VERSION 5.8 ;
BUSBITCHARS "[]" ;
DIVIDERCHAR "/" ;
UNITS
    DATABASE MICRONS 1000 ;
END UNITS

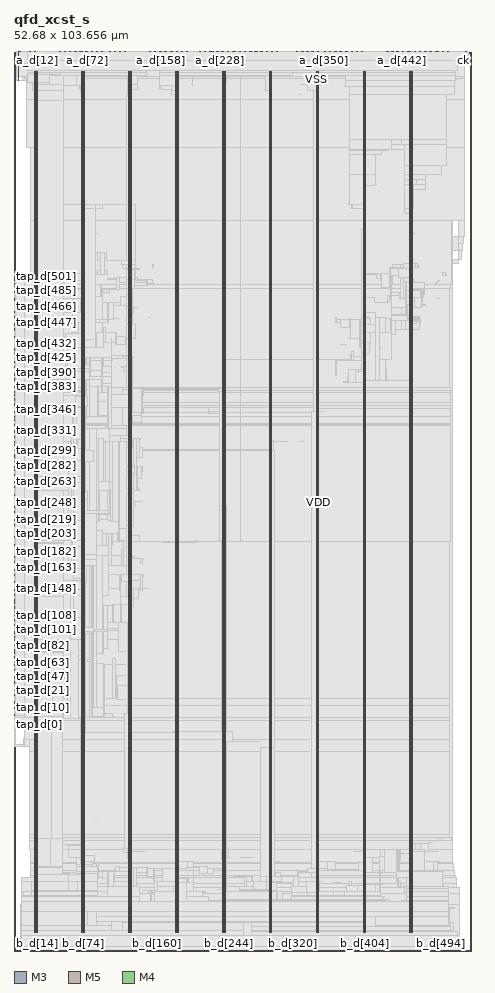
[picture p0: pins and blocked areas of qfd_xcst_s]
MACRO qfd_xcst_s
  FOREIGN qfd_xcst_s 0 0 ;
  CLASS BLOCK ;
  SIZE 52.68 BY 103.656 ;
  PIN a_d[0]
    DIRECTION INPUT ;
    USE SIGNAL ;
    PORT
      LAYER M3 ;
        RECT  1.44 103.618 1.458 103.656 ;
    END
  END a_d[0]
  PIN a_d[100]
    DIRECTION INPUT ;
    USE SIGNAL ;
    PORT
      LAYER M3 ;
        RECT  11.232 103.618 11.25 103.656 ;
    END
  END a_d[100]
  PIN a_d[101]
    DIRECTION INPUT ;
    USE SIGNAL ;
    PORT
      LAYER M5 ;
        RECT  11.328 103.572 11.352 103.656 ;
    END
  END a_d[101]
  PIN a_d[102]
    DIRECTION INPUT ;
    USE SIGNAL ;
    PORT
      LAYER M3 ;
        RECT  11.412 103.618 11.43 103.656 ;
    END
  END a_d[102]
  PIN a_d[103]
    DIRECTION INPUT ;
    USE SIGNAL ;
    PORT
      LAYER M5 ;
        RECT  11.52 103.572 11.544 103.656 ;
    END
  END a_d[103]
  PIN a_d[104]
    DIRECTION INPUT ;
    USE SIGNAL ;
    PORT
      LAYER M3 ;
        RECT  11.628 103.618 11.646 103.656 ;
    END
  END a_d[104]
  PIN a_d[105]
    DIRECTION INPUT ;
    USE SIGNAL ;
    PORT
      LAYER M5 ;
        RECT  11.712 103.572 11.736 103.656 ;
    END
  END a_d[105]
  PIN a_d[106]
    DIRECTION INPUT ;
    USE SIGNAL ;
    PORT
      LAYER M3 ;
        RECT  11.808 103.618 11.826 103.656 ;
    END
  END a_d[106]
  PIN a_d[107]
    DIRECTION INPUT ;
    USE SIGNAL ;
    PORT
      LAYER M5 ;
        RECT  11.904 103.572 11.928 103.656 ;
    END
  END a_d[107]
  PIN a_d[108]
    DIRECTION INPUT ;
    USE SIGNAL ;
    PORT
      LAYER M3 ;
        RECT  12.024 103.618 12.042 103.656 ;
    END
  END a_d[108]
  PIN a_d[109]
    DIRECTION INPUT ;
    USE SIGNAL ;
    PORT
      LAYER M5 ;
        RECT  12.096 103.572 12.12 103.656 ;
    END
  END a_d[109]
  PIN a_d[10]
    DIRECTION INPUT ;
    USE SIGNAL ;
    PORT
      LAYER M3 ;
        RECT  2.412 103.618 2.43 103.656 ;
    END
  END a_d[10]
  PIN a_d[110]
    DIRECTION INPUT ;
    USE SIGNAL ;
    PORT
      LAYER M3 ;
        RECT  12.204 103.618 12.222 103.656 ;
    END
  END a_d[110]
  PIN a_d[111]
    DIRECTION INPUT ;
    USE SIGNAL ;
    PORT
      LAYER M5 ;
        RECT  12.288 103.572 12.312 103.656 ;
    END
  END a_d[111]
  PIN a_d[112]
    DIRECTION INPUT ;
    USE SIGNAL ;
    PORT
      LAYER M3 ;
        RECT  12.42 103.618 12.438 103.656 ;
    END
  END a_d[112]
  PIN a_d[113]
    DIRECTION INPUT ;
    USE SIGNAL ;
    PORT
      LAYER M5 ;
        RECT  12.48 103.572 12.504 103.656 ;
    END
  END a_d[113]
  PIN a_d[114]
    DIRECTION INPUT ;
    USE SIGNAL ;
    PORT
      LAYER M3 ;
        RECT  12.6 103.618 12.618 103.656 ;
    END
  END a_d[114]
  PIN a_d[115]
    DIRECTION INPUT ;
    USE SIGNAL ;
    PORT
      LAYER M5 ;
        RECT  12.672 103.572 12.696 103.656 ;
    END
  END a_d[115]
  PIN a_d[116]
    DIRECTION INPUT ;
    USE SIGNAL ;
    PORT
      LAYER M3 ;
        RECT  12.78 103.618 12.798 103.656 ;
    END
  END a_d[116]
  PIN a_d[117]
    DIRECTION INPUT ;
    USE SIGNAL ;
    PORT
      LAYER M5 ;
        RECT  12.912 103.572 12.936 103.656 ;
    END
  END a_d[117]
  PIN a_d[118]
    DIRECTION INPUT ;
    USE SIGNAL ;
    PORT
      LAYER M3 ;
        RECT  12.996 103.618 13.014 103.656 ;
    END
  END a_d[118]
  PIN a_d[119]
    DIRECTION INPUT ;
    USE SIGNAL ;
    PORT
      LAYER M5 ;
        RECT  13.104 103.572 13.128 103.656 ;
    END
  END a_d[119]
  PIN a_d[11]
    DIRECTION INPUT ;
    USE SIGNAL ;
    PORT
      LAYER M5 ;
        RECT  2.496 103.572 2.52 103.656 ;
    END
  END a_d[11]
  PIN a_d[120]
    DIRECTION INPUT ;
    USE SIGNAL ;
    PORT
      LAYER M3 ;
        RECT  13.176 103.618 13.194 103.656 ;
    END
  END a_d[120]
  PIN a_d[121]
    DIRECTION INPUT ;
    USE SIGNAL ;
    PORT
      LAYER M5 ;
        RECT  13.296 103.572 13.32 103.656 ;
    END
  END a_d[121]
  PIN a_d[122]
    DIRECTION INPUT ;
    USE SIGNAL ;
    PORT
      LAYER M3 ;
        RECT  13.392 103.618 13.41 103.656 ;
    END
  END a_d[122]
  PIN a_d[123]
    DIRECTION INPUT ;
    USE SIGNAL ;
    PORT
      LAYER M5 ;
        RECT  13.488 103.572 13.512 103.656 ;
    END
  END a_d[123]
  PIN a_d[124]
    DIRECTION INPUT ;
    USE SIGNAL ;
    PORT
      LAYER M3 ;
        RECT  13.572 103.618 13.59 103.656 ;
    END
  END a_d[124]
  PIN a_d[125]
    DIRECTION INPUT ;
    USE SIGNAL ;
    PORT
      LAYER M5 ;
        RECT  13.68 103.572 13.704 103.656 ;
    END
  END a_d[125]
  PIN a_d[126]
    DIRECTION INPUT ;
    USE SIGNAL ;
    PORT
      LAYER M3 ;
        RECT  13.788 103.618 13.806 103.656 ;
    END
  END a_d[126]
  PIN a_d[127]
    DIRECTION INPUT ;
    USE SIGNAL ;
    PORT
      LAYER M5 ;
        RECT  13.872 103.572 13.896 103.656 ;
    END
  END a_d[127]
  PIN a_d[128]
    DIRECTION INPUT ;
    USE SIGNAL ;
    PORT
      LAYER M3 ;
        RECT  13.968 103.618 13.986 103.656 ;
    END
  END a_d[128]
  PIN a_d[129]
    DIRECTION INPUT ;
    USE SIGNAL ;
    PORT
      LAYER M5 ;
        RECT  14.064 103.572 14.088 103.656 ;
    END
  END a_d[129]
  PIN a_d[12]
    DIRECTION INPUT ;
    USE SIGNAL ;
    PORT
      LAYER M3 ;
        RECT  2.628 103.618 2.646 103.656 ;
    END
  END a_d[12]
  PIN a_d[130]
    DIRECTION INPUT ;
    USE SIGNAL ;
    PORT
      LAYER M3 ;
        RECT  14.184 103.618 14.202 103.656 ;
    END
  END a_d[130]
  PIN a_d[131]
    DIRECTION INPUT ;
    USE SIGNAL ;
    PORT
      LAYER M5 ;
        RECT  14.256 103.572 14.28 103.656 ;
    END
  END a_d[131]
  PIN a_d[132]
    DIRECTION INPUT ;
    USE SIGNAL ;
    PORT
      LAYER M3 ;
        RECT  14.364 103.618 14.382 103.656 ;
    END
  END a_d[132]
  PIN a_d[133]
    DIRECTION INPUT ;
    USE SIGNAL ;
    PORT
      LAYER M5 ;
        RECT  14.448 103.572 14.472 103.656 ;
    END
  END a_d[133]
  PIN a_d[134]
    DIRECTION INPUT ;
    USE SIGNAL ;
    PORT
      LAYER M3 ;
        RECT  14.544 103.618 14.562 103.656 ;
    END
  END a_d[134]
  PIN a_d[135]
    DIRECTION INPUT ;
    USE SIGNAL ;
    PORT
      LAYER M5 ;
        RECT  14.64 103.572 14.664 103.656 ;
    END
  END a_d[135]
  PIN a_d[136]
    DIRECTION INPUT ;
    USE SIGNAL ;
    PORT
      LAYER M3 ;
        RECT  14.76 103.618 14.778 103.656 ;
    END
  END a_d[136]
  PIN a_d[137]
    DIRECTION INPUT ;
    USE SIGNAL ;
    PORT
      LAYER M5 ;
        RECT  14.832 103.572 14.856 103.656 ;
    END
  END a_d[137]
  PIN a_d[138]
    DIRECTION INPUT ;
    USE SIGNAL ;
    PORT
      LAYER M3 ;
        RECT  14.94 103.618 14.958 103.656 ;
    END
  END a_d[138]
  PIN a_d[139]
    DIRECTION INPUT ;
    USE SIGNAL ;
    PORT
      LAYER M5 ;
        RECT  15.024 103.572 15.048 103.656 ;
    END
  END a_d[139]
  PIN a_d[13]
    DIRECTION INPUT ;
    USE SIGNAL ;
    PORT
      LAYER M5 ;
        RECT  2.736 103.572 2.76 103.656 ;
    END
  END a_d[13]
  PIN a_d[140]
    DIRECTION INPUT ;
    USE SIGNAL ;
    PORT
      LAYER M3 ;
        RECT  15.156 103.618 15.174 103.656 ;
    END
  END a_d[140]
  PIN a_d[141]
    DIRECTION INPUT ;
    USE SIGNAL ;
    PORT
      LAYER M5 ;
        RECT  15.216 103.572 15.24 103.656 ;
    END
  END a_d[141]
  PIN a_d[142]
    DIRECTION INPUT ;
    USE SIGNAL ;
    PORT
      LAYER M3 ;
        RECT  15.336 103.618 15.354 103.656 ;
    END
  END a_d[142]
  PIN a_d[143]
    DIRECTION INPUT ;
    USE SIGNAL ;
    PORT
      LAYER M5 ;
        RECT  15.456 103.572 15.48 103.656 ;
    END
  END a_d[143]
  PIN a_d[144]
    DIRECTION INPUT ;
    USE SIGNAL ;
    PORT
      LAYER M3 ;
        RECT  15.552 103.618 15.57 103.656 ;
    END
  END a_d[144]
  PIN a_d[145]
    DIRECTION INPUT ;
    USE SIGNAL ;
    PORT
      LAYER M5 ;
        RECT  15.648 103.572 15.672 103.656 ;
    END
  END a_d[145]
  PIN a_d[146]
    DIRECTION INPUT ;
    USE SIGNAL ;
    PORT
      LAYER M3 ;
        RECT  15.732 103.618 15.75 103.656 ;
    END
  END a_d[146]
  PIN a_d[147]
    DIRECTION INPUT ;
    USE SIGNAL ;
    PORT
      LAYER M5 ;
        RECT  15.84 103.572 15.864 103.656 ;
    END
  END a_d[147]
  PIN a_d[148]
    DIRECTION INPUT ;
    USE SIGNAL ;
    PORT
      LAYER M3 ;
        RECT  15.912 103.618 15.93 103.656 ;
    END
  END a_d[148]
  PIN a_d[149]
    DIRECTION INPUT ;
    USE SIGNAL ;
    PORT
      LAYER M5 ;
        RECT  16.032 103.572 16.056 103.656 ;
    END
  END a_d[149]
  PIN a_d[14]
    DIRECTION INPUT ;
    USE SIGNAL ;
    PORT
      LAYER M3 ;
        RECT  2.808 103.618 2.826 103.656 ;
    END
  END a_d[14]
  PIN a_d[150]
    DIRECTION INPUT ;
    USE SIGNAL ;
    PORT
      LAYER M3 ;
        RECT  16.128 103.618 16.146 103.656 ;
    END
  END a_d[150]
  PIN a_d[151]
    DIRECTION INPUT ;
    USE SIGNAL ;
    PORT
      LAYER M5 ;
        RECT  16.224 103.572 16.248 103.656 ;
    END
  END a_d[151]
  PIN a_d[152]
    DIRECTION INPUT ;
    USE SIGNAL ;
    PORT
      LAYER M3 ;
        RECT  16.308 103.618 16.326 103.656 ;
    END
  END a_d[152]
  PIN a_d[153]
    DIRECTION INPUT ;
    USE SIGNAL ;
    PORT
      LAYER M5 ;
        RECT  16.416 103.572 16.44 103.656 ;
    END
  END a_d[153]
  PIN a_d[154]
    DIRECTION INPUT ;
    USE SIGNAL ;
    PORT
      LAYER M3 ;
        RECT  16.524 103.618 16.542 103.656 ;
    END
  END a_d[154]
  PIN a_d[155]
    DIRECTION INPUT ;
    USE SIGNAL ;
    PORT
      LAYER M5 ;
        RECT  16.608 103.572 16.632 103.656 ;
    END
  END a_d[155]
  PIN a_d[156]
    DIRECTION INPUT ;
    USE SIGNAL ;
    PORT
      LAYER M3 ;
        RECT  16.704 103.618 16.722 103.656 ;
    END
  END a_d[156]
  PIN a_d[157]
    DIRECTION INPUT ;
    USE SIGNAL ;
    PORT
      LAYER M5 ;
        RECT  16.8 103.572 16.824 103.656 ;
    END
  END a_d[157]
  PIN a_d[158]
    DIRECTION INPUT ;
    USE SIGNAL ;
    PORT
      LAYER M3 ;
        RECT  16.92 103.618 16.938 103.656 ;
    END
  END a_d[158]
  PIN a_d[159]
    DIRECTION INPUT ;
    USE SIGNAL ;
    PORT
      LAYER M5 ;
        RECT  16.992 103.572 17.016 103.656 ;
    END
  END a_d[159]
  PIN a_d[15]
    DIRECTION INPUT ;
    USE SIGNAL ;
    PORT
      LAYER M5 ;
        RECT  2.928 103.572 2.952 103.656 ;
    END
  END a_d[15]
  PIN a_d[160]
    DIRECTION INPUT ;
    USE SIGNAL ;
    PORT
      LAYER M3 ;
        RECT  17.1 103.618 17.118 103.656 ;
    END
  END a_d[160]
  PIN a_d[161]
    DIRECTION INPUT ;
    USE SIGNAL ;
    PORT
      LAYER M5 ;
        RECT  17.184 103.572 17.208 103.656 ;
    END
  END a_d[161]
  PIN a_d[162]
    DIRECTION INPUT ;
    USE SIGNAL ;
    PORT
      LAYER M3 ;
        RECT  17.28 103.618 17.298 103.656 ;
    END
  END a_d[162]
  PIN a_d[163]
    DIRECTION INPUT ;
    USE SIGNAL ;
    PORT
      LAYER M5 ;
        RECT  17.376 103.572 17.4 103.656 ;
    END
  END a_d[163]
  PIN a_d[164]
    DIRECTION INPUT ;
    USE SIGNAL ;
    PORT
      LAYER M3 ;
        RECT  17.496 103.618 17.514 103.656 ;
    END
  END a_d[164]
  PIN a_d[165]
    DIRECTION INPUT ;
    USE SIGNAL ;
    PORT
      LAYER M5 ;
        RECT  17.568 103.572 17.592 103.656 ;
    END
  END a_d[165]
  PIN a_d[166]
    DIRECTION INPUT ;
    USE SIGNAL ;
    PORT
      LAYER M3 ;
        RECT  17.676 103.618 17.694 103.656 ;
    END
  END a_d[166]
  PIN a_d[167]
    DIRECTION INPUT ;
    USE SIGNAL ;
    PORT
      LAYER M5 ;
        RECT  17.808 103.572 17.832 103.656 ;
    END
  END a_d[167]
  PIN a_d[168]
    DIRECTION INPUT ;
    USE SIGNAL ;
    PORT
      LAYER M3 ;
        RECT  17.892 103.618 17.91 103.656 ;
    END
  END a_d[168]
  PIN a_d[169]
    DIRECTION INPUT ;
    USE SIGNAL ;
    PORT
      LAYER M5 ;
        RECT  18 103.572 18.024 103.656 ;
    END
  END a_d[169]
  PIN a_d[16]
    DIRECTION INPUT ;
    USE SIGNAL ;
    PORT
      LAYER M3 ;
        RECT  3.024 103.618 3.042 103.656 ;
    END
  END a_d[16]
  PIN a_d[170]
    DIRECTION INPUT ;
    USE SIGNAL ;
    PORT
      LAYER M3 ;
        RECT  18.072 103.618 18.09 103.656 ;
    END
  END a_d[170]
  PIN a_d[171]
    DIRECTION INPUT ;
    USE SIGNAL ;
    PORT
      LAYER M5 ;
        RECT  18.192 103.572 18.216 103.656 ;
    END
  END a_d[171]
  PIN a_d[172]
    DIRECTION INPUT ;
    USE SIGNAL ;
    PORT
      LAYER M3 ;
        RECT  18.288 103.618 18.306 103.656 ;
    END
  END a_d[172]
  PIN a_d[173]
    DIRECTION INPUT ;
    USE SIGNAL ;
    PORT
      LAYER M5 ;
        RECT  18.384 103.572 18.408 103.656 ;
    END
  END a_d[173]
  PIN a_d[174]
    DIRECTION INPUT ;
    USE SIGNAL ;
    PORT
      LAYER M3 ;
        RECT  18.468 103.618 18.486 103.656 ;
    END
  END a_d[174]
  PIN a_d[175]
    DIRECTION INPUT ;
    USE SIGNAL ;
    PORT
      LAYER M5 ;
        RECT  18.576 103.572 18.6 103.656 ;
    END
  END a_d[175]
  PIN a_d[176]
    DIRECTION INPUT ;
    USE SIGNAL ;
    PORT
      LAYER M3 ;
        RECT  18.684 103.618 18.702 103.656 ;
    END
  END a_d[176]
  PIN a_d[177]
    DIRECTION INPUT ;
    USE SIGNAL ;
    PORT
      LAYER M5 ;
        RECT  18.768 103.572 18.792 103.656 ;
    END
  END a_d[177]
  PIN a_d[178]
    DIRECTION INPUT ;
    USE SIGNAL ;
    PORT
      LAYER M3 ;
        RECT  18.864 103.618 18.882 103.656 ;
    END
  END a_d[178]
  PIN a_d[179]
    DIRECTION INPUT ;
    USE SIGNAL ;
    PORT
      LAYER M5 ;
        RECT  18.96 103.572 18.984 103.656 ;
    END
  END a_d[179]
  PIN a_d[17]
    DIRECTION INPUT ;
    USE SIGNAL ;
    PORT
      LAYER M5 ;
        RECT  3.12 103.572 3.144 103.656 ;
    END
  END a_d[17]
  PIN a_d[180]
    DIRECTION INPUT ;
    USE SIGNAL ;
    PORT
      LAYER M3 ;
        RECT  19.044 103.618 19.062 103.656 ;
    END
  END a_d[180]
  PIN a_d[181]
    DIRECTION INPUT ;
    USE SIGNAL ;
    PORT
      LAYER M5 ;
        RECT  19.152 103.572 19.176 103.656 ;
    END
  END a_d[181]
  PIN a_d[182]
    DIRECTION INPUT ;
    USE SIGNAL ;
    PORT
      LAYER M3 ;
        RECT  19.26 103.618 19.278 103.656 ;
    END
  END a_d[182]
  PIN a_d[183]
    DIRECTION INPUT ;
    USE SIGNAL ;
    PORT
      LAYER M5 ;
        RECT  19.344 103.572 19.368 103.656 ;
    END
  END a_d[183]
  PIN a_d[184]
    DIRECTION INPUT ;
    USE SIGNAL ;
    PORT
      LAYER M3 ;
        RECT  19.44 103.618 19.458 103.656 ;
    END
  END a_d[184]
  PIN a_d[185]
    DIRECTION INPUT ;
    USE SIGNAL ;
    PORT
      LAYER M5 ;
        RECT  19.536 103.572 19.56 103.656 ;
    END
  END a_d[185]
  PIN a_d[186]
    DIRECTION INPUT ;
    USE SIGNAL ;
    PORT
      LAYER M3 ;
        RECT  19.656 103.618 19.674 103.656 ;
    END
  END a_d[186]
  PIN a_d[187]
    DIRECTION INPUT ;
    USE SIGNAL ;
    PORT
      LAYER M5 ;
        RECT  19.728 103.572 19.752 103.656 ;
    END
  END a_d[187]
  PIN a_d[188]
    DIRECTION INPUT ;
    USE SIGNAL ;
    PORT
      LAYER M3 ;
        RECT  19.836 103.618 19.854 103.656 ;
    END
  END a_d[188]
  PIN a_d[189]
    DIRECTION INPUT ;
    USE SIGNAL ;
    PORT
      LAYER M5 ;
        RECT  19.92 103.572 19.944 103.656 ;
    END
  END a_d[189]
  PIN a_d[18]
    DIRECTION INPUT ;
    USE SIGNAL ;
    PORT
      LAYER M3 ;
        RECT  3.204 103.618 3.222 103.656 ;
    END
  END a_d[18]
  PIN a_d[190]
    DIRECTION INPUT ;
    USE SIGNAL ;
    PORT
      LAYER M3 ;
        RECT  20.052 103.618 20.07 103.656 ;
    END
  END a_d[190]
  PIN a_d[191]
    DIRECTION INPUT ;
    USE SIGNAL ;
    PORT
      LAYER M5 ;
        RECT  20.112 103.572 20.136 103.656 ;
    END
  END a_d[191]
  PIN a_d[192]
    DIRECTION INPUT ;
    USE SIGNAL ;
    PORT
      LAYER M3 ;
        RECT  20.232 103.618 20.25 103.656 ;
    END
  END a_d[192]
  PIN a_d[193]
    DIRECTION INPUT ;
    USE SIGNAL ;
    PORT
      LAYER M5 ;
        RECT  20.352 103.572 20.376 103.656 ;
    END
  END a_d[193]
  PIN a_d[194]
    DIRECTION INPUT ;
    USE SIGNAL ;
    PORT
      LAYER M3 ;
        RECT  20.412 103.618 20.43 103.656 ;
    END
  END a_d[194]
  PIN a_d[195]
    DIRECTION INPUT ;
    USE SIGNAL ;
    PORT
      LAYER M5 ;
        RECT  20.544 103.572 20.568 103.656 ;
    END
  END a_d[195]
  PIN a_d[196]
    DIRECTION INPUT ;
    USE SIGNAL ;
    PORT
      LAYER M3 ;
        RECT  20.628 103.618 20.646 103.656 ;
    END
  END a_d[196]
  PIN a_d[197]
    DIRECTION INPUT ;
    USE SIGNAL ;
    PORT
      LAYER M5 ;
        RECT  20.736 103.572 20.76 103.656 ;
    END
  END a_d[197]
  PIN a_d[198]
    DIRECTION INPUT ;
    USE SIGNAL ;
    PORT
      LAYER M3 ;
        RECT  20.808 103.618 20.826 103.656 ;
    END
  END a_d[198]
  PIN a_d[199]
    DIRECTION INPUT ;
    USE SIGNAL ;
    PORT
      LAYER M5 ;
        RECT  20.928 103.572 20.952 103.656 ;
    END
  END a_d[199]
  PIN a_d[19]
    DIRECTION INPUT ;
    USE SIGNAL ;
    PORT
      LAYER M5 ;
        RECT  3.312 103.572 3.336 103.656 ;
    END
  END a_d[19]
  PIN a_d[1]
    DIRECTION INPUT ;
    USE SIGNAL ;
    PORT
      LAYER M5 ;
        RECT  1.536 103.572 1.56 103.656 ;
    END
  END a_d[1]
  PIN a_d[200]
    DIRECTION INPUT ;
    USE SIGNAL ;
    PORT
      LAYER M3 ;
        RECT  21.024 103.618 21.042 103.656 ;
    END
  END a_d[200]
  PIN a_d[201]
    DIRECTION INPUT ;
    USE SIGNAL ;
    PORT
      LAYER M5 ;
        RECT  21.12 103.572 21.144 103.656 ;
    END
  END a_d[201]
  PIN a_d[202]
    DIRECTION INPUT ;
    USE SIGNAL ;
    PORT
      LAYER M3 ;
        RECT  21.204 103.618 21.222 103.656 ;
    END
  END a_d[202]
  PIN a_d[203]
    DIRECTION INPUT ;
    USE SIGNAL ;
    PORT
      LAYER M5 ;
        RECT  21.312 103.572 21.336 103.656 ;
    END
  END a_d[203]
  PIN a_d[204]
    DIRECTION INPUT ;
    USE SIGNAL ;
    PORT
      LAYER M3 ;
        RECT  21.42 103.618 21.438 103.656 ;
    END
  END a_d[204]
  PIN a_d[205]
    DIRECTION INPUT ;
    USE SIGNAL ;
    PORT
      LAYER M5 ;
        RECT  21.504 103.572 21.528 103.656 ;
    END
  END a_d[205]
  PIN a_d[206]
    DIRECTION INPUT ;
    USE SIGNAL ;
    PORT
      LAYER M3 ;
        RECT  21.6 103.618 21.618 103.656 ;
    END
  END a_d[206]
  PIN a_d[207]
    DIRECTION INPUT ;
    USE SIGNAL ;
    PORT
      LAYER M5 ;
        RECT  21.696 103.572 21.72 103.656 ;
    END
  END a_d[207]
  PIN a_d[208]
    DIRECTION INPUT ;
    USE SIGNAL ;
    PORT
      LAYER M3 ;
        RECT  21.816 103.618 21.834 103.656 ;
    END
  END a_d[208]
  PIN a_d[209]
    DIRECTION INPUT ;
    USE SIGNAL ;
    PORT
      LAYER M5 ;
        RECT  21.888 103.572 21.912 103.656 ;
    END
  END a_d[209]
  PIN a_d[20]
    DIRECTION INPUT ;
    USE SIGNAL ;
    PORT
      LAYER M3 ;
        RECT  3.384 103.618 3.402 103.656 ;
    END
  END a_d[20]
  PIN a_d[210]
    DIRECTION INPUT ;
    USE SIGNAL ;
    PORT
      LAYER M3 ;
        RECT  21.996 103.618 22.014 103.656 ;
    END
  END a_d[210]
  PIN a_d[211]
    DIRECTION INPUT ;
    USE SIGNAL ;
    PORT
      LAYER M5 ;
        RECT  22.08 103.572 22.104 103.656 ;
    END
  END a_d[211]
  PIN a_d[212]
    DIRECTION INPUT ;
    USE SIGNAL ;
    PORT
      LAYER M3 ;
        RECT  22.176 103.618 22.194 103.656 ;
    END
  END a_d[212]
  PIN a_d[213]
    DIRECTION INPUT ;
    USE SIGNAL ;
    PORT
      LAYER M5 ;
        RECT  22.272 103.572 22.296 103.656 ;
    END
  END a_d[213]
  PIN a_d[214]
    DIRECTION INPUT ;
    USE SIGNAL ;
    PORT
      LAYER M3 ;
        RECT  22.392 103.618 22.41 103.656 ;
    END
  END a_d[214]
  PIN a_d[215]
    DIRECTION INPUT ;
    USE SIGNAL ;
    PORT
      LAYER M5 ;
        RECT  22.464 103.572 22.488 103.656 ;
    END
  END a_d[215]
  PIN a_d[216]
    DIRECTION INPUT ;
    USE SIGNAL ;
    PORT
      LAYER M3 ;
        RECT  22.572 103.618 22.59 103.656 ;
    END
  END a_d[216]
  PIN a_d[217]
    DIRECTION INPUT ;
    USE SIGNAL ;
    PORT
      LAYER M5 ;
        RECT  22.656 103.572 22.68 103.656 ;
    END
  END a_d[217]
  PIN a_d[218]
    DIRECTION INPUT ;
    USE SIGNAL ;
    PORT
      LAYER M3 ;
        RECT  22.788 103.618 22.806 103.656 ;
    END
  END a_d[218]
  PIN a_d[219]
    DIRECTION INPUT ;
    USE SIGNAL ;
    PORT
      LAYER M5 ;
        RECT  22.896 103.572 22.92 103.656 ;
    END
  END a_d[219]
  PIN a_d[21]
    DIRECTION INPUT ;
    USE SIGNAL ;
    PORT
      LAYER M5 ;
        RECT  3.504 103.572 3.528 103.656 ;
    END
  END a_d[21]
  PIN a_d[220]
    DIRECTION INPUT ;
    USE SIGNAL ;
    PORT
      LAYER M3 ;
        RECT  22.968 103.618 22.986 103.656 ;
    END
  END a_d[220]
  PIN a_d[221]
    DIRECTION INPUT ;
    USE SIGNAL ;
    PORT
      LAYER M5 ;
        RECT  23.088 103.572 23.112 103.656 ;
    END
  END a_d[221]
  PIN a_d[222]
    DIRECTION INPUT ;
    USE SIGNAL ;
    PORT
      LAYER M3 ;
        RECT  23.184 103.618 23.202 103.656 ;
    END
  END a_d[222]
  PIN a_d[223]
    DIRECTION INPUT ;
    USE SIGNAL ;
    PORT
      LAYER M5 ;
        RECT  23.28 103.572 23.304 103.656 ;
    END
  END a_d[223]
  PIN a_d[224]
    DIRECTION INPUT ;
    USE SIGNAL ;
    PORT
      LAYER M3 ;
        RECT  23.364 103.618 23.382 103.656 ;
    END
  END a_d[224]
  PIN a_d[225]
    DIRECTION INPUT ;
    USE SIGNAL ;
    PORT
      LAYER M5 ;
        RECT  23.472 103.572 23.496 103.656 ;
    END
  END a_d[225]
  PIN a_d[226]
    DIRECTION INPUT ;
    USE SIGNAL ;
    PORT
      LAYER M3 ;
        RECT  23.544 103.618 23.562 103.656 ;
    END
  END a_d[226]
  PIN a_d[227]
    DIRECTION INPUT ;
    USE SIGNAL ;
    PORT
      LAYER M5 ;
        RECT  23.664 103.572 23.688 103.656 ;
    END
  END a_d[227]
  PIN a_d[228]
    DIRECTION INPUT ;
    USE SIGNAL ;
    PORT
      LAYER M3 ;
        RECT  23.76 103.618 23.778 103.656 ;
    END
  END a_d[228]
  PIN a_d[229]
    DIRECTION INPUT ;
    USE SIGNAL ;
    PORT
      LAYER M5 ;
        RECT  23.856 103.572 23.88 103.656 ;
    END
  END a_d[229]
  PIN a_d[22]
    DIRECTION INPUT ;
    USE SIGNAL ;
    PORT
      LAYER M3 ;
        RECT  3.6 103.618 3.618 103.656 ;
    END
  END a_d[22]
  PIN a_d[230]
    DIRECTION INPUT ;
    USE SIGNAL ;
    PORT
      LAYER M3 ;
        RECT  23.94 103.618 23.958 103.656 ;
    END
  END a_d[230]
  PIN a_d[231]
    DIRECTION INPUT ;
    USE SIGNAL ;
    PORT
      LAYER M5 ;
        RECT  24.048 103.572 24.072 103.656 ;
    END
  END a_d[231]
  PIN a_d[232]
    DIRECTION INPUT ;
    USE SIGNAL ;
    PORT
      LAYER M3 ;
        RECT  24.156 103.618 24.174 103.656 ;
    END
  END a_d[232]
  PIN a_d[233]
    DIRECTION INPUT ;
    USE SIGNAL ;
    PORT
      LAYER M5 ;
        RECT  24.24 103.572 24.264 103.656 ;
    END
  END a_d[233]
  PIN a_d[234]
    DIRECTION INPUT ;
    USE SIGNAL ;
    PORT
      LAYER M3 ;
        RECT  24.336 103.618 24.354 103.656 ;
    END
  END a_d[234]
  PIN a_d[235]
    DIRECTION INPUT ;
    USE SIGNAL ;
    PORT
      LAYER M5 ;
        RECT  24.432 103.572 24.456 103.656 ;
    END
  END a_d[235]
  PIN a_d[236]
    DIRECTION INPUT ;
    USE SIGNAL ;
    PORT
      LAYER M3 ;
        RECT  24.552 103.618 24.57 103.656 ;
    END
  END a_d[236]
  PIN a_d[237]
    DIRECTION INPUT ;
    USE SIGNAL ;
    PORT
      LAYER M5 ;
        RECT  24.624 103.572 24.648 103.656 ;
    END
  END a_d[237]
  PIN a_d[238]
    DIRECTION INPUT ;
    USE SIGNAL ;
    PORT
      LAYER M3 ;
        RECT  24.732 103.618 24.75 103.656 ;
    END
  END a_d[238]
  PIN a_d[239]
    DIRECTION INPUT ;
    USE SIGNAL ;
    PORT
      LAYER M5 ;
        RECT  24.816 103.572 24.84 103.656 ;
    END
  END a_d[239]
  PIN a_d[23]
    DIRECTION INPUT ;
    USE SIGNAL ;
    PORT
      LAYER M5 ;
        RECT  3.696 103.572 3.72 103.656 ;
    END
  END a_d[23]
  PIN a_d[240]
    DIRECTION INPUT ;
    USE SIGNAL ;
    PORT
      LAYER M3 ;
        RECT  24.948 103.618 24.966 103.656 ;
    END
  END a_d[240]
  PIN a_d[241]
    DIRECTION INPUT ;
    USE SIGNAL ;
    PORT
      LAYER M5 ;
        RECT  25.008 103.572 25.032 103.656 ;
    END
  END a_d[241]
  PIN a_d[242]
    DIRECTION INPUT ;
    USE SIGNAL ;
    PORT
      LAYER M3 ;
        RECT  25.128 103.618 25.146 103.656 ;
    END
  END a_d[242]
  PIN a_d[243]
    DIRECTION INPUT ;
    USE SIGNAL ;
    PORT
      LAYER M5 ;
        RECT  25.2 103.572 25.224 103.656 ;
    END
  END a_d[243]
  PIN a_d[244]
    DIRECTION INPUT ;
    USE SIGNAL ;
    PORT
      LAYER M3 ;
        RECT  25.308 103.618 25.326 103.656 ;
    END
  END a_d[244]
  PIN a_d[245]
    DIRECTION INPUT ;
    USE SIGNAL ;
    PORT
      LAYER M5 ;
        RECT  25.44 103.572 25.464 103.656 ;
    END
  END a_d[245]
  PIN a_d[246]
    DIRECTION INPUT ;
    USE SIGNAL ;
    PORT
      LAYER M3 ;
        RECT  25.524 103.618 25.542 103.656 ;
    END
  END a_d[246]
  PIN a_d[247]
    DIRECTION INPUT ;
    USE SIGNAL ;
    PORT
      LAYER M5 ;
        RECT  25.632 103.572 25.656 103.656 ;
    END
  END a_d[247]
  PIN a_d[248]
    DIRECTION INPUT ;
    USE SIGNAL ;
    PORT
      LAYER M3 ;
        RECT  25.704 103.618 25.722 103.656 ;
    END
  END a_d[248]
  PIN a_d[249]
    DIRECTION INPUT ;
    USE SIGNAL ;
    PORT
      LAYER M5 ;
        RECT  25.824 103.572 25.848 103.656 ;
    END
  END a_d[249]
  PIN a_d[24]
    DIRECTION INPUT ;
    USE SIGNAL ;
    PORT
      LAYER M3 ;
        RECT  3.78 103.618 3.798 103.656 ;
    END
  END a_d[24]
  PIN a_d[250]
    DIRECTION INPUT ;
    USE SIGNAL ;
    PORT
      LAYER M3 ;
        RECT  25.92 103.618 25.938 103.656 ;
    END
  END a_d[250]
  PIN a_d[251]
    DIRECTION INPUT ;
    USE SIGNAL ;
    PORT
      LAYER M5 ;
        RECT  26.016 103.572 26.04 103.656 ;
    END
  END a_d[251]
  PIN a_d[252]
    DIRECTION INPUT ;
    USE SIGNAL ;
    PORT
      LAYER M3 ;
        RECT  26.1 103.618 26.118 103.656 ;
    END
  END a_d[252]
  PIN a_d[253]
    DIRECTION INPUT ;
    USE SIGNAL ;
    PORT
      LAYER M5 ;
        RECT  26.208 103.572 26.232 103.656 ;
    END
  END a_d[253]
  PIN a_d[254]
    DIRECTION INPUT ;
    USE SIGNAL ;
    PORT
      LAYER M3 ;
        RECT  26.316 103.618 26.334 103.656 ;
    END
  END a_d[254]
  PIN a_d[255]
    DIRECTION INPUT ;
    USE SIGNAL ;
    PORT
      LAYER M5 ;
        RECT  26.4 103.572 26.424 103.656 ;
    END
  END a_d[255]
  PIN a_d[256]
    DIRECTION INPUT ;
    USE SIGNAL ;
    PORT
      LAYER M3 ;
        RECT  26.496 103.618 26.514 103.656 ;
    END
  END a_d[256]
  PIN a_d[257]
    DIRECTION INPUT ;
    USE SIGNAL ;
    PORT
      LAYER M5 ;
        RECT  26.592 103.572 26.616 103.656 ;
    END
  END a_d[257]
  PIN a_d[258]
    DIRECTION INPUT ;
    USE SIGNAL ;
    PORT
      LAYER M3 ;
        RECT  26.676 103.618 26.694 103.656 ;
    END
  END a_d[258]
  PIN a_d[259]
    DIRECTION INPUT ;
    USE SIGNAL ;
    PORT
      LAYER M5 ;
        RECT  26.784 103.572 26.808 103.656 ;
    END
  END a_d[259]
  PIN a_d[25]
    DIRECTION INPUT ;
    USE SIGNAL ;
    PORT
      LAYER M5 ;
        RECT  3.888 103.572 3.912 103.656 ;
    END
  END a_d[25]
  PIN a_d[260]
    DIRECTION INPUT ;
    USE SIGNAL ;
    PORT
      LAYER M3 ;
        RECT  26.892 103.618 26.91 103.656 ;
    END
  END a_d[260]
  PIN a_d[261]
    DIRECTION INPUT ;
    USE SIGNAL ;
    PORT
      LAYER M5 ;
        RECT  26.976 103.572 27 103.656 ;
    END
  END a_d[261]
  PIN a_d[262]
    DIRECTION INPUT ;
    USE SIGNAL ;
    PORT
      LAYER M3 ;
        RECT  27.072 103.618 27.09 103.656 ;
    END
  END a_d[262]
  PIN a_d[263]
    DIRECTION INPUT ;
    USE SIGNAL ;
    PORT
      LAYER M5 ;
        RECT  27.168 103.572 27.192 103.656 ;
    END
  END a_d[263]
  PIN a_d[264]
    DIRECTION INPUT ;
    USE SIGNAL ;
    PORT
      LAYER M3 ;
        RECT  27.288 103.618 27.306 103.656 ;
    END
  END a_d[264]
  PIN a_d[265]
    DIRECTION INPUT ;
    USE SIGNAL ;
    PORT
      LAYER M5 ;
        RECT  27.36 103.572 27.384 103.656 ;
    END
  END a_d[265]
  PIN a_d[266]
    DIRECTION INPUT ;
    USE SIGNAL ;
    PORT
      LAYER M3 ;
        RECT  27.468 103.618 27.486 103.656 ;
    END
  END a_d[266]
  PIN a_d[267]
    DIRECTION INPUT ;
    USE SIGNAL ;
    PORT
      LAYER M5 ;
        RECT  27.552 103.572 27.576 103.656 ;
    END
  END a_d[267]
  PIN a_d[268]
    DIRECTION INPUT ;
    USE SIGNAL ;
    PORT
      LAYER M3 ;
        RECT  27.684 103.618 27.702 103.656 ;
    END
  END a_d[268]
  PIN a_d[269]
    DIRECTION INPUT ;
    USE SIGNAL ;
    PORT
      LAYER M5 ;
        RECT  27.744 103.572 27.768 103.656 ;
    END
  END a_d[269]
  PIN a_d[26]
    DIRECTION INPUT ;
    USE SIGNAL ;
    PORT
      LAYER M3 ;
        RECT  3.996 103.618 4.014 103.656 ;
    END
  END a_d[26]
  PIN a_d[270]
    DIRECTION INPUT ;
    USE SIGNAL ;
    PORT
      LAYER M3 ;
        RECT  27.864 103.618 27.882 103.656 ;
    END
  END a_d[270]
  PIN a_d[271]
    DIRECTION INPUT ;
    USE SIGNAL ;
    PORT
      LAYER M5 ;
        RECT  27.984 103.572 28.008 103.656 ;
    END
  END a_d[271]
  PIN a_d[272]
    DIRECTION INPUT ;
    USE SIGNAL ;
    PORT
      LAYER M3 ;
        RECT  28.08 103.618 28.098 103.656 ;
    END
  END a_d[272]
  PIN a_d[273]
    DIRECTION INPUT ;
    USE SIGNAL ;
    PORT
      LAYER M5 ;
        RECT  28.176 103.572 28.2 103.656 ;
    END
  END a_d[273]
  PIN a_d[274]
    DIRECTION INPUT ;
    USE SIGNAL ;
    PORT
      LAYER M3 ;
        RECT  28.26 103.618 28.278 103.656 ;
    END
  END a_d[274]
  PIN a_d[275]
    DIRECTION INPUT ;
    USE SIGNAL ;
    PORT
      LAYER M5 ;
        RECT  28.368 103.572 28.392 103.656 ;
    END
  END a_d[275]
  PIN a_d[276]
    DIRECTION INPUT ;
    USE SIGNAL ;
    PORT
      LAYER M3 ;
        RECT  28.44 103.618 28.458 103.656 ;
    END
  END a_d[276]
  PIN a_d[277]
    DIRECTION INPUT ;
    USE SIGNAL ;
    PORT
      LAYER M5 ;
        RECT  28.56 103.572 28.584 103.656 ;
    END
  END a_d[277]
  PIN a_d[278]
    DIRECTION INPUT ;
    USE SIGNAL ;
    PORT
      LAYER M3 ;
        RECT  28.656 103.618 28.674 103.656 ;
    END
  END a_d[278]
  PIN a_d[279]
    DIRECTION INPUT ;
    USE SIGNAL ;
    PORT
      LAYER M5 ;
        RECT  28.752 103.572 28.776 103.656 ;
    END
  END a_d[279]
  PIN a_d[27]
    DIRECTION INPUT ;
    USE SIGNAL ;
    PORT
      LAYER M5 ;
        RECT  4.08 103.572 4.104 103.656 ;
    END
  END a_d[27]
  PIN a_d[280]
    DIRECTION INPUT ;
    USE SIGNAL ;
    PORT
      LAYER M3 ;
        RECT  28.836 103.618 28.854 103.656 ;
    END
  END a_d[280]
  PIN a_d[281]
    DIRECTION INPUT ;
    USE SIGNAL ;
    PORT
      LAYER M5 ;
        RECT  28.944 103.572 28.968 103.656 ;
    END
  END a_d[281]
  PIN a_d[282]
    DIRECTION INPUT ;
    USE SIGNAL ;
    PORT
      LAYER M3 ;
        RECT  29.052 103.618 29.07 103.656 ;
    END
  END a_d[282]
  PIN a_d[283]
    DIRECTION INPUT ;
    USE SIGNAL ;
    PORT
      LAYER M5 ;
        RECT  29.136 103.572 29.16 103.656 ;
    END
  END a_d[283]
  PIN a_d[284]
    DIRECTION INPUT ;
    USE SIGNAL ;
    PORT
      LAYER M3 ;
        RECT  29.232 103.618 29.25 103.656 ;
    END
  END a_d[284]
  PIN a_d[285]
    DIRECTION INPUT ;
    USE SIGNAL ;
    PORT
      LAYER M5 ;
        RECT  29.328 103.572 29.352 103.656 ;
    END
  END a_d[285]
  PIN a_d[286]
    DIRECTION INPUT ;
    USE SIGNAL ;
    PORT
      LAYER M3 ;
        RECT  29.448 103.618 29.466 103.656 ;
    END
  END a_d[286]
  PIN a_d[287]
    DIRECTION INPUT ;
    USE SIGNAL ;
    PORT
      LAYER M5 ;
        RECT  29.52 103.572 29.544 103.656 ;
    END
  END a_d[287]
  PIN a_d[288]
    DIRECTION INPUT ;
    USE SIGNAL ;
    PORT
      LAYER M3 ;
        RECT  29.628 103.618 29.646 103.656 ;
    END
  END a_d[288]
  PIN a_d[289]
    DIRECTION INPUT ;
    USE SIGNAL ;
    PORT
      LAYER M5 ;
        RECT  29.712 103.572 29.736 103.656 ;
    END
  END a_d[289]
  PIN a_d[28]
    DIRECTION INPUT ;
    USE SIGNAL ;
    PORT
      LAYER M3 ;
        RECT  4.176 103.618 4.194 103.656 ;
    END
  END a_d[28]
  PIN a_d[290]
    DIRECTION INPUT ;
    USE SIGNAL ;
    PORT
      LAYER M3 ;
        RECT  29.808 103.618 29.826 103.656 ;
    END
  END a_d[290]
  PIN a_d[291]
    DIRECTION INPUT ;
    USE SIGNAL ;
    PORT
      LAYER M5 ;
        RECT  29.904 103.572 29.928 103.656 ;
    END
  END a_d[291]
  PIN a_d[292]
    DIRECTION INPUT ;
    USE SIGNAL ;
    PORT
      LAYER M3 ;
        RECT  30.024 103.618 30.042 103.656 ;
    END
  END a_d[292]
  PIN a_d[293]
    DIRECTION INPUT ;
    USE SIGNAL ;
    PORT
      LAYER M5 ;
        RECT  30.096 103.572 30.12 103.656 ;
    END
  END a_d[293]
  PIN a_d[294]
    DIRECTION INPUT ;
    USE SIGNAL ;
    PORT
      LAYER M3 ;
        RECT  30.204 103.618 30.222 103.656 ;
    END
  END a_d[294]
  PIN a_d[295]
    DIRECTION INPUT ;
    USE SIGNAL ;
    PORT
      LAYER M5 ;
        RECT  30.288 103.572 30.312 103.656 ;
    END
  END a_d[295]
  PIN a_d[296]
    DIRECTION INPUT ;
    USE SIGNAL ;
    PORT
      LAYER M3 ;
        RECT  30.42 103.618 30.438 103.656 ;
    END
  END a_d[296]
  PIN a_d[297]
    DIRECTION INPUT ;
    USE SIGNAL ;
    PORT
      LAYER M5 ;
        RECT  30.528 103.572 30.552 103.656 ;
    END
  END a_d[297]
  PIN a_d[298]
    DIRECTION INPUT ;
    USE SIGNAL ;
    PORT
      LAYER M3 ;
        RECT  30.6 103.618 30.618 103.656 ;
    END
  END a_d[298]
  PIN a_d[299]
    DIRECTION INPUT ;
    USE SIGNAL ;
    PORT
      LAYER M5 ;
        RECT  30.72 103.572 30.744 103.656 ;
    END
  END a_d[299]
  PIN a_d[29]
    DIRECTION INPUT ;
    USE SIGNAL ;
    PORT
      LAYER M5 ;
        RECT  4.272 103.572 4.296 103.656 ;
    END
  END a_d[29]
  PIN a_d[2]
    DIRECTION INPUT ;
    USE SIGNAL ;
    PORT
      LAYER M3 ;
        RECT  1.656 103.618 1.674 103.656 ;
    END
  END a_d[2]
  PIN a_d[300]
    DIRECTION INPUT ;
    USE SIGNAL ;
    PORT
      LAYER M3 ;
        RECT  30.816 103.618 30.834 103.656 ;
    END
  END a_d[300]
  PIN a_d[301]
    DIRECTION INPUT ;
    USE SIGNAL ;
    PORT
      LAYER M5 ;
        RECT  30.912 103.572 30.936 103.656 ;
    END
  END a_d[301]
  PIN a_d[302]
    DIRECTION INPUT ;
    USE SIGNAL ;
    PORT
      LAYER M3 ;
        RECT  30.996 103.618 31.014 103.656 ;
    END
  END a_d[302]
  PIN a_d[303]
    DIRECTION INPUT ;
    USE SIGNAL ;
    PORT
      LAYER M5 ;
        RECT  31.104 103.572 31.128 103.656 ;
    END
  END a_d[303]
  PIN a_d[304]
    DIRECTION INPUT ;
    USE SIGNAL ;
    PORT
      LAYER M3 ;
        RECT  31.212 103.618 31.23 103.656 ;
    END
  END a_d[304]
  PIN a_d[305]
    DIRECTION INPUT ;
    USE SIGNAL ;
    PORT
      LAYER M5 ;
        RECT  31.296 103.572 31.32 103.656 ;
    END
  END a_d[305]
  PIN a_d[306]
    DIRECTION INPUT ;
    USE SIGNAL ;
    PORT
      LAYER M3 ;
        RECT  31.392 103.618 31.41 103.656 ;
    END
  END a_d[306]
  PIN a_d[307]
    DIRECTION INPUT ;
    USE SIGNAL ;
    PORT
      LAYER M5 ;
        RECT  31.488 103.572 31.512 103.656 ;
    END
  END a_d[307]
  PIN a_d[308]
    DIRECTION INPUT ;
    USE SIGNAL ;
    PORT
      LAYER M3 ;
        RECT  31.572 103.618 31.59 103.656 ;
    END
  END a_d[308]
  PIN a_d[309]
    DIRECTION INPUT ;
    USE SIGNAL ;
    PORT
      LAYER M5 ;
        RECT  31.68 103.572 31.704 103.656 ;
    END
  END a_d[309]
  PIN a_d[30]
    DIRECTION INPUT ;
    USE SIGNAL ;
    PORT
      LAYER M3 ;
        RECT  4.392 103.618 4.41 103.656 ;
    END
  END a_d[30]
  PIN a_d[310]
    DIRECTION INPUT ;
    USE SIGNAL ;
    PORT
      LAYER M3 ;
        RECT  31.788 103.618 31.806 103.656 ;
    END
  END a_d[310]
  PIN a_d[311]
    DIRECTION INPUT ;
    USE SIGNAL ;
    PORT
      LAYER M5 ;
        RECT  31.872 103.572 31.896 103.656 ;
    END
  END a_d[311]
  PIN a_d[312]
    DIRECTION INPUT ;
    USE SIGNAL ;
    PORT
      LAYER M3 ;
        RECT  31.968 103.618 31.986 103.656 ;
    END
  END a_d[312]
  PIN a_d[313]
    DIRECTION INPUT ;
    USE SIGNAL ;
    PORT
      LAYER M5 ;
        RECT  32.064 103.572 32.088 103.656 ;
    END
  END a_d[313]
  PIN a_d[314]
    DIRECTION INPUT ;
    USE SIGNAL ;
    PORT
      LAYER M3 ;
        RECT  32.184 103.618 32.202 103.656 ;
    END
  END a_d[314]
  PIN a_d[315]
    DIRECTION INPUT ;
    USE SIGNAL ;
    PORT
      LAYER M5 ;
        RECT  32.256 103.572 32.28 103.656 ;
    END
  END a_d[315]
  PIN a_d[316]
    DIRECTION INPUT ;
    USE SIGNAL ;
    PORT
      LAYER M3 ;
        RECT  32.364 103.618 32.382 103.656 ;
    END
  END a_d[316]
  PIN a_d[317]
    DIRECTION INPUT ;
    USE SIGNAL ;
    PORT
      LAYER M5 ;
        RECT  32.448 103.572 32.472 103.656 ;
    END
  END a_d[317]
  PIN a_d[318]
    DIRECTION INPUT ;
    USE SIGNAL ;
    PORT
      LAYER M3 ;
        RECT  32.58 103.618 32.598 103.656 ;
    END
  END a_d[318]
  PIN a_d[319]
    DIRECTION INPUT ;
    USE SIGNAL ;
    PORT
      LAYER M5 ;
        RECT  32.64 103.572 32.664 103.656 ;
    END
  END a_d[319]
  PIN a_d[31]
    DIRECTION INPUT ;
    USE SIGNAL ;
    PORT
      LAYER M5 ;
        RECT  4.464 103.572 4.488 103.656 ;
    END
  END a_d[31]
  PIN a_d[320]
    DIRECTION INPUT ;
    USE SIGNAL ;
    PORT
      LAYER M3 ;
        RECT  32.76 103.618 32.778 103.656 ;
    END
  END a_d[320]
  PIN a_d[321]
    DIRECTION INPUT ;
    USE SIGNAL ;
    PORT
      LAYER M5 ;
        RECT  32.832 103.572 32.856 103.656 ;
    END
  END a_d[321]
  PIN a_d[322]
    DIRECTION INPUT ;
    USE SIGNAL ;
    PORT
      LAYER M3 ;
        RECT  32.94 103.618 32.958 103.656 ;
    END
  END a_d[322]
  PIN a_d[323]
    DIRECTION INPUT ;
    USE SIGNAL ;
    PORT
      LAYER M5 ;
        RECT  33.072 103.572 33.096 103.656 ;
    END
  END a_d[323]
  PIN a_d[324]
    DIRECTION INPUT ;
    USE SIGNAL ;
    PORT
      LAYER M3 ;
        RECT  33.156 103.618 33.174 103.656 ;
    END
  END a_d[324]
  PIN a_d[325]
    DIRECTION INPUT ;
    USE SIGNAL ;
    PORT
      LAYER M5 ;
        RECT  33.264 103.572 33.288 103.656 ;
    END
  END a_d[325]
  PIN a_d[326]
    DIRECTION INPUT ;
    USE SIGNAL ;
    PORT
      LAYER M3 ;
        RECT  33.336 103.618 33.354 103.656 ;
    END
  END a_d[326]
  PIN a_d[327]
    DIRECTION INPUT ;
    USE SIGNAL ;
    PORT
      LAYER M5 ;
        RECT  33.456 103.572 33.48 103.656 ;
    END
  END a_d[327]
  PIN a_d[328]
    DIRECTION INPUT ;
    USE SIGNAL ;
    PORT
      LAYER M3 ;
        RECT  33.552 103.618 33.57 103.656 ;
    END
  END a_d[328]
  PIN a_d[329]
    DIRECTION INPUT ;
    USE SIGNAL ;
    PORT
      LAYER M5 ;
        RECT  33.648 103.572 33.672 103.656 ;
    END
  END a_d[329]
  PIN a_d[32]
    DIRECTION INPUT ;
    USE SIGNAL ;
    PORT
      LAYER M3 ;
        RECT  4.572 103.618 4.59 103.656 ;
    END
  END a_d[32]
  PIN a_d[330]
    DIRECTION INPUT ;
    USE SIGNAL ;
    PORT
      LAYER M3 ;
        RECT  33.732 103.618 33.75 103.656 ;
    END
  END a_d[330]
  PIN a_d[331]
    DIRECTION INPUT ;
    USE SIGNAL ;
    PORT
      LAYER M5 ;
        RECT  33.84 103.572 33.864 103.656 ;
    END
  END a_d[331]
  PIN a_d[332]
    DIRECTION INPUT ;
    USE SIGNAL ;
    PORT
      LAYER M3 ;
        RECT  33.948 103.618 33.966 103.656 ;
    END
  END a_d[332]
  PIN a_d[333]
    DIRECTION INPUT ;
    USE SIGNAL ;
    PORT
      LAYER M5 ;
        RECT  34.032 103.572 34.056 103.656 ;
    END
  END a_d[333]
  PIN a_d[334]
    DIRECTION INPUT ;
    USE SIGNAL ;
    PORT
      LAYER M3 ;
        RECT  34.128 103.618 34.146 103.656 ;
    END
  END a_d[334]
  PIN a_d[335]
    DIRECTION INPUT ;
    USE SIGNAL ;
    PORT
      LAYER M5 ;
        RECT  34.224 103.572 34.248 103.656 ;
    END
  END a_d[335]
  PIN a_d[336]
    DIRECTION INPUT ;
    USE SIGNAL ;
    PORT
      LAYER M3 ;
        RECT  34.308 103.618 34.326 103.656 ;
    END
  END a_d[336]
  PIN a_d[337]
    DIRECTION INPUT ;
    USE SIGNAL ;
    PORT
      LAYER M5 ;
        RECT  34.416 103.572 34.44 103.656 ;
    END
  END a_d[337]
  PIN a_d[338]
    DIRECTION INPUT ;
    USE SIGNAL ;
    PORT
      LAYER M3 ;
        RECT  34.524 103.618 34.542 103.656 ;
    END
  END a_d[338]
  PIN a_d[339]
    DIRECTION INPUT ;
    USE SIGNAL ;
    PORT
      LAYER M5 ;
        RECT  34.608 103.572 34.632 103.656 ;
    END
  END a_d[339]
  PIN a_d[33]
    DIRECTION INPUT ;
    USE SIGNAL ;
    PORT
      LAYER M5 ;
        RECT  4.656 103.572 4.68 103.656 ;
    END
  END a_d[33]
  PIN a_d[340]
    DIRECTION INPUT ;
    USE SIGNAL ;
    PORT
      LAYER M3 ;
        RECT  34.704 103.618 34.722 103.656 ;
    END
  END a_d[340]
  PIN a_d[341]
    DIRECTION INPUT ;
    USE SIGNAL ;
    PORT
      LAYER M5 ;
        RECT  34.8 103.572 34.824 103.656 ;
    END
  END a_d[341]
  PIN a_d[342]
    DIRECTION INPUT ;
    USE SIGNAL ;
    PORT
      LAYER M3 ;
        RECT  34.92 103.618 34.938 103.656 ;
    END
  END a_d[342]
  PIN a_d[343]
    DIRECTION INPUT ;
    USE SIGNAL ;
    PORT
      LAYER M5 ;
        RECT  34.992 103.572 35.016 103.656 ;
    END
  END a_d[343]
  PIN a_d[344]
    DIRECTION INPUT ;
    USE SIGNAL ;
    PORT
      LAYER M3 ;
        RECT  35.1 103.618 35.118 103.656 ;
    END
  END a_d[344]
  PIN a_d[345]
    DIRECTION INPUT ;
    USE SIGNAL ;
    PORT
      LAYER M5 ;
        RECT  35.184 103.572 35.208 103.656 ;
    END
  END a_d[345]
  PIN a_d[346]
    DIRECTION INPUT ;
    USE SIGNAL ;
    PORT
      LAYER M3 ;
        RECT  35.316 103.618 35.334 103.656 ;
    END
  END a_d[346]
  PIN a_d[347]
    DIRECTION INPUT ;
    USE SIGNAL ;
    PORT
      LAYER M5 ;
        RECT  35.376 103.572 35.4 103.656 ;
    END
  END a_d[347]
  PIN a_d[348]
    DIRECTION INPUT ;
    USE SIGNAL ;
    PORT
      LAYER M3 ;
        RECT  35.496 103.618 35.514 103.656 ;
    END
  END a_d[348]
  PIN a_d[349]
    DIRECTION INPUT ;
    USE SIGNAL ;
    PORT
      LAYER M5 ;
        RECT  35.616 103.572 35.64 103.656 ;
    END
  END a_d[349]
  PIN a_d[34]
    DIRECTION INPUT ;
    USE SIGNAL ;
    PORT
      LAYER M3 ;
        RECT  4.788 103.618 4.806 103.656 ;
    END
  END a_d[34]
  PIN a_d[350]
    DIRECTION INPUT ;
    USE SIGNAL ;
    PORT
      LAYER M3 ;
        RECT  35.712 103.618 35.73 103.656 ;
    END
  END a_d[350]
  PIN a_d[351]
    DIRECTION INPUT ;
    USE SIGNAL ;
    PORT
      LAYER M5 ;
        RECT  35.808 103.572 35.832 103.656 ;
    END
  END a_d[351]
  PIN a_d[352]
    DIRECTION INPUT ;
    USE SIGNAL ;
    PORT
      LAYER M3 ;
        RECT  35.892 103.618 35.91 103.656 ;
    END
  END a_d[352]
  PIN a_d[353]
    DIRECTION INPUT ;
    USE SIGNAL ;
    PORT
      LAYER M5 ;
        RECT  36 103.572 36.024 103.656 ;
    END
  END a_d[353]
  PIN a_d[354]
    DIRECTION INPUT ;
    USE SIGNAL ;
    PORT
      LAYER M3 ;
        RECT  36.072 103.618 36.09 103.656 ;
    END
  END a_d[354]
  PIN a_d[355]
    DIRECTION INPUT ;
    USE SIGNAL ;
    PORT
      LAYER M5 ;
        RECT  36.192 103.572 36.216 103.656 ;
    END
  END a_d[355]
  PIN a_d[356]
    DIRECTION INPUT ;
    USE SIGNAL ;
    PORT
      LAYER M3 ;
        RECT  36.288 103.618 36.306 103.656 ;
    END
  END a_d[356]
  PIN a_d[357]
    DIRECTION INPUT ;
    USE SIGNAL ;
    PORT
      LAYER M5 ;
        RECT  36.384 103.572 36.408 103.656 ;
    END
  END a_d[357]
  PIN a_d[358]
    DIRECTION INPUT ;
    USE SIGNAL ;
    PORT
      LAYER M3 ;
        RECT  36.468 103.618 36.486 103.656 ;
    END
  END a_d[358]
  PIN a_d[359]
    DIRECTION INPUT ;
    USE SIGNAL ;
    PORT
      LAYER M5 ;
        RECT  36.576 103.572 36.6 103.656 ;
    END
  END a_d[359]
  PIN a_d[35]
    DIRECTION INPUT ;
    USE SIGNAL ;
    PORT
      LAYER M5 ;
        RECT  4.848 103.572 4.872 103.656 ;
    END
  END a_d[35]
  PIN a_d[360]
    DIRECTION INPUT ;
    USE SIGNAL ;
    PORT
      LAYER M3 ;
        RECT  36.684 103.618 36.702 103.656 ;
    END
  END a_d[360]
  PIN a_d[361]
    DIRECTION INPUT ;
    USE SIGNAL ;
    PORT
      LAYER M5 ;
        RECT  36.768 103.572 36.792 103.656 ;
    END
  END a_d[361]
  PIN a_d[362]
    DIRECTION INPUT ;
    USE SIGNAL ;
    PORT
      LAYER M3 ;
        RECT  36.864 103.618 36.882 103.656 ;
    END
  END a_d[362]
  PIN a_d[363]
    DIRECTION INPUT ;
    USE SIGNAL ;
    PORT
      LAYER M5 ;
        RECT  36.96 103.572 36.984 103.656 ;
    END
  END a_d[363]
  PIN a_d[364]
    DIRECTION INPUT ;
    USE SIGNAL ;
    PORT
      LAYER M3 ;
        RECT  37.08 103.618 37.098 103.656 ;
    END
  END a_d[364]
  PIN a_d[365]
    DIRECTION INPUT ;
    USE SIGNAL ;
    PORT
      LAYER M5 ;
        RECT  37.152 103.572 37.176 103.656 ;
    END
  END a_d[365]
  PIN a_d[366]
    DIRECTION INPUT ;
    USE SIGNAL ;
    PORT
      LAYER M3 ;
        RECT  37.26 103.618 37.278 103.656 ;
    END
  END a_d[366]
  PIN a_d[367]
    DIRECTION INPUT ;
    USE SIGNAL ;
    PORT
      LAYER M5 ;
        RECT  37.344 103.572 37.368 103.656 ;
    END
  END a_d[367]
  PIN a_d[368]
    DIRECTION INPUT ;
    USE SIGNAL ;
    PORT
      LAYER M3 ;
        RECT  37.44 103.618 37.458 103.656 ;
    END
  END a_d[368]
  PIN a_d[369]
    DIRECTION INPUT ;
    USE SIGNAL ;
    PORT
      LAYER M5 ;
        RECT  37.536 103.572 37.56 103.656 ;
    END
  END a_d[369]
  PIN a_d[36]
    DIRECTION INPUT ;
    USE SIGNAL ;
    PORT
      LAYER M3 ;
        RECT  4.968 103.618 4.986 103.656 ;
    END
  END a_d[36]
  PIN a_d[370]
    DIRECTION INPUT ;
    USE SIGNAL ;
    PORT
      LAYER M3 ;
        RECT  37.656 103.618 37.674 103.656 ;
    END
  END a_d[370]
  PIN a_d[371]
    DIRECTION INPUT ;
    USE SIGNAL ;
    PORT
      LAYER M5 ;
        RECT  37.728 103.572 37.752 103.656 ;
    END
  END a_d[371]
  PIN a_d[372]
    DIRECTION INPUT ;
    USE SIGNAL ;
    PORT
      LAYER M3 ;
        RECT  37.836 103.618 37.854 103.656 ;
    END
  END a_d[372]
  PIN a_d[373]
    DIRECTION INPUT ;
    USE SIGNAL ;
    PORT
      LAYER M5 ;
        RECT  37.92 103.572 37.944 103.656 ;
    END
  END a_d[373]
  PIN a_d[374]
    DIRECTION INPUT ;
    USE SIGNAL ;
    PORT
      LAYER M3 ;
        RECT  38.052 103.618 38.07 103.656 ;
    END
  END a_d[374]
  PIN a_d[375]
    DIRECTION INPUT ;
    USE SIGNAL ;
    PORT
      LAYER M5 ;
        RECT  38.16 103.572 38.184 103.656 ;
    END
  END a_d[375]
  PIN a_d[376]
    DIRECTION INPUT ;
    USE SIGNAL ;
    PORT
      LAYER M3 ;
        RECT  38.232 103.618 38.25 103.656 ;
    END
  END a_d[376]
  PIN a_d[377]
    DIRECTION INPUT ;
    USE SIGNAL ;
    PORT
      LAYER M5 ;
        RECT  38.352 103.572 38.376 103.656 ;
    END
  END a_d[377]
  PIN a_d[378]
    DIRECTION INPUT ;
    USE SIGNAL ;
    PORT
      LAYER M3 ;
        RECT  38.448 103.618 38.466 103.656 ;
    END
  END a_d[378]
  PIN a_d[379]
    DIRECTION INPUT ;
    USE SIGNAL ;
    PORT
      LAYER M5 ;
        RECT  38.544 103.572 38.568 103.656 ;
    END
  END a_d[379]
  PIN a_d[37]
    DIRECTION INPUT ;
    USE SIGNAL ;
    PORT
      LAYER M5 ;
        RECT  5.04 103.572 5.064 103.656 ;
    END
  END a_d[37]
  PIN a_d[380]
    DIRECTION INPUT ;
    USE SIGNAL ;
    PORT
      LAYER M3 ;
        RECT  38.628 103.618 38.646 103.656 ;
    END
  END a_d[380]
  PIN a_d[381]
    DIRECTION INPUT ;
    USE SIGNAL ;
    PORT
      LAYER M5 ;
        RECT  38.736 103.572 38.76 103.656 ;
    END
  END a_d[381]
  PIN a_d[382]
    DIRECTION INPUT ;
    USE SIGNAL ;
    PORT
      LAYER M3 ;
        RECT  38.844 103.618 38.862 103.656 ;
    END
  END a_d[382]
  PIN a_d[383]
    DIRECTION INPUT ;
    USE SIGNAL ;
    PORT
      LAYER M5 ;
        RECT  38.928 103.572 38.952 103.656 ;
    END
  END a_d[383]
  PIN a_d[384]
    DIRECTION INPUT ;
    USE SIGNAL ;
    PORT
      LAYER M3 ;
        RECT  39.024 103.618 39.042 103.656 ;
    END
  END a_d[384]
  PIN a_d[385]
    DIRECTION INPUT ;
    USE SIGNAL ;
    PORT
      LAYER M5 ;
        RECT  39.12 103.572 39.144 103.656 ;
    END
  END a_d[385]
  PIN a_d[386]
    DIRECTION INPUT ;
    USE SIGNAL ;
    PORT
      LAYER M3 ;
        RECT  39.204 103.618 39.222 103.656 ;
    END
  END a_d[386]
  PIN a_d[387]
    DIRECTION INPUT ;
    USE SIGNAL ;
    PORT
      LAYER M5 ;
        RECT  39.312 103.572 39.336 103.656 ;
    END
  END a_d[387]
  PIN a_d[388]
    DIRECTION INPUT ;
    USE SIGNAL ;
    PORT
      LAYER M3 ;
        RECT  39.42 103.618 39.438 103.656 ;
    END
  END a_d[388]
  PIN a_d[389]
    DIRECTION INPUT ;
    USE SIGNAL ;
    PORT
      LAYER M5 ;
        RECT  39.504 103.572 39.528 103.656 ;
    END
  END a_d[389]
  PIN a_d[38]
    DIRECTION INPUT ;
    USE SIGNAL ;
    PORT
      LAYER M3 ;
        RECT  5.148 103.618 5.166 103.656 ;
    END
  END a_d[38]
  PIN a_d[390]
    DIRECTION INPUT ;
    USE SIGNAL ;
    PORT
      LAYER M3 ;
        RECT  39.6 103.618 39.618 103.656 ;
    END
  END a_d[390]
  PIN a_d[391]
    DIRECTION INPUT ;
    USE SIGNAL ;
    PORT
      LAYER M5 ;
        RECT  39.696 103.572 39.72 103.656 ;
    END
  END a_d[391]
  PIN a_d[392]
    DIRECTION INPUT ;
    USE SIGNAL ;
    PORT
      LAYER M3 ;
        RECT  39.816 103.618 39.834 103.656 ;
    END
  END a_d[392]
  PIN a_d[393]
    DIRECTION INPUT ;
    USE SIGNAL ;
    PORT
      LAYER M5 ;
        RECT  39.888 103.572 39.912 103.656 ;
    END
  END a_d[393]
  PIN a_d[394]
    DIRECTION INPUT ;
    USE SIGNAL ;
    PORT
      LAYER M3 ;
        RECT  39.996 103.618 40.014 103.656 ;
    END
  END a_d[394]
  PIN a_d[395]
    DIRECTION INPUT ;
    USE SIGNAL ;
    PORT
      LAYER M5 ;
        RECT  40.08 103.572 40.104 103.656 ;
    END
  END a_d[395]
  PIN a_d[396]
    DIRECTION INPUT ;
    USE SIGNAL ;
    PORT
      LAYER M3 ;
        RECT  40.212 103.618 40.23 103.656 ;
    END
  END a_d[396]
  PIN a_d[397]
    DIRECTION INPUT ;
    USE SIGNAL ;
    PORT
      LAYER M5 ;
        RECT  40.272 103.572 40.296 103.656 ;
    END
  END a_d[397]
  PIN a_d[398]
    DIRECTION INPUT ;
    USE SIGNAL ;
    PORT
      LAYER M3 ;
        RECT  40.392 103.618 40.41 103.656 ;
    END
  END a_d[398]
  PIN a_d[399]
    DIRECTION INPUT ;
    USE SIGNAL ;
    PORT
      LAYER M5 ;
        RECT  40.464 103.572 40.488 103.656 ;
    END
  END a_d[399]
  PIN a_d[39]
    DIRECTION INPUT ;
    USE SIGNAL ;
    PORT
      LAYER M5 ;
        RECT  5.28 103.572 5.304 103.656 ;
    END
  END a_d[39]
  PIN a_d[3]
    DIRECTION INPUT ;
    USE SIGNAL ;
    PORT
      LAYER M5 ;
        RECT  1.728 103.572 1.752 103.656 ;
    END
  END a_d[3]
  PIN a_d[400]
    DIRECTION INPUT ;
    USE SIGNAL ;
    PORT
      LAYER M3 ;
        RECT  40.572 103.618 40.59 103.656 ;
    END
  END a_d[400]
  PIN a_d[401]
    DIRECTION INPUT ;
    USE SIGNAL ;
    PORT
      LAYER M5 ;
        RECT  40.704 103.572 40.728 103.656 ;
    END
  END a_d[401]
  PIN a_d[402]
    DIRECTION INPUT ;
    USE SIGNAL ;
    PORT
      LAYER M3 ;
        RECT  40.788 103.618 40.806 103.656 ;
    END
  END a_d[402]
  PIN a_d[403]
    DIRECTION INPUT ;
    USE SIGNAL ;
    PORT
      LAYER M5 ;
        RECT  40.896 103.572 40.92 103.656 ;
    END
  END a_d[403]
  PIN a_d[404]
    DIRECTION INPUT ;
    USE SIGNAL ;
    PORT
      LAYER M3 ;
        RECT  40.968 103.618 40.986 103.656 ;
    END
  END a_d[404]
  PIN a_d[405]
    DIRECTION INPUT ;
    USE SIGNAL ;
    PORT
      LAYER M5 ;
        RECT  41.088 103.572 41.112 103.656 ;
    END
  END a_d[405]
  PIN a_d[406]
    DIRECTION INPUT ;
    USE SIGNAL ;
    PORT
      LAYER M3 ;
        RECT  41.184 103.618 41.202 103.656 ;
    END
  END a_d[406]
  PIN a_d[407]
    DIRECTION INPUT ;
    USE SIGNAL ;
    PORT
      LAYER M5 ;
        RECT  41.28 103.572 41.304 103.656 ;
    END
  END a_d[407]
  PIN a_d[408]
    DIRECTION INPUT ;
    USE SIGNAL ;
    PORT
      LAYER M3 ;
        RECT  41.364 103.618 41.382 103.656 ;
    END
  END a_d[408]
  PIN a_d[409]
    DIRECTION INPUT ;
    USE SIGNAL ;
    PORT
      LAYER M5 ;
        RECT  41.472 103.572 41.496 103.656 ;
    END
  END a_d[409]
  PIN a_d[40]
    DIRECTION INPUT ;
    USE SIGNAL ;
    PORT
      LAYER M3 ;
        RECT  5.364 103.618 5.382 103.656 ;
    END
  END a_d[40]
  PIN a_d[410]
    DIRECTION INPUT ;
    USE SIGNAL ;
    PORT
      LAYER M3 ;
        RECT  41.58 103.618 41.598 103.656 ;
    END
  END a_d[410]
  PIN a_d[411]
    DIRECTION INPUT ;
    USE SIGNAL ;
    PORT
      LAYER M5 ;
        RECT  41.664 103.572 41.688 103.656 ;
    END
  END a_d[411]
  PIN a_d[412]
    DIRECTION INPUT ;
    USE SIGNAL ;
    PORT
      LAYER M3 ;
        RECT  41.76 103.618 41.778 103.656 ;
    END
  END a_d[412]
  PIN a_d[413]
    DIRECTION INPUT ;
    USE SIGNAL ;
    PORT
      LAYER M5 ;
        RECT  41.856 103.572 41.88 103.656 ;
    END
  END a_d[413]
  PIN a_d[414]
    DIRECTION INPUT ;
    USE SIGNAL ;
    PORT
      LAYER M3 ;
        RECT  41.976 103.618 41.994 103.656 ;
    END
  END a_d[414]
  PIN a_d[415]
    DIRECTION INPUT ;
    USE SIGNAL ;
    PORT
      LAYER M5 ;
        RECT  42.048 103.572 42.072 103.656 ;
    END
  END a_d[415]
  PIN a_d[416]
    DIRECTION INPUT ;
    USE SIGNAL ;
    PORT
      LAYER M3 ;
        RECT  42.156 103.618 42.174 103.656 ;
    END
  END a_d[416]
  PIN a_d[417]
    DIRECTION INPUT ;
    USE SIGNAL ;
    PORT
      LAYER M5 ;
        RECT  42.24 103.572 42.264 103.656 ;
    END
  END a_d[417]
  PIN a_d[418]
    DIRECTION INPUT ;
    USE SIGNAL ;
    PORT
      LAYER M3 ;
        RECT  42.336 103.618 42.354 103.656 ;
    END
  END a_d[418]
  PIN a_d[419]
    DIRECTION INPUT ;
    USE SIGNAL ;
    PORT
      LAYER M5 ;
        RECT  42.432 103.572 42.456 103.656 ;
    END
  END a_d[419]
  PIN a_d[41]
    DIRECTION INPUT ;
    USE SIGNAL ;
    PORT
      LAYER M5 ;
        RECT  5.472 103.572 5.496 103.656 ;
    END
  END a_d[41]
  PIN a_d[420]
    DIRECTION INPUT ;
    USE SIGNAL ;
    PORT
      LAYER M3 ;
        RECT  42.552 103.618 42.57 103.656 ;
    END
  END a_d[420]
  PIN a_d[421]
    DIRECTION INPUT ;
    USE SIGNAL ;
    PORT
      LAYER M5 ;
        RECT  42.624 103.572 42.648 103.656 ;
    END
  END a_d[421]
  PIN a_d[422]
    DIRECTION INPUT ;
    USE SIGNAL ;
    PORT
      LAYER M3 ;
        RECT  42.732 103.618 42.75 103.656 ;
    END
  END a_d[422]
  PIN a_d[423]
    DIRECTION INPUT ;
    USE SIGNAL ;
    PORT
      LAYER M5 ;
        RECT  42.816 103.572 42.84 103.656 ;
    END
  END a_d[423]
  PIN a_d[424]
    DIRECTION INPUT ;
    USE SIGNAL ;
    PORT
      LAYER M3 ;
        RECT  42.948 103.618 42.966 103.656 ;
    END
  END a_d[424]
  PIN a_d[425]
    DIRECTION INPUT ;
    USE SIGNAL ;
    PORT
      LAYER M5 ;
        RECT  43.056 103.572 43.08 103.656 ;
    END
  END a_d[425]
  PIN a_d[426]
    DIRECTION INPUT ;
    USE SIGNAL ;
    PORT
      LAYER M3 ;
        RECT  43.128 103.618 43.146 103.656 ;
    END
  END a_d[426]
  PIN a_d[427]
    DIRECTION INPUT ;
    USE SIGNAL ;
    PORT
      LAYER M5 ;
        RECT  43.248 103.572 43.272 103.656 ;
    END
  END a_d[427]
  PIN a_d[428]
    DIRECTION INPUT ;
    USE SIGNAL ;
    PORT
      LAYER M3 ;
        RECT  43.344 103.618 43.362 103.656 ;
    END
  END a_d[428]
  PIN a_d[429]
    DIRECTION INPUT ;
    USE SIGNAL ;
    PORT
      LAYER M5 ;
        RECT  43.44 103.572 43.464 103.656 ;
    END
  END a_d[429]
  PIN a_d[42]
    DIRECTION INPUT ;
    USE SIGNAL ;
    PORT
      LAYER M3 ;
        RECT  5.544 103.618 5.562 103.656 ;
    END
  END a_d[42]
  PIN a_d[430]
    DIRECTION INPUT ;
    USE SIGNAL ;
    PORT
      LAYER M3 ;
        RECT  43.524 103.618 43.542 103.656 ;
    END
  END a_d[430]
  PIN a_d[431]
    DIRECTION INPUT ;
    USE SIGNAL ;
    PORT
      LAYER M5 ;
        RECT  43.632 103.572 43.656 103.656 ;
    END
  END a_d[431]
  PIN a_d[432]
    DIRECTION INPUT ;
    USE SIGNAL ;
    PORT
      LAYER M3 ;
        RECT  43.704 103.618 43.722 103.656 ;
    END
  END a_d[432]
  PIN a_d[433]
    DIRECTION INPUT ;
    USE SIGNAL ;
    PORT
      LAYER M5 ;
        RECT  43.824 103.572 43.848 103.656 ;
    END
  END a_d[433]
  PIN a_d[434]
    DIRECTION INPUT ;
    USE SIGNAL ;
    PORT
      LAYER M3 ;
        RECT  43.92 103.618 43.938 103.656 ;
    END
  END a_d[434]
  PIN a_d[435]
    DIRECTION INPUT ;
    USE SIGNAL ;
    PORT
      LAYER M5 ;
        RECT  44.016 103.572 44.04 103.656 ;
    END
  END a_d[435]
  PIN a_d[436]
    DIRECTION INPUT ;
    USE SIGNAL ;
    PORT
      LAYER M3 ;
        RECT  44.1 103.618 44.118 103.656 ;
    END
  END a_d[436]
  PIN a_d[437]
    DIRECTION INPUT ;
    USE SIGNAL ;
    PORT
      LAYER M5 ;
        RECT  44.208 103.572 44.232 103.656 ;
    END
  END a_d[437]
  PIN a_d[438]
    DIRECTION INPUT ;
    USE SIGNAL ;
    PORT
      LAYER M3 ;
        RECT  44.316 103.618 44.334 103.656 ;
    END
  END a_d[438]
  PIN a_d[439]
    DIRECTION INPUT ;
    USE SIGNAL ;
    PORT
      LAYER M5 ;
        RECT  44.4 103.572 44.424 103.656 ;
    END
  END a_d[439]
  PIN a_d[43]
    DIRECTION INPUT ;
    USE SIGNAL ;
    PORT
      LAYER M5 ;
        RECT  5.664 103.572 5.688 103.656 ;
    END
  END a_d[43]
  PIN a_d[440]
    DIRECTION INPUT ;
    USE SIGNAL ;
    PORT
      LAYER M3 ;
        RECT  44.496 103.618 44.514 103.656 ;
    END
  END a_d[440]
  PIN a_d[441]
    DIRECTION INPUT ;
    USE SIGNAL ;
    PORT
      LAYER M5 ;
        RECT  44.592 103.572 44.616 103.656 ;
    END
  END a_d[441]
  PIN a_d[442]
    DIRECTION INPUT ;
    USE SIGNAL ;
    PORT
      LAYER M3 ;
        RECT  44.712 103.618 44.73 103.656 ;
    END
  END a_d[442]
  PIN a_d[443]
    DIRECTION INPUT ;
    USE SIGNAL ;
    PORT
      LAYER M5 ;
        RECT  44.784 103.572 44.808 103.656 ;
    END
  END a_d[443]
  PIN a_d[444]
    DIRECTION INPUT ;
    USE SIGNAL ;
    PORT
      LAYER M3 ;
        RECT  44.892 103.618 44.91 103.656 ;
    END
  END a_d[444]
  PIN a_d[445]
    DIRECTION INPUT ;
    USE SIGNAL ;
    PORT
      LAYER M5 ;
        RECT  44.976 103.572 45 103.656 ;
    END
  END a_d[445]
  PIN a_d[446]
    DIRECTION INPUT ;
    USE SIGNAL ;
    PORT
      LAYER M3 ;
        RECT  45.108 103.618 45.126 103.656 ;
    END
  END a_d[446]
  PIN a_d[447]
    DIRECTION INPUT ;
    USE SIGNAL ;
    PORT
      LAYER M5 ;
        RECT  45.168 103.572 45.192 103.656 ;
    END
  END a_d[447]
  PIN a_d[448]
    DIRECTION INPUT ;
    USE SIGNAL ;
    PORT
      LAYER M3 ;
        RECT  45.288 103.618 45.306 103.656 ;
    END
  END a_d[448]
  PIN a_d[449]
    DIRECTION INPUT ;
    USE SIGNAL ;
    PORT
      LAYER M5 ;
        RECT  45.36 103.572 45.384 103.656 ;
    END
  END a_d[449]
  PIN a_d[44]
    DIRECTION INPUT ;
    USE SIGNAL ;
    PORT
      LAYER M3 ;
        RECT  5.76 103.618 5.778 103.656 ;
    END
  END a_d[44]
  PIN a_d[450]
    DIRECTION INPUT ;
    USE SIGNAL ;
    PORT
      LAYER M3 ;
        RECT  45.468 103.618 45.486 103.656 ;
    END
  END a_d[450]
  PIN a_d[451]
    DIRECTION INPUT ;
    USE SIGNAL ;
    PORT
      LAYER M5 ;
        RECT  45.6 103.572 45.624 103.656 ;
    END
  END a_d[451]
  PIN a_d[452]
    DIRECTION INPUT ;
    USE SIGNAL ;
    PORT
      LAYER M3 ;
        RECT  45.684 103.618 45.702 103.656 ;
    END
  END a_d[452]
  PIN a_d[453]
    DIRECTION INPUT ;
    USE SIGNAL ;
    PORT
      LAYER M5 ;
        RECT  45.792 103.572 45.816 103.656 ;
    END
  END a_d[453]
  PIN a_d[454]
    DIRECTION INPUT ;
    USE SIGNAL ;
    PORT
      LAYER M3 ;
        RECT  45.864 103.618 45.882 103.656 ;
    END
  END a_d[454]
  PIN a_d[455]
    DIRECTION INPUT ;
    USE SIGNAL ;
    PORT
      LAYER M5 ;
        RECT  45.984 103.572 46.008 103.656 ;
    END
  END a_d[455]
  PIN a_d[456]
    DIRECTION INPUT ;
    USE SIGNAL ;
    PORT
      LAYER M3 ;
        RECT  46.08 103.618 46.098 103.656 ;
    END
  END a_d[456]
  PIN a_d[457]
    DIRECTION INPUT ;
    USE SIGNAL ;
    PORT
      LAYER M5 ;
        RECT  46.176 103.572 46.2 103.656 ;
    END
  END a_d[457]
  PIN a_d[458]
    DIRECTION INPUT ;
    USE SIGNAL ;
    PORT
      LAYER M3 ;
        RECT  46.26 103.618 46.278 103.656 ;
    END
  END a_d[458]
  PIN a_d[459]
    DIRECTION INPUT ;
    USE SIGNAL ;
    PORT
      LAYER M5 ;
        RECT  46.368 103.572 46.392 103.656 ;
    END
  END a_d[459]
  PIN a_d[45]
    DIRECTION INPUT ;
    USE SIGNAL ;
    PORT
      LAYER M5 ;
        RECT  5.856 103.572 5.88 103.656 ;
    END
  END a_d[45]
  PIN a_d[460]
    DIRECTION INPUT ;
    USE SIGNAL ;
    PORT
      LAYER M3 ;
        RECT  46.476 103.618 46.494 103.656 ;
    END
  END a_d[460]
  PIN a_d[461]
    DIRECTION INPUT ;
    USE SIGNAL ;
    PORT
      LAYER M5 ;
        RECT  46.56 103.572 46.584 103.656 ;
    END
  END a_d[461]
  PIN a_d[462]
    DIRECTION INPUT ;
    USE SIGNAL ;
    PORT
      LAYER M3 ;
        RECT  46.656 103.618 46.674 103.656 ;
    END
  END a_d[462]
  PIN a_d[463]
    DIRECTION INPUT ;
    USE SIGNAL ;
    PORT
      LAYER M5 ;
        RECT  46.752 103.572 46.776 103.656 ;
    END
  END a_d[463]
  PIN a_d[464]
    DIRECTION INPUT ;
    USE SIGNAL ;
    PORT
      LAYER M3 ;
        RECT  46.836 103.618 46.854 103.656 ;
    END
  END a_d[464]
  PIN a_d[465]
    DIRECTION INPUT ;
    USE SIGNAL ;
    PORT
      LAYER M5 ;
        RECT  46.944 103.572 46.968 103.656 ;
    END
  END a_d[465]
  PIN a_d[466]
    DIRECTION INPUT ;
    USE SIGNAL ;
    PORT
      LAYER M3 ;
        RECT  47.052 103.618 47.07 103.656 ;
    END
  END a_d[466]
  PIN a_d[467]
    DIRECTION INPUT ;
    USE SIGNAL ;
    PORT
      LAYER M5 ;
        RECT  47.136 103.572 47.16 103.656 ;
    END
  END a_d[467]
  PIN a_d[468]
    DIRECTION INPUT ;
    USE SIGNAL ;
    PORT
      LAYER M3 ;
        RECT  47.232 103.618 47.25 103.656 ;
    END
  END a_d[468]
  PIN a_d[469]
    DIRECTION INPUT ;
    USE SIGNAL ;
    PORT
      LAYER M5 ;
        RECT  47.328 103.572 47.352 103.656 ;
    END
  END a_d[469]
  PIN a_d[46]
    DIRECTION INPUT ;
    USE SIGNAL ;
    PORT
      LAYER M3 ;
        RECT  5.94 103.618 5.958 103.656 ;
    END
  END a_d[46]
  PIN a_d[470]
    DIRECTION INPUT ;
    USE SIGNAL ;
    PORT
      LAYER M3 ;
        RECT  47.448 103.618 47.466 103.656 ;
    END
  END a_d[470]
  PIN a_d[471]
    DIRECTION INPUT ;
    USE SIGNAL ;
    PORT
      LAYER M5 ;
        RECT  47.52 103.572 47.544 103.656 ;
    END
  END a_d[471]
  PIN a_d[472]
    DIRECTION INPUT ;
    USE SIGNAL ;
    PORT
      LAYER M3 ;
        RECT  47.628 103.618 47.646 103.656 ;
    END
  END a_d[472]
  PIN a_d[473]
    DIRECTION INPUT ;
    USE SIGNAL ;
    PORT
      LAYER M5 ;
        RECT  47.712 103.572 47.736 103.656 ;
    END
  END a_d[473]
  PIN a_d[474]
    DIRECTION INPUT ;
    USE SIGNAL ;
    PORT
      LAYER M3 ;
        RECT  47.844 103.618 47.862 103.656 ;
    END
  END a_d[474]
  PIN a_d[475]
    DIRECTION INPUT ;
    USE SIGNAL ;
    PORT
      LAYER M5 ;
        RECT  47.904 103.572 47.928 103.656 ;
    END
  END a_d[475]
  PIN a_d[476]
    DIRECTION INPUT ;
    USE SIGNAL ;
    PORT
      LAYER M3 ;
        RECT  48.024 103.618 48.042 103.656 ;
    END
  END a_d[476]
  PIN a_d[477]
    DIRECTION INPUT ;
    USE SIGNAL ;
    PORT
      LAYER M5 ;
        RECT  48.144 103.572 48.168 103.656 ;
    END
  END a_d[477]
  PIN a_d[478]
    DIRECTION INPUT ;
    USE SIGNAL ;
    PORT
      LAYER M3 ;
        RECT  48.204 103.618 48.222 103.656 ;
    END
  END a_d[478]
  PIN a_d[479]
    DIRECTION INPUT ;
    USE SIGNAL ;
    PORT
      LAYER M5 ;
        RECT  48.336 103.572 48.36 103.656 ;
    END
  END a_d[479]
  PIN a_d[47]
    DIRECTION INPUT ;
    USE SIGNAL ;
    PORT
      LAYER M5 ;
        RECT  6.048 103.572 6.072 103.656 ;
    END
  END a_d[47]
  PIN a_d[480]
    DIRECTION INPUT ;
    USE SIGNAL ;
    PORT
      LAYER M3 ;
        RECT  48.42 103.618 48.438 103.656 ;
    END
  END a_d[480]
  PIN a_d[481]
    DIRECTION INPUT ;
    USE SIGNAL ;
    PORT
      LAYER M5 ;
        RECT  48.528 103.572 48.552 103.656 ;
    END
  END a_d[481]
  PIN a_d[482]
    DIRECTION INPUT ;
    USE SIGNAL ;
    PORT
      LAYER M3 ;
        RECT  48.6 103.618 48.618 103.656 ;
    END
  END a_d[482]
  PIN a_d[483]
    DIRECTION INPUT ;
    USE SIGNAL ;
    PORT
      LAYER M5 ;
        RECT  48.72 103.572 48.744 103.656 ;
    END
  END a_d[483]
  PIN a_d[484]
    DIRECTION INPUT ;
    USE SIGNAL ;
    PORT
      LAYER M3 ;
        RECT  48.816 103.618 48.834 103.656 ;
    END
  END a_d[484]
  PIN a_d[485]
    DIRECTION INPUT ;
    USE SIGNAL ;
    PORT
      LAYER M5 ;
        RECT  48.912 103.572 48.936 103.656 ;
    END
  END a_d[485]
  PIN a_d[486]
    DIRECTION INPUT ;
    USE SIGNAL ;
    PORT
      LAYER M3 ;
        RECT  48.996 103.618 49.014 103.656 ;
    END
  END a_d[486]
  PIN a_d[487]
    DIRECTION INPUT ;
    USE SIGNAL ;
    PORT
      LAYER M5 ;
        RECT  49.104 103.572 49.128 103.656 ;
    END
  END a_d[487]
  PIN a_d[488]
    DIRECTION INPUT ;
    USE SIGNAL ;
    PORT
      LAYER M3 ;
        RECT  49.212 103.618 49.23 103.656 ;
    END
  END a_d[488]
  PIN a_d[489]
    DIRECTION INPUT ;
    USE SIGNAL ;
    PORT
      LAYER M5 ;
        RECT  49.296 103.572 49.32 103.656 ;
    END
  END a_d[489]
  PIN a_d[48]
    DIRECTION INPUT ;
    USE SIGNAL ;
    PORT
      LAYER M3 ;
        RECT  6.156 103.618 6.174 103.656 ;
    END
  END a_d[48]
  PIN a_d[490]
    DIRECTION INPUT ;
    USE SIGNAL ;
    PORT
      LAYER M3 ;
        RECT  49.392 103.618 49.41 103.656 ;
    END
  END a_d[490]
  PIN a_d[491]
    DIRECTION INPUT ;
    USE SIGNAL ;
    PORT
      LAYER M5 ;
        RECT  49.488 103.572 49.512 103.656 ;
    END
  END a_d[491]
  PIN a_d[492]
    DIRECTION INPUT ;
    USE SIGNAL ;
    PORT
      LAYER M3 ;
        RECT  49.608 103.618 49.626 103.656 ;
    END
  END a_d[492]
  PIN a_d[493]
    DIRECTION INPUT ;
    USE SIGNAL ;
    PORT
      LAYER M5 ;
        RECT  49.68 103.572 49.704 103.656 ;
    END
  END a_d[493]
  PIN a_d[494]
    DIRECTION INPUT ;
    USE SIGNAL ;
    PORT
      LAYER M3 ;
        RECT  49.788 103.618 49.806 103.656 ;
    END
  END a_d[494]
  PIN a_d[495]
    DIRECTION INPUT ;
    USE SIGNAL ;
    PORT
      LAYER M5 ;
        RECT  49.872 103.572 49.896 103.656 ;
    END
  END a_d[495]
  PIN a_d[496]
    DIRECTION INPUT ;
    USE SIGNAL ;
    PORT
      LAYER M3 ;
        RECT  49.968 103.618 49.986 103.656 ;
    END
  END a_d[496]
  PIN a_d[497]
    DIRECTION INPUT ;
    USE SIGNAL ;
    PORT
      LAYER M5 ;
        RECT  50.064 103.572 50.088 103.656 ;
    END
  END a_d[497]
  PIN a_d[498]
    DIRECTION INPUT ;
    USE SIGNAL ;
    PORT
      LAYER M3 ;
        RECT  50.184 103.618 50.202 103.656 ;
    END
  END a_d[498]
  PIN a_d[499]
    DIRECTION INPUT ;
    USE SIGNAL ;
    PORT
      LAYER M5 ;
        RECT  50.256 103.572 50.28 103.656 ;
    END
  END a_d[499]
  PIN a_d[49]
    DIRECTION INPUT ;
    USE SIGNAL ;
    PORT
      LAYER M5 ;
        RECT  6.24 103.572 6.264 103.656 ;
    END
  END a_d[49]
  PIN a_d[4]
    DIRECTION INPUT ;
    USE SIGNAL ;
    PORT
      LAYER M3 ;
        RECT  1.836 103.618 1.854 103.656 ;
    END
  END a_d[4]
  PIN a_d[500]
    DIRECTION INPUT ;
    USE SIGNAL ;
    PORT
      LAYER M3 ;
        RECT  50.364 103.618 50.382 103.656 ;
    END
  END a_d[500]
  PIN a_d[501]
    DIRECTION INPUT ;
    USE SIGNAL ;
    PORT
      LAYER M5 ;
        RECT  50.448 103.572 50.472 103.656 ;
    END
  END a_d[501]
  PIN a_d[502]
    DIRECTION INPUT ;
    USE SIGNAL ;
    PORT
      LAYER M3 ;
        RECT  50.58 103.618 50.598 103.656 ;
    END
  END a_d[502]
  PIN a_d[503]
    DIRECTION INPUT ;
    USE SIGNAL ;
    PORT
      LAYER M5 ;
        RECT  50.688 103.572 50.712 103.656 ;
    END
  END a_d[503]
  PIN a_d[504]
    DIRECTION INPUT ;
    USE SIGNAL ;
    PORT
      LAYER M3 ;
        RECT  50.76 103.618 50.778 103.656 ;
    END
  END a_d[504]
  PIN a_d[505]
    DIRECTION INPUT ;
    USE SIGNAL ;
    PORT
      LAYER M5 ;
        RECT  50.88 103.572 50.904 103.656 ;
    END
  END a_d[505]
  PIN a_d[506]
    DIRECTION INPUT ;
    USE SIGNAL ;
    PORT
      LAYER M3 ;
        RECT  50.976 103.618 50.994 103.656 ;
    END
  END a_d[506]
  PIN a_d[507]
    DIRECTION INPUT ;
    USE SIGNAL ;
    PORT
      LAYER M5 ;
        RECT  51.072 103.572 51.096 103.656 ;
    END
  END a_d[507]
  PIN a_d[508]
    DIRECTION INPUT ;
    USE SIGNAL ;
    PORT
      LAYER M3 ;
        RECT  51.156 103.618 51.174 103.656 ;
    END
  END a_d[508]
  PIN a_d[509]
    DIRECTION INPUT ;
    USE SIGNAL ;
    PORT
      LAYER M5 ;
        RECT  51.264 103.572 51.288 103.656 ;
    END
  END a_d[509]
  PIN a_d[50]
    DIRECTION INPUT ;
    USE SIGNAL ;
    PORT
      LAYER M3 ;
        RECT  6.336 103.618 6.354 103.656 ;
    END
  END a_d[50]
  PIN a_d[510]
    DIRECTION INPUT ;
    USE SIGNAL ;
    PORT
      LAYER M3 ;
        RECT  51.336 103.618 51.354 103.656 ;
    END
  END a_d[510]
  PIN a_d[511]
    DIRECTION INPUT ;
    USE SIGNAL ;
    PORT
      LAYER M5 ;
        RECT  51.456 103.572 51.48 103.656 ;
    END
  END a_d[511]
  PIN a_d[512]
    DIRECTION INPUT ;
    USE SIGNAL ;
    PORT
      LAYER M3 ;
        RECT  51.552 103.618 51.57 103.656 ;
    END
  END a_d[512]
  PIN a_d[513]
    DIRECTION INPUT ;
    USE SIGNAL ;
    PORT
      LAYER M5 ;
        RECT  51.648 103.572 51.672 103.656 ;
    END
  END a_d[513]
  PIN a_d[514]
    DIRECTION INPUT ;
    USE SIGNAL ;
    PORT
      LAYER M3 ;
        RECT  51.732 103.618 51.75 103.656 ;
    END
  END a_d[514]
  PIN a_d[515]
    DIRECTION INPUT ;
    USE SIGNAL ;
    PORT
      LAYER M5 ;
        RECT  51.84 103.572 51.864 103.656 ;
    END
  END a_d[515]
  PIN a_d[51]
    DIRECTION INPUT ;
    USE SIGNAL ;
    PORT
      LAYER M5 ;
        RECT  6.432 103.572 6.456 103.656 ;
    END
  END a_d[51]
  PIN a_d[52]
    DIRECTION INPUT ;
    USE SIGNAL ;
    PORT
      LAYER M3 ;
        RECT  6.516 103.618 6.534 103.656 ;
    END
  END a_d[52]
  PIN a_d[53]
    DIRECTION INPUT ;
    USE SIGNAL ;
    PORT
      LAYER M5 ;
        RECT  6.624 103.572 6.648 103.656 ;
    END
  END a_d[53]
  PIN a_d[54]
    DIRECTION INPUT ;
    USE SIGNAL ;
    PORT
      LAYER M3 ;
        RECT  6.732 103.618 6.75 103.656 ;
    END
  END a_d[54]
  PIN a_d[55]
    DIRECTION INPUT ;
    USE SIGNAL ;
    PORT
      LAYER M5 ;
        RECT  6.816 103.572 6.84 103.656 ;
    END
  END a_d[55]
  PIN a_d[56]
    DIRECTION INPUT ;
    USE SIGNAL ;
    PORT
      LAYER M3 ;
        RECT  6.912 103.618 6.93 103.656 ;
    END
  END a_d[56]
  PIN a_d[57]
    DIRECTION INPUT ;
    USE SIGNAL ;
    PORT
      LAYER M5 ;
        RECT  7.008 103.572 7.032 103.656 ;
    END
  END a_d[57]
  PIN a_d[58]
    DIRECTION INPUT ;
    USE SIGNAL ;
    PORT
      LAYER M3 ;
        RECT  7.128 103.618 7.146 103.656 ;
    END
  END a_d[58]
  PIN a_d[59]
    DIRECTION INPUT ;
    USE SIGNAL ;
    PORT
      LAYER M5 ;
        RECT  7.2 103.572 7.224 103.656 ;
    END
  END a_d[59]
  PIN a_d[5]
    DIRECTION INPUT ;
    USE SIGNAL ;
    PORT
      LAYER M5 ;
        RECT  1.92 103.572 1.944 103.656 ;
    END
  END a_d[5]
  PIN a_d[60]
    DIRECTION INPUT ;
    USE SIGNAL ;
    PORT
      LAYER M3 ;
        RECT  7.308 103.618 7.326 103.656 ;
    END
  END a_d[60]
  PIN a_d[61]
    DIRECTION INPUT ;
    USE SIGNAL ;
    PORT
      LAYER M5 ;
        RECT  7.392 103.572 7.416 103.656 ;
    END
  END a_d[61]
  PIN a_d[62]
    DIRECTION INPUT ;
    USE SIGNAL ;
    PORT
      LAYER M3 ;
        RECT  7.524 103.618 7.542 103.656 ;
    END
  END a_d[62]
  PIN a_d[63]
    DIRECTION INPUT ;
    USE SIGNAL ;
    PORT
      LAYER M5 ;
        RECT  7.584 103.572 7.608 103.656 ;
    END
  END a_d[63]
  PIN a_d[64]
    DIRECTION INPUT ;
    USE SIGNAL ;
    PORT
      LAYER M3 ;
        RECT  7.704 103.618 7.722 103.656 ;
    END
  END a_d[64]
  PIN a_d[65]
    DIRECTION INPUT ;
    USE SIGNAL ;
    PORT
      LAYER M5 ;
        RECT  7.824 103.572 7.848 103.656 ;
    END
  END a_d[65]
  PIN a_d[66]
    DIRECTION INPUT ;
    USE SIGNAL ;
    PORT
      LAYER M3 ;
        RECT  7.92 103.618 7.938 103.656 ;
    END
  END a_d[66]
  PIN a_d[67]
    DIRECTION INPUT ;
    USE SIGNAL ;
    PORT
      LAYER M5 ;
        RECT  8.016 103.572 8.04 103.656 ;
    END
  END a_d[67]
  PIN a_d[68]
    DIRECTION INPUT ;
    USE SIGNAL ;
    PORT
      LAYER M3 ;
        RECT  8.1 103.618 8.118 103.656 ;
    END
  END a_d[68]
  PIN a_d[69]
    DIRECTION INPUT ;
    USE SIGNAL ;
    PORT
      LAYER M5 ;
        RECT  8.208 103.572 8.232 103.656 ;
    END
  END a_d[69]
  PIN a_d[6]
    DIRECTION INPUT ;
    USE SIGNAL ;
    PORT
      LAYER M3 ;
        RECT  2.016 103.618 2.034 103.656 ;
    END
  END a_d[6]
  PIN a_d[70]
    DIRECTION INPUT ;
    USE SIGNAL ;
    PORT
      LAYER M3 ;
        RECT  8.28 103.618 8.298 103.656 ;
    END
  END a_d[70]
  PIN a_d[71]
    DIRECTION INPUT ;
    USE SIGNAL ;
    PORT
      LAYER M5 ;
        RECT  8.4 103.572 8.424 103.656 ;
    END
  END a_d[71]
  PIN a_d[72]
    DIRECTION INPUT ;
    USE SIGNAL ;
    PORT
      LAYER M3 ;
        RECT  8.496 103.618 8.514 103.656 ;
    END
  END a_d[72]
  PIN a_d[73]
    DIRECTION INPUT ;
    USE SIGNAL ;
    PORT
      LAYER M5 ;
        RECT  8.592 103.572 8.616 103.656 ;
    END
  END a_d[73]
  PIN a_d[74]
    DIRECTION INPUT ;
    USE SIGNAL ;
    PORT
      LAYER M3 ;
        RECT  8.676 103.618 8.694 103.656 ;
    END
  END a_d[74]
  PIN a_d[75]
    DIRECTION INPUT ;
    USE SIGNAL ;
    PORT
      LAYER M5 ;
        RECT  8.784 103.572 8.808 103.656 ;
    END
  END a_d[75]
  PIN a_d[76]
    DIRECTION INPUT ;
    USE SIGNAL ;
    PORT
      LAYER M3 ;
        RECT  8.892 103.618 8.91 103.656 ;
    END
  END a_d[76]
  PIN a_d[77]
    DIRECTION INPUT ;
    USE SIGNAL ;
    PORT
      LAYER M5 ;
        RECT  8.976 103.572 9 103.656 ;
    END
  END a_d[77]
  PIN a_d[78]
    DIRECTION INPUT ;
    USE SIGNAL ;
    PORT
      LAYER M3 ;
        RECT  9.072 103.618 9.09 103.656 ;
    END
  END a_d[78]
  PIN a_d[79]
    DIRECTION INPUT ;
    USE SIGNAL ;
    PORT
      LAYER M5 ;
        RECT  9.168 103.572 9.192 103.656 ;
    END
  END a_d[79]
  PIN a_d[7]
    DIRECTION INPUT ;
    USE SIGNAL ;
    PORT
      LAYER M5 ;
        RECT  2.112 103.572 2.136 103.656 ;
    END
  END a_d[7]
  PIN a_d[80]
    DIRECTION INPUT ;
    USE SIGNAL ;
    PORT
      LAYER M3 ;
        RECT  9.288 103.618 9.306 103.656 ;
    END
  END a_d[80]
  PIN a_d[81]
    DIRECTION INPUT ;
    USE SIGNAL ;
    PORT
      LAYER M5 ;
        RECT  9.36 103.572 9.384 103.656 ;
    END
  END a_d[81]
  PIN a_d[82]
    DIRECTION INPUT ;
    USE SIGNAL ;
    PORT
      LAYER M3 ;
        RECT  9.468 103.618 9.486 103.656 ;
    END
  END a_d[82]
  PIN a_d[83]
    DIRECTION INPUT ;
    USE SIGNAL ;
    PORT
      LAYER M5 ;
        RECT  9.552 103.572 9.576 103.656 ;
    END
  END a_d[83]
  PIN a_d[84]
    DIRECTION INPUT ;
    USE SIGNAL ;
    PORT
      LAYER M3 ;
        RECT  9.648 103.618 9.666 103.656 ;
    END
  END a_d[84]
  PIN a_d[85]
    DIRECTION INPUT ;
    USE SIGNAL ;
    PORT
      LAYER M5 ;
        RECT  9.744 103.572 9.768 103.656 ;
    END
  END a_d[85]
  PIN a_d[86]
    DIRECTION INPUT ;
    USE SIGNAL ;
    PORT
      LAYER M3 ;
        RECT  9.864 103.618 9.882 103.656 ;
    END
  END a_d[86]
  PIN a_d[87]
    DIRECTION INPUT ;
    USE SIGNAL ;
    PORT
      LAYER M5 ;
        RECT  9.936 103.572 9.96 103.656 ;
    END
  END a_d[87]
  PIN a_d[88]
    DIRECTION INPUT ;
    USE SIGNAL ;
    PORT
      LAYER M3 ;
        RECT  10.044 103.618 10.062 103.656 ;
    END
  END a_d[88]
  PIN a_d[89]
    DIRECTION INPUT ;
    USE SIGNAL ;
    PORT
      LAYER M5 ;
        RECT  10.128 103.572 10.152 103.656 ;
    END
  END a_d[89]
  PIN a_d[8]
    DIRECTION INPUT ;
    USE SIGNAL ;
    PORT
      LAYER M3 ;
        RECT  2.232 103.618 2.25 103.656 ;
    END
  END a_d[8]
  PIN a_d[90]
    DIRECTION INPUT ;
    USE SIGNAL ;
    PORT
      LAYER M3 ;
        RECT  10.26 103.618 10.278 103.656 ;
    END
  END a_d[90]
  PIN a_d[91]
    DIRECTION INPUT ;
    USE SIGNAL ;
    PORT
      LAYER M5 ;
        RECT  10.368 103.572 10.392 103.656 ;
    END
  END a_d[91]
  PIN a_d[92]
    DIRECTION INPUT ;
    USE SIGNAL ;
    PORT
      LAYER M3 ;
        RECT  10.44 103.618 10.458 103.656 ;
    END
  END a_d[92]
  PIN a_d[93]
    DIRECTION INPUT ;
    USE SIGNAL ;
    PORT
      LAYER M5 ;
        RECT  10.56 103.572 10.584 103.656 ;
    END
  END a_d[93]
  PIN a_d[94]
    DIRECTION INPUT ;
    USE SIGNAL ;
    PORT
      LAYER M3 ;
        RECT  10.656 103.618 10.674 103.656 ;
    END
  END a_d[94]
  PIN a_d[95]
    DIRECTION INPUT ;
    USE SIGNAL ;
    PORT
      LAYER M5 ;
        RECT  10.752 103.572 10.776 103.656 ;
    END
  END a_d[95]
  PIN a_d[96]
    DIRECTION INPUT ;
    USE SIGNAL ;
    PORT
      LAYER M3 ;
        RECT  10.836 103.618 10.854 103.656 ;
    END
  END a_d[96]
  PIN a_d[97]
    DIRECTION INPUT ;
    USE SIGNAL ;
    PORT
      LAYER M5 ;
        RECT  10.944 103.572 10.968 103.656 ;
    END
  END a_d[97]
  PIN a_d[98]
    DIRECTION INPUT ;
    USE SIGNAL ;
    PORT
      LAYER M3 ;
        RECT  11.052 103.618 11.07 103.656 ;
    END
  END a_d[98]
  PIN a_d[99]
    DIRECTION INPUT ;
    USE SIGNAL ;
    PORT
      LAYER M5 ;
        RECT  11.136 103.572 11.16 103.656 ;
    END
  END a_d[99]
  PIN a_d[9]
    DIRECTION INPUT ;
    USE SIGNAL ;
    PORT
      LAYER M5 ;
        RECT  2.304 103.572 2.328 103.656 ;
    END
  END a_d[9]
  PIN b_d[0]
    DIRECTION OUTPUT ;
    USE SIGNAL ;
    PORT
      LAYER M3 ;
        RECT  0.756 0 0.774 0.038 ;
    END
  END b_d[0]
  PIN b_d[100]
    DIRECTION OUTPUT ;
    USE SIGNAL ;
    PORT
      LAYER M3 ;
        RECT  10.584 0 10.602 0.038 ;
    END
  END b_d[100]
  PIN b_d[101]
    DIRECTION OUTPUT ;
    USE SIGNAL ;
    PORT
      LAYER M5 ;
        RECT  10.656 0 10.68 0.084 ;
    END
  END b_d[101]
  PIN b_d[102]
    DIRECTION OUTPUT ;
    USE SIGNAL ;
    PORT
      LAYER M3 ;
        RECT  10.764 0 10.782 0.038 ;
    END
  END b_d[102]
  PIN b_d[103]
    DIRECTION OUTPUT ;
    USE SIGNAL ;
    PORT
      LAYER M5 ;
        RECT  10.848 0 10.872 0.084 ;
    END
  END b_d[103]
  PIN b_d[104]
    DIRECTION OUTPUT ;
    USE SIGNAL ;
    PORT
      LAYER M3 ;
        RECT  10.98 0 10.998 0.038 ;
    END
  END b_d[104]
  PIN b_d[105]
    DIRECTION OUTPUT ;
    USE SIGNAL ;
    PORT
      LAYER M5 ;
        RECT  11.088 0 11.112 0.084 ;
    END
  END b_d[105]
  PIN b_d[106]
    DIRECTION OUTPUT ;
    USE SIGNAL ;
    PORT
      LAYER M3 ;
        RECT  11.16 0 11.178 0.038 ;
    END
  END b_d[106]
  PIN b_d[107]
    DIRECTION OUTPUT ;
    USE SIGNAL ;
    PORT
      LAYER M5 ;
        RECT  11.28 0 11.304 0.084 ;
    END
  END b_d[107]
  PIN b_d[108]
    DIRECTION OUTPUT ;
    USE SIGNAL ;
    PORT
      LAYER M3 ;
        RECT  11.376 0 11.394 0.038 ;
    END
  END b_d[108]
  PIN b_d[109]
    DIRECTION OUTPUT ;
    USE SIGNAL ;
    PORT
      LAYER M5 ;
        RECT  11.472 0 11.496 0.084 ;
    END
  END b_d[109]
  PIN b_d[10]
    DIRECTION OUTPUT ;
    USE SIGNAL ;
    PORT
      LAYER M3 ;
        RECT  1.764 0 1.782 0.038 ;
    END
  END b_d[10]
  PIN b_d[110]
    DIRECTION OUTPUT ;
    USE SIGNAL ;
    PORT
      LAYER M3 ;
        RECT  11.556 0 11.574 0.038 ;
    END
  END b_d[110]
  PIN b_d[111]
    DIRECTION OUTPUT ;
    USE SIGNAL ;
    PORT
      LAYER M5 ;
        RECT  11.664 0 11.688 0.084 ;
    END
  END b_d[111]
  PIN b_d[112]
    DIRECTION OUTPUT ;
    USE SIGNAL ;
    PORT
      LAYER M3 ;
        RECT  11.736 0 11.754 0.038 ;
    END
  END b_d[112]
  PIN b_d[113]
    DIRECTION OUTPUT ;
    USE SIGNAL ;
    PORT
      LAYER M5 ;
        RECT  11.856 0 11.88 0.084 ;
    END
  END b_d[113]
  PIN b_d[114]
    DIRECTION OUTPUT ;
    USE SIGNAL ;
    PORT
      LAYER M3 ;
        RECT  11.952 0 11.97 0.038 ;
    END
  END b_d[114]
  PIN b_d[115]
    DIRECTION OUTPUT ;
    USE SIGNAL ;
    PORT
      LAYER M5 ;
        RECT  12.048 0 12.072 0.084 ;
    END
  END b_d[115]
  PIN b_d[116]
    DIRECTION OUTPUT ;
    USE SIGNAL ;
    PORT
      LAYER M3 ;
        RECT  12.132 0 12.15 0.038 ;
    END
  END b_d[116]
  PIN b_d[117]
    DIRECTION OUTPUT ;
    USE SIGNAL ;
    PORT
      LAYER M5 ;
        RECT  12.24 0 12.264 0.084 ;
    END
  END b_d[117]
  PIN b_d[118]
    DIRECTION OUTPUT ;
    USE SIGNAL ;
    PORT
      LAYER M3 ;
        RECT  12.348 0 12.366 0.038 ;
    END
  END b_d[118]
  PIN b_d[119]
    DIRECTION OUTPUT ;
    USE SIGNAL ;
    PORT
      LAYER M5 ;
        RECT  12.432 0 12.456 0.084 ;
    END
  END b_d[119]
  PIN b_d[11]
    DIRECTION OUTPUT ;
    USE SIGNAL ;
    PORT
      LAYER M5 ;
        RECT  1.872 0 1.896 0.084 ;
    END
  END b_d[11]
  PIN b_d[120]
    DIRECTION OUTPUT ;
    USE SIGNAL ;
    PORT
      LAYER M3 ;
        RECT  12.528 0 12.546 0.038 ;
    END
  END b_d[120]
  PIN b_d[121]
    DIRECTION OUTPUT ;
    USE SIGNAL ;
    PORT
      LAYER M5 ;
        RECT  12.624 0 12.648 0.084 ;
    END
  END b_d[121]
  PIN b_d[122]
    DIRECTION OUTPUT ;
    USE SIGNAL ;
    PORT
      LAYER M3 ;
        RECT  12.744 0 12.762 0.038 ;
    END
  END b_d[122]
  PIN b_d[123]
    DIRECTION OUTPUT ;
    USE SIGNAL ;
    PORT
      LAYER M5 ;
        RECT  12.816 0 12.84 0.084 ;
    END
  END b_d[123]
  PIN b_d[124]
    DIRECTION OUTPUT ;
    USE SIGNAL ;
    PORT
      LAYER M3 ;
        RECT  12.924 0 12.942 0.038 ;
    END
  END b_d[124]
  PIN b_d[125]
    DIRECTION OUTPUT ;
    USE SIGNAL ;
    PORT
      LAYER M5 ;
        RECT  13.008 0 13.032 0.084 ;
    END
  END b_d[125]
  PIN b_d[126]
    DIRECTION OUTPUT ;
    USE SIGNAL ;
    PORT
      LAYER M3 ;
        RECT  13.14 0 13.158 0.038 ;
    END
  END b_d[126]
  PIN b_d[127]
    DIRECTION OUTPUT ;
    USE SIGNAL ;
    PORT
      LAYER M5 ;
        RECT  13.2 0 13.224 0.084 ;
    END
  END b_d[127]
  PIN b_d[128]
    DIRECTION OUTPUT ;
    USE SIGNAL ;
    PORT
      LAYER M3 ;
        RECT  13.32 0 13.338 0.038 ;
    END
  END b_d[128]
  PIN b_d[129]
    DIRECTION OUTPUT ;
    USE SIGNAL ;
    PORT
      LAYER M5 ;
        RECT  13.44 0 13.464 0.084 ;
    END
  END b_d[129]
  PIN b_d[12]
    DIRECTION OUTPUT ;
    USE SIGNAL ;
    PORT
      LAYER M3 ;
        RECT  1.944 0 1.962 0.038 ;
    END
  END b_d[12]
  PIN b_d[130]
    DIRECTION OUTPUT ;
    USE SIGNAL ;
    PORT
      LAYER M3 ;
        RECT  13.536 0 13.554 0.038 ;
    END
  END b_d[130]
  PIN b_d[131]
    DIRECTION OUTPUT ;
    USE SIGNAL ;
    PORT
      LAYER M5 ;
        RECT  13.632 0 13.656 0.084 ;
    END
  END b_d[131]
  PIN b_d[132]
    DIRECTION OUTPUT ;
    USE SIGNAL ;
    PORT
      LAYER M3 ;
        RECT  13.716 0 13.734 0.038 ;
    END
  END b_d[132]
  PIN b_d[133]
    DIRECTION OUTPUT ;
    USE SIGNAL ;
    PORT
      LAYER M5 ;
        RECT  13.824 0 13.848 0.084 ;
    END
  END b_d[133]
  PIN b_d[134]
    DIRECTION OUTPUT ;
    USE SIGNAL ;
    PORT
      LAYER M3 ;
        RECT  13.896 0 13.914 0.038 ;
    END
  END b_d[134]
  PIN b_d[135]
    DIRECTION OUTPUT ;
    USE SIGNAL ;
    PORT
      LAYER M5 ;
        RECT  14.016 0 14.04 0.084 ;
    END
  END b_d[135]
  PIN b_d[136]
    DIRECTION OUTPUT ;
    USE SIGNAL ;
    PORT
      LAYER M3 ;
        RECT  14.112 0 14.13 0.038 ;
    END
  END b_d[136]
  PIN b_d[137]
    DIRECTION OUTPUT ;
    USE SIGNAL ;
    PORT
      LAYER M5 ;
        RECT  14.208 0 14.232 0.084 ;
    END
  END b_d[137]
  PIN b_d[138]
    DIRECTION OUTPUT ;
    USE SIGNAL ;
    PORT
      LAYER M3 ;
        RECT  14.292 0 14.31 0.038 ;
    END
  END b_d[138]
  PIN b_d[139]
    DIRECTION OUTPUT ;
    USE SIGNAL ;
    PORT
      LAYER M5 ;
        RECT  14.4 0 14.424 0.084 ;
    END
  END b_d[139]
  PIN b_d[13]
    DIRECTION OUTPUT ;
    USE SIGNAL ;
    PORT
      LAYER M5 ;
        RECT  2.064 0 2.088 0.084 ;
    END
  END b_d[13]
  PIN b_d[140]
    DIRECTION OUTPUT ;
    USE SIGNAL ;
    PORT
      LAYER M3 ;
        RECT  14.508 0 14.526 0.038 ;
    END
  END b_d[140]
  PIN b_d[141]
    DIRECTION OUTPUT ;
    USE SIGNAL ;
    PORT
      LAYER M5 ;
        RECT  14.592 0 14.616 0.084 ;
    END
  END b_d[141]
  PIN b_d[142]
    DIRECTION OUTPUT ;
    USE SIGNAL ;
    PORT
      LAYER M3 ;
        RECT  14.688 0 14.706 0.038 ;
    END
  END b_d[142]
  PIN b_d[143]
    DIRECTION OUTPUT ;
    USE SIGNAL ;
    PORT
      LAYER M5 ;
        RECT  14.784 0 14.808 0.084 ;
    END
  END b_d[143]
  PIN b_d[144]
    DIRECTION OUTPUT ;
    USE SIGNAL ;
    PORT
      LAYER M3 ;
        RECT  14.904 0 14.922 0.038 ;
    END
  END b_d[144]
  PIN b_d[145]
    DIRECTION OUTPUT ;
    USE SIGNAL ;
    PORT
      LAYER M5 ;
        RECT  14.976 0 15 0.084 ;
    END
  END b_d[145]
  PIN b_d[146]
    DIRECTION OUTPUT ;
    USE SIGNAL ;
    PORT
      LAYER M3 ;
        RECT  15.084 0 15.102 0.038 ;
    END
  END b_d[146]
  PIN b_d[147]
    DIRECTION OUTPUT ;
    USE SIGNAL ;
    PORT
      LAYER M5 ;
        RECT  15.168 0 15.192 0.084 ;
    END
  END b_d[147]
  PIN b_d[148]
    DIRECTION OUTPUT ;
    USE SIGNAL ;
    PORT
      LAYER M3 ;
        RECT  15.3 0 15.318 0.038 ;
    END
  END b_d[148]
  PIN b_d[149]
    DIRECTION OUTPUT ;
    USE SIGNAL ;
    PORT
      LAYER M5 ;
        RECT  15.36 0 15.384 0.084 ;
    END
  END b_d[149]
  PIN b_d[14]
    DIRECTION OUTPUT ;
    USE SIGNAL ;
    PORT
      LAYER M3 ;
        RECT  2.16 0 2.178 0.038 ;
    END
  END b_d[14]
  PIN b_d[150]
    DIRECTION OUTPUT ;
    USE SIGNAL ;
    PORT
      LAYER M3 ;
        RECT  15.48 0 15.498 0.038 ;
    END
  END b_d[150]
  PIN b_d[151]
    DIRECTION OUTPUT ;
    USE SIGNAL ;
    PORT
      LAYER M5 ;
        RECT  15.552 0 15.576 0.084 ;
    END
  END b_d[151]
  PIN b_d[152]
    DIRECTION OUTPUT ;
    USE SIGNAL ;
    PORT
      LAYER M3 ;
        RECT  15.66 0 15.678 0.038 ;
    END
  END b_d[152]
  PIN b_d[153]
    DIRECTION OUTPUT ;
    USE SIGNAL ;
    PORT
      LAYER M5 ;
        RECT  15.792 0 15.816 0.084 ;
    END
  END b_d[153]
  PIN b_d[154]
    DIRECTION OUTPUT ;
    USE SIGNAL ;
    PORT
      LAYER M3 ;
        RECT  15.876 0 15.894 0.038 ;
    END
  END b_d[154]
  PIN b_d[155]
    DIRECTION OUTPUT ;
    USE SIGNAL ;
    PORT
      LAYER M5 ;
        RECT  15.984 0 16.008 0.084 ;
    END
  END b_d[155]
  PIN b_d[156]
    DIRECTION OUTPUT ;
    USE SIGNAL ;
    PORT
      LAYER M3 ;
        RECT  16.056 0 16.074 0.038 ;
    END
  END b_d[156]
  PIN b_d[157]
    DIRECTION OUTPUT ;
    USE SIGNAL ;
    PORT
      LAYER M5 ;
        RECT  16.176 0 16.2 0.084 ;
    END
  END b_d[157]
  PIN b_d[158]
    DIRECTION OUTPUT ;
    USE SIGNAL ;
    PORT
      LAYER M3 ;
        RECT  16.272 0 16.29 0.038 ;
    END
  END b_d[158]
  PIN b_d[159]
    DIRECTION OUTPUT ;
    USE SIGNAL ;
    PORT
      LAYER M5 ;
        RECT  16.368 0 16.392 0.084 ;
    END
  END b_d[159]
  PIN b_d[15]
    DIRECTION OUTPUT ;
    USE SIGNAL ;
    PORT
      LAYER M5 ;
        RECT  2.256 0 2.28 0.084 ;
    END
  END b_d[15]
  PIN b_d[160]
    DIRECTION OUTPUT ;
    USE SIGNAL ;
    PORT
      LAYER M3 ;
        RECT  16.452 0 16.47 0.038 ;
    END
  END b_d[160]
  PIN b_d[161]
    DIRECTION OUTPUT ;
    USE SIGNAL ;
    PORT
      LAYER M5 ;
        RECT  16.56 0 16.584 0.084 ;
    END
  END b_d[161]
  PIN b_d[162]
    DIRECTION OUTPUT ;
    USE SIGNAL ;
    PORT
      LAYER M3 ;
        RECT  16.668 0 16.686 0.038 ;
    END
  END b_d[162]
  PIN b_d[163]
    DIRECTION OUTPUT ;
    USE SIGNAL ;
    PORT
      LAYER M5 ;
        RECT  16.752 0 16.776 0.084 ;
    END
  END b_d[163]
  PIN b_d[164]
    DIRECTION OUTPUT ;
    USE SIGNAL ;
    PORT
      LAYER M3 ;
        RECT  16.848 0 16.866 0.038 ;
    END
  END b_d[164]
  PIN b_d[165]
    DIRECTION OUTPUT ;
    USE SIGNAL ;
    PORT
      LAYER M5 ;
        RECT  16.944 0 16.968 0.084 ;
    END
  END b_d[165]
  PIN b_d[166]
    DIRECTION OUTPUT ;
    USE SIGNAL ;
    PORT
      LAYER M3 ;
        RECT  17.064 0 17.082 0.038 ;
    END
  END b_d[166]
  PIN b_d[167]
    DIRECTION OUTPUT ;
    USE SIGNAL ;
    PORT
      LAYER M5 ;
        RECT  17.136 0 17.16 0.084 ;
    END
  END b_d[167]
  PIN b_d[168]
    DIRECTION OUTPUT ;
    USE SIGNAL ;
    PORT
      LAYER M3 ;
        RECT  17.244 0 17.262 0.038 ;
    END
  END b_d[168]
  PIN b_d[169]
    DIRECTION OUTPUT ;
    USE SIGNAL ;
    PORT
      LAYER M5 ;
        RECT  17.328 0 17.352 0.084 ;
    END
  END b_d[169]
  PIN b_d[16]
    DIRECTION OUTPUT ;
    USE SIGNAL ;
    PORT
      LAYER M3 ;
        RECT  2.34 0 2.358 0.038 ;
    END
  END b_d[16]
  PIN b_d[170]
    DIRECTION OUTPUT ;
    USE SIGNAL ;
    PORT
      LAYER M3 ;
        RECT  17.424 0 17.442 0.038 ;
    END
  END b_d[170]
  PIN b_d[171]
    DIRECTION OUTPUT ;
    USE SIGNAL ;
    PORT
      LAYER M5 ;
        RECT  17.52 0 17.544 0.084 ;
    END
  END b_d[171]
  PIN b_d[172]
    DIRECTION OUTPUT ;
    USE SIGNAL ;
    PORT
      LAYER M3 ;
        RECT  17.64 0 17.658 0.038 ;
    END
  END b_d[172]
  PIN b_d[173]
    DIRECTION OUTPUT ;
    USE SIGNAL ;
    PORT
      LAYER M5 ;
        RECT  17.712 0 17.736 0.084 ;
    END
  END b_d[173]
  PIN b_d[174]
    DIRECTION OUTPUT ;
    USE SIGNAL ;
    PORT
      LAYER M3 ;
        RECT  17.82 0 17.838 0.038 ;
    END
  END b_d[174]
  PIN b_d[175]
    DIRECTION OUTPUT ;
    USE SIGNAL ;
    PORT
      LAYER M5 ;
        RECT  17.904 0 17.928 0.084 ;
    END
  END b_d[175]
  PIN b_d[176]
    DIRECTION OUTPUT ;
    USE SIGNAL ;
    PORT
      LAYER M3 ;
        RECT  18.036 0 18.054 0.038 ;
    END
  END b_d[176]
  PIN b_d[177]
    DIRECTION OUTPUT ;
    USE SIGNAL ;
    PORT
      LAYER M5 ;
        RECT  18.144 0 18.168 0.084 ;
    END
  END b_d[177]
  PIN b_d[178]
    DIRECTION OUTPUT ;
    USE SIGNAL ;
    PORT
      LAYER M3 ;
        RECT  18.216 0 18.234 0.038 ;
    END
  END b_d[178]
  PIN b_d[179]
    DIRECTION OUTPUT ;
    USE SIGNAL ;
    PORT
      LAYER M5 ;
        RECT  18.336 0 18.36 0.084 ;
    END
  END b_d[179]
  PIN b_d[17]
    DIRECTION OUTPUT ;
    USE SIGNAL ;
    PORT
      LAYER M5 ;
        RECT  2.448 0 2.472 0.084 ;
    END
  END b_d[17]
  PIN b_d[180]
    DIRECTION OUTPUT ;
    USE SIGNAL ;
    PORT
      LAYER M3 ;
        RECT  18.432 0 18.45 0.038 ;
    END
  END b_d[180]
  PIN b_d[181]
    DIRECTION OUTPUT ;
    USE SIGNAL ;
    PORT
      LAYER M5 ;
        RECT  18.528 0 18.552 0.084 ;
    END
  END b_d[181]
  PIN b_d[182]
    DIRECTION OUTPUT ;
    USE SIGNAL ;
    PORT
      LAYER M3 ;
        RECT  18.612 0 18.63 0.038 ;
    END
  END b_d[182]
  PIN b_d[183]
    DIRECTION OUTPUT ;
    USE SIGNAL ;
    PORT
      LAYER M5 ;
        RECT  18.72 0 18.744 0.084 ;
    END
  END b_d[183]
  PIN b_d[184]
    DIRECTION OUTPUT ;
    USE SIGNAL ;
    PORT
      LAYER M3 ;
        RECT  18.828 0 18.846 0.038 ;
    END
  END b_d[184]
  PIN b_d[185]
    DIRECTION OUTPUT ;
    USE SIGNAL ;
    PORT
      LAYER M5 ;
        RECT  18.912 0 18.936 0.084 ;
    END
  END b_d[185]
  PIN b_d[186]
    DIRECTION OUTPUT ;
    USE SIGNAL ;
    PORT
      LAYER M3 ;
        RECT  19.008 0 19.026 0.038 ;
    END
  END b_d[186]
  PIN b_d[187]
    DIRECTION OUTPUT ;
    USE SIGNAL ;
    PORT
      LAYER M5 ;
        RECT  19.104 0 19.128 0.084 ;
    END
  END b_d[187]
  PIN b_d[188]
    DIRECTION OUTPUT ;
    USE SIGNAL ;
    PORT
      LAYER M3 ;
        RECT  19.188 0 19.206 0.038 ;
    END
  END b_d[188]
  PIN b_d[189]
    DIRECTION OUTPUT ;
    USE SIGNAL ;
    PORT
      LAYER M5 ;
        RECT  19.296 0 19.32 0.084 ;
    END
  END b_d[189]
  PIN b_d[18]
    DIRECTION OUTPUT ;
    USE SIGNAL ;
    PORT
      LAYER M3 ;
        RECT  2.52 0 2.538 0.038 ;
    END
  END b_d[18]
  PIN b_d[190]
    DIRECTION OUTPUT ;
    USE SIGNAL ;
    PORT
      LAYER M3 ;
        RECT  19.404 0 19.422 0.038 ;
    END
  END b_d[190]
  PIN b_d[191]
    DIRECTION OUTPUT ;
    USE SIGNAL ;
    PORT
      LAYER M5 ;
        RECT  19.488 0 19.512 0.084 ;
    END
  END b_d[191]
  PIN b_d[192]
    DIRECTION OUTPUT ;
    USE SIGNAL ;
    PORT
      LAYER M3 ;
        RECT  19.584 0 19.602 0.038 ;
    END
  END b_d[192]
  PIN b_d[193]
    DIRECTION OUTPUT ;
    USE SIGNAL ;
    PORT
      LAYER M5 ;
        RECT  19.68 0 19.704 0.084 ;
    END
  END b_d[193]
  PIN b_d[194]
    DIRECTION OUTPUT ;
    USE SIGNAL ;
    PORT
      LAYER M3 ;
        RECT  19.8 0 19.818 0.038 ;
    END
  END b_d[194]
  PIN b_d[195]
    DIRECTION OUTPUT ;
    USE SIGNAL ;
    PORT
      LAYER M5 ;
        RECT  19.872 0 19.896 0.084 ;
    END
  END b_d[195]
  PIN b_d[196]
    DIRECTION OUTPUT ;
    USE SIGNAL ;
    PORT
      LAYER M3 ;
        RECT  19.98 0 19.998 0.038 ;
    END
  END b_d[196]
  PIN b_d[197]
    DIRECTION OUTPUT ;
    USE SIGNAL ;
    PORT
      LAYER M5 ;
        RECT  20.064 0 20.088 0.084 ;
    END
  END b_d[197]
  PIN b_d[198]
    DIRECTION OUTPUT ;
    USE SIGNAL ;
    PORT
      LAYER M3 ;
        RECT  20.196 0 20.214 0.038 ;
    END
  END b_d[198]
  PIN b_d[199]
    DIRECTION OUTPUT ;
    USE SIGNAL ;
    PORT
      LAYER M5 ;
        RECT  20.304 0 20.328 0.084 ;
    END
  END b_d[199]
  PIN b_d[19]
    DIRECTION OUTPUT ;
    USE SIGNAL ;
    PORT
      LAYER M5 ;
        RECT  2.64 0 2.664 0.084 ;
    END
  END b_d[19]
  PIN b_d[1]
    DIRECTION OUTPUT ;
    USE SIGNAL ;
    PORT
      LAYER M5 ;
        RECT  0.864 0 0.888 0.084 ;
    END
  END b_d[1]
  PIN b_d[200]
    DIRECTION OUTPUT ;
    USE SIGNAL ;
    PORT
      LAYER M3 ;
        RECT  20.376 0 20.394 0.038 ;
    END
  END b_d[200]
  PIN b_d[201]
    DIRECTION OUTPUT ;
    USE SIGNAL ;
    PORT
      LAYER M5 ;
        RECT  20.496 0 20.52 0.084 ;
    END
  END b_d[201]
  PIN b_d[202]
    DIRECTION OUTPUT ;
    USE SIGNAL ;
    PORT
      LAYER M3 ;
        RECT  20.592 0 20.61 0.038 ;
    END
  END b_d[202]
  PIN b_d[203]
    DIRECTION OUTPUT ;
    USE SIGNAL ;
    PORT
      LAYER M5 ;
        RECT  20.688 0 20.712 0.084 ;
    END
  END b_d[203]
  PIN b_d[204]
    DIRECTION OUTPUT ;
    USE SIGNAL ;
    PORT
      LAYER M3 ;
        RECT  20.772 0 20.79 0.038 ;
    END
  END b_d[204]
  PIN b_d[205]
    DIRECTION OUTPUT ;
    USE SIGNAL ;
    PORT
      LAYER M5 ;
        RECT  20.88 0 20.904 0.084 ;
    END
  END b_d[205]
  PIN b_d[206]
    DIRECTION OUTPUT ;
    USE SIGNAL ;
    PORT
      LAYER M3 ;
        RECT  20.988 0 21.006 0.038 ;
    END
  END b_d[206]
  PIN b_d[207]
    DIRECTION OUTPUT ;
    USE SIGNAL ;
    PORT
      LAYER M5 ;
        RECT  21.072 0 21.096 0.084 ;
    END
  END b_d[207]
  PIN b_d[208]
    DIRECTION OUTPUT ;
    USE SIGNAL ;
    PORT
      LAYER M3 ;
        RECT  21.168 0 21.186 0.038 ;
    END
  END b_d[208]
  PIN b_d[209]
    DIRECTION OUTPUT ;
    USE SIGNAL ;
    PORT
      LAYER M5 ;
        RECT  21.264 0 21.288 0.084 ;
    END
  END b_d[209]
  PIN b_d[20]
    DIRECTION OUTPUT ;
    USE SIGNAL ;
    PORT
      LAYER M3 ;
        RECT  2.736 0 2.754 0.038 ;
    END
  END b_d[20]
  PIN b_d[210]
    DIRECTION OUTPUT ;
    USE SIGNAL ;
    PORT
      LAYER M3 ;
        RECT  21.348 0 21.366 0.038 ;
    END
  END b_d[210]
  PIN b_d[211]
    DIRECTION OUTPUT ;
    USE SIGNAL ;
    PORT
      LAYER M5 ;
        RECT  21.456 0 21.48 0.084 ;
    END
  END b_d[211]
  PIN b_d[212]
    DIRECTION OUTPUT ;
    USE SIGNAL ;
    PORT
      LAYER M3 ;
        RECT  21.564 0 21.582 0.038 ;
    END
  END b_d[212]
  PIN b_d[213]
    DIRECTION OUTPUT ;
    USE SIGNAL ;
    PORT
      LAYER M5 ;
        RECT  21.648 0 21.672 0.084 ;
    END
  END b_d[213]
  PIN b_d[214]
    DIRECTION OUTPUT ;
    USE SIGNAL ;
    PORT
      LAYER M3 ;
        RECT  21.744 0 21.762 0.038 ;
    END
  END b_d[214]
  PIN b_d[215]
    DIRECTION OUTPUT ;
    USE SIGNAL ;
    PORT
      LAYER M5 ;
        RECT  21.84 0 21.864 0.084 ;
    END
  END b_d[215]
  PIN b_d[216]
    DIRECTION OUTPUT ;
    USE SIGNAL ;
    PORT
      LAYER M3 ;
        RECT  21.96 0 21.978 0.038 ;
    END
  END b_d[216]
  PIN b_d[217]
    DIRECTION OUTPUT ;
    USE SIGNAL ;
    PORT
      LAYER M5 ;
        RECT  22.032 0 22.056 0.084 ;
    END
  END b_d[217]
  PIN b_d[218]
    DIRECTION OUTPUT ;
    USE SIGNAL ;
    PORT
      LAYER M3 ;
        RECT  22.14 0 22.158 0.038 ;
    END
  END b_d[218]
  PIN b_d[219]
    DIRECTION OUTPUT ;
    USE SIGNAL ;
    PORT
      LAYER M5 ;
        RECT  22.224 0 22.248 0.084 ;
    END
  END b_d[219]
  PIN b_d[21]
    DIRECTION OUTPUT ;
    USE SIGNAL ;
    PORT
      LAYER M5 ;
        RECT  2.832 0 2.856 0.084 ;
    END
  END b_d[21]
  PIN b_d[220]
    DIRECTION OUTPUT ;
    USE SIGNAL ;
    PORT
      LAYER M3 ;
        RECT  22.356 0 22.374 0.038 ;
    END
  END b_d[220]
  PIN b_d[221]
    DIRECTION OUTPUT ;
    USE SIGNAL ;
    PORT
      LAYER M5 ;
        RECT  22.416 0 22.44 0.084 ;
    END
  END b_d[221]
  PIN b_d[222]
    DIRECTION OUTPUT ;
    USE SIGNAL ;
    PORT
      LAYER M3 ;
        RECT  22.536 0 22.554 0.038 ;
    END
  END b_d[222]
  PIN b_d[223]
    DIRECTION OUTPUT ;
    USE SIGNAL ;
    PORT
      LAYER M5 ;
        RECT  22.656 0 22.68 0.084 ;
    END
  END b_d[223]
  PIN b_d[224]
    DIRECTION OUTPUT ;
    USE SIGNAL ;
    PORT
      LAYER M3 ;
        RECT  22.752 0 22.77 0.038 ;
    END
  END b_d[224]
  PIN b_d[225]
    DIRECTION OUTPUT ;
    USE SIGNAL ;
    PORT
      LAYER M5 ;
        RECT  22.848 0 22.872 0.084 ;
    END
  END b_d[225]
  PIN b_d[226]
    DIRECTION OUTPUT ;
    USE SIGNAL ;
    PORT
      LAYER M3 ;
        RECT  22.932 0 22.95 0.038 ;
    END
  END b_d[226]
  PIN b_d[227]
    DIRECTION OUTPUT ;
    USE SIGNAL ;
    PORT
      LAYER M5 ;
        RECT  23.04 0 23.064 0.084 ;
    END
  END b_d[227]
  PIN b_d[228]
    DIRECTION OUTPUT ;
    USE SIGNAL ;
    PORT
      LAYER M3 ;
        RECT  23.112 0 23.13 0.038 ;
    END
  END b_d[228]
  PIN b_d[229]
    DIRECTION OUTPUT ;
    USE SIGNAL ;
    PORT
      LAYER M5 ;
        RECT  23.232 0 23.256 0.084 ;
    END
  END b_d[229]
  PIN b_d[22]
    DIRECTION OUTPUT ;
    USE SIGNAL ;
    PORT
      LAYER M3 ;
        RECT  2.916 0 2.934 0.038 ;
    END
  END b_d[22]
  PIN b_d[230]
    DIRECTION OUTPUT ;
    USE SIGNAL ;
    PORT
      LAYER M3 ;
        RECT  23.328 0 23.346 0.038 ;
    END
  END b_d[230]
  PIN b_d[231]
    DIRECTION OUTPUT ;
    USE SIGNAL ;
    PORT
      LAYER M5 ;
        RECT  23.424 0 23.448 0.084 ;
    END
  END b_d[231]
  PIN b_d[232]
    DIRECTION OUTPUT ;
    USE SIGNAL ;
    PORT
      LAYER M3 ;
        RECT  23.508 0 23.526 0.038 ;
    END
  END b_d[232]
  PIN b_d[233]
    DIRECTION OUTPUT ;
    USE SIGNAL ;
    PORT
      LAYER M5 ;
        RECT  23.616 0 23.64 0.084 ;
    END
  END b_d[233]
  PIN b_d[234]
    DIRECTION OUTPUT ;
    USE SIGNAL ;
    PORT
      LAYER M3 ;
        RECT  23.724 0 23.742 0.038 ;
    END
  END b_d[234]
  PIN b_d[235]
    DIRECTION OUTPUT ;
    USE SIGNAL ;
    PORT
      LAYER M5 ;
        RECT  23.808 0 23.832 0.084 ;
    END
  END b_d[235]
  PIN b_d[236]
    DIRECTION OUTPUT ;
    USE SIGNAL ;
    PORT
      LAYER M3 ;
        RECT  23.904 0 23.922 0.038 ;
    END
  END b_d[236]
  PIN b_d[237]
    DIRECTION OUTPUT ;
    USE SIGNAL ;
    PORT
      LAYER M5 ;
        RECT  24 0 24.024 0.084 ;
    END
  END b_d[237]
  PIN b_d[238]
    DIRECTION OUTPUT ;
    USE SIGNAL ;
    PORT
      LAYER M3 ;
        RECT  24.12 0 24.138 0.038 ;
    END
  END b_d[238]
  PIN b_d[239]
    DIRECTION OUTPUT ;
    USE SIGNAL ;
    PORT
      LAYER M5 ;
        RECT  24.192 0 24.216 0.084 ;
    END
  END b_d[239]
  PIN b_d[23]
    DIRECTION OUTPUT ;
    USE SIGNAL ;
    PORT
      LAYER M5 ;
        RECT  3.024 0 3.048 0.084 ;
    END
  END b_d[23]
  PIN b_d[240]
    DIRECTION OUTPUT ;
    USE SIGNAL ;
    PORT
      LAYER M3 ;
        RECT  24.3 0 24.318 0.038 ;
    END
  END b_d[240]
  PIN b_d[241]
    DIRECTION OUTPUT ;
    USE SIGNAL ;
    PORT
      LAYER M5 ;
        RECT  24.384 0 24.408 0.084 ;
    END
  END b_d[241]
  PIN b_d[242]
    DIRECTION OUTPUT ;
    USE SIGNAL ;
    PORT
      LAYER M3 ;
        RECT  24.516 0 24.534 0.038 ;
    END
  END b_d[242]
  PIN b_d[243]
    DIRECTION OUTPUT ;
    USE SIGNAL ;
    PORT
      LAYER M5 ;
        RECT  24.576 0 24.6 0.084 ;
    END
  END b_d[243]
  PIN b_d[244]
    DIRECTION OUTPUT ;
    USE SIGNAL ;
    PORT
      LAYER M3 ;
        RECT  24.696 0 24.714 0.038 ;
    END
  END b_d[244]
  PIN b_d[245]
    DIRECTION OUTPUT ;
    USE SIGNAL ;
    PORT
      LAYER M5 ;
        RECT  24.768 0 24.792 0.084 ;
    END
  END b_d[245]
  PIN b_d[246]
    DIRECTION OUTPUT ;
    USE SIGNAL ;
    PORT
      LAYER M3 ;
        RECT  24.876 0 24.894 0.038 ;
    END
  END b_d[246]
  PIN b_d[247]
    DIRECTION OUTPUT ;
    USE SIGNAL ;
    PORT
      LAYER M5 ;
        RECT  25.008 0 25.032 0.084 ;
    END
  END b_d[247]
  PIN b_d[248]
    DIRECTION OUTPUT ;
    USE SIGNAL ;
    PORT
      LAYER M3 ;
        RECT  25.092 0 25.11 0.038 ;
    END
  END b_d[248]
  PIN b_d[249]
    DIRECTION OUTPUT ;
    USE SIGNAL ;
    PORT
      LAYER M5 ;
        RECT  25.2 0 25.224 0.084 ;
    END
  END b_d[249]
  PIN b_d[24]
    DIRECTION OUTPUT ;
    USE SIGNAL ;
    PORT
      LAYER M3 ;
        RECT  3.132 0 3.15 0.038 ;
    END
  END b_d[24]
  PIN b_d[250]
    DIRECTION OUTPUT ;
    USE SIGNAL ;
    PORT
      LAYER M3 ;
        RECT  25.272 0 25.29 0.038 ;
    END
  END b_d[250]
  PIN b_d[251]
    DIRECTION OUTPUT ;
    USE SIGNAL ;
    PORT
      LAYER M5 ;
        RECT  25.392 0 25.416 0.084 ;
    END
  END b_d[251]
  PIN b_d[252]
    DIRECTION OUTPUT ;
    USE SIGNAL ;
    PORT
      LAYER M3 ;
        RECT  25.488 0 25.506 0.038 ;
    END
  END b_d[252]
  PIN b_d[253]
    DIRECTION OUTPUT ;
    USE SIGNAL ;
    PORT
      LAYER M5 ;
        RECT  25.584 0 25.608 0.084 ;
    END
  END b_d[253]
  PIN b_d[254]
    DIRECTION OUTPUT ;
    USE SIGNAL ;
    PORT
      LAYER M3 ;
        RECT  25.668 0 25.686 0.038 ;
    END
  END b_d[254]
  PIN b_d[255]
    DIRECTION OUTPUT ;
    USE SIGNAL ;
    PORT
      LAYER M5 ;
        RECT  25.776 0 25.8 0.084 ;
    END
  END b_d[255]
  PIN b_d[256]
    DIRECTION OUTPUT ;
    USE SIGNAL ;
    PORT
      LAYER M3 ;
        RECT  25.884 0 25.902 0.038 ;
    END
  END b_d[256]
  PIN b_d[257]
    DIRECTION OUTPUT ;
    USE SIGNAL ;
    PORT
      LAYER M5 ;
        RECT  25.968 0 25.992 0.084 ;
    END
  END b_d[257]
  PIN b_d[258]
    DIRECTION OUTPUT ;
    USE SIGNAL ;
    PORT
      LAYER M3 ;
        RECT  26.064 0 26.082 0.038 ;
    END
  END b_d[258]
  PIN b_d[259]
    DIRECTION OUTPUT ;
    USE SIGNAL ;
    PORT
      LAYER M5 ;
        RECT  26.16 0 26.184 0.084 ;
    END
  END b_d[259]
  PIN b_d[25]
    DIRECTION OUTPUT ;
    USE SIGNAL ;
    PORT
      LAYER M5 ;
        RECT  3.216 0 3.24 0.084 ;
    END
  END b_d[25]
  PIN b_d[260]
    DIRECTION OUTPUT ;
    USE SIGNAL ;
    PORT
      LAYER M3 ;
        RECT  26.28 0 26.298 0.038 ;
    END
  END b_d[260]
  PIN b_d[261]
    DIRECTION OUTPUT ;
    USE SIGNAL ;
    PORT
      LAYER M5 ;
        RECT  26.352 0 26.376 0.084 ;
    END
  END b_d[261]
  PIN b_d[262]
    DIRECTION OUTPUT ;
    USE SIGNAL ;
    PORT
      LAYER M3 ;
        RECT  26.46 0 26.478 0.038 ;
    END
  END b_d[262]
  PIN b_d[263]
    DIRECTION OUTPUT ;
    USE SIGNAL ;
    PORT
      LAYER M5 ;
        RECT  26.544 0 26.568 0.084 ;
    END
  END b_d[263]
  PIN b_d[264]
    DIRECTION OUTPUT ;
    USE SIGNAL ;
    PORT
      LAYER M3 ;
        RECT  26.64 0 26.658 0.038 ;
    END
  END b_d[264]
  PIN b_d[265]
    DIRECTION OUTPUT ;
    USE SIGNAL ;
    PORT
      LAYER M5 ;
        RECT  26.736 0 26.76 0.084 ;
    END
  END b_d[265]
  PIN b_d[266]
    DIRECTION OUTPUT ;
    USE SIGNAL ;
    PORT
      LAYER M3 ;
        RECT  26.856 0 26.874 0.038 ;
    END
  END b_d[266]
  PIN b_d[267]
    DIRECTION OUTPUT ;
    USE SIGNAL ;
    PORT
      LAYER M5 ;
        RECT  26.928 0 26.952 0.084 ;
    END
  END b_d[267]
  PIN b_d[268]
    DIRECTION OUTPUT ;
    USE SIGNAL ;
    PORT
      LAYER M3 ;
        RECT  27.036 0 27.054 0.038 ;
    END
  END b_d[268]
  PIN b_d[269]
    DIRECTION OUTPUT ;
    USE SIGNAL ;
    PORT
      LAYER M5 ;
        RECT  27.168 0 27.192 0.084 ;
    END
  END b_d[269]
  PIN b_d[26]
    DIRECTION OUTPUT ;
    USE SIGNAL ;
    PORT
      LAYER M3 ;
        RECT  3.312 0 3.33 0.038 ;
    END
  END b_d[26]
  PIN b_d[270]
    DIRECTION OUTPUT ;
    USE SIGNAL ;
    PORT
      LAYER M3 ;
        RECT  27.252 0 27.27 0.038 ;
    END
  END b_d[270]
  PIN b_d[271]
    DIRECTION OUTPUT ;
    USE SIGNAL ;
    PORT
      LAYER M5 ;
        RECT  27.36 0 27.384 0.084 ;
    END
  END b_d[271]
  PIN b_d[272]
    DIRECTION OUTPUT ;
    USE SIGNAL ;
    PORT
      LAYER M3 ;
        RECT  27.432 0 27.45 0.038 ;
    END
  END b_d[272]
  PIN b_d[273]
    DIRECTION OUTPUT ;
    USE SIGNAL ;
    PORT
      LAYER M5 ;
        RECT  27.552 0 27.576 0.084 ;
    END
  END b_d[273]
  PIN b_d[274]
    DIRECTION OUTPUT ;
    USE SIGNAL ;
    PORT
      LAYER M3 ;
        RECT  27.648 0 27.666 0.038 ;
    END
  END b_d[274]
  PIN b_d[275]
    DIRECTION OUTPUT ;
    USE SIGNAL ;
    PORT
      LAYER M5 ;
        RECT  27.744 0 27.768 0.084 ;
    END
  END b_d[275]
  PIN b_d[276]
    DIRECTION OUTPUT ;
    USE SIGNAL ;
    PORT
      LAYER M3 ;
        RECT  27.828 0 27.846 0.038 ;
    END
  END b_d[276]
  PIN b_d[277]
    DIRECTION OUTPUT ;
    USE SIGNAL ;
    PORT
      LAYER M5 ;
        RECT  27.936 0 27.96 0.084 ;
    END
  END b_d[277]
  PIN b_d[278]
    DIRECTION OUTPUT ;
    USE SIGNAL ;
    PORT
      LAYER M3 ;
        RECT  28.044 0 28.062 0.038 ;
    END
  END b_d[278]
  PIN b_d[279]
    DIRECTION OUTPUT ;
    USE SIGNAL ;
    PORT
      LAYER M5 ;
        RECT  28.128 0 28.152 0.084 ;
    END
  END b_d[279]
  PIN b_d[27]
    DIRECTION OUTPUT ;
    USE SIGNAL ;
    PORT
      LAYER M5 ;
        RECT  3.408 0 3.432 0.084 ;
    END
  END b_d[27]
  PIN b_d[280]
    DIRECTION OUTPUT ;
    USE SIGNAL ;
    PORT
      LAYER M3 ;
        RECT  28.224 0 28.242 0.038 ;
    END
  END b_d[280]
  PIN b_d[281]
    DIRECTION OUTPUT ;
    USE SIGNAL ;
    PORT
      LAYER M5 ;
        RECT  28.32 0 28.344 0.084 ;
    END
  END b_d[281]
  PIN b_d[282]
    DIRECTION OUTPUT ;
    USE SIGNAL ;
    PORT
      LAYER M3 ;
        RECT  28.404 0 28.422 0.038 ;
    END
  END b_d[282]
  PIN b_d[283]
    DIRECTION OUTPUT ;
    USE SIGNAL ;
    PORT
      LAYER M5 ;
        RECT  28.512 0 28.536 0.084 ;
    END
  END b_d[283]
  PIN b_d[284]
    DIRECTION OUTPUT ;
    USE SIGNAL ;
    PORT
      LAYER M3 ;
        RECT  28.62 0 28.638 0.038 ;
    END
  END b_d[284]
  PIN b_d[285]
    DIRECTION OUTPUT ;
    USE SIGNAL ;
    PORT
      LAYER M5 ;
        RECT  28.704 0 28.728 0.084 ;
    END
  END b_d[285]
  PIN b_d[286]
    DIRECTION OUTPUT ;
    USE SIGNAL ;
    PORT
      LAYER M3 ;
        RECT  28.8 0 28.818 0.038 ;
    END
  END b_d[286]
  PIN b_d[287]
    DIRECTION OUTPUT ;
    USE SIGNAL ;
    PORT
      LAYER M5 ;
        RECT  28.896 0 28.92 0.084 ;
    END
  END b_d[287]
  PIN b_d[288]
    DIRECTION OUTPUT ;
    USE SIGNAL ;
    PORT
      LAYER M3 ;
        RECT  29.016 0 29.034 0.038 ;
    END
  END b_d[288]
  PIN b_d[289]
    DIRECTION OUTPUT ;
    USE SIGNAL ;
    PORT
      LAYER M5 ;
        RECT  29.088 0 29.112 0.084 ;
    END
  END b_d[289]
  PIN b_d[28]
    DIRECTION OUTPUT ;
    USE SIGNAL ;
    PORT
      LAYER M3 ;
        RECT  3.528 0 3.546 0.038 ;
    END
  END b_d[28]
  PIN b_d[290]
    DIRECTION OUTPUT ;
    USE SIGNAL ;
    PORT
      LAYER M3 ;
        RECT  29.196 0 29.214 0.038 ;
    END
  END b_d[290]
  PIN b_d[291]
    DIRECTION OUTPUT ;
    USE SIGNAL ;
    PORT
      LAYER M5 ;
        RECT  29.28 0 29.304 0.084 ;
    END
  END b_d[291]
  PIN b_d[292]
    DIRECTION OUTPUT ;
    USE SIGNAL ;
    PORT
      LAYER M3 ;
        RECT  29.412 0 29.43 0.038 ;
    END
  END b_d[292]
  PIN b_d[293]
    DIRECTION OUTPUT ;
    USE SIGNAL ;
    PORT
      LAYER M5 ;
        RECT  29.52 0 29.544 0.084 ;
    END
  END b_d[293]
  PIN b_d[294]
    DIRECTION OUTPUT ;
    USE SIGNAL ;
    PORT
      LAYER M3 ;
        RECT  29.592 0 29.61 0.038 ;
    END
  END b_d[294]
  PIN b_d[295]
    DIRECTION OUTPUT ;
    USE SIGNAL ;
    PORT
      LAYER M5 ;
        RECT  29.712 0 29.736 0.084 ;
    END
  END b_d[295]
  PIN b_d[296]
    DIRECTION OUTPUT ;
    USE SIGNAL ;
    PORT
      LAYER M3 ;
        RECT  29.808 0 29.826 0.038 ;
    END
  END b_d[296]
  PIN b_d[297]
    DIRECTION OUTPUT ;
    USE SIGNAL ;
    PORT
      LAYER M5 ;
        RECT  29.904 0 29.928 0.084 ;
    END
  END b_d[297]
  PIN b_d[298]
    DIRECTION OUTPUT ;
    USE SIGNAL ;
    PORT
      LAYER M3 ;
        RECT  29.988 0 30.006 0.038 ;
    END
  END b_d[298]
  PIN b_d[299]
    DIRECTION OUTPUT ;
    USE SIGNAL ;
    PORT
      LAYER M5 ;
        RECT  30.096 0 30.12 0.084 ;
    END
  END b_d[299]
  PIN b_d[29]
    DIRECTION OUTPUT ;
    USE SIGNAL ;
    PORT
      LAYER M5 ;
        RECT  3.6 0 3.624 0.084 ;
    END
  END b_d[29]
  PIN b_d[2]
    DIRECTION OUTPUT ;
    USE SIGNAL ;
    PORT
      LAYER M3 ;
        RECT  0.972 0 0.99 0.038 ;
    END
  END b_d[2]
  PIN b_d[300]
    DIRECTION OUTPUT ;
    USE SIGNAL ;
    PORT
      LAYER M3 ;
        RECT  30.204 0 30.222 0.038 ;
    END
  END b_d[300]
  PIN b_d[301]
    DIRECTION OUTPUT ;
    USE SIGNAL ;
    PORT
      LAYER M5 ;
        RECT  30.288 0 30.312 0.084 ;
    END
  END b_d[301]
  PIN b_d[302]
    DIRECTION OUTPUT ;
    USE SIGNAL ;
    PORT
      LAYER M3 ;
        RECT  30.384 0 30.402 0.038 ;
    END
  END b_d[302]
  PIN b_d[303]
    DIRECTION OUTPUT ;
    USE SIGNAL ;
    PORT
      LAYER M5 ;
        RECT  30.48 0 30.504 0.084 ;
    END
  END b_d[303]
  PIN b_d[304]
    DIRECTION OUTPUT ;
    USE SIGNAL ;
    PORT
      LAYER M3 ;
        RECT  30.564 0 30.582 0.038 ;
    END
  END b_d[304]
  PIN b_d[305]
    DIRECTION OUTPUT ;
    USE SIGNAL ;
    PORT
      LAYER M5 ;
        RECT  30.672 0 30.696 0.084 ;
    END
  END b_d[305]
  PIN b_d[306]
    DIRECTION OUTPUT ;
    USE SIGNAL ;
    PORT
      LAYER M3 ;
        RECT  30.78 0 30.798 0.038 ;
    END
  END b_d[306]
  PIN b_d[307]
    DIRECTION OUTPUT ;
    USE SIGNAL ;
    PORT
      LAYER M5 ;
        RECT  30.864 0 30.888 0.084 ;
    END
  END b_d[307]
  PIN b_d[308]
    DIRECTION OUTPUT ;
    USE SIGNAL ;
    PORT
      LAYER M3 ;
        RECT  30.96 0 30.978 0.038 ;
    END
  END b_d[308]
  PIN b_d[309]
    DIRECTION OUTPUT ;
    USE SIGNAL ;
    PORT
      LAYER M5 ;
        RECT  31.056 0 31.08 0.084 ;
    END
  END b_d[309]
  PIN b_d[30]
    DIRECTION OUTPUT ;
    USE SIGNAL ;
    PORT
      LAYER M3 ;
        RECT  3.708 0 3.726 0.038 ;
    END
  END b_d[30]
  PIN b_d[310]
    DIRECTION OUTPUT ;
    USE SIGNAL ;
    PORT
      LAYER M3 ;
        RECT  31.176 0 31.194 0.038 ;
    END
  END b_d[310]
  PIN b_d[311]
    DIRECTION OUTPUT ;
    USE SIGNAL ;
    PORT
      LAYER M5 ;
        RECT  31.248 0 31.272 0.084 ;
    END
  END b_d[311]
  PIN b_d[312]
    DIRECTION OUTPUT ;
    USE SIGNAL ;
    PORT
      LAYER M3 ;
        RECT  31.356 0 31.374 0.038 ;
    END
  END b_d[312]
  PIN b_d[313]
    DIRECTION OUTPUT ;
    USE SIGNAL ;
    PORT
      LAYER M5 ;
        RECT  31.44 0 31.464 0.084 ;
    END
  END b_d[313]
  PIN b_d[314]
    DIRECTION OUTPUT ;
    USE SIGNAL ;
    PORT
      LAYER M3 ;
        RECT  31.572 0 31.59 0.038 ;
    END
  END b_d[314]
  PIN b_d[315]
    DIRECTION OUTPUT ;
    USE SIGNAL ;
    PORT
      LAYER M5 ;
        RECT  31.632 0 31.656 0.084 ;
    END
  END b_d[315]
  PIN b_d[316]
    DIRECTION OUTPUT ;
    USE SIGNAL ;
    PORT
      LAYER M3 ;
        RECT  31.752 0 31.77 0.038 ;
    END
  END b_d[316]
  PIN b_d[317]
    DIRECTION OUTPUT ;
    USE SIGNAL ;
    PORT
      LAYER M5 ;
        RECT  31.872 0 31.896 0.084 ;
    END
  END b_d[317]
  PIN b_d[318]
    DIRECTION OUTPUT ;
    USE SIGNAL ;
    PORT
      LAYER M3 ;
        RECT  31.968 0 31.986 0.038 ;
    END
  END b_d[318]
  PIN b_d[319]
    DIRECTION OUTPUT ;
    USE SIGNAL ;
    PORT
      LAYER M5 ;
        RECT  32.064 0 32.088 0.084 ;
    END
  END b_d[319]
  PIN b_d[31]
    DIRECTION OUTPUT ;
    USE SIGNAL ;
    PORT
      LAYER M5 ;
        RECT  3.792 0 3.816 0.084 ;
    END
  END b_d[31]
  PIN b_d[320]
    DIRECTION OUTPUT ;
    USE SIGNAL ;
    PORT
      LAYER M3 ;
        RECT  32.148 0 32.166 0.038 ;
    END
  END b_d[320]
  PIN b_d[321]
    DIRECTION OUTPUT ;
    USE SIGNAL ;
    PORT
      LAYER M5 ;
        RECT  32.256 0 32.28 0.084 ;
    END
  END b_d[321]
  PIN b_d[322]
    DIRECTION OUTPUT ;
    USE SIGNAL ;
    PORT
      LAYER M3 ;
        RECT  32.328 0 32.346 0.038 ;
    END
  END b_d[322]
  PIN b_d[323]
    DIRECTION OUTPUT ;
    USE SIGNAL ;
    PORT
      LAYER M5 ;
        RECT  32.448 0 32.472 0.084 ;
    END
  END b_d[323]
  PIN b_d[324]
    DIRECTION OUTPUT ;
    USE SIGNAL ;
    PORT
      LAYER M3 ;
        RECT  32.544 0 32.562 0.038 ;
    END
  END b_d[324]
  PIN b_d[325]
    DIRECTION OUTPUT ;
    USE SIGNAL ;
    PORT
      LAYER M5 ;
        RECT  32.64 0 32.664 0.084 ;
    END
  END b_d[325]
  PIN b_d[326]
    DIRECTION OUTPUT ;
    USE SIGNAL ;
    PORT
      LAYER M3 ;
        RECT  32.724 0 32.742 0.038 ;
    END
  END b_d[326]
  PIN b_d[327]
    DIRECTION OUTPUT ;
    USE SIGNAL ;
    PORT
      LAYER M5 ;
        RECT  32.832 0 32.856 0.084 ;
    END
  END b_d[327]
  PIN b_d[328]
    DIRECTION OUTPUT ;
    USE SIGNAL ;
    PORT
      LAYER M3 ;
        RECT  32.94 0 32.958 0.038 ;
    END
  END b_d[328]
  PIN b_d[329]
    DIRECTION OUTPUT ;
    USE SIGNAL ;
    PORT
      LAYER M5 ;
        RECT  33.024 0 33.048 0.084 ;
    END
  END b_d[329]
  PIN b_d[32]
    DIRECTION OUTPUT ;
    USE SIGNAL ;
    PORT
      LAYER M3 ;
        RECT  3.924 0 3.942 0.038 ;
    END
  END b_d[32]
  PIN b_d[330]
    DIRECTION OUTPUT ;
    USE SIGNAL ;
    PORT
      LAYER M3 ;
        RECT  33.12 0 33.138 0.038 ;
    END
  END b_d[330]
  PIN b_d[331]
    DIRECTION OUTPUT ;
    USE SIGNAL ;
    PORT
      LAYER M5 ;
        RECT  33.216 0 33.24 0.084 ;
    END
  END b_d[331]
  PIN b_d[332]
    DIRECTION OUTPUT ;
    USE SIGNAL ;
    PORT
      LAYER M3 ;
        RECT  33.336 0 33.354 0.038 ;
    END
  END b_d[332]
  PIN b_d[333]
    DIRECTION OUTPUT ;
    USE SIGNAL ;
    PORT
      LAYER M5 ;
        RECT  33.408 0 33.432 0.084 ;
    END
  END b_d[333]
  PIN b_d[334]
    DIRECTION OUTPUT ;
    USE SIGNAL ;
    PORT
      LAYER M3 ;
        RECT  33.516 0 33.534 0.038 ;
    END
  END b_d[334]
  PIN b_d[335]
    DIRECTION OUTPUT ;
    USE SIGNAL ;
    PORT
      LAYER M5 ;
        RECT  33.6 0 33.624 0.084 ;
    END
  END b_d[335]
  PIN b_d[336]
    DIRECTION OUTPUT ;
    USE SIGNAL ;
    PORT
      LAYER M3 ;
        RECT  33.732 0 33.75 0.038 ;
    END
  END b_d[336]
  PIN b_d[337]
    DIRECTION OUTPUT ;
    USE SIGNAL ;
    PORT
      LAYER M5 ;
        RECT  33.792 0 33.816 0.084 ;
    END
  END b_d[337]
  PIN b_d[338]
    DIRECTION OUTPUT ;
    USE SIGNAL ;
    PORT
      LAYER M3 ;
        RECT  33.912 0 33.93 0.038 ;
    END
  END b_d[338]
  PIN b_d[339]
    DIRECTION OUTPUT ;
    USE SIGNAL ;
    PORT
      LAYER M5 ;
        RECT  33.984 0 34.008 0.084 ;
    END
  END b_d[339]
  PIN b_d[33]
    DIRECTION OUTPUT ;
    USE SIGNAL ;
    PORT
      LAYER M5 ;
        RECT  3.984 0 4.008 0.084 ;
    END
  END b_d[33]
  PIN b_d[340]
    DIRECTION OUTPUT ;
    USE SIGNAL ;
    PORT
      LAYER M3 ;
        RECT  34.092 0 34.11 0.038 ;
    END
  END b_d[340]
  PIN b_d[341]
    DIRECTION OUTPUT ;
    USE SIGNAL ;
    PORT
      LAYER M5 ;
        RECT  34.224 0 34.248 0.084 ;
    END
  END b_d[341]
  PIN b_d[342]
    DIRECTION OUTPUT ;
    USE SIGNAL ;
    PORT
      LAYER M3 ;
        RECT  34.308 0 34.326 0.038 ;
    END
  END b_d[342]
  PIN b_d[343]
    DIRECTION OUTPUT ;
    USE SIGNAL ;
    PORT
      LAYER M5 ;
        RECT  34.416 0 34.44 0.084 ;
    END
  END b_d[343]
  PIN b_d[344]
    DIRECTION OUTPUT ;
    USE SIGNAL ;
    PORT
      LAYER M3 ;
        RECT  34.488 0 34.506 0.038 ;
    END
  END b_d[344]
  PIN b_d[345]
    DIRECTION OUTPUT ;
    USE SIGNAL ;
    PORT
      LAYER M5 ;
        RECT  34.608 0 34.632 0.084 ;
    END
  END b_d[345]
  PIN b_d[346]
    DIRECTION OUTPUT ;
    USE SIGNAL ;
    PORT
      LAYER M3 ;
        RECT  34.704 0 34.722 0.038 ;
    END
  END b_d[346]
  PIN b_d[347]
    DIRECTION OUTPUT ;
    USE SIGNAL ;
    PORT
      LAYER M5 ;
        RECT  34.8 0 34.824 0.084 ;
    END
  END b_d[347]
  PIN b_d[348]
    DIRECTION OUTPUT ;
    USE SIGNAL ;
    PORT
      LAYER M3 ;
        RECT  34.884 0 34.902 0.038 ;
    END
  END b_d[348]
  PIN b_d[349]
    DIRECTION OUTPUT ;
    USE SIGNAL ;
    PORT
      LAYER M5 ;
        RECT  34.992 0 35.016 0.084 ;
    END
  END b_d[349]
  PIN b_d[34]
    DIRECTION OUTPUT ;
    USE SIGNAL ;
    PORT
      LAYER M3 ;
        RECT  4.104 0 4.122 0.038 ;
    END
  END b_d[34]
  PIN b_d[350]
    DIRECTION OUTPUT ;
    USE SIGNAL ;
    PORT
      LAYER M3 ;
        RECT  35.1 0 35.118 0.038 ;
    END
  END b_d[350]
  PIN b_d[351]
    DIRECTION OUTPUT ;
    USE SIGNAL ;
    PORT
      LAYER M5 ;
        RECT  35.184 0 35.208 0.084 ;
    END
  END b_d[351]
  PIN b_d[352]
    DIRECTION OUTPUT ;
    USE SIGNAL ;
    PORT
      LAYER M3 ;
        RECT  35.28 0 35.298 0.038 ;
    END
  END b_d[352]
  PIN b_d[353]
    DIRECTION OUTPUT ;
    USE SIGNAL ;
    PORT
      LAYER M5 ;
        RECT  35.376 0 35.4 0.084 ;
    END
  END b_d[353]
  PIN b_d[354]
    DIRECTION OUTPUT ;
    USE SIGNAL ;
    PORT
      LAYER M3 ;
        RECT  35.496 0 35.514 0.038 ;
    END
  END b_d[354]
  PIN b_d[355]
    DIRECTION OUTPUT ;
    USE SIGNAL ;
    PORT
      LAYER M5 ;
        RECT  35.568 0 35.592 0.084 ;
    END
  END b_d[355]
  PIN b_d[356]
    DIRECTION OUTPUT ;
    USE SIGNAL ;
    PORT
      LAYER M3 ;
        RECT  35.676 0 35.694 0.038 ;
    END
  END b_d[356]
  PIN b_d[357]
    DIRECTION OUTPUT ;
    USE SIGNAL ;
    PORT
      LAYER M5 ;
        RECT  35.76 0 35.784 0.084 ;
    END
  END b_d[357]
  PIN b_d[358]
    DIRECTION OUTPUT ;
    USE SIGNAL ;
    PORT
      LAYER M3 ;
        RECT  35.856 0 35.874 0.038 ;
    END
  END b_d[358]
  PIN b_d[359]
    DIRECTION OUTPUT ;
    USE SIGNAL ;
    PORT
      LAYER M5 ;
        RECT  35.952 0 35.976 0.084 ;
    END
  END b_d[359]
  PIN b_d[35]
    DIRECTION OUTPUT ;
    USE SIGNAL ;
    PORT
      LAYER M5 ;
        RECT  4.224 0 4.248 0.084 ;
    END
  END b_d[35]
  PIN b_d[360]
    DIRECTION OUTPUT ;
    USE SIGNAL ;
    PORT
      LAYER M3 ;
        RECT  36.072 0 36.09 0.038 ;
    END
  END b_d[360]
  PIN b_d[361]
    DIRECTION OUTPUT ;
    USE SIGNAL ;
    PORT
      LAYER M5 ;
        RECT  36.144 0 36.168 0.084 ;
    END
  END b_d[361]
  PIN b_d[362]
    DIRECTION OUTPUT ;
    USE SIGNAL ;
    PORT
      LAYER M3 ;
        RECT  36.252 0 36.27 0.038 ;
    END
  END b_d[362]
  PIN b_d[363]
    DIRECTION OUTPUT ;
    USE SIGNAL ;
    PORT
      LAYER M5 ;
        RECT  36.384 0 36.408 0.084 ;
    END
  END b_d[363]
  PIN b_d[364]
    DIRECTION OUTPUT ;
    USE SIGNAL ;
    PORT
      LAYER M3 ;
        RECT  36.468 0 36.486 0.038 ;
    END
  END b_d[364]
  PIN b_d[365]
    DIRECTION OUTPUT ;
    USE SIGNAL ;
    PORT
      LAYER M5 ;
        RECT  36.576 0 36.6 0.084 ;
    END
  END b_d[365]
  PIN b_d[366]
    DIRECTION OUTPUT ;
    USE SIGNAL ;
    PORT
      LAYER M3 ;
        RECT  36.648 0 36.666 0.038 ;
    END
  END b_d[366]
  PIN b_d[367]
    DIRECTION OUTPUT ;
    USE SIGNAL ;
    PORT
      LAYER M5 ;
        RECT  36.768 0 36.792 0.084 ;
    END
  END b_d[367]
  PIN b_d[368]
    DIRECTION OUTPUT ;
    USE SIGNAL ;
    PORT
      LAYER M3 ;
        RECT  36.864 0 36.882 0.038 ;
    END
  END b_d[368]
  PIN b_d[369]
    DIRECTION OUTPUT ;
    USE SIGNAL ;
    PORT
      LAYER M5 ;
        RECT  36.96 0 36.984 0.084 ;
    END
  END b_d[369]
  PIN b_d[36]
    DIRECTION OUTPUT ;
    USE SIGNAL ;
    PORT
      LAYER M3 ;
        RECT  4.32 0 4.338 0.038 ;
    END
  END b_d[36]
  PIN b_d[370]
    DIRECTION OUTPUT ;
    USE SIGNAL ;
    PORT
      LAYER M3 ;
        RECT  37.044 0 37.062 0.038 ;
    END
  END b_d[370]
  PIN b_d[371]
    DIRECTION OUTPUT ;
    USE SIGNAL ;
    PORT
      LAYER M5 ;
        RECT  37.152 0 37.176 0.084 ;
    END
  END b_d[371]
  PIN b_d[372]
    DIRECTION OUTPUT ;
    USE SIGNAL ;
    PORT
      LAYER M3 ;
        RECT  37.26 0 37.278 0.038 ;
    END
  END b_d[372]
  PIN b_d[373]
    DIRECTION OUTPUT ;
    USE SIGNAL ;
    PORT
      LAYER M5 ;
        RECT  37.344 0 37.368 0.084 ;
    END
  END b_d[373]
  PIN b_d[374]
    DIRECTION OUTPUT ;
    USE SIGNAL ;
    PORT
      LAYER M3 ;
        RECT  37.44 0 37.458 0.038 ;
    END
  END b_d[374]
  PIN b_d[375]
    DIRECTION OUTPUT ;
    USE SIGNAL ;
    PORT
      LAYER M5 ;
        RECT  37.536 0 37.56 0.084 ;
    END
  END b_d[375]
  PIN b_d[376]
    DIRECTION OUTPUT ;
    USE SIGNAL ;
    PORT
      LAYER M3 ;
        RECT  37.656 0 37.674 0.038 ;
    END
  END b_d[376]
  PIN b_d[377]
    DIRECTION OUTPUT ;
    USE SIGNAL ;
    PORT
      LAYER M5 ;
        RECT  37.728 0 37.752 0.084 ;
    END
  END b_d[377]
  PIN b_d[378]
    DIRECTION OUTPUT ;
    USE SIGNAL ;
    PORT
      LAYER M3 ;
        RECT  37.836 0 37.854 0.038 ;
    END
  END b_d[378]
  PIN b_d[379]
    DIRECTION OUTPUT ;
    USE SIGNAL ;
    PORT
      LAYER M5 ;
        RECT  37.92 0 37.944 0.084 ;
    END
  END b_d[379]
  PIN b_d[37]
    DIRECTION OUTPUT ;
    USE SIGNAL ;
    PORT
      LAYER M5 ;
        RECT  4.416 0 4.44 0.084 ;
    END
  END b_d[37]
  PIN b_d[380]
    DIRECTION OUTPUT ;
    USE SIGNAL ;
    PORT
      LAYER M3 ;
        RECT  38.016 0 38.034 0.038 ;
    END
  END b_d[380]
  PIN b_d[381]
    DIRECTION OUTPUT ;
    USE SIGNAL ;
    PORT
      LAYER M5 ;
        RECT  38.112 0 38.136 0.084 ;
    END
  END b_d[381]
  PIN b_d[382]
    DIRECTION OUTPUT ;
    USE SIGNAL ;
    PORT
      LAYER M3 ;
        RECT  38.232 0 38.25 0.038 ;
    END
  END b_d[382]
  PIN b_d[383]
    DIRECTION OUTPUT ;
    USE SIGNAL ;
    PORT
      LAYER M5 ;
        RECT  38.304 0 38.328 0.084 ;
    END
  END b_d[383]
  PIN b_d[384]
    DIRECTION OUTPUT ;
    USE SIGNAL ;
    PORT
      LAYER M3 ;
        RECT  38.412 0 38.43 0.038 ;
    END
  END b_d[384]
  PIN b_d[385]
    DIRECTION OUTPUT ;
    USE SIGNAL ;
    PORT
      LAYER M5 ;
        RECT  38.496 0 38.52 0.084 ;
    END
  END b_d[385]
  PIN b_d[386]
    DIRECTION OUTPUT ;
    USE SIGNAL ;
    PORT
      LAYER M3 ;
        RECT  38.628 0 38.646 0.038 ;
    END
  END b_d[386]
  PIN b_d[387]
    DIRECTION OUTPUT ;
    USE SIGNAL ;
    PORT
      LAYER M5 ;
        RECT  38.736 0 38.76 0.084 ;
    END
  END b_d[387]
  PIN b_d[388]
    DIRECTION OUTPUT ;
    USE SIGNAL ;
    PORT
      LAYER M3 ;
        RECT  38.808 0 38.826 0.038 ;
    END
  END b_d[388]
  PIN b_d[389]
    DIRECTION OUTPUT ;
    USE SIGNAL ;
    PORT
      LAYER M5 ;
        RECT  38.928 0 38.952 0.084 ;
    END
  END b_d[389]
  PIN b_d[38]
    DIRECTION OUTPUT ;
    USE SIGNAL ;
    PORT
      LAYER M3 ;
        RECT  4.5 0 4.518 0.038 ;
    END
  END b_d[38]
  PIN b_d[390]
    DIRECTION OUTPUT ;
    USE SIGNAL ;
    PORT
      LAYER M3 ;
        RECT  39.024 0 39.042 0.038 ;
    END
  END b_d[390]
  PIN b_d[391]
    DIRECTION OUTPUT ;
    USE SIGNAL ;
    PORT
      LAYER M5 ;
        RECT  39.12 0 39.144 0.084 ;
    END
  END b_d[391]
  PIN b_d[392]
    DIRECTION OUTPUT ;
    USE SIGNAL ;
    PORT
      LAYER M3 ;
        RECT  39.204 0 39.222 0.038 ;
    END
  END b_d[392]
  PIN b_d[393]
    DIRECTION OUTPUT ;
    USE SIGNAL ;
    PORT
      LAYER M5 ;
        RECT  39.312 0 39.336 0.084 ;
    END
  END b_d[393]
  PIN b_d[394]
    DIRECTION OUTPUT ;
    USE SIGNAL ;
    PORT
      LAYER M3 ;
        RECT  39.42 0 39.438 0.038 ;
    END
  END b_d[394]
  PIN b_d[395]
    DIRECTION OUTPUT ;
    USE SIGNAL ;
    PORT
      LAYER M5 ;
        RECT  39.504 0 39.528 0.084 ;
    END
  END b_d[395]
  PIN b_d[396]
    DIRECTION OUTPUT ;
    USE SIGNAL ;
    PORT
      LAYER M3 ;
        RECT  39.6 0 39.618 0.038 ;
    END
  END b_d[396]
  PIN b_d[397]
    DIRECTION OUTPUT ;
    USE SIGNAL ;
    PORT
      LAYER M5 ;
        RECT  39.696 0 39.72 0.084 ;
    END
  END b_d[397]
  PIN b_d[398]
    DIRECTION OUTPUT ;
    USE SIGNAL ;
    PORT
      LAYER M3 ;
        RECT  39.78 0 39.798 0.038 ;
    END
  END b_d[398]
  PIN b_d[399]
    DIRECTION OUTPUT ;
    USE SIGNAL ;
    PORT
      LAYER M5 ;
        RECT  39.888 0 39.912 0.084 ;
    END
  END b_d[399]
  PIN b_d[39]
    DIRECTION OUTPUT ;
    USE SIGNAL ;
    PORT
      LAYER M5 ;
        RECT  4.608 0 4.632 0.084 ;
    END
  END b_d[39]
  PIN b_d[3]
    DIRECTION OUTPUT ;
    USE SIGNAL ;
    PORT
      LAYER M5 ;
        RECT  1.056 0 1.08 0.084 ;
    END
  END b_d[3]
  PIN b_d[400]
    DIRECTION OUTPUT ;
    USE SIGNAL ;
    PORT
      LAYER M3 ;
        RECT  39.996 0 40.014 0.038 ;
    END
  END b_d[400]
  PIN b_d[401]
    DIRECTION OUTPUT ;
    USE SIGNAL ;
    PORT
      LAYER M5 ;
        RECT  40.08 0 40.104 0.084 ;
    END
  END b_d[401]
  PIN b_d[402]
    DIRECTION OUTPUT ;
    USE SIGNAL ;
    PORT
      LAYER M3 ;
        RECT  40.176 0 40.194 0.038 ;
    END
  END b_d[402]
  PIN b_d[403]
    DIRECTION OUTPUT ;
    USE SIGNAL ;
    PORT
      LAYER M5 ;
        RECT  40.272 0 40.296 0.084 ;
    END
  END b_d[403]
  PIN b_d[404]
    DIRECTION OUTPUT ;
    USE SIGNAL ;
    PORT
      LAYER M3 ;
        RECT  40.392 0 40.41 0.038 ;
    END
  END b_d[404]
  PIN b_d[405]
    DIRECTION OUTPUT ;
    USE SIGNAL ;
    PORT
      LAYER M5 ;
        RECT  40.464 0 40.488 0.084 ;
    END
  END b_d[405]
  PIN b_d[406]
    DIRECTION OUTPUT ;
    USE SIGNAL ;
    PORT
      LAYER M3 ;
        RECT  40.572 0 40.59 0.038 ;
    END
  END b_d[406]
  PIN b_d[407]
    DIRECTION OUTPUT ;
    USE SIGNAL ;
    PORT
      LAYER M5 ;
        RECT  40.656 0 40.68 0.084 ;
    END
  END b_d[407]
  PIN b_d[408]
    DIRECTION OUTPUT ;
    USE SIGNAL ;
    PORT
      LAYER M3 ;
        RECT  40.788 0 40.806 0.038 ;
    END
  END b_d[408]
  PIN b_d[409]
    DIRECTION OUTPUT ;
    USE SIGNAL ;
    PORT
      LAYER M5 ;
        RECT  40.848 0 40.872 0.084 ;
    END
  END b_d[409]
  PIN b_d[40]
    DIRECTION OUTPUT ;
    USE SIGNAL ;
    PORT
      LAYER M3 ;
        RECT  4.68 0 4.698 0.038 ;
    END
  END b_d[40]
  PIN b_d[410]
    DIRECTION OUTPUT ;
    USE SIGNAL ;
    PORT
      LAYER M3 ;
        RECT  40.968 0 40.986 0.038 ;
    END
  END b_d[410]
  PIN b_d[411]
    DIRECTION OUTPUT ;
    USE SIGNAL ;
    PORT
      LAYER M5 ;
        RECT  41.088 0 41.112 0.084 ;
    END
  END b_d[411]
  PIN b_d[412]
    DIRECTION OUTPUT ;
    USE SIGNAL ;
    PORT
      LAYER M3 ;
        RECT  41.184 0 41.202 0.038 ;
    END
  END b_d[412]
  PIN b_d[413]
    DIRECTION OUTPUT ;
    USE SIGNAL ;
    PORT
      LAYER M5 ;
        RECT  41.28 0 41.304 0.084 ;
    END
  END b_d[413]
  PIN b_d[414]
    DIRECTION OUTPUT ;
    USE SIGNAL ;
    PORT
      LAYER M3 ;
        RECT  41.364 0 41.382 0.038 ;
    END
  END b_d[414]
  PIN b_d[415]
    DIRECTION OUTPUT ;
    USE SIGNAL ;
    PORT
      LAYER M5 ;
        RECT  41.472 0 41.496 0.084 ;
    END
  END b_d[415]
  PIN b_d[416]
    DIRECTION OUTPUT ;
    USE SIGNAL ;
    PORT
      LAYER M3 ;
        RECT  41.544 0 41.562 0.038 ;
    END
  END b_d[416]
  PIN b_d[417]
    DIRECTION OUTPUT ;
    USE SIGNAL ;
    PORT
      LAYER M5 ;
        RECT  41.664 0 41.688 0.084 ;
    END
  END b_d[417]
  PIN b_d[418]
    DIRECTION OUTPUT ;
    USE SIGNAL ;
    PORT
      LAYER M3 ;
        RECT  41.76 0 41.778 0.038 ;
    END
  END b_d[418]
  PIN b_d[419]
    DIRECTION OUTPUT ;
    USE SIGNAL ;
    PORT
      LAYER M5 ;
        RECT  41.856 0 41.88 0.084 ;
    END
  END b_d[419]
  PIN b_d[41]
    DIRECTION OUTPUT ;
    USE SIGNAL ;
    PORT
      LAYER M5 ;
        RECT  4.8 0 4.824 0.084 ;
    END
  END b_d[41]
  PIN b_d[420]
    DIRECTION OUTPUT ;
    USE SIGNAL ;
    PORT
      LAYER M3 ;
        RECT  41.94 0 41.958 0.038 ;
    END
  END b_d[420]
  PIN b_d[421]
    DIRECTION OUTPUT ;
    USE SIGNAL ;
    PORT
      LAYER M5 ;
        RECT  42.048 0 42.072 0.084 ;
    END
  END b_d[421]
  PIN b_d[422]
    DIRECTION OUTPUT ;
    USE SIGNAL ;
    PORT
      LAYER M3 ;
        RECT  42.156 0 42.174 0.038 ;
    END
  END b_d[422]
  PIN b_d[423]
    DIRECTION OUTPUT ;
    USE SIGNAL ;
    PORT
      LAYER M5 ;
        RECT  42.24 0 42.264 0.084 ;
    END
  END b_d[423]
  PIN b_d[424]
    DIRECTION OUTPUT ;
    USE SIGNAL ;
    PORT
      LAYER M3 ;
        RECT  42.336 0 42.354 0.038 ;
    END
  END b_d[424]
  PIN b_d[425]
    DIRECTION OUTPUT ;
    USE SIGNAL ;
    PORT
      LAYER M5 ;
        RECT  42.432 0 42.456 0.084 ;
    END
  END b_d[425]
  PIN b_d[426]
    DIRECTION OUTPUT ;
    USE SIGNAL ;
    PORT
      LAYER M3 ;
        RECT  42.552 0 42.57 0.038 ;
    END
  END b_d[426]
  PIN b_d[427]
    DIRECTION OUTPUT ;
    USE SIGNAL ;
    PORT
      LAYER M5 ;
        RECT  42.624 0 42.648 0.084 ;
    END
  END b_d[427]
  PIN b_d[428]
    DIRECTION OUTPUT ;
    USE SIGNAL ;
    PORT
      LAYER M3 ;
        RECT  42.732 0 42.75 0.038 ;
    END
  END b_d[428]
  PIN b_d[429]
    DIRECTION OUTPUT ;
    USE SIGNAL ;
    PORT
      LAYER M5 ;
        RECT  42.816 0 42.84 0.084 ;
    END
  END b_d[429]
  PIN b_d[42]
    DIRECTION OUTPUT ;
    USE SIGNAL ;
    PORT
      LAYER M3 ;
        RECT  4.896 0 4.914 0.038 ;
    END
  END b_d[42]
  PIN b_d[430]
    DIRECTION OUTPUT ;
    USE SIGNAL ;
    PORT
      LAYER M3 ;
        RECT  42.948 0 42.966 0.038 ;
    END
  END b_d[430]
  PIN b_d[431]
    DIRECTION OUTPUT ;
    USE SIGNAL ;
    PORT
      LAYER M5 ;
        RECT  43.008 0 43.032 0.084 ;
    END
  END b_d[431]
  PIN b_d[432]
    DIRECTION OUTPUT ;
    USE SIGNAL ;
    PORT
      LAYER M3 ;
        RECT  43.128 0 43.146 0.038 ;
    END
  END b_d[432]
  PIN b_d[433]
    DIRECTION OUTPUT ;
    USE SIGNAL ;
    PORT
      LAYER M5 ;
        RECT  43.2 0 43.224 0.084 ;
    END
  END b_d[433]
  PIN b_d[434]
    DIRECTION OUTPUT ;
    USE SIGNAL ;
    PORT
      LAYER M3 ;
        RECT  43.308 0 43.326 0.038 ;
    END
  END b_d[434]
  PIN b_d[435]
    DIRECTION OUTPUT ;
    USE SIGNAL ;
    PORT
      LAYER M5 ;
        RECT  43.44 0 43.464 0.084 ;
    END
  END b_d[435]
  PIN b_d[436]
    DIRECTION OUTPUT ;
    USE SIGNAL ;
    PORT
      LAYER M3 ;
        RECT  43.524 0 43.542 0.038 ;
    END
  END b_d[436]
  PIN b_d[437]
    DIRECTION OUTPUT ;
    USE SIGNAL ;
    PORT
      LAYER M5 ;
        RECT  43.632 0 43.656 0.084 ;
    END
  END b_d[437]
  PIN b_d[438]
    DIRECTION OUTPUT ;
    USE SIGNAL ;
    PORT
      LAYER M3 ;
        RECT  43.704 0 43.722 0.038 ;
    END
  END b_d[438]
  PIN b_d[439]
    DIRECTION OUTPUT ;
    USE SIGNAL ;
    PORT
      LAYER M5 ;
        RECT  43.824 0 43.848 0.084 ;
    END
  END b_d[439]
  PIN b_d[43]
    DIRECTION OUTPUT ;
    USE SIGNAL ;
    PORT
      LAYER M5 ;
        RECT  4.992 0 5.016 0.084 ;
    END
  END b_d[43]
  PIN b_d[440]
    DIRECTION OUTPUT ;
    USE SIGNAL ;
    PORT
      LAYER M3 ;
        RECT  43.92 0 43.938 0.038 ;
    END
  END b_d[440]
  PIN b_d[441]
    DIRECTION OUTPUT ;
    USE SIGNAL ;
    PORT
      LAYER M5 ;
        RECT  44.016 0 44.04 0.084 ;
    END
  END b_d[441]
  PIN b_d[442]
    DIRECTION OUTPUT ;
    USE SIGNAL ;
    PORT
      LAYER M3 ;
        RECT  44.1 0 44.118 0.038 ;
    END
  END b_d[442]
  PIN b_d[443]
    DIRECTION OUTPUT ;
    USE SIGNAL ;
    PORT
      LAYER M5 ;
        RECT  44.208 0 44.232 0.084 ;
    END
  END b_d[443]
  PIN b_d[444]
    DIRECTION OUTPUT ;
    USE SIGNAL ;
    PORT
      LAYER M3 ;
        RECT  44.316 0 44.334 0.038 ;
    END
  END b_d[444]
  PIN b_d[445]
    DIRECTION OUTPUT ;
    USE SIGNAL ;
    PORT
      LAYER M5 ;
        RECT  44.4 0 44.424 0.084 ;
    END
  END b_d[445]
  PIN b_d[446]
    DIRECTION OUTPUT ;
    USE SIGNAL ;
    PORT
      LAYER M3 ;
        RECT  44.496 0 44.514 0.038 ;
    END
  END b_d[446]
  PIN b_d[447]
    DIRECTION OUTPUT ;
    USE SIGNAL ;
    PORT
      LAYER M5 ;
        RECT  44.592 0 44.616 0.084 ;
    END
  END b_d[447]
  PIN b_d[448]
    DIRECTION OUTPUT ;
    USE SIGNAL ;
    PORT
      LAYER M3 ;
        RECT  44.712 0 44.73 0.038 ;
    END
  END b_d[448]
  PIN b_d[449]
    DIRECTION OUTPUT ;
    USE SIGNAL ;
    PORT
      LAYER M5 ;
        RECT  44.784 0 44.808 0.084 ;
    END
  END b_d[449]
  PIN b_d[44]
    DIRECTION OUTPUT ;
    USE SIGNAL ;
    PORT
      LAYER M3 ;
        RECT  5.076 0 5.094 0.038 ;
    END
  END b_d[44]
  PIN b_d[450]
    DIRECTION OUTPUT ;
    USE SIGNAL ;
    PORT
      LAYER M3 ;
        RECT  44.892 0 44.91 0.038 ;
    END
  END b_d[450]
  PIN b_d[451]
    DIRECTION OUTPUT ;
    USE SIGNAL ;
    PORT
      LAYER M5 ;
        RECT  44.976 0 45 0.084 ;
    END
  END b_d[451]
  PIN b_d[452]
    DIRECTION OUTPUT ;
    USE SIGNAL ;
    PORT
      LAYER M3 ;
        RECT  45.072 0 45.09 0.038 ;
    END
  END b_d[452]
  PIN b_d[453]
    DIRECTION OUTPUT ;
    USE SIGNAL ;
    PORT
      LAYER M5 ;
        RECT  45.168 0 45.192 0.084 ;
    END
  END b_d[453]
  PIN b_d[454]
    DIRECTION OUTPUT ;
    USE SIGNAL ;
    PORT
      LAYER M3 ;
        RECT  45.288 0 45.306 0.038 ;
    END
  END b_d[454]
  PIN b_d[455]
    DIRECTION OUTPUT ;
    USE SIGNAL ;
    PORT
      LAYER M5 ;
        RECT  45.36 0 45.384 0.084 ;
    END
  END b_d[455]
  PIN b_d[456]
    DIRECTION OUTPUT ;
    USE SIGNAL ;
    PORT
      LAYER M3 ;
        RECT  45.468 0 45.486 0.038 ;
    END
  END b_d[456]
  PIN b_d[457]
    DIRECTION OUTPUT ;
    USE SIGNAL ;
    PORT
      LAYER M5 ;
        RECT  45.6 0 45.624 0.084 ;
    END
  END b_d[457]
  PIN b_d[458]
    DIRECTION OUTPUT ;
    USE SIGNAL ;
    PORT
      LAYER M3 ;
        RECT  45.684 0 45.702 0.038 ;
    END
  END b_d[458]
  PIN b_d[459]
    DIRECTION OUTPUT ;
    USE SIGNAL ;
    PORT
      LAYER M5 ;
        RECT  45.792 0 45.816 0.084 ;
    END
  END b_d[459]
  PIN b_d[45]
    DIRECTION OUTPUT ;
    USE SIGNAL ;
    PORT
      LAYER M5 ;
        RECT  5.184 0 5.208 0.084 ;
    END
  END b_d[45]
  PIN b_d[460]
    DIRECTION OUTPUT ;
    USE SIGNAL ;
    PORT
      LAYER M3 ;
        RECT  45.864 0 45.882 0.038 ;
    END
  END b_d[460]
  PIN b_d[461]
    DIRECTION OUTPUT ;
    USE SIGNAL ;
    PORT
      LAYER M5 ;
        RECT  45.984 0 46.008 0.084 ;
    END
  END b_d[461]
  PIN b_d[462]
    DIRECTION OUTPUT ;
    USE SIGNAL ;
    PORT
      LAYER M3 ;
        RECT  46.08 0 46.098 0.038 ;
    END
  END b_d[462]
  PIN b_d[463]
    DIRECTION OUTPUT ;
    USE SIGNAL ;
    PORT
      LAYER M5 ;
        RECT  46.176 0 46.2 0.084 ;
    END
  END b_d[463]
  PIN b_d[464]
    DIRECTION OUTPUT ;
    USE SIGNAL ;
    PORT
      LAYER M3 ;
        RECT  46.26 0 46.278 0.038 ;
    END
  END b_d[464]
  PIN b_d[465]
    DIRECTION OUTPUT ;
    USE SIGNAL ;
    PORT
      LAYER M5 ;
        RECT  46.368 0 46.392 0.084 ;
    END
  END b_d[465]
  PIN b_d[466]
    DIRECTION OUTPUT ;
    USE SIGNAL ;
    PORT
      LAYER M3 ;
        RECT  46.476 0 46.494 0.038 ;
    END
  END b_d[466]
  PIN b_d[467]
    DIRECTION OUTPUT ;
    USE SIGNAL ;
    PORT
      LAYER M5 ;
        RECT  46.56 0 46.584 0.084 ;
    END
  END b_d[467]
  PIN b_d[468]
    DIRECTION OUTPUT ;
    USE SIGNAL ;
    PORT
      LAYER M3 ;
        RECT  46.656 0 46.674 0.038 ;
    END
  END b_d[468]
  PIN b_d[469]
    DIRECTION OUTPUT ;
    USE SIGNAL ;
    PORT
      LAYER M5 ;
        RECT  46.752 0 46.776 0.084 ;
    END
  END b_d[469]
  PIN b_d[46]
    DIRECTION OUTPUT ;
    USE SIGNAL ;
    PORT
      LAYER M3 ;
        RECT  5.292 0 5.31 0.038 ;
    END
  END b_d[46]
  PIN b_d[470]
    DIRECTION OUTPUT ;
    USE SIGNAL ;
    PORT
      LAYER M3 ;
        RECT  46.872 0 46.89 0.038 ;
    END
  END b_d[470]
  PIN b_d[471]
    DIRECTION OUTPUT ;
    USE SIGNAL ;
    PORT
      LAYER M5 ;
        RECT  46.944 0 46.968 0.084 ;
    END
  END b_d[471]
  PIN b_d[472]
    DIRECTION OUTPUT ;
    USE SIGNAL ;
    PORT
      LAYER M3 ;
        RECT  47.052 0 47.07 0.038 ;
    END
  END b_d[472]
  PIN b_d[473]
    DIRECTION OUTPUT ;
    USE SIGNAL ;
    PORT
      LAYER M5 ;
        RECT  47.136 0 47.16 0.084 ;
    END
  END b_d[473]
  PIN b_d[474]
    DIRECTION OUTPUT ;
    USE SIGNAL ;
    PORT
      LAYER M3 ;
        RECT  47.232 0 47.25 0.038 ;
    END
  END b_d[474]
  PIN b_d[475]
    DIRECTION OUTPUT ;
    USE SIGNAL ;
    PORT
      LAYER M5 ;
        RECT  47.328 0 47.352 0.084 ;
    END
  END b_d[475]
  PIN b_d[476]
    DIRECTION OUTPUT ;
    USE SIGNAL ;
    PORT
      LAYER M3 ;
        RECT  47.448 0 47.466 0.038 ;
    END
  END b_d[476]
  PIN b_d[477]
    DIRECTION OUTPUT ;
    USE SIGNAL ;
    PORT
      LAYER M5 ;
        RECT  47.52 0 47.544 0.084 ;
    END
  END b_d[477]
  PIN b_d[478]
    DIRECTION OUTPUT ;
    USE SIGNAL ;
    PORT
      LAYER M3 ;
        RECT  47.628 0 47.646 0.038 ;
    END
  END b_d[478]
  PIN b_d[479]
    DIRECTION OUTPUT ;
    USE SIGNAL ;
    PORT
      LAYER M5 ;
        RECT  47.712 0 47.736 0.084 ;
    END
  END b_d[479]
  PIN b_d[47]
    DIRECTION OUTPUT ;
    USE SIGNAL ;
    PORT
      LAYER M5 ;
        RECT  5.376 0 5.4 0.084 ;
    END
  END b_d[47]
  PIN b_d[480]
    DIRECTION OUTPUT ;
    USE SIGNAL ;
    PORT
      LAYER M3 ;
        RECT  47.844 0 47.862 0.038 ;
    END
  END b_d[480]
  PIN b_d[481]
    DIRECTION OUTPUT ;
    USE SIGNAL ;
    PORT
      LAYER M5 ;
        RECT  47.952 0 47.976 0.084 ;
    END
  END b_d[481]
  PIN b_d[482]
    DIRECTION OUTPUT ;
    USE SIGNAL ;
    PORT
      LAYER M3 ;
        RECT  48.024 0 48.042 0.038 ;
    END
  END b_d[482]
  PIN b_d[483]
    DIRECTION OUTPUT ;
    USE SIGNAL ;
    PORT
      LAYER M5 ;
        RECT  48.144 0 48.168 0.084 ;
    END
  END b_d[483]
  PIN b_d[484]
    DIRECTION OUTPUT ;
    USE SIGNAL ;
    PORT
      LAYER M3 ;
        RECT  48.24 0 48.258 0.038 ;
    END
  END b_d[484]
  PIN b_d[485]
    DIRECTION OUTPUT ;
    USE SIGNAL ;
    PORT
      LAYER M5 ;
        RECT  48.336 0 48.36 0.084 ;
    END
  END b_d[485]
  PIN b_d[486]
    DIRECTION OUTPUT ;
    USE SIGNAL ;
    PORT
      LAYER M3 ;
        RECT  48.42 0 48.438 0.038 ;
    END
  END b_d[486]
  PIN b_d[487]
    DIRECTION OUTPUT ;
    USE SIGNAL ;
    PORT
      LAYER M5 ;
        RECT  48.528 0 48.552 0.084 ;
    END
  END b_d[487]
  PIN b_d[488]
    DIRECTION OUTPUT ;
    USE SIGNAL ;
    PORT
      LAYER M3 ;
        RECT  48.636 0 48.654 0.038 ;
    END
  END b_d[488]
  PIN b_d[489]
    DIRECTION OUTPUT ;
    USE SIGNAL ;
    PORT
      LAYER M5 ;
        RECT  48.72 0 48.744 0.084 ;
    END
  END b_d[489]
  PIN b_d[48]
    DIRECTION OUTPUT ;
    USE SIGNAL ;
    PORT
      LAYER M3 ;
        RECT  5.472 0 5.49 0.038 ;
    END
  END b_d[48]
  PIN b_d[490]
    DIRECTION OUTPUT ;
    USE SIGNAL ;
    PORT
      LAYER M3 ;
        RECT  48.816 0 48.834 0.038 ;
    END
  END b_d[490]
  PIN b_d[491]
    DIRECTION OUTPUT ;
    USE SIGNAL ;
    PORT
      LAYER M5 ;
        RECT  48.912 0 48.936 0.084 ;
    END
  END b_d[491]
  PIN b_d[492]
    DIRECTION OUTPUT ;
    USE SIGNAL ;
    PORT
      LAYER M3 ;
        RECT  48.996 0 49.014 0.038 ;
    END
  END b_d[492]
  PIN b_d[493]
    DIRECTION OUTPUT ;
    USE SIGNAL ;
    PORT
      LAYER M5 ;
        RECT  49.104 0 49.128 0.084 ;
    END
  END b_d[493]
  PIN b_d[494]
    DIRECTION OUTPUT ;
    USE SIGNAL ;
    PORT
      LAYER M3 ;
        RECT  49.212 0 49.23 0.038 ;
    END
  END b_d[494]
  PIN b_d[495]
    DIRECTION OUTPUT ;
    USE SIGNAL ;
    PORT
      LAYER M5 ;
        RECT  49.296 0 49.32 0.084 ;
    END
  END b_d[495]
  PIN b_d[496]
    DIRECTION OUTPUT ;
    USE SIGNAL ;
    PORT
      LAYER M3 ;
        RECT  49.392 0 49.41 0.038 ;
    END
  END b_d[496]
  PIN b_d[497]
    DIRECTION OUTPUT ;
    USE SIGNAL ;
    PORT
      LAYER M5 ;
        RECT  49.488 0 49.512 0.084 ;
    END
  END b_d[497]
  PIN b_d[498]
    DIRECTION OUTPUT ;
    USE SIGNAL ;
    PORT
      LAYER M3 ;
        RECT  49.608 0 49.626 0.038 ;
    END
  END b_d[498]
  PIN b_d[499]
    DIRECTION OUTPUT ;
    USE SIGNAL ;
    PORT
      LAYER M5 ;
        RECT  49.68 0 49.704 0.084 ;
    END
  END b_d[499]
  PIN b_d[49]
    DIRECTION OUTPUT ;
    USE SIGNAL ;
    PORT
      LAYER M5 ;
        RECT  5.568 0 5.592 0.084 ;
    END
  END b_d[49]
  PIN b_d[4]
    DIRECTION OUTPUT ;
    USE SIGNAL ;
    PORT
      LAYER M3 ;
        RECT  1.152 0 1.17 0.038 ;
    END
  END b_d[4]
  PIN b_d[500]
    DIRECTION OUTPUT ;
    USE SIGNAL ;
    PORT
      LAYER M3 ;
        RECT  49.788 0 49.806 0.038 ;
    END
  END b_d[500]
  PIN b_d[501]
    DIRECTION OUTPUT ;
    USE SIGNAL ;
    PORT
      LAYER M5 ;
        RECT  49.872 0 49.896 0.084 ;
    END
  END b_d[501]
  PIN b_d[502]
    DIRECTION OUTPUT ;
    USE SIGNAL ;
    PORT
      LAYER M3 ;
        RECT  50.004 0 50.022 0.038 ;
    END
  END b_d[502]
  PIN b_d[503]
    DIRECTION OUTPUT ;
    USE SIGNAL ;
    PORT
      LAYER M5 ;
        RECT  50.064 0 50.088 0.084 ;
    END
  END b_d[503]
  PIN b_d[504]
    DIRECTION OUTPUT ;
    USE SIGNAL ;
    PORT
      LAYER M3 ;
        RECT  50.184 0 50.202 0.038 ;
    END
  END b_d[504]
  PIN b_d[505]
    DIRECTION OUTPUT ;
    USE SIGNAL ;
    PORT
      LAYER M5 ;
        RECT  50.304 0 50.328 0.084 ;
    END
  END b_d[505]
  PIN b_d[506]
    DIRECTION OUTPUT ;
    USE SIGNAL ;
    PORT
      LAYER M3 ;
        RECT  50.4 0 50.418 0.038 ;
    END
  END b_d[506]
  PIN b_d[507]
    DIRECTION OUTPUT ;
    USE SIGNAL ;
    PORT
      LAYER M5 ;
        RECT  50.496 0 50.52 0.084 ;
    END
  END b_d[507]
  PIN b_d[508]
    DIRECTION OUTPUT ;
    USE SIGNAL ;
    PORT
      LAYER M3 ;
        RECT  50.58 0 50.598 0.038 ;
    END
  END b_d[508]
  PIN b_d[509]
    DIRECTION OUTPUT ;
    USE SIGNAL ;
    PORT
      LAYER M5 ;
        RECT  50.688 0 50.712 0.084 ;
    END
  END b_d[509]
  PIN b_d[50]
    DIRECTION OUTPUT ;
    USE SIGNAL ;
    PORT
      LAYER M3 ;
        RECT  5.688 0 5.706 0.038 ;
    END
  END b_d[50]
  PIN b_d[510]
    DIRECTION OUTPUT ;
    USE SIGNAL ;
    PORT
      LAYER M3 ;
        RECT  50.76 0 50.778 0.038 ;
    END
  END b_d[510]
  PIN b_d[511]
    DIRECTION OUTPUT ;
    USE SIGNAL ;
    PORT
      LAYER M5 ;
        RECT  50.88 0 50.904 0.084 ;
    END
  END b_d[511]
  PIN b_d[512]
    DIRECTION OUTPUT ;
    USE SIGNAL ;
    PORT
      LAYER M3 ;
        RECT  50.976 0 50.994 0.038 ;
    END
  END b_d[512]
  PIN b_d[513]
    DIRECTION OUTPUT ;
    USE SIGNAL ;
    PORT
      LAYER M5 ;
        RECT  51.072 0 51.096 0.084 ;
    END
  END b_d[513]
  PIN b_d[514]
    DIRECTION OUTPUT ;
    USE SIGNAL ;
    PORT
      LAYER M3 ;
        RECT  51.156 0 51.174 0.038 ;
    END
  END b_d[514]
  PIN b_d[515]
    DIRECTION OUTPUT ;
    USE SIGNAL ;
    PORT
      LAYER M5 ;
        RECT  51.264 0 51.288 0.084 ;
    END
  END b_d[515]
  PIN b_d[51]
    DIRECTION OUTPUT ;
    USE SIGNAL ;
    PORT
      LAYER M5 ;
        RECT  5.76 0 5.784 0.084 ;
    END
  END b_d[51]
  PIN b_d[52]
    DIRECTION OUTPUT ;
    USE SIGNAL ;
    PORT
      LAYER M3 ;
        RECT  5.868 0 5.886 0.038 ;
    END
  END b_d[52]
  PIN b_d[53]
    DIRECTION OUTPUT ;
    USE SIGNAL ;
    PORT
      LAYER M5 ;
        RECT  5.952 0 5.976 0.084 ;
    END
  END b_d[53]
  PIN b_d[54]
    DIRECTION OUTPUT ;
    USE SIGNAL ;
    PORT
      LAYER M3 ;
        RECT  6.084 0 6.102 0.038 ;
    END
  END b_d[54]
  PIN b_d[55]
    DIRECTION OUTPUT ;
    USE SIGNAL ;
    PORT
      LAYER M5 ;
        RECT  6.144 0 6.168 0.084 ;
    END
  END b_d[55]
  PIN b_d[56]
    DIRECTION OUTPUT ;
    USE SIGNAL ;
    PORT
      LAYER M3 ;
        RECT  6.264 0 6.282 0.038 ;
    END
  END b_d[56]
  PIN b_d[57]
    DIRECTION OUTPUT ;
    USE SIGNAL ;
    PORT
      LAYER M5 ;
        RECT  6.336 0 6.36 0.084 ;
    END
  END b_d[57]
  PIN b_d[58]
    DIRECTION OUTPUT ;
    USE SIGNAL ;
    PORT
      LAYER M3 ;
        RECT  6.444 0 6.462 0.038 ;
    END
  END b_d[58]
  PIN b_d[59]
    DIRECTION OUTPUT ;
    USE SIGNAL ;
    PORT
      LAYER M5 ;
        RECT  6.576 0 6.6 0.084 ;
    END
  END b_d[59]
  PIN b_d[5]
    DIRECTION OUTPUT ;
    USE SIGNAL ;
    PORT
      LAYER M5 ;
        RECT  1.248 0 1.272 0.084 ;
    END
  END b_d[5]
  PIN b_d[60]
    DIRECTION OUTPUT ;
    USE SIGNAL ;
    PORT
      LAYER M3 ;
        RECT  6.66 0 6.678 0.038 ;
    END
  END b_d[60]
  PIN b_d[61]
    DIRECTION OUTPUT ;
    USE SIGNAL ;
    PORT
      LAYER M5 ;
        RECT  6.768 0 6.792 0.084 ;
    END
  END b_d[61]
  PIN b_d[62]
    DIRECTION OUTPUT ;
    USE SIGNAL ;
    PORT
      LAYER M3 ;
        RECT  6.84 0 6.858 0.038 ;
    END
  END b_d[62]
  PIN b_d[63]
    DIRECTION OUTPUT ;
    USE SIGNAL ;
    PORT
      LAYER M5 ;
        RECT  6.96 0 6.984 0.084 ;
    END
  END b_d[63]
  PIN b_d[64]
    DIRECTION OUTPUT ;
    USE SIGNAL ;
    PORT
      LAYER M3 ;
        RECT  7.056 0 7.074 0.038 ;
    END
  END b_d[64]
  PIN b_d[65]
    DIRECTION OUTPUT ;
    USE SIGNAL ;
    PORT
      LAYER M5 ;
        RECT  7.152 0 7.176 0.084 ;
    END
  END b_d[65]
  PIN b_d[66]
    DIRECTION OUTPUT ;
    USE SIGNAL ;
    PORT
      LAYER M3 ;
        RECT  7.236 0 7.254 0.038 ;
    END
  END b_d[66]
  PIN b_d[67]
    DIRECTION OUTPUT ;
    USE SIGNAL ;
    PORT
      LAYER M5 ;
        RECT  7.344 0 7.368 0.084 ;
    END
  END b_d[67]
  PIN b_d[68]
    DIRECTION OUTPUT ;
    USE SIGNAL ;
    PORT
      LAYER M3 ;
        RECT  7.452 0 7.47 0.038 ;
    END
  END b_d[68]
  PIN b_d[69]
    DIRECTION OUTPUT ;
    USE SIGNAL ;
    PORT
      LAYER M5 ;
        RECT  7.536 0 7.56 0.084 ;
    END
  END b_d[69]
  PIN b_d[6]
    DIRECTION OUTPUT ;
    USE SIGNAL ;
    PORT
      LAYER M3 ;
        RECT  1.368 0 1.386 0.038 ;
    END
  END b_d[6]
  PIN b_d[70]
    DIRECTION OUTPUT ;
    USE SIGNAL ;
    PORT
      LAYER M3 ;
        RECT  7.632 0 7.65 0.038 ;
    END
  END b_d[70]
  PIN b_d[71]
    DIRECTION OUTPUT ;
    USE SIGNAL ;
    PORT
      LAYER M5 ;
        RECT  7.728 0 7.752 0.084 ;
    END
  END b_d[71]
  PIN b_d[72]
    DIRECTION OUTPUT ;
    USE SIGNAL ;
    PORT
      LAYER M3 ;
        RECT  7.848 0 7.866 0.038 ;
    END
  END b_d[72]
  PIN b_d[73]
    DIRECTION OUTPUT ;
    USE SIGNAL ;
    PORT
      LAYER M5 ;
        RECT  7.92 0 7.944 0.084 ;
    END
  END b_d[73]
  PIN b_d[74]
    DIRECTION OUTPUT ;
    USE SIGNAL ;
    PORT
      LAYER M3 ;
        RECT  8.028 0 8.046 0.038 ;
    END
  END b_d[74]
  PIN b_d[75]
    DIRECTION OUTPUT ;
    USE SIGNAL ;
    PORT
      LAYER M5 ;
        RECT  8.112 0 8.136 0.084 ;
    END
  END b_d[75]
  PIN b_d[76]
    DIRECTION OUTPUT ;
    USE SIGNAL ;
    PORT
      LAYER M3 ;
        RECT  8.208 0 8.226 0.038 ;
    END
  END b_d[76]
  PIN b_d[77]
    DIRECTION OUTPUT ;
    USE SIGNAL ;
    PORT
      LAYER M5 ;
        RECT  8.304 0 8.328 0.084 ;
    END
  END b_d[77]
  PIN b_d[78]
    DIRECTION OUTPUT ;
    USE SIGNAL ;
    PORT
      LAYER M3 ;
        RECT  8.424 0 8.442 0.038 ;
    END
  END b_d[78]
  PIN b_d[79]
    DIRECTION OUTPUT ;
    USE SIGNAL ;
    PORT
      LAYER M5 ;
        RECT  8.496 0 8.52 0.084 ;
    END
  END b_d[79]
  PIN b_d[7]
    DIRECTION OUTPUT ;
    USE SIGNAL ;
    PORT
      LAYER M5 ;
        RECT  1.44 0 1.464 0.084 ;
    END
  END b_d[7]
  PIN b_d[80]
    DIRECTION OUTPUT ;
    USE SIGNAL ;
    PORT
      LAYER M3 ;
        RECT  8.604 0 8.622 0.038 ;
    END
  END b_d[80]
  PIN b_d[81]
    DIRECTION OUTPUT ;
    USE SIGNAL ;
    PORT
      LAYER M5 ;
        RECT  8.688 0 8.712 0.084 ;
    END
  END b_d[81]
  PIN b_d[82]
    DIRECTION OUTPUT ;
    USE SIGNAL ;
    PORT
      LAYER M3 ;
        RECT  8.82 0 8.838 0.038 ;
    END
  END b_d[82]
  PIN b_d[83]
    DIRECTION OUTPUT ;
    USE SIGNAL ;
    PORT
      LAYER M5 ;
        RECT  8.928 0 8.952 0.084 ;
    END
  END b_d[83]
  PIN b_d[84]
    DIRECTION OUTPUT ;
    USE SIGNAL ;
    PORT
      LAYER M3 ;
        RECT  9 0 9.018 0.038 ;
    END
  END b_d[84]
  PIN b_d[85]
    DIRECTION OUTPUT ;
    USE SIGNAL ;
    PORT
      LAYER M5 ;
        RECT  9.12 0 9.144 0.084 ;
    END
  END b_d[85]
  PIN b_d[86]
    DIRECTION OUTPUT ;
    USE SIGNAL ;
    PORT
      LAYER M3 ;
        RECT  9.216 0 9.234 0.038 ;
    END
  END b_d[86]
  PIN b_d[87]
    DIRECTION OUTPUT ;
    USE SIGNAL ;
    PORT
      LAYER M5 ;
        RECT  9.312 0 9.336 0.084 ;
    END
  END b_d[87]
  PIN b_d[88]
    DIRECTION OUTPUT ;
    USE SIGNAL ;
    PORT
      LAYER M3 ;
        RECT  9.396 0 9.414 0.038 ;
    END
  END b_d[88]
  PIN b_d[89]
    DIRECTION OUTPUT ;
    USE SIGNAL ;
    PORT
      LAYER M5 ;
        RECT  9.504 0 9.528 0.084 ;
    END
  END b_d[89]
  PIN b_d[8]
    DIRECTION OUTPUT ;
    USE SIGNAL ;
    PORT
      LAYER M3 ;
        RECT  1.548 0 1.566 0.038 ;
    END
  END b_d[8]
  PIN b_d[90]
    DIRECTION OUTPUT ;
    USE SIGNAL ;
    PORT
      LAYER M3 ;
        RECT  9.612 0 9.63 0.038 ;
    END
  END b_d[90]
  PIN b_d[91]
    DIRECTION OUTPUT ;
    USE SIGNAL ;
    PORT
      LAYER M5 ;
        RECT  9.696 0 9.72 0.084 ;
    END
  END b_d[91]
  PIN b_d[92]
    DIRECTION OUTPUT ;
    USE SIGNAL ;
    PORT
      LAYER M3 ;
        RECT  9.792 0 9.81 0.038 ;
    END
  END b_d[92]
  PIN b_d[93]
    DIRECTION OUTPUT ;
    USE SIGNAL ;
    PORT
      LAYER M5 ;
        RECT  9.888 0 9.912 0.084 ;
    END
  END b_d[93]
  PIN b_d[94]
    DIRECTION OUTPUT ;
    USE SIGNAL ;
    PORT
      LAYER M3 ;
        RECT  9.972 0 9.99 0.038 ;
    END
  END b_d[94]
  PIN b_d[95]
    DIRECTION OUTPUT ;
    USE SIGNAL ;
    PORT
      LAYER M5 ;
        RECT  10.08 0 10.104 0.084 ;
    END
  END b_d[95]
  PIN b_d[96]
    DIRECTION OUTPUT ;
    USE SIGNAL ;
    PORT
      LAYER M3 ;
        RECT  10.188 0 10.206 0.038 ;
    END
  END b_d[96]
  PIN b_d[97]
    DIRECTION OUTPUT ;
    USE SIGNAL ;
    PORT
      LAYER M5 ;
        RECT  10.272 0 10.296 0.084 ;
    END
  END b_d[97]
  PIN b_d[98]
    DIRECTION OUTPUT ;
    USE SIGNAL ;
    PORT
      LAYER M3 ;
        RECT  10.368 0 10.386 0.038 ;
    END
  END b_d[98]
  PIN b_d[99]
    DIRECTION OUTPUT ;
    USE SIGNAL ;
    PORT
      LAYER M5 ;
        RECT  10.464 0 10.488 0.084 ;
    END
  END b_d[99]
  PIN b_d[9]
    DIRECTION OUTPUT ;
    USE SIGNAL ;
    PORT
      LAYER M5 ;
        RECT  1.632 0 1.656 0.084 ;
    END
  END b_d[9]
  PIN ck
    DIRECTION INPUT ;
    USE SIGNAL ;
    PORT
      LAYER M3 ;
        RECT  52.056 103.618 52.074 103.656 ;
    END
  END ck
  PIN rst_n
    DIRECTION INPUT ;
    USE SIGNAL ;
    PORT
      LAYER M3 ;
        RECT  52.344 103.618 52.362 103.656 ;
    END
  END rst_n
  PIN sidx[0]
    DIRECTION INPUT ;
    USE SIGNAL ;
    PORT
      LAYER M3 ;
        RECT  0.288 103.618 0.306 103.656 ;
    END
  END sidx[0]
  PIN sidx[1]
    DIRECTION INPUT ;
    USE SIGNAL ;
    PORT
      LAYER M5 ;
        RECT  0.48 103.572 0.504 103.656 ;
    END
    PORT
      LAYER M5 ;
        RECT  0.48 100.261 0.504 103.632 ;
    END
  END sidx[1]
  PIN sidx[2]
    DIRECTION INPUT ;
    USE SIGNAL ;
    PORT
      LAYER M3 ;
        RECT  0.684 103.618 0.702 103.656 ;
    END
  END sidx[2]
  PIN tap_d[0]
    DIRECTION OUTPUT ;
    USE SIGNAL ;
    PORT
      LAYER M4 ;
        RECT  0 26.976 0.084 27 ;
    END
  END tap_d[0]
  PIN tap_d[100]
    DIRECTION OUTPUT ;
    USE SIGNAL ;
    PORT
      LAYER M4 ;
        RECT  0 36.912 0.084 36.936 ;
    END
  END tap_d[100]
  PIN tap_d[101]
    DIRECTION OUTPUT ;
    USE SIGNAL ;
    PORT
      LAYER M4 ;
        RECT  0 37.008 0.084 37.032 ;
    END
  END tap_d[101]
  PIN tap_d[102]
    DIRECTION OUTPUT ;
    USE SIGNAL ;
    PORT
      LAYER M4 ;
        RECT  0 37.104 0.084 37.128 ;
    END
  END tap_d[102]
  PIN tap_d[103]
    DIRECTION OUTPUT ;
    USE SIGNAL ;
    PORT
      LAYER M4 ;
        RECT  0 37.2 0.084 37.224 ;
    END
  END tap_d[103]
  PIN tap_d[104]
    DIRECTION OUTPUT ;
    USE SIGNAL ;
    PORT
      LAYER M4 ;
        RECT  0 37.296 0.084 37.32 ;
    END
  END tap_d[104]
  PIN tap_d[105]
    DIRECTION OUTPUT ;
    USE SIGNAL ;
    PORT
      LAYER M4 ;
        RECT  0 37.392 0.084 37.416 ;
    END
  END tap_d[105]
  PIN tap_d[106]
    DIRECTION OUTPUT ;
    USE SIGNAL ;
    PORT
      LAYER M4 ;
        RECT  0 37.536 0.084 37.56 ;
    END
  END tap_d[106]
  PIN tap_d[107]
    DIRECTION OUTPUT ;
    USE SIGNAL ;
    PORT
      LAYER M4 ;
        RECT  0 37.632 0.084 37.656 ;
    END
  END tap_d[107]
  PIN tap_d[108]
    DIRECTION OUTPUT ;
    USE SIGNAL ;
    PORT
      LAYER M4 ;
        RECT  0 37.728 0.084 37.752 ;
    END
  END tap_d[108]
  PIN tap_d[109]
    DIRECTION OUTPUT ;
    USE SIGNAL ;
    PORT
      LAYER M4 ;
        RECT  0 37.824 0.084 37.848 ;
    END
  END tap_d[109]
  PIN tap_d[10]
    DIRECTION OUTPUT ;
    USE SIGNAL ;
    PORT
      LAYER M4 ;
        RECT  0 27.984 0.084 28.008 ;
    END
  END tap_d[10]
  PIN tap_d[110]
    DIRECTION OUTPUT ;
    USE SIGNAL ;
    PORT
      LAYER M4 ;
        RECT  0 37.92 0.084 37.944 ;
    END
  END tap_d[110]
  PIN tap_d[111]
    DIRECTION OUTPUT ;
    USE SIGNAL ;
    PORT
      LAYER M4 ;
        RECT  0 38.016 0.084 38.04 ;
    END
  END tap_d[111]
  PIN tap_d[112]
    DIRECTION OUTPUT ;
    USE SIGNAL ;
    PORT
      LAYER M4 ;
        RECT  0 38.112 0.084 38.136 ;
    END
  END tap_d[112]
  PIN tap_d[113]
    DIRECTION OUTPUT ;
    USE SIGNAL ;
    PORT
      LAYER M4 ;
        RECT  0 38.208 0.084 38.232 ;
    END
  END tap_d[113]
  PIN tap_d[114]
    DIRECTION OUTPUT ;
    USE SIGNAL ;
    PORT
      LAYER M4 ;
        RECT  0 38.304 0.084 38.328 ;
    END
  END tap_d[114]
  PIN tap_d[115]
    DIRECTION OUTPUT ;
    USE SIGNAL ;
    PORT
      LAYER M4 ;
        RECT  0 38.4 0.084 38.424 ;
    END
  END tap_d[115]
  PIN tap_d[116]
    DIRECTION OUTPUT ;
    USE SIGNAL ;
    PORT
      LAYER M4 ;
        RECT  0 38.496 0.084 38.52 ;
    END
  END tap_d[116]
  PIN tap_d[117]
    DIRECTION OUTPUT ;
    USE SIGNAL ;
    PORT
      LAYER M4 ;
        RECT  0 38.592 0.084 38.616 ;
    END
  END tap_d[117]
  PIN tap_d[118]
    DIRECTION OUTPUT ;
    USE SIGNAL ;
    PORT
      LAYER M4 ;
        RECT  0 38.688 0.084 38.712 ;
    END
  END tap_d[118]
  PIN tap_d[119]
    DIRECTION OUTPUT ;
    USE SIGNAL ;
    PORT
      LAYER M4 ;
        RECT  0 38.784 0.084 38.808 ;
    END
  END tap_d[119]
  PIN tap_d[11]
    DIRECTION OUTPUT ;
    USE SIGNAL ;
    PORT
      LAYER M4 ;
        RECT  0 28.08 0.084 28.104 ;
    END
  END tap_d[11]
  PIN tap_d[120]
    DIRECTION OUTPUT ;
    USE SIGNAL ;
    PORT
      LAYER M4 ;
        RECT  0 38.928 0.084 38.952 ;
    END
  END tap_d[120]
  PIN tap_d[121]
    DIRECTION OUTPUT ;
    USE SIGNAL ;
    PORT
      LAYER M4 ;
        RECT  0 39.024 0.084 39.048 ;
    END
  END tap_d[121]
  PIN tap_d[122]
    DIRECTION OUTPUT ;
    USE SIGNAL ;
    PORT
      LAYER M4 ;
        RECT  0 39.12 0.084 39.144 ;
    END
  END tap_d[122]
  PIN tap_d[123]
    DIRECTION OUTPUT ;
    USE SIGNAL ;
    PORT
      LAYER M4 ;
        RECT  0 39.216 0.084 39.24 ;
    END
  END tap_d[123]
  PIN tap_d[124]
    DIRECTION OUTPUT ;
    USE SIGNAL ;
    PORT
      LAYER M4 ;
        RECT  0 39.312 0.084 39.336 ;
    END
  END tap_d[124]
  PIN tap_d[125]
    DIRECTION OUTPUT ;
    USE SIGNAL ;
    PORT
      LAYER M4 ;
        RECT  0 39.408 0.084 39.432 ;
    END
  END tap_d[125]
  PIN tap_d[126]
    DIRECTION OUTPUT ;
    USE SIGNAL ;
    PORT
      LAYER M4 ;
        RECT  0 39.504 0.084 39.528 ;
    END
  END tap_d[126]
  PIN tap_d[127]
    DIRECTION OUTPUT ;
    USE SIGNAL ;
    PORT
      LAYER M4 ;
        RECT  0 39.6 0.084 39.624 ;
    END
  END tap_d[127]
  PIN tap_d[128]
    DIRECTION OUTPUT ;
    USE SIGNAL ;
    PORT
      LAYER M4 ;
        RECT  0 39.696 0.084 39.72 ;
    END
  END tap_d[128]
  PIN tap_d[129]
    DIRECTION OUTPUT ;
    USE SIGNAL ;
    PORT
      LAYER M4 ;
        RECT  0 39.792 0.084 39.816 ;
    END
  END tap_d[129]
  PIN tap_d[12]
    DIRECTION OUTPUT ;
    USE SIGNAL ;
    PORT
      LAYER M4 ;
        RECT  0 28.176 0.084 28.2 ;
    END
  END tap_d[12]
  PIN tap_d[130]
    DIRECTION OUTPUT ;
    USE SIGNAL ;
    PORT
      LAYER M4 ;
        RECT  0 39.888 0.084 39.912 ;
    END
  END tap_d[130]
  PIN tap_d[131]
    DIRECTION OUTPUT ;
    USE SIGNAL ;
    PORT
      LAYER M4 ;
        RECT  0 39.984 0.084 40.008 ;
    END
  END tap_d[131]
  PIN tap_d[132]
    DIRECTION OUTPUT ;
    USE SIGNAL ;
    PORT
      LAYER M4 ;
        RECT  0 40.08 0.084 40.104 ;
    END
  END tap_d[132]
  PIN tap_d[133]
    DIRECTION OUTPUT ;
    USE SIGNAL ;
    PORT
      LAYER M4 ;
        RECT  0 40.176 0.084 40.2 ;
    END
  END tap_d[133]
  PIN tap_d[134]
    DIRECTION OUTPUT ;
    USE SIGNAL ;
    PORT
      LAYER M4 ;
        RECT  0 40.32 0.084 40.344 ;
    END
  END tap_d[134]
  PIN tap_d[135]
    DIRECTION OUTPUT ;
    USE SIGNAL ;
    PORT
      LAYER M4 ;
        RECT  0 40.416 0.084 40.44 ;
    END
  END tap_d[135]
  PIN tap_d[136]
    DIRECTION OUTPUT ;
    USE SIGNAL ;
    PORT
      LAYER M4 ;
        RECT  0 40.512 0.084 40.536 ;
    END
  END tap_d[136]
  PIN tap_d[137]
    DIRECTION OUTPUT ;
    USE SIGNAL ;
    PORT
      LAYER M4 ;
        RECT  0 40.608 0.084 40.632 ;
    END
  END tap_d[137]
  PIN tap_d[138]
    DIRECTION OUTPUT ;
    USE SIGNAL ;
    PORT
      LAYER M4 ;
        RECT  0 40.704 0.084 40.728 ;
    END
  END tap_d[138]
  PIN tap_d[139]
    DIRECTION OUTPUT ;
    USE SIGNAL ;
    PORT
      LAYER M4 ;
        RECT  0 40.8 0.084 40.824 ;
    END
  END tap_d[139]
  PIN tap_d[13]
    DIRECTION OUTPUT ;
    USE SIGNAL ;
    PORT
      LAYER M4 ;
        RECT  0 28.272 0.084 28.296 ;
    END
  END tap_d[13]
  PIN tap_d[140]
    DIRECTION OUTPUT ;
    USE SIGNAL ;
    PORT
      LAYER M4 ;
        RECT  0 40.896 0.084 40.92 ;
    END
  END tap_d[140]
  PIN tap_d[141]
    DIRECTION OUTPUT ;
    USE SIGNAL ;
    PORT
      LAYER M4 ;
        RECT  0 40.992 0.084 41.016 ;
    END
  END tap_d[141]
  PIN tap_d[142]
    DIRECTION OUTPUT ;
    USE SIGNAL ;
    PORT
      LAYER M4 ;
        RECT  0 41.088 0.084 41.112 ;
    END
  END tap_d[142]
  PIN tap_d[143]
    DIRECTION OUTPUT ;
    USE SIGNAL ;
    PORT
      LAYER M4 ;
        RECT  0 41.184 0.084 41.208 ;
    END
  END tap_d[143]
  PIN tap_d[144]
    DIRECTION OUTPUT ;
    USE SIGNAL ;
    PORT
      LAYER M4 ;
        RECT  0 41.28 0.084 41.304 ;
    END
  END tap_d[144]
  PIN tap_d[145]
    DIRECTION OUTPUT ;
    USE SIGNAL ;
    PORT
      LAYER M4 ;
        RECT  0 41.376 0.084 41.4 ;
    END
  END tap_d[145]
  PIN tap_d[146]
    DIRECTION OUTPUT ;
    USE SIGNAL ;
    PORT
      LAYER M4 ;
        RECT  0 41.472 0.084 41.496 ;
    END
  END tap_d[146]
  PIN tap_d[147]
    DIRECTION OUTPUT ;
    USE SIGNAL ;
    PORT
      LAYER M4 ;
        RECT  0 41.568 0.084 41.592 ;
    END
  END tap_d[147]
  PIN tap_d[148]
    DIRECTION OUTPUT ;
    USE SIGNAL ;
    PORT
      LAYER M4 ;
        RECT  0 41.712 0.084 41.736 ;
    END
  END tap_d[148]
  PIN tap_d[149]
    DIRECTION OUTPUT ;
    USE SIGNAL ;
    PORT
      LAYER M4 ;
        RECT  0 41.808 0.084 41.832 ;
    END
  END tap_d[149]
  PIN tap_d[14]
    DIRECTION OUTPUT ;
    USE SIGNAL ;
    PORT
      LAYER M4 ;
        RECT  0 28.368 0.084 28.392 ;
    END
  END tap_d[14]
  PIN tap_d[150]
    DIRECTION OUTPUT ;
    USE SIGNAL ;
    PORT
      LAYER M4 ;
        RECT  0 41.904 0.084 41.928 ;
    END
  END tap_d[150]
  PIN tap_d[151]
    DIRECTION OUTPUT ;
    USE SIGNAL ;
    PORT
      LAYER M4 ;
        RECT  0 42 0.084 42.024 ;
    END
  END tap_d[151]
  PIN tap_d[152]
    DIRECTION OUTPUT ;
    USE SIGNAL ;
    PORT
      LAYER M4 ;
        RECT  0 42.096 0.084 42.12 ;
    END
  END tap_d[152]
  PIN tap_d[153]
    DIRECTION OUTPUT ;
    USE SIGNAL ;
    PORT
      LAYER M4 ;
        RECT  0 42.192 0.084 42.216 ;
    END
  END tap_d[153]
  PIN tap_d[154]
    DIRECTION OUTPUT ;
    USE SIGNAL ;
    PORT
      LAYER M4 ;
        RECT  0 42.288 0.084 42.312 ;
    END
  END tap_d[154]
  PIN tap_d[155]
    DIRECTION OUTPUT ;
    USE SIGNAL ;
    PORT
      LAYER M4 ;
        RECT  0 42.384 0.084 42.408 ;
    END
  END tap_d[155]
  PIN tap_d[156]
    DIRECTION OUTPUT ;
    USE SIGNAL ;
    PORT
      LAYER M4 ;
        RECT  0 42.48 0.084 42.504 ;
    END
  END tap_d[156]
  PIN tap_d[157]
    DIRECTION OUTPUT ;
    USE SIGNAL ;
    PORT
      LAYER M4 ;
        RECT  0 42.576 0.084 42.6 ;
    END
  END tap_d[157]
  PIN tap_d[158]
    DIRECTION OUTPUT ;
    USE SIGNAL ;
    PORT
      LAYER M4 ;
        RECT  0 42.672 0.084 42.696 ;
    END
  END tap_d[158]
  PIN tap_d[159]
    DIRECTION OUTPUT ;
    USE SIGNAL ;
    PORT
      LAYER M4 ;
        RECT  0 42.768 0.084 42.792 ;
    END
  END tap_d[159]
  PIN tap_d[15]
    DIRECTION OUTPUT ;
    USE SIGNAL ;
    PORT
      LAYER M4 ;
        RECT  0 28.464 0.084 28.488 ;
    END
  END tap_d[15]
  PIN tap_d[160]
    DIRECTION OUTPUT ;
    USE SIGNAL ;
    PORT
      LAYER M4 ;
        RECT  0 42.864 0.084 42.888 ;
    END
  END tap_d[160]
  PIN tap_d[161]
    DIRECTION OUTPUT ;
    USE SIGNAL ;
    PORT
      LAYER M4 ;
        RECT  0 42.96 0.084 42.984 ;
    END
  END tap_d[161]
  PIN tap_d[162]
    DIRECTION OUTPUT ;
    USE SIGNAL ;
    PORT
      LAYER M4 ;
        RECT  0 43.104 0.084 43.128 ;
    END
  END tap_d[162]
  PIN tap_d[163]
    DIRECTION OUTPUT ;
    USE SIGNAL ;
    PORT
      LAYER M4 ;
        RECT  0 43.2 0.084 43.224 ;
    END
  END tap_d[163]
  PIN tap_d[164]
    DIRECTION OUTPUT ;
    USE SIGNAL ;
    PORT
      LAYER M4 ;
        RECT  0 43.296 0.084 43.32 ;
    END
  END tap_d[164]
  PIN tap_d[165]
    DIRECTION OUTPUT ;
    USE SIGNAL ;
    PORT
      LAYER M4 ;
        RECT  0 43.392 0.084 43.416 ;
    END
  END tap_d[165]
  PIN tap_d[166]
    DIRECTION OUTPUT ;
    USE SIGNAL ;
    PORT
      LAYER M4 ;
        RECT  0 43.488 0.084 43.512 ;
    END
  END tap_d[166]
  PIN tap_d[167]
    DIRECTION OUTPUT ;
    USE SIGNAL ;
    PORT
      LAYER M4 ;
        RECT  0 43.584 0.084 43.608 ;
    END
  END tap_d[167]
  PIN tap_d[168]
    DIRECTION OUTPUT ;
    USE SIGNAL ;
    PORT
      LAYER M4 ;
        RECT  0 43.68 0.084 43.704 ;
    END
  END tap_d[168]
  PIN tap_d[169]
    DIRECTION OUTPUT ;
    USE SIGNAL ;
    PORT
      LAYER M4 ;
        RECT  0 43.776 0.084 43.8 ;
    END
  END tap_d[169]
  PIN tap_d[16]
    DIRECTION OUTPUT ;
    USE SIGNAL ;
    PORT
      LAYER M4 ;
        RECT  0 28.56 0.084 28.584 ;
    END
  END tap_d[16]
  PIN tap_d[170]
    DIRECTION OUTPUT ;
    USE SIGNAL ;
    PORT
      LAYER M4 ;
        RECT  0 43.872 0.084 43.896 ;
    END
  END tap_d[170]
  PIN tap_d[171]
    DIRECTION OUTPUT ;
    USE SIGNAL ;
    PORT
      LAYER M4 ;
        RECT  0 43.968 0.084 43.992 ;
    END
  END tap_d[171]
  PIN tap_d[172]
    DIRECTION OUTPUT ;
    USE SIGNAL ;
    PORT
      LAYER M4 ;
        RECT  0 44.064 0.084 44.088 ;
    END
  END tap_d[172]
  PIN tap_d[173]
    DIRECTION OUTPUT ;
    USE SIGNAL ;
    PORT
      LAYER M4 ;
        RECT  0 44.16 0.084 44.184 ;
    END
  END tap_d[173]
  PIN tap_d[174]
    DIRECTION OUTPUT ;
    USE SIGNAL ;
    PORT
      LAYER M4 ;
        RECT  0 44.256 0.084 44.28 ;
    END
  END tap_d[174]
  PIN tap_d[175]
    DIRECTION OUTPUT ;
    USE SIGNAL ;
    PORT
      LAYER M4 ;
        RECT  0 44.352 0.084 44.376 ;
    END
  END tap_d[175]
  PIN tap_d[176]
    DIRECTION OUTPUT ;
    USE SIGNAL ;
    PORT
      LAYER M4 ;
        RECT  0 44.496 0.084 44.52 ;
    END
  END tap_d[176]
  PIN tap_d[177]
    DIRECTION OUTPUT ;
    USE SIGNAL ;
    PORT
      LAYER M4 ;
        RECT  0 44.592 0.084 44.616 ;
    END
  END tap_d[177]
  PIN tap_d[178]
    DIRECTION OUTPUT ;
    USE SIGNAL ;
    PORT
      LAYER M4 ;
        RECT  0 44.688 0.084 44.712 ;
    END
  END tap_d[178]
  PIN tap_d[179]
    DIRECTION OUTPUT ;
    USE SIGNAL ;
    PORT
      LAYER M4 ;
        RECT  0 44.784 0.084 44.808 ;
    END
  END tap_d[179]
  PIN tap_d[17]
    DIRECTION OUTPUT ;
    USE SIGNAL ;
    PORT
      LAYER M4 ;
        RECT  0 28.656 0.084 28.68 ;
    END
  END tap_d[17]
  PIN tap_d[180]
    DIRECTION OUTPUT ;
    USE SIGNAL ;
    PORT
      LAYER M4 ;
        RECT  0 44.88 0.084 44.904 ;
    END
  END tap_d[180]
  PIN tap_d[181]
    DIRECTION OUTPUT ;
    USE SIGNAL ;
    PORT
      LAYER M4 ;
        RECT  0 44.976 0.084 45 ;
    END
  END tap_d[181]
  PIN tap_d[182]
    DIRECTION OUTPUT ;
    USE SIGNAL ;
    PORT
      LAYER M4 ;
        RECT  0 45.072 0.084 45.096 ;
    END
  END tap_d[182]
  PIN tap_d[183]
    DIRECTION OUTPUT ;
    USE SIGNAL ;
    PORT
      LAYER M4 ;
        RECT  0 45.168 0.084 45.192 ;
    END
  END tap_d[183]
  PIN tap_d[184]
    DIRECTION OUTPUT ;
    USE SIGNAL ;
    PORT
      LAYER M4 ;
        RECT  0 45.264 0.084 45.288 ;
    END
  END tap_d[184]
  PIN tap_d[185]
    DIRECTION OUTPUT ;
    USE SIGNAL ;
    PORT
      LAYER M4 ;
        RECT  0 45.36 0.084 45.384 ;
    END
  END tap_d[185]
  PIN tap_d[186]
    DIRECTION OUTPUT ;
    USE SIGNAL ;
    PORT
      LAYER M4 ;
        RECT  0 45.456 0.084 45.48 ;
    END
  END tap_d[186]
  PIN tap_d[187]
    DIRECTION OUTPUT ;
    USE SIGNAL ;
    PORT
      LAYER M4 ;
        RECT  0 45.552 0.084 45.576 ;
    END
  END tap_d[187]
  PIN tap_d[188]
    DIRECTION OUTPUT ;
    USE SIGNAL ;
    PORT
      LAYER M4 ;
        RECT  0 45.648 0.084 45.672 ;
    END
  END tap_d[188]
  PIN tap_d[189]
    DIRECTION OUTPUT ;
    USE SIGNAL ;
    PORT
      LAYER M4 ;
        RECT  0 45.744 0.084 45.768 ;
    END
  END tap_d[189]
  PIN tap_d[18]
    DIRECTION OUTPUT ;
    USE SIGNAL ;
    PORT
      LAYER M4 ;
        RECT  0 28.752 0.084 28.776 ;
    END
  END tap_d[18]
  PIN tap_d[190]
    DIRECTION OUTPUT ;
    USE SIGNAL ;
    PORT
      LAYER M4 ;
        RECT  0 45.888 0.084 45.912 ;
    END
  END tap_d[190]
  PIN tap_d[191]
    DIRECTION OUTPUT ;
    USE SIGNAL ;
    PORT
      LAYER M4 ;
        RECT  0 45.984 0.084 46.008 ;
    END
  END tap_d[191]
  PIN tap_d[192]
    DIRECTION OUTPUT ;
    USE SIGNAL ;
    PORT
      LAYER M4 ;
        RECT  0 46.08 0.084 46.104 ;
    END
  END tap_d[192]
  PIN tap_d[193]
    DIRECTION OUTPUT ;
    USE SIGNAL ;
    PORT
      LAYER M4 ;
        RECT  0 46.176 0.084 46.2 ;
    END
  END tap_d[193]
  PIN tap_d[194]
    DIRECTION OUTPUT ;
    USE SIGNAL ;
    PORT
      LAYER M4 ;
        RECT  0 46.272 0.084 46.296 ;
    END
  END tap_d[194]
  PIN tap_d[195]
    DIRECTION OUTPUT ;
    USE SIGNAL ;
    PORT
      LAYER M4 ;
        RECT  0 46.368 0.084 46.392 ;
    END
  END tap_d[195]
  PIN tap_d[196]
    DIRECTION OUTPUT ;
    USE SIGNAL ;
    PORT
      LAYER M4 ;
        RECT  0 46.464 0.084 46.488 ;
    END
  END tap_d[196]
  PIN tap_d[197]
    DIRECTION OUTPUT ;
    USE SIGNAL ;
    PORT
      LAYER M4 ;
        RECT  0 46.56 0.084 46.584 ;
    END
  END tap_d[197]
  PIN tap_d[198]
    DIRECTION OUTPUT ;
    USE SIGNAL ;
    PORT
      LAYER M4 ;
        RECT  0 46.656 0.084 46.68 ;
    END
  END tap_d[198]
  PIN tap_d[199]
    DIRECTION OUTPUT ;
    USE SIGNAL ;
    PORT
      LAYER M4 ;
        RECT  0 46.752 0.084 46.776 ;
    END
  END tap_d[199]
  PIN tap_d[19]
    DIRECTION OUTPUT ;
    USE SIGNAL ;
    PORT
      LAYER M4 ;
        RECT  0 28.848 0.084 28.872 ;
    END
  END tap_d[19]
  PIN tap_d[1]
    DIRECTION OUTPUT ;
    USE SIGNAL ;
    PORT
      LAYER M4 ;
        RECT  0 27.072 0.084 27.096 ;
    END
  END tap_d[1]
  PIN tap_d[200]
    DIRECTION OUTPUT ;
    USE SIGNAL ;
    PORT
      LAYER M4 ;
        RECT  0 46.848 0.084 46.872 ;
    END
  END tap_d[200]
  PIN tap_d[201]
    DIRECTION OUTPUT ;
    USE SIGNAL ;
    PORT
      LAYER M4 ;
        RECT  0 46.944 0.084 46.968 ;
    END
  END tap_d[201]
  PIN tap_d[202]
    DIRECTION OUTPUT ;
    USE SIGNAL ;
    PORT
      LAYER M4 ;
        RECT  0 47.04 0.084 47.064 ;
    END
  END tap_d[202]
  PIN tap_d[203]
    DIRECTION OUTPUT ;
    USE SIGNAL ;
    PORT
      LAYER M4 ;
        RECT  0 47.136 0.084 47.16 ;
    END
  END tap_d[203]
  PIN tap_d[204]
    DIRECTION OUTPUT ;
    USE SIGNAL ;
    PORT
      LAYER M4 ;
        RECT  0 47.28 0.084 47.304 ;
    END
  END tap_d[204]
  PIN tap_d[205]
    DIRECTION OUTPUT ;
    USE SIGNAL ;
    PORT
      LAYER M4 ;
        RECT  0 47.376 0.084 47.4 ;
    END
  END tap_d[205]
  PIN tap_d[206]
    DIRECTION OUTPUT ;
    USE SIGNAL ;
    PORT
      LAYER M4 ;
        RECT  0 47.472 0.084 47.496 ;
    END
  END tap_d[206]
  PIN tap_d[207]
    DIRECTION OUTPUT ;
    USE SIGNAL ;
    PORT
      LAYER M4 ;
        RECT  0 47.568 0.084 47.592 ;
    END
  END tap_d[207]
  PIN tap_d[208]
    DIRECTION OUTPUT ;
    USE SIGNAL ;
    PORT
      LAYER M4 ;
        RECT  0 47.664 0.084 47.688 ;
    END
  END tap_d[208]
  PIN tap_d[209]
    DIRECTION OUTPUT ;
    USE SIGNAL ;
    PORT
      LAYER M4 ;
        RECT  0 47.76 0.084 47.784 ;
    END
  END tap_d[209]
  PIN tap_d[20]
    DIRECTION OUTPUT ;
    USE SIGNAL ;
    PORT
      LAYER M4 ;
        RECT  0 28.944 0.084 28.968 ;
    END
  END tap_d[20]
  PIN tap_d[210]
    DIRECTION OUTPUT ;
    USE SIGNAL ;
    PORT
      LAYER M4 ;
        RECT  0 47.856 0.084 47.88 ;
    END
  END tap_d[210]
  PIN tap_d[211]
    DIRECTION OUTPUT ;
    USE SIGNAL ;
    PORT
      LAYER M4 ;
        RECT  0 47.952 0.084 47.976 ;
    END
  END tap_d[211]
  PIN tap_d[212]
    DIRECTION OUTPUT ;
    USE SIGNAL ;
    PORT
      LAYER M4 ;
        RECT  0 48.048 0.084 48.072 ;
    END
  END tap_d[212]
  PIN tap_d[213]
    DIRECTION OUTPUT ;
    USE SIGNAL ;
    PORT
      LAYER M4 ;
        RECT  0 48.144 0.084 48.168 ;
    END
  END tap_d[213]
  PIN tap_d[214]
    DIRECTION OUTPUT ;
    USE SIGNAL ;
    PORT
      LAYER M4 ;
        RECT  0 48.24 0.084 48.264 ;
    END
  END tap_d[214]
  PIN tap_d[215]
    DIRECTION OUTPUT ;
    USE SIGNAL ;
    PORT
      LAYER M4 ;
        RECT  0 48.336 0.084 48.36 ;
    END
  END tap_d[215]
  PIN tap_d[216]
    DIRECTION OUTPUT ;
    USE SIGNAL ;
    PORT
      LAYER M4 ;
        RECT  0 48.432 0.084 48.456 ;
    END
  END tap_d[216]
  PIN tap_d[217]
    DIRECTION OUTPUT ;
    USE SIGNAL ;
    PORT
      LAYER M4 ;
        RECT  0 48.528 0.084 48.552 ;
    END
  END tap_d[217]
  PIN tap_d[218]
    DIRECTION OUTPUT ;
    USE SIGNAL ;
    PORT
      LAYER M4 ;
        RECT  0 48.624 0.084 48.648 ;
    END
  END tap_d[218]
  PIN tap_d[219]
    DIRECTION OUTPUT ;
    USE SIGNAL ;
    PORT
      LAYER M4 ;
        RECT  0 48.768 0.084 48.792 ;
    END
  END tap_d[219]
  PIN tap_d[21]
    DIRECTION OUTPUT ;
    USE SIGNAL ;
    PORT
      LAYER M4 ;
        RECT  0 29.088 0.084 29.112 ;
    END
  END tap_d[21]
  PIN tap_d[220]
    DIRECTION OUTPUT ;
    USE SIGNAL ;
    PORT
      LAYER M4 ;
        RECT  0 48.864 0.084 48.888 ;
    END
  END tap_d[220]
  PIN tap_d[221]
    DIRECTION OUTPUT ;
    USE SIGNAL ;
    PORT
      LAYER M4 ;
        RECT  0 48.96 0.084 48.984 ;
    END
  END tap_d[221]
  PIN tap_d[222]
    DIRECTION OUTPUT ;
    USE SIGNAL ;
    PORT
      LAYER M4 ;
        RECT  0 49.056 0.084 49.08 ;
    END
  END tap_d[222]
  PIN tap_d[223]
    DIRECTION OUTPUT ;
    USE SIGNAL ;
    PORT
      LAYER M4 ;
        RECT  0 49.152 0.084 49.176 ;
    END
  END tap_d[223]
  PIN tap_d[224]
    DIRECTION OUTPUT ;
    USE SIGNAL ;
    PORT
      LAYER M4 ;
        RECT  0 49.248 0.084 49.272 ;
    END
  END tap_d[224]
  PIN tap_d[225]
    DIRECTION OUTPUT ;
    USE SIGNAL ;
    PORT
      LAYER M4 ;
        RECT  0 49.344 0.084 49.368 ;
    END
  END tap_d[225]
  PIN tap_d[226]
    DIRECTION OUTPUT ;
    USE SIGNAL ;
    PORT
      LAYER M4 ;
        RECT  0 49.44 0.084 49.464 ;
    END
  END tap_d[226]
  PIN tap_d[227]
    DIRECTION OUTPUT ;
    USE SIGNAL ;
    PORT
      LAYER M4 ;
        RECT  0 49.536 0.084 49.56 ;
    END
  END tap_d[227]
  PIN tap_d[228]
    DIRECTION OUTPUT ;
    USE SIGNAL ;
    PORT
      LAYER M4 ;
        RECT  0 49.632 0.084 49.656 ;
    END
  END tap_d[228]
  PIN tap_d[229]
    DIRECTION OUTPUT ;
    USE SIGNAL ;
    PORT
      LAYER M4 ;
        RECT  0 49.728 0.084 49.752 ;
    END
  END tap_d[229]
  PIN tap_d[22]
    DIRECTION OUTPUT ;
    USE SIGNAL ;
    PORT
      LAYER M4 ;
        RECT  0 29.184 0.084 29.208 ;
    END
  END tap_d[22]
  PIN tap_d[230]
    DIRECTION OUTPUT ;
    USE SIGNAL ;
    PORT
      LAYER M4 ;
        RECT  0 49.824 0.084 49.848 ;
    END
  END tap_d[230]
  PIN tap_d[231]
    DIRECTION OUTPUT ;
    USE SIGNAL ;
    PORT
      LAYER M4 ;
        RECT  0 49.92 0.084 49.944 ;
    END
  END tap_d[231]
  PIN tap_d[232]
    DIRECTION OUTPUT ;
    USE SIGNAL ;
    PORT
      LAYER M4 ;
        RECT  0 50.016 0.084 50.04 ;
    END
  END tap_d[232]
  PIN tap_d[233]
    DIRECTION OUTPUT ;
    USE SIGNAL ;
    PORT
      LAYER M4 ;
        RECT  0 50.16 0.084 50.184 ;
    END
  END tap_d[233]
  PIN tap_d[234]
    DIRECTION OUTPUT ;
    USE SIGNAL ;
    PORT
      LAYER M4 ;
        RECT  0 50.256 0.084 50.28 ;
    END
  END tap_d[234]
  PIN tap_d[235]
    DIRECTION OUTPUT ;
    USE SIGNAL ;
    PORT
      LAYER M4 ;
        RECT  0 50.352 0.084 50.376 ;
    END
  END tap_d[235]
  PIN tap_d[236]
    DIRECTION OUTPUT ;
    USE SIGNAL ;
    PORT
      LAYER M4 ;
        RECT  0 50.448 0.084 50.472 ;
    END
  END tap_d[236]
  PIN tap_d[237]
    DIRECTION OUTPUT ;
    USE SIGNAL ;
    PORT
      LAYER M4 ;
        RECT  0 50.544 0.084 50.568 ;
    END
  END tap_d[237]
  PIN tap_d[238]
    DIRECTION OUTPUT ;
    USE SIGNAL ;
    PORT
      LAYER M4 ;
        RECT  0 50.64 0.084 50.664 ;
    END
  END tap_d[238]
  PIN tap_d[239]
    DIRECTION OUTPUT ;
    USE SIGNAL ;
    PORT
      LAYER M4 ;
        RECT  0 50.736 0.084 50.76 ;
    END
  END tap_d[239]
  PIN tap_d[23]
    DIRECTION OUTPUT ;
    USE SIGNAL ;
    PORT
      LAYER M4 ;
        RECT  0 29.28 0.084 29.304 ;
    END
  END tap_d[23]
  PIN tap_d[240]
    DIRECTION OUTPUT ;
    USE SIGNAL ;
    PORT
      LAYER M4 ;
        RECT  0 50.832 0.084 50.856 ;
    END
  END tap_d[240]
  PIN tap_d[241]
    DIRECTION OUTPUT ;
    USE SIGNAL ;
    PORT
      LAYER M4 ;
        RECT  0 50.928 0.084 50.952 ;
    END
  END tap_d[241]
  PIN tap_d[242]
    DIRECTION OUTPUT ;
    USE SIGNAL ;
    PORT
      LAYER M4 ;
        RECT  0 51.024 0.084 51.048 ;
    END
  END tap_d[242]
  PIN tap_d[243]
    DIRECTION OUTPUT ;
    USE SIGNAL ;
    PORT
      LAYER M4 ;
        RECT  0 51.12 0.084 51.144 ;
    END
  END tap_d[243]
  PIN tap_d[244]
    DIRECTION OUTPUT ;
    USE SIGNAL ;
    PORT
      LAYER M4 ;
        RECT  0 51.216 0.084 51.24 ;
    END
  END tap_d[244]
  PIN tap_d[245]
    DIRECTION OUTPUT ;
    USE SIGNAL ;
    PORT
      LAYER M4 ;
        RECT  0 51.312 0.084 51.336 ;
    END
  END tap_d[245]
  PIN tap_d[246]
    DIRECTION OUTPUT ;
    USE SIGNAL ;
    PORT
      LAYER M4 ;
        RECT  0 51.408 0.084 51.432 ;
    END
  END tap_d[246]
  PIN tap_d[247]
    DIRECTION OUTPUT ;
    USE SIGNAL ;
    PORT
      LAYER M4 ;
        RECT  0 51.552 0.084 51.576 ;
    END
  END tap_d[247]
  PIN tap_d[248]
    DIRECTION OUTPUT ;
    USE SIGNAL ;
    PORT
      LAYER M4 ;
        RECT  0 51.648 0.084 51.672 ;
    END
  END tap_d[248]
  PIN tap_d[249]
    DIRECTION OUTPUT ;
    USE SIGNAL ;
    PORT
      LAYER M4 ;
        RECT  0 51.744 0.084 51.768 ;
    END
  END tap_d[249]
  PIN tap_d[24]
    DIRECTION OUTPUT ;
    USE SIGNAL ;
    PORT
      LAYER M4 ;
        RECT  0 29.376 0.084 29.4 ;
    END
  END tap_d[24]
  PIN tap_d[250]
    DIRECTION OUTPUT ;
    USE SIGNAL ;
    PORT
      LAYER M4 ;
        RECT  0 51.84 0.084 51.864 ;
    END
  END tap_d[250]
  PIN tap_d[251]
    DIRECTION OUTPUT ;
    USE SIGNAL ;
    PORT
      LAYER M4 ;
        RECT  0 51.936 0.084 51.96 ;
    END
  END tap_d[251]
  PIN tap_d[252]
    DIRECTION OUTPUT ;
    USE SIGNAL ;
    PORT
      LAYER M4 ;
        RECT  0 52.032 0.084 52.056 ;
    END
  END tap_d[252]
  PIN tap_d[253]
    DIRECTION OUTPUT ;
    USE SIGNAL ;
    PORT
      LAYER M4 ;
        RECT  0 52.128 0.084 52.152 ;
    END
  END tap_d[253]
  PIN tap_d[254]
    DIRECTION OUTPUT ;
    USE SIGNAL ;
    PORT
      LAYER M4 ;
        RECT  0 52.224 0.084 52.248 ;
    END
  END tap_d[254]
  PIN tap_d[255]
    DIRECTION OUTPUT ;
    USE SIGNAL ;
    PORT
      LAYER M4 ;
        RECT  0 52.32 0.084 52.344 ;
    END
  END tap_d[255]
  PIN tap_d[256]
    DIRECTION OUTPUT ;
    USE SIGNAL ;
    PORT
      LAYER M4 ;
        RECT  0 52.416 0.084 52.44 ;
    END
  END tap_d[256]
  PIN tap_d[257]
    DIRECTION OUTPUT ;
    USE SIGNAL ;
    PORT
      LAYER M4 ;
        RECT  0 52.512 0.084 52.536 ;
    END
  END tap_d[257]
  PIN tap_d[258]
    DIRECTION OUTPUT ;
    USE SIGNAL ;
    PORT
      LAYER M4 ;
        RECT  0 52.608 0.084 52.632 ;
    END
  END tap_d[258]
  PIN tap_d[259]
    DIRECTION OUTPUT ;
    USE SIGNAL ;
    PORT
      LAYER M4 ;
        RECT  0 52.704 0.084 52.728 ;
    END
  END tap_d[259]
  PIN tap_d[25]
    DIRECTION OUTPUT ;
    USE SIGNAL ;
    PORT
      LAYER M4 ;
        RECT  0 29.472 0.084 29.496 ;
    END
  END tap_d[25]
  PIN tap_d[260]
    DIRECTION OUTPUT ;
    USE SIGNAL ;
    PORT
      LAYER M4 ;
        RECT  0 52.8 0.084 52.824 ;
    END
  END tap_d[260]
  PIN tap_d[261]
    DIRECTION OUTPUT ;
    USE SIGNAL ;
    PORT
      LAYER M4 ;
        RECT  0 52.944 0.084 52.968 ;
    END
  END tap_d[261]
  PIN tap_d[262]
    DIRECTION OUTPUT ;
    USE SIGNAL ;
    PORT
      LAYER M4 ;
        RECT  0 53.04 0.084 53.064 ;
    END
  END tap_d[262]
  PIN tap_d[263]
    DIRECTION OUTPUT ;
    USE SIGNAL ;
    PORT
      LAYER M4 ;
        RECT  0 53.136 0.084 53.16 ;
    END
  END tap_d[263]
  PIN tap_d[264]
    DIRECTION OUTPUT ;
    USE SIGNAL ;
    PORT
      LAYER M4 ;
        RECT  0 53.232 0.084 53.256 ;
    END
  END tap_d[264]
  PIN tap_d[265]
    DIRECTION OUTPUT ;
    USE SIGNAL ;
    PORT
      LAYER M4 ;
        RECT  0 53.328 0.084 53.352 ;
    END
  END tap_d[265]
  PIN tap_d[266]
    DIRECTION OUTPUT ;
    USE SIGNAL ;
    PORT
      LAYER M4 ;
        RECT  0 53.424 0.084 53.448 ;
    END
  END tap_d[266]
  PIN tap_d[267]
    DIRECTION OUTPUT ;
    USE SIGNAL ;
    PORT
      LAYER M4 ;
        RECT  0 53.52 0.084 53.544 ;
    END
  END tap_d[267]
  PIN tap_d[268]
    DIRECTION OUTPUT ;
    USE SIGNAL ;
    PORT
      LAYER M4 ;
        RECT  0 53.616 0.084 53.64 ;
    END
  END tap_d[268]
  PIN tap_d[269]
    DIRECTION OUTPUT ;
    USE SIGNAL ;
    PORT
      LAYER M4 ;
        RECT  0 53.712 0.084 53.736 ;
    END
  END tap_d[269]
  PIN tap_d[26]
    DIRECTION OUTPUT ;
    USE SIGNAL ;
    PORT
      LAYER M4 ;
        RECT  0 29.568 0.084 29.592 ;
    END
  END tap_d[26]
  PIN tap_d[270]
    DIRECTION OUTPUT ;
    USE SIGNAL ;
    PORT
      LAYER M4 ;
        RECT  0 53.808 0.084 53.832 ;
    END
  END tap_d[270]
  PIN tap_d[271]
    DIRECTION OUTPUT ;
    USE SIGNAL ;
    PORT
      LAYER M4 ;
        RECT  0 53.904 0.084 53.928 ;
    END
  END tap_d[271]
  PIN tap_d[272]
    DIRECTION OUTPUT ;
    USE SIGNAL ;
    PORT
      LAYER M4 ;
        RECT  0 54 0.084 54.024 ;
    END
  END tap_d[272]
  PIN tap_d[273]
    DIRECTION OUTPUT ;
    USE SIGNAL ;
    PORT
      LAYER M4 ;
        RECT  0 54.096 0.084 54.12 ;
    END
  END tap_d[273]
  PIN tap_d[274]
    DIRECTION OUTPUT ;
    USE SIGNAL ;
    PORT
      LAYER M4 ;
        RECT  0 54.192 0.084 54.216 ;
    END
  END tap_d[274]
  PIN tap_d[275]
    DIRECTION OUTPUT ;
    USE SIGNAL ;
    PORT
      LAYER M4 ;
        RECT  0 54.336 0.084 54.36 ;
    END
  END tap_d[275]
  PIN tap_d[276]
    DIRECTION OUTPUT ;
    USE SIGNAL ;
    PORT
      LAYER M4 ;
        RECT  0 54.432 0.084 54.456 ;
    END
  END tap_d[276]
  PIN tap_d[277]
    DIRECTION OUTPUT ;
    USE SIGNAL ;
    PORT
      LAYER M4 ;
        RECT  0 54.528 0.084 54.552 ;
    END
  END tap_d[277]
  PIN tap_d[278]
    DIRECTION OUTPUT ;
    USE SIGNAL ;
    PORT
      LAYER M4 ;
        RECT  0 54.624 0.084 54.648 ;
    END
  END tap_d[278]
  PIN tap_d[279]
    DIRECTION OUTPUT ;
    USE SIGNAL ;
    PORT
      LAYER M4 ;
        RECT  0 54.72 0.084 54.744 ;
    END
  END tap_d[279]
  PIN tap_d[27]
    DIRECTION OUTPUT ;
    USE SIGNAL ;
    PORT
      LAYER M4 ;
        RECT  0 29.664 0.084 29.688 ;
    END
  END tap_d[27]
  PIN tap_d[280]
    DIRECTION OUTPUT ;
    USE SIGNAL ;
    PORT
      LAYER M4 ;
        RECT  0 54.816 0.084 54.84 ;
    END
  END tap_d[280]
  PIN tap_d[281]
    DIRECTION OUTPUT ;
    USE SIGNAL ;
    PORT
      LAYER M4 ;
        RECT  0 54.912 0.084 54.936 ;
    END
  END tap_d[281]
  PIN tap_d[282]
    DIRECTION OUTPUT ;
    USE SIGNAL ;
    PORT
      LAYER M4 ;
        RECT  0 55.008 0.084 55.032 ;
    END
  END tap_d[282]
  PIN tap_d[283]
    DIRECTION OUTPUT ;
    USE SIGNAL ;
    PORT
      LAYER M4 ;
        RECT  0 55.104 0.084 55.128 ;
    END
  END tap_d[283]
  PIN tap_d[284]
    DIRECTION OUTPUT ;
    USE SIGNAL ;
    PORT
      LAYER M4 ;
        RECT  0 55.2 0.084 55.224 ;
    END
  END tap_d[284]
  PIN tap_d[285]
    DIRECTION OUTPUT ;
    USE SIGNAL ;
    PORT
      LAYER M4 ;
        RECT  0 55.296 0.084 55.32 ;
    END
  END tap_d[285]
  PIN tap_d[286]
    DIRECTION OUTPUT ;
    USE SIGNAL ;
    PORT
      LAYER M4 ;
        RECT  0 55.392 0.084 55.416 ;
    END
  END tap_d[286]
  PIN tap_d[287]
    DIRECTION OUTPUT ;
    USE SIGNAL ;
    PORT
      LAYER M4 ;
        RECT  0 55.488 0.084 55.512 ;
    END
  END tap_d[287]
  PIN tap_d[288]
    DIRECTION OUTPUT ;
    USE SIGNAL ;
    PORT
      LAYER M4 ;
        RECT  0 55.584 0.084 55.608 ;
    END
  END tap_d[288]
  PIN tap_d[289]
    DIRECTION OUTPUT ;
    USE SIGNAL ;
    PORT
      LAYER M4 ;
        RECT  0 55.728 0.084 55.752 ;
    END
  END tap_d[289]
  PIN tap_d[28]
    DIRECTION OUTPUT ;
    USE SIGNAL ;
    PORT
      LAYER M4 ;
        RECT  0 29.76 0.084 29.784 ;
    END
  END tap_d[28]
  PIN tap_d[290]
    DIRECTION OUTPUT ;
    USE SIGNAL ;
    PORT
      LAYER M4 ;
        RECT  0 55.824 0.084 55.848 ;
    END
  END tap_d[290]
  PIN tap_d[291]
    DIRECTION OUTPUT ;
    USE SIGNAL ;
    PORT
      LAYER M4 ;
        RECT  0 55.92 0.084 55.944 ;
    END
  END tap_d[291]
  PIN tap_d[292]
    DIRECTION OUTPUT ;
    USE SIGNAL ;
    PORT
      LAYER M4 ;
        RECT  0 56.016 0.084 56.04 ;
    END
  END tap_d[292]
  PIN tap_d[293]
    DIRECTION OUTPUT ;
    USE SIGNAL ;
    PORT
      LAYER M4 ;
        RECT  0 56.112 0.084 56.136 ;
    END
  END tap_d[293]
  PIN tap_d[294]
    DIRECTION OUTPUT ;
    USE SIGNAL ;
    PORT
      LAYER M4 ;
        RECT  0 56.208 0.084 56.232 ;
    END
  END tap_d[294]
  PIN tap_d[295]
    DIRECTION OUTPUT ;
    USE SIGNAL ;
    PORT
      LAYER M4 ;
        RECT  0 56.304 0.084 56.328 ;
    END
  END tap_d[295]
  PIN tap_d[296]
    DIRECTION OUTPUT ;
    USE SIGNAL ;
    PORT
      LAYER M4 ;
        RECT  0 56.4 0.084 56.424 ;
    END
  END tap_d[296]
  PIN tap_d[297]
    DIRECTION OUTPUT ;
    USE SIGNAL ;
    PORT
      LAYER M4 ;
        RECT  0 56.496 0.084 56.52 ;
    END
  END tap_d[297]
  PIN tap_d[298]
    DIRECTION OUTPUT ;
    USE SIGNAL ;
    PORT
      LAYER M4 ;
        RECT  0 56.592 0.084 56.616 ;
    END
  END tap_d[298]
  PIN tap_d[299]
    DIRECTION OUTPUT ;
    USE SIGNAL ;
    PORT
      LAYER M4 ;
        RECT  0 56.688 0.084 56.712 ;
    END
  END tap_d[299]
  PIN tap_d[29]
    DIRECTION OUTPUT ;
    USE SIGNAL ;
    PORT
      LAYER M4 ;
        RECT  0 29.856 0.084 29.88 ;
    END
  END tap_d[29]
  PIN tap_d[2]
    DIRECTION OUTPUT ;
    USE SIGNAL ;
    PORT
      LAYER M4 ;
        RECT  0 27.168 0.084 27.192 ;
    END
  END tap_d[2]
  PIN tap_d[300]
    DIRECTION OUTPUT ;
    USE SIGNAL ;
    PORT
      LAYER M4 ;
        RECT  0 56.784 0.084 56.808 ;
    END
  END tap_d[300]
  PIN tap_d[301]
    DIRECTION OUTPUT ;
    USE SIGNAL ;
    PORT
      LAYER M4 ;
        RECT  0 56.88 0.084 56.904 ;
    END
  END tap_d[301]
  PIN tap_d[302]
    DIRECTION OUTPUT ;
    USE SIGNAL ;
    PORT
      LAYER M4 ;
        RECT  0 56.976 0.084 57 ;
    END
  END tap_d[302]
  PIN tap_d[303]
    DIRECTION OUTPUT ;
    USE SIGNAL ;
    PORT
      LAYER M4 ;
        RECT  0 57.12 0.084 57.144 ;
    END
  END tap_d[303]
  PIN tap_d[304]
    DIRECTION OUTPUT ;
    USE SIGNAL ;
    PORT
      LAYER M4 ;
        RECT  0 57.216 0.084 57.24 ;
    END
  END tap_d[304]
  PIN tap_d[305]
    DIRECTION OUTPUT ;
    USE SIGNAL ;
    PORT
      LAYER M4 ;
        RECT  0 57.312 0.084 57.336 ;
    END
  END tap_d[305]
  PIN tap_d[306]
    DIRECTION OUTPUT ;
    USE SIGNAL ;
    PORT
      LAYER M4 ;
        RECT  0 57.408 0.084 57.432 ;
    END
  END tap_d[306]
  PIN tap_d[307]
    DIRECTION OUTPUT ;
    USE SIGNAL ;
    PORT
      LAYER M4 ;
        RECT  0 57.504 0.084 57.528 ;
    END
  END tap_d[307]
  PIN tap_d[308]
    DIRECTION OUTPUT ;
    USE SIGNAL ;
    PORT
      LAYER M4 ;
        RECT  0 57.6 0.084 57.624 ;
    END
  END tap_d[308]
  PIN tap_d[309]
    DIRECTION OUTPUT ;
    USE SIGNAL ;
    PORT
      LAYER M4 ;
        RECT  0 57.696 0.084 57.72 ;
    END
  END tap_d[309]
  PIN tap_d[30]
    DIRECTION OUTPUT ;
    USE SIGNAL ;
    PORT
      LAYER M4 ;
        RECT  0 29.952 0.084 29.976 ;
    END
  END tap_d[30]
  PIN tap_d[310]
    DIRECTION OUTPUT ;
    USE SIGNAL ;
    PORT
      LAYER M4 ;
        RECT  0 57.792 0.084 57.816 ;
    END
  END tap_d[310]
  PIN tap_d[311]
    DIRECTION OUTPUT ;
    USE SIGNAL ;
    PORT
      LAYER M4 ;
        RECT  0 57.888 0.084 57.912 ;
    END
  END tap_d[311]
  PIN tap_d[312]
    DIRECTION OUTPUT ;
    USE SIGNAL ;
    PORT
      LAYER M4 ;
        RECT  0 57.984 0.084 58.008 ;
    END
  END tap_d[312]
  PIN tap_d[313]
    DIRECTION OUTPUT ;
    USE SIGNAL ;
    PORT
      LAYER M4 ;
        RECT  0 58.08 0.084 58.104 ;
    END
  END tap_d[313]
  PIN tap_d[314]
    DIRECTION OUTPUT ;
    USE SIGNAL ;
    PORT
      LAYER M4 ;
        RECT  0 58.176 0.084 58.2 ;
    END
  END tap_d[314]
  PIN tap_d[315]
    DIRECTION OUTPUT ;
    USE SIGNAL ;
    PORT
      LAYER M4 ;
        RECT  0 58.272 0.084 58.296 ;
    END
  END tap_d[315]
  PIN tap_d[316]
    DIRECTION OUTPUT ;
    USE SIGNAL ;
    PORT
      LAYER M4 ;
        RECT  0 58.368 0.084 58.392 ;
    END
  END tap_d[316]
  PIN tap_d[317]
    DIRECTION OUTPUT ;
    USE SIGNAL ;
    PORT
      LAYER M4 ;
        RECT  0 58.512 0.084 58.536 ;
    END
  END tap_d[317]
  PIN tap_d[318]
    DIRECTION OUTPUT ;
    USE SIGNAL ;
    PORT
      LAYER M4 ;
        RECT  0 58.608 0.084 58.632 ;
    END
  END tap_d[318]
  PIN tap_d[319]
    DIRECTION OUTPUT ;
    USE SIGNAL ;
    PORT
      LAYER M4 ;
        RECT  0 58.704 0.084 58.728 ;
    END
  END tap_d[319]
  PIN tap_d[31]
    DIRECTION OUTPUT ;
    USE SIGNAL ;
    PORT
      LAYER M4 ;
        RECT  0 30.048 0.084 30.072 ;
    END
  END tap_d[31]
  PIN tap_d[320]
    DIRECTION OUTPUT ;
    USE SIGNAL ;
    PORT
      LAYER M4 ;
        RECT  0 58.8 0.084 58.824 ;
    END
  END tap_d[320]
  PIN tap_d[321]
    DIRECTION OUTPUT ;
    USE SIGNAL ;
    PORT
      LAYER M4 ;
        RECT  0 58.896 0.084 58.92 ;
    END
  END tap_d[321]
  PIN tap_d[322]
    DIRECTION OUTPUT ;
    USE SIGNAL ;
    PORT
      LAYER M4 ;
        RECT  0 58.992 0.084 59.016 ;
    END
  END tap_d[322]
  PIN tap_d[323]
    DIRECTION OUTPUT ;
    USE SIGNAL ;
    PORT
      LAYER M4 ;
        RECT  0 59.088 0.084 59.112 ;
    END
  END tap_d[323]
  PIN tap_d[324]
    DIRECTION OUTPUT ;
    USE SIGNAL ;
    PORT
      LAYER M4 ;
        RECT  0 59.184 0.084 59.208 ;
    END
  END tap_d[324]
  PIN tap_d[325]
    DIRECTION OUTPUT ;
    USE SIGNAL ;
    PORT
      LAYER M4 ;
        RECT  0 59.28 0.084 59.304 ;
    END
  END tap_d[325]
  PIN tap_d[326]
    DIRECTION OUTPUT ;
    USE SIGNAL ;
    PORT
      LAYER M4 ;
        RECT  0 59.376 0.084 59.4 ;
    END
  END tap_d[326]
  PIN tap_d[327]
    DIRECTION OUTPUT ;
    USE SIGNAL ;
    PORT
      LAYER M4 ;
        RECT  0 59.472 0.084 59.496 ;
    END
  END tap_d[327]
  PIN tap_d[328]
    DIRECTION OUTPUT ;
    USE SIGNAL ;
    PORT
      LAYER M4 ;
        RECT  0 59.568 0.084 59.592 ;
    END
  END tap_d[328]
  PIN tap_d[329]
    DIRECTION OUTPUT ;
    USE SIGNAL ;
    PORT
      LAYER M4 ;
        RECT  0 59.664 0.084 59.688 ;
    END
  END tap_d[329]
  PIN tap_d[32]
    DIRECTION OUTPUT ;
    USE SIGNAL ;
    PORT
      LAYER M4 ;
        RECT  0 30.144 0.084 30.168 ;
    END
  END tap_d[32]
  PIN tap_d[330]
    DIRECTION OUTPUT ;
    USE SIGNAL ;
    PORT
      LAYER M4 ;
        RECT  0 59.76 0.084 59.784 ;
    END
  END tap_d[330]
  PIN tap_d[331]
    DIRECTION OUTPUT ;
    USE SIGNAL ;
    PORT
      LAYER M4 ;
        RECT  0 59.904 0.084 59.928 ;
    END
  END tap_d[331]
  PIN tap_d[332]
    DIRECTION OUTPUT ;
    USE SIGNAL ;
    PORT
      LAYER M4 ;
        RECT  0 60 0.084 60.024 ;
    END
  END tap_d[332]
  PIN tap_d[333]
    DIRECTION OUTPUT ;
    USE SIGNAL ;
    PORT
      LAYER M4 ;
        RECT  0 60.096 0.084 60.12 ;
    END
  END tap_d[333]
  PIN tap_d[334]
    DIRECTION OUTPUT ;
    USE SIGNAL ;
    PORT
      LAYER M4 ;
        RECT  0 60.192 0.084 60.216 ;
    END
  END tap_d[334]
  PIN tap_d[335]
    DIRECTION OUTPUT ;
    USE SIGNAL ;
    PORT
      LAYER M4 ;
        RECT  0 60.288 0.084 60.312 ;
    END
  END tap_d[335]
  PIN tap_d[336]
    DIRECTION OUTPUT ;
    USE SIGNAL ;
    PORT
      LAYER M4 ;
        RECT  0 60.384 0.084 60.408 ;
    END
  END tap_d[336]
  PIN tap_d[337]
    DIRECTION OUTPUT ;
    USE SIGNAL ;
    PORT
      LAYER M4 ;
        RECT  0 60.48 0.084 60.504 ;
    END
  END tap_d[337]
  PIN tap_d[338]
    DIRECTION OUTPUT ;
    USE SIGNAL ;
    PORT
      LAYER M4 ;
        RECT  0 60.576 0.084 60.6 ;
    END
  END tap_d[338]
  PIN tap_d[339]
    DIRECTION OUTPUT ;
    USE SIGNAL ;
    PORT
      LAYER M4 ;
        RECT  0 60.672 0.084 60.696 ;
    END
  END tap_d[339]
  PIN tap_d[33]
    DIRECTION OUTPUT ;
    USE SIGNAL ;
    PORT
      LAYER M4 ;
        RECT  0 30.24 0.084 30.264 ;
    END
  END tap_d[33]
  PIN tap_d[340]
    DIRECTION OUTPUT ;
    USE SIGNAL ;
    PORT
      LAYER M4 ;
        RECT  0 60.768 0.084 60.792 ;
    END
  END tap_d[340]
  PIN tap_d[341]
    DIRECTION OUTPUT ;
    USE SIGNAL ;
    PORT
      LAYER M4 ;
        RECT  0 60.864 0.084 60.888 ;
    END
  END tap_d[341]
  PIN tap_d[342]
    DIRECTION OUTPUT ;
    USE SIGNAL ;
    PORT
      LAYER M4 ;
        RECT  0 60.96 0.084 60.984 ;
    END
  END tap_d[342]
  PIN tap_d[343]
    DIRECTION OUTPUT ;
    USE SIGNAL ;
    PORT
      LAYER M4 ;
        RECT  0 61.056 0.084 61.08 ;
    END
  END tap_d[343]
  PIN tap_d[344]
    DIRECTION OUTPUT ;
    USE SIGNAL ;
    PORT
      LAYER M4 ;
        RECT  0 61.152 0.084 61.176 ;
    END
  END tap_d[344]
  PIN tap_d[345]
    DIRECTION OUTPUT ;
    USE SIGNAL ;
    PORT
      LAYER M4 ;
        RECT  0 61.248 0.084 61.272 ;
    END
  END tap_d[345]
  PIN tap_d[346]
    DIRECTION OUTPUT ;
    USE SIGNAL ;
    PORT
      LAYER M4 ;
        RECT  0 61.392 0.084 61.416 ;
    END
  END tap_d[346]
  PIN tap_d[347]
    DIRECTION OUTPUT ;
    USE SIGNAL ;
    PORT
      LAYER M4 ;
        RECT  0 61.488 0.084 61.512 ;
    END
  END tap_d[347]
  PIN tap_d[348]
    DIRECTION OUTPUT ;
    USE SIGNAL ;
    PORT
      LAYER M4 ;
        RECT  0 61.584 0.084 61.608 ;
    END
  END tap_d[348]
  PIN tap_d[349]
    DIRECTION OUTPUT ;
    USE SIGNAL ;
    PORT
      LAYER M4 ;
        RECT  0 61.68 0.084 61.704 ;
    END
  END tap_d[349]
  PIN tap_d[34]
    DIRECTION OUTPUT ;
    USE SIGNAL ;
    PORT
      LAYER M4 ;
        RECT  0 30.336 0.084 30.36 ;
    END
  END tap_d[34]
  PIN tap_d[350]
    DIRECTION OUTPUT ;
    USE SIGNAL ;
    PORT
      LAYER M4 ;
        RECT  0 61.776 0.084 61.8 ;
    END
  END tap_d[350]
  PIN tap_d[351]
    DIRECTION OUTPUT ;
    USE SIGNAL ;
    PORT
      LAYER M4 ;
        RECT  0 61.872 0.084 61.896 ;
    END
  END tap_d[351]
  PIN tap_d[352]
    DIRECTION OUTPUT ;
    USE SIGNAL ;
    PORT
      LAYER M4 ;
        RECT  0 61.968 0.084 61.992 ;
    END
  END tap_d[352]
  PIN tap_d[353]
    DIRECTION OUTPUT ;
    USE SIGNAL ;
    PORT
      LAYER M4 ;
        RECT  0 62.064 0.084 62.088 ;
    END
  END tap_d[353]
  PIN tap_d[354]
    DIRECTION OUTPUT ;
    USE SIGNAL ;
    PORT
      LAYER M4 ;
        RECT  0 62.16 0.084 62.184 ;
    END
  END tap_d[354]
  PIN tap_d[355]
    DIRECTION OUTPUT ;
    USE SIGNAL ;
    PORT
      LAYER M4 ;
        RECT  0 62.256 0.084 62.28 ;
    END
  END tap_d[355]
  PIN tap_d[356]
    DIRECTION OUTPUT ;
    USE SIGNAL ;
    PORT
      LAYER M4 ;
        RECT  0 62.352 0.084 62.376 ;
    END
  END tap_d[356]
  PIN tap_d[357]
    DIRECTION OUTPUT ;
    USE SIGNAL ;
    PORT
      LAYER M4 ;
        RECT  0 62.448 0.084 62.472 ;
    END
  END tap_d[357]
  PIN tap_d[358]
    DIRECTION OUTPUT ;
    USE SIGNAL ;
    PORT
      LAYER M4 ;
        RECT  0 62.544 0.084 62.568 ;
    END
  END tap_d[358]
  PIN tap_d[359]
    DIRECTION OUTPUT ;
    USE SIGNAL ;
    PORT
      LAYER M4 ;
        RECT  0 62.64 0.084 62.664 ;
    END
  END tap_d[359]
  PIN tap_d[35]
    DIRECTION OUTPUT ;
    USE SIGNAL ;
    PORT
      LAYER M4 ;
        RECT  0 30.48 0.084 30.504 ;
    END
  END tap_d[35]
  PIN tap_d[360]
    DIRECTION OUTPUT ;
    USE SIGNAL ;
    PORT
      LAYER M4 ;
        RECT  0 62.784 0.084 62.808 ;
    END
  END tap_d[360]
  PIN tap_d[361]
    DIRECTION OUTPUT ;
    USE SIGNAL ;
    PORT
      LAYER M4 ;
        RECT  0 62.88 0.084 62.904 ;
    END
  END tap_d[361]
  PIN tap_d[362]
    DIRECTION OUTPUT ;
    USE SIGNAL ;
    PORT
      LAYER M4 ;
        RECT  0 62.976 0.084 63 ;
    END
  END tap_d[362]
  PIN tap_d[363]
    DIRECTION OUTPUT ;
    USE SIGNAL ;
    PORT
      LAYER M4 ;
        RECT  0 63.072 0.084 63.096 ;
    END
  END tap_d[363]
  PIN tap_d[364]
    DIRECTION OUTPUT ;
    USE SIGNAL ;
    PORT
      LAYER M4 ;
        RECT  0 63.168 0.084 63.192 ;
    END
  END tap_d[364]
  PIN tap_d[365]
    DIRECTION OUTPUT ;
    USE SIGNAL ;
    PORT
      LAYER M4 ;
        RECT  0 63.264 0.084 63.288 ;
    END
  END tap_d[365]
  PIN tap_d[366]
    DIRECTION OUTPUT ;
    USE SIGNAL ;
    PORT
      LAYER M4 ;
        RECT  0 63.36 0.084 63.384 ;
    END
  END tap_d[366]
  PIN tap_d[367]
    DIRECTION OUTPUT ;
    USE SIGNAL ;
    PORT
      LAYER M4 ;
        RECT  0 63.456 0.084 63.48 ;
    END
  END tap_d[367]
  PIN tap_d[368]
    DIRECTION OUTPUT ;
    USE SIGNAL ;
    PORT
      LAYER M4 ;
        RECT  0 63.552 0.084 63.576 ;
    END
  END tap_d[368]
  PIN tap_d[369]
    DIRECTION OUTPUT ;
    USE SIGNAL ;
    PORT
      LAYER M4 ;
        RECT  0 63.648 0.084 63.672 ;
    END
  END tap_d[369]
  PIN tap_d[36]
    DIRECTION OUTPUT ;
    USE SIGNAL ;
    PORT
      LAYER M4 ;
        RECT  0 30.576 0.084 30.6 ;
    END
  END tap_d[36]
  PIN tap_d[370]
    DIRECTION OUTPUT ;
    USE SIGNAL ;
    PORT
      LAYER M4 ;
        RECT  0 63.744 0.084 63.768 ;
    END
  END tap_d[370]
  PIN tap_d[371]
    DIRECTION OUTPUT ;
    USE SIGNAL ;
    PORT
      LAYER M4 ;
        RECT  0 63.84 0.084 63.864 ;
    END
  END tap_d[371]
  PIN tap_d[372]
    DIRECTION OUTPUT ;
    USE SIGNAL ;
    PORT
      LAYER M4 ;
        RECT  0 63.936 0.084 63.96 ;
    END
  END tap_d[372]
  PIN tap_d[373]
    DIRECTION OUTPUT ;
    USE SIGNAL ;
    PORT
      LAYER M4 ;
        RECT  0 64.032 0.084 64.056 ;
    END
  END tap_d[373]
  PIN tap_d[374]
    DIRECTION OUTPUT ;
    USE SIGNAL ;
    PORT
      LAYER M4 ;
        RECT  0 64.176 0.084 64.2 ;
    END
  END tap_d[374]
  PIN tap_d[375]
    DIRECTION OUTPUT ;
    USE SIGNAL ;
    PORT
      LAYER M4 ;
        RECT  0 64.272 0.084 64.296 ;
    END
  END tap_d[375]
  PIN tap_d[376]
    DIRECTION OUTPUT ;
    USE SIGNAL ;
    PORT
      LAYER M4 ;
        RECT  0 64.368 0.084 64.392 ;
    END
  END tap_d[376]
  PIN tap_d[377]
    DIRECTION OUTPUT ;
    USE SIGNAL ;
    PORT
      LAYER M4 ;
        RECT  0 64.464 0.084 64.488 ;
    END
  END tap_d[377]
  PIN tap_d[378]
    DIRECTION OUTPUT ;
    USE SIGNAL ;
    PORT
      LAYER M4 ;
        RECT  0 64.56 0.084 64.584 ;
    END
  END tap_d[378]
  PIN tap_d[379]
    DIRECTION OUTPUT ;
    USE SIGNAL ;
    PORT
      LAYER M4 ;
        RECT  0 64.656 0.084 64.68 ;
    END
  END tap_d[379]
  PIN tap_d[37]
    DIRECTION OUTPUT ;
    USE SIGNAL ;
    PORT
      LAYER M4 ;
        RECT  0 30.672 0.084 30.696 ;
    END
  END tap_d[37]
  PIN tap_d[380]
    DIRECTION OUTPUT ;
    USE SIGNAL ;
    PORT
      LAYER M4 ;
        RECT  0 64.752 0.084 64.776 ;
    END
  END tap_d[380]
  PIN tap_d[381]
    DIRECTION OUTPUT ;
    USE SIGNAL ;
    PORT
      LAYER M4 ;
        RECT  0 64.848 0.084 64.872 ;
    END
  END tap_d[381]
  PIN tap_d[382]
    DIRECTION OUTPUT ;
    USE SIGNAL ;
    PORT
      LAYER M4 ;
        RECT  0 64.944 0.084 64.968 ;
    END
  END tap_d[382]
  PIN tap_d[383]
    DIRECTION OUTPUT ;
    USE SIGNAL ;
    PORT
      LAYER M4 ;
        RECT  0 65.04 0.084 65.064 ;
    END
  END tap_d[383]
  PIN tap_d[384]
    DIRECTION OUTPUT ;
    USE SIGNAL ;
    PORT
      LAYER M4 ;
        RECT  0 65.136 0.084 65.16 ;
    END
  END tap_d[384]
  PIN tap_d[385]
    DIRECTION OUTPUT ;
    USE SIGNAL ;
    PORT
      LAYER M4 ;
        RECT  0 65.232 0.084 65.256 ;
    END
  END tap_d[385]
  PIN tap_d[386]
    DIRECTION OUTPUT ;
    USE SIGNAL ;
    PORT
      LAYER M4 ;
        RECT  0 65.328 0.084 65.352 ;
    END
  END tap_d[386]
  PIN tap_d[387]
    DIRECTION OUTPUT ;
    USE SIGNAL ;
    PORT
      LAYER M4 ;
        RECT  0 65.424 0.084 65.448 ;
    END
  END tap_d[387]
  PIN tap_d[388]
    DIRECTION OUTPUT ;
    USE SIGNAL ;
    PORT
      LAYER M4 ;
        RECT  0 65.568 0.084 65.592 ;
    END
  END tap_d[388]
  PIN tap_d[389]
    DIRECTION OUTPUT ;
    USE SIGNAL ;
    PORT
      LAYER M4 ;
        RECT  0 65.664 0.084 65.688 ;
    END
  END tap_d[389]
  PIN tap_d[38]
    DIRECTION OUTPUT ;
    USE SIGNAL ;
    PORT
      LAYER M4 ;
        RECT  0 30.768 0.084 30.792 ;
    END
  END tap_d[38]
  PIN tap_d[390]
    DIRECTION OUTPUT ;
    USE SIGNAL ;
    PORT
      LAYER M4 ;
        RECT  0 65.76 0.084 65.784 ;
    END
  END tap_d[390]
  PIN tap_d[391]
    DIRECTION OUTPUT ;
    USE SIGNAL ;
    PORT
      LAYER M4 ;
        RECT  0 65.856 0.084 65.88 ;
    END
  END tap_d[391]
  PIN tap_d[392]
    DIRECTION OUTPUT ;
    USE SIGNAL ;
    PORT
      LAYER M4 ;
        RECT  0 65.952 0.084 65.976 ;
    END
  END tap_d[392]
  PIN tap_d[393]
    DIRECTION OUTPUT ;
    USE SIGNAL ;
    PORT
      LAYER M4 ;
        RECT  0 66.048 0.084 66.072 ;
    END
  END tap_d[393]
  PIN tap_d[394]
    DIRECTION OUTPUT ;
    USE SIGNAL ;
    PORT
      LAYER M4 ;
        RECT  0 66.144 0.084 66.168 ;
    END
  END tap_d[394]
  PIN tap_d[395]
    DIRECTION OUTPUT ;
    USE SIGNAL ;
    PORT
      LAYER M4 ;
        RECT  0 66.24 0.084 66.264 ;
    END
  END tap_d[395]
  PIN tap_d[396]
    DIRECTION OUTPUT ;
    USE SIGNAL ;
    PORT
      LAYER M4 ;
        RECT  0 66.336 0.084 66.36 ;
    END
  END tap_d[396]
  PIN tap_d[397]
    DIRECTION OUTPUT ;
    USE SIGNAL ;
    PORT
      LAYER M4 ;
        RECT  0 66.432 0.084 66.456 ;
    END
  END tap_d[397]
  PIN tap_d[398]
    DIRECTION OUTPUT ;
    USE SIGNAL ;
    PORT
      LAYER M4 ;
        RECT  0 66.528 0.084 66.552 ;
    END
  END tap_d[398]
  PIN tap_d[399]
    DIRECTION OUTPUT ;
    USE SIGNAL ;
    PORT
      LAYER M4 ;
        RECT  0 66.624 0.084 66.648 ;
    END
  END tap_d[399]
  PIN tap_d[39]
    DIRECTION OUTPUT ;
    USE SIGNAL ;
    PORT
      LAYER M4 ;
        RECT  0 30.864 0.084 30.888 ;
    END
  END tap_d[39]
  PIN tap_d[3]
    DIRECTION OUTPUT ;
    USE SIGNAL ;
    PORT
      LAYER M4 ;
        RECT  0 27.264 0.084 27.288 ;
    END
  END tap_d[3]
  PIN tap_d[400]
    DIRECTION OUTPUT ;
    USE SIGNAL ;
    PORT
      LAYER M4 ;
        RECT  0 66.72 0.084 66.744 ;
    END
  END tap_d[400]
  PIN tap_d[401]
    DIRECTION OUTPUT ;
    USE SIGNAL ;
    PORT
      LAYER M4 ;
        RECT  0 66.816 0.084 66.84 ;
    END
  END tap_d[401]
  PIN tap_d[402]
    DIRECTION OUTPUT ;
    USE SIGNAL ;
    PORT
      LAYER M4 ;
        RECT  0 66.96 0.084 66.984 ;
    END
  END tap_d[402]
  PIN tap_d[403]
    DIRECTION OUTPUT ;
    USE SIGNAL ;
    PORT
      LAYER M4 ;
        RECT  0 67.056 0.084 67.08 ;
    END
  END tap_d[403]
  PIN tap_d[404]
    DIRECTION OUTPUT ;
    USE SIGNAL ;
    PORT
      LAYER M4 ;
        RECT  0 67.152 0.084 67.176 ;
    END
  END tap_d[404]
  PIN tap_d[405]
    DIRECTION OUTPUT ;
    USE SIGNAL ;
    PORT
      LAYER M4 ;
        RECT  0 67.248 0.084 67.272 ;
    END
  END tap_d[405]
  PIN tap_d[406]
    DIRECTION OUTPUT ;
    USE SIGNAL ;
    PORT
      LAYER M4 ;
        RECT  0 67.344 0.084 67.368 ;
    END
  END tap_d[406]
  PIN tap_d[407]
    DIRECTION OUTPUT ;
    USE SIGNAL ;
    PORT
      LAYER M4 ;
        RECT  0 67.44 0.084 67.464 ;
    END
  END tap_d[407]
  PIN tap_d[408]
    DIRECTION OUTPUT ;
    USE SIGNAL ;
    PORT
      LAYER M4 ;
        RECT  0 67.536 0.084 67.56 ;
    END
  END tap_d[408]
  PIN tap_d[409]
    DIRECTION OUTPUT ;
    USE SIGNAL ;
    PORT
      LAYER M4 ;
        RECT  0 67.632 0.084 67.656 ;
    END
  END tap_d[409]
  PIN tap_d[40]
    DIRECTION OUTPUT ;
    USE SIGNAL ;
    PORT
      LAYER M4 ;
        RECT  0 30.96 0.084 30.984 ;
    END
  END tap_d[40]
  PIN tap_d[410]
    DIRECTION OUTPUT ;
    USE SIGNAL ;
    PORT
      LAYER M4 ;
        RECT  0 67.728 0.084 67.752 ;
    END
  END tap_d[410]
  PIN tap_d[411]
    DIRECTION OUTPUT ;
    USE SIGNAL ;
    PORT
      LAYER M4 ;
        RECT  0 67.824 0.084 67.848 ;
    END
  END tap_d[411]
  PIN tap_d[412]
    DIRECTION OUTPUT ;
    USE SIGNAL ;
    PORT
      LAYER M4 ;
        RECT  0 67.92 0.084 67.944 ;
    END
  END tap_d[412]
  PIN tap_d[413]
    DIRECTION OUTPUT ;
    USE SIGNAL ;
    PORT
      LAYER M4 ;
        RECT  0 68.016 0.084 68.04 ;
    END
  END tap_d[413]
  PIN tap_d[414]
    DIRECTION OUTPUT ;
    USE SIGNAL ;
    PORT
      LAYER M4 ;
        RECT  0 68.112 0.084 68.136 ;
    END
  END tap_d[414]
  PIN tap_d[415]
    DIRECTION OUTPUT ;
    USE SIGNAL ;
    PORT
      LAYER M4 ;
        RECT  0 68.208 0.084 68.232 ;
    END
  END tap_d[415]
  PIN tap_d[416]
    DIRECTION OUTPUT ;
    USE SIGNAL ;
    PORT
      LAYER M4 ;
        RECT  0 68.352 0.084 68.376 ;
    END
  END tap_d[416]
  PIN tap_d[417]
    DIRECTION OUTPUT ;
    USE SIGNAL ;
    PORT
      LAYER M4 ;
        RECT  0 68.448 0.084 68.472 ;
    END
  END tap_d[417]
  PIN tap_d[418]
    DIRECTION OUTPUT ;
    USE SIGNAL ;
    PORT
      LAYER M4 ;
        RECT  0 68.544 0.084 68.568 ;
    END
  END tap_d[418]
  PIN tap_d[419]
    DIRECTION OUTPUT ;
    USE SIGNAL ;
    PORT
      LAYER M4 ;
        RECT  0 68.64 0.084 68.664 ;
    END
  END tap_d[419]
  PIN tap_d[41]
    DIRECTION OUTPUT ;
    USE SIGNAL ;
    PORT
      LAYER M4 ;
        RECT  0 31.056 0.084 31.08 ;
    END
  END tap_d[41]
  PIN tap_d[420]
    DIRECTION OUTPUT ;
    USE SIGNAL ;
    PORT
      LAYER M4 ;
        RECT  0 68.736 0.084 68.76 ;
    END
  END tap_d[420]
  PIN tap_d[421]
    DIRECTION OUTPUT ;
    USE SIGNAL ;
    PORT
      LAYER M4 ;
        RECT  0 68.832 0.084 68.856 ;
    END
  END tap_d[421]
  PIN tap_d[422]
    DIRECTION OUTPUT ;
    USE SIGNAL ;
    PORT
      LAYER M4 ;
        RECT  0 68.928 0.084 68.952 ;
    END
  END tap_d[422]
  PIN tap_d[423]
    DIRECTION OUTPUT ;
    USE SIGNAL ;
    PORT
      LAYER M4 ;
        RECT  0 69.024 0.084 69.048 ;
    END
  END tap_d[423]
  PIN tap_d[424]
    DIRECTION OUTPUT ;
    USE SIGNAL ;
    PORT
      LAYER M4 ;
        RECT  0 69.12 0.084 69.144 ;
    END
  END tap_d[424]
  PIN tap_d[425]
    DIRECTION OUTPUT ;
    USE SIGNAL ;
    PORT
      LAYER M4 ;
        RECT  0 69.216 0.084 69.24 ;
    END
  END tap_d[425]
  PIN tap_d[426]
    DIRECTION OUTPUT ;
    USE SIGNAL ;
    PORT
      LAYER M4 ;
        RECT  0 69.312 0.084 69.336 ;
    END
  END tap_d[426]
  PIN tap_d[427]
    DIRECTION OUTPUT ;
    USE SIGNAL ;
    PORT
      LAYER M4 ;
        RECT  0 69.408 0.084 69.432 ;
    END
  END tap_d[427]
  PIN tap_d[428]
    DIRECTION OUTPUT ;
    USE SIGNAL ;
    PORT
      LAYER M4 ;
        RECT  0 69.504 0.084 69.528 ;
    END
  END tap_d[428]
  PIN tap_d[429]
    DIRECTION OUTPUT ;
    USE SIGNAL ;
    PORT
      LAYER M4 ;
        RECT  0 69.6 0.084 69.624 ;
    END
  END tap_d[429]
  PIN tap_d[42]
    DIRECTION OUTPUT ;
    USE SIGNAL ;
    PORT
      LAYER M4 ;
        RECT  0 31.152 0.084 31.176 ;
    END
  END tap_d[42]
  PIN tap_d[430]
    DIRECTION OUTPUT ;
    USE SIGNAL ;
    PORT
      LAYER M4 ;
        RECT  0 69.744 0.084 69.768 ;
    END
  END tap_d[430]
  PIN tap_d[431]
    DIRECTION OUTPUT ;
    USE SIGNAL ;
    PORT
      LAYER M4 ;
        RECT  0 69.84 0.084 69.864 ;
    END
  END tap_d[431]
  PIN tap_d[432]
    DIRECTION OUTPUT ;
    USE SIGNAL ;
    PORT
      LAYER M4 ;
        RECT  0 69.936 0.084 69.96 ;
    END
  END tap_d[432]
  PIN tap_d[433]
    DIRECTION OUTPUT ;
    USE SIGNAL ;
    PORT
      LAYER M4 ;
        RECT  0 70.032 0.084 70.056 ;
    END
  END tap_d[433]
  PIN tap_d[434]
    DIRECTION OUTPUT ;
    USE SIGNAL ;
    PORT
      LAYER M4 ;
        RECT  0 70.128 0.084 70.152 ;
    END
  END tap_d[434]
  PIN tap_d[435]
    DIRECTION OUTPUT ;
    USE SIGNAL ;
    PORT
      LAYER M4 ;
        RECT  0 70.224 0.084 70.248 ;
    END
  END tap_d[435]
  PIN tap_d[436]
    DIRECTION OUTPUT ;
    USE SIGNAL ;
    PORT
      LAYER M4 ;
        RECT  0 70.32 0.084 70.344 ;
    END
  END tap_d[436]
  PIN tap_d[437]
    DIRECTION OUTPUT ;
    USE SIGNAL ;
    PORT
      LAYER M4 ;
        RECT  0 70.416 0.084 70.44 ;
    END
  END tap_d[437]
  PIN tap_d[438]
    DIRECTION OUTPUT ;
    USE SIGNAL ;
    PORT
      LAYER M4 ;
        RECT  0 70.512 0.084 70.536 ;
    END
  END tap_d[438]
  PIN tap_d[439]
    DIRECTION OUTPUT ;
    USE SIGNAL ;
    PORT
      LAYER M4 ;
        RECT  0 70.608 0.084 70.632 ;
    END
  END tap_d[439]
  PIN tap_d[43]
    DIRECTION OUTPUT ;
    USE SIGNAL ;
    PORT
      LAYER M4 ;
        RECT  0 31.248 0.084 31.272 ;
    END
  END tap_d[43]
  PIN tap_d[440]
    DIRECTION OUTPUT ;
    USE SIGNAL ;
    PORT
      LAYER M4 ;
        RECT  0 70.704 0.084 70.728 ;
    END
  END tap_d[440]
  PIN tap_d[441]
    DIRECTION OUTPUT ;
    USE SIGNAL ;
    PORT
      LAYER M4 ;
        RECT  0 70.8 0.084 70.824 ;
    END
  END tap_d[441]
  PIN tap_d[442]
    DIRECTION OUTPUT ;
    USE SIGNAL ;
    PORT
      LAYER M4 ;
        RECT  0 70.896 0.084 70.92 ;
    END
  END tap_d[442]
  PIN tap_d[443]
    DIRECTION OUTPUT ;
    USE SIGNAL ;
    PORT
      LAYER M4 ;
        RECT  0 70.992 0.084 71.016 ;
    END
  END tap_d[443]
  PIN tap_d[444]
    DIRECTION OUTPUT ;
    USE SIGNAL ;
    PORT
      LAYER M4 ;
        RECT  0 71.136 0.084 71.16 ;
    END
  END tap_d[444]
  PIN tap_d[445]
    DIRECTION OUTPUT ;
    USE SIGNAL ;
    PORT
      LAYER M4 ;
        RECT  0 71.232 0.084 71.256 ;
    END
  END tap_d[445]
  PIN tap_d[446]
    DIRECTION OUTPUT ;
    USE SIGNAL ;
    PORT
      LAYER M4 ;
        RECT  0 71.328 0.084 71.352 ;
    END
  END tap_d[446]
  PIN tap_d[447]
    DIRECTION OUTPUT ;
    USE SIGNAL ;
    PORT
      LAYER M4 ;
        RECT  0 71.424 0.084 71.448 ;
    END
  END tap_d[447]
  PIN tap_d[448]
    DIRECTION OUTPUT ;
    USE SIGNAL ;
    PORT
      LAYER M4 ;
        RECT  0 71.52 0.084 71.544 ;
    END
  END tap_d[448]
  PIN tap_d[449]
    DIRECTION OUTPUT ;
    USE SIGNAL ;
    PORT
      LAYER M4 ;
        RECT  0 71.616 0.084 71.64 ;
    END
  END tap_d[449]
  PIN tap_d[44]
    DIRECTION OUTPUT ;
    USE SIGNAL ;
    PORT
      LAYER M4 ;
        RECT  0 31.344 0.084 31.368 ;
    END
  END tap_d[44]
  PIN tap_d[450]
    DIRECTION OUTPUT ;
    USE SIGNAL ;
    PORT
      LAYER M4 ;
        RECT  0 71.712 0.084 71.736 ;
    END
  END tap_d[450]
  PIN tap_d[451]
    DIRECTION OUTPUT ;
    USE SIGNAL ;
    PORT
      LAYER M4 ;
        RECT  0 71.808 0.084 71.832 ;
    END
  END tap_d[451]
  PIN tap_d[452]
    DIRECTION OUTPUT ;
    USE SIGNAL ;
    PORT
      LAYER M4 ;
        RECT  0 71.904 0.084 71.928 ;
    END
  END tap_d[452]
  PIN tap_d[453]
    DIRECTION OUTPUT ;
    USE SIGNAL ;
    PORT
      LAYER M4 ;
        RECT  0 72 0.084 72.024 ;
    END
  END tap_d[453]
  PIN tap_d[454]
    DIRECTION OUTPUT ;
    USE SIGNAL ;
    PORT
      LAYER M4 ;
        RECT  0 72.096 0.084 72.12 ;
    END
  END tap_d[454]
  PIN tap_d[455]
    DIRECTION OUTPUT ;
    USE SIGNAL ;
    PORT
      LAYER M4 ;
        RECT  0 72.192 0.084 72.216 ;
    END
  END tap_d[455]
  PIN tap_d[456]
    DIRECTION OUTPUT ;
    USE SIGNAL ;
    PORT
      LAYER M4 ;
        RECT  0 72.288 0.084 72.312 ;
    END
  END tap_d[456]
  PIN tap_d[457]
    DIRECTION OUTPUT ;
    USE SIGNAL ;
    PORT
      LAYER M4 ;
        RECT  0 72.384 0.084 72.408 ;
    END
  END tap_d[457]
  PIN tap_d[458]
    DIRECTION OUTPUT ;
    USE SIGNAL ;
    PORT
      LAYER M4 ;
        RECT  0 72.528 0.084 72.552 ;
    END
  END tap_d[458]
  PIN tap_d[459]
    DIRECTION OUTPUT ;
    USE SIGNAL ;
    PORT
      LAYER M4 ;
        RECT  0 72.624 0.084 72.648 ;
    END
  END tap_d[459]
  PIN tap_d[45]
    DIRECTION OUTPUT ;
    USE SIGNAL ;
    PORT
      LAYER M4 ;
        RECT  0 31.44 0.084 31.464 ;
    END
  END tap_d[45]
  PIN tap_d[460]
    DIRECTION OUTPUT ;
    USE SIGNAL ;
    PORT
      LAYER M4 ;
        RECT  0 72.72 0.084 72.744 ;
    END
  END tap_d[460]
  PIN tap_d[461]
    DIRECTION OUTPUT ;
    USE SIGNAL ;
    PORT
      LAYER M4 ;
        RECT  0 72.816 0.084 72.84 ;
    END
  END tap_d[461]
  PIN tap_d[462]
    DIRECTION OUTPUT ;
    USE SIGNAL ;
    PORT
      LAYER M4 ;
        RECT  0 72.912 0.084 72.936 ;
    END
  END tap_d[462]
  PIN tap_d[463]
    DIRECTION OUTPUT ;
    USE SIGNAL ;
    PORT
      LAYER M4 ;
        RECT  0 73.008 0.084 73.032 ;
    END
  END tap_d[463]
  PIN tap_d[464]
    DIRECTION OUTPUT ;
    USE SIGNAL ;
    PORT
      LAYER M4 ;
        RECT  0 73.104 0.084 73.128 ;
    END
  END tap_d[464]
  PIN tap_d[465]
    DIRECTION OUTPUT ;
    USE SIGNAL ;
    PORT
      LAYER M4 ;
        RECT  0 73.2 0.084 73.224 ;
    END
  END tap_d[465]
  PIN tap_d[466]
    DIRECTION OUTPUT ;
    USE SIGNAL ;
    PORT
      LAYER M4 ;
        RECT  0 73.296 0.084 73.32 ;
    END
  END tap_d[466]
  PIN tap_d[467]
    DIRECTION OUTPUT ;
    USE SIGNAL ;
    PORT
      LAYER M4 ;
        RECT  0 73.392 0.084 73.416 ;
    END
  END tap_d[467]
  PIN tap_d[468]
    DIRECTION OUTPUT ;
    USE SIGNAL ;
    PORT
      LAYER M4 ;
        RECT  0 73.488 0.084 73.512 ;
    END
  END tap_d[468]
  PIN tap_d[469]
    DIRECTION OUTPUT ;
    USE SIGNAL ;
    PORT
      LAYER M4 ;
        RECT  0 73.584 0.084 73.608 ;
    END
  END tap_d[469]
  PIN tap_d[46]
    DIRECTION OUTPUT ;
    USE SIGNAL ;
    PORT
      LAYER M4 ;
        RECT  0 31.536 0.084 31.56 ;
    END
  END tap_d[46]
  PIN tap_d[470]
    DIRECTION OUTPUT ;
    USE SIGNAL ;
    PORT
      LAYER M4 ;
        RECT  0 73.68 0.084 73.704 ;
    END
  END tap_d[470]
  PIN tap_d[471]
    DIRECTION OUTPUT ;
    USE SIGNAL ;
    PORT
      LAYER M4 ;
        RECT  0 73.776 0.084 73.8 ;
    END
  END tap_d[471]
  PIN tap_d[472]
    DIRECTION OUTPUT ;
    USE SIGNAL ;
    PORT
      LAYER M4 ;
        RECT  0 73.872 0.084 73.896 ;
    END
  END tap_d[472]
  PIN tap_d[473]
    DIRECTION OUTPUT ;
    USE SIGNAL ;
    PORT
      LAYER M4 ;
        RECT  0 74.016 0.084 74.04 ;
    END
  END tap_d[473]
  PIN tap_d[474]
    DIRECTION OUTPUT ;
    USE SIGNAL ;
    PORT
      LAYER M4 ;
        RECT  0 74.112 0.084 74.136 ;
    END
  END tap_d[474]
  PIN tap_d[475]
    DIRECTION OUTPUT ;
    USE SIGNAL ;
    PORT
      LAYER M4 ;
        RECT  0 74.208 0.084 74.232 ;
    END
  END tap_d[475]
  PIN tap_d[476]
    DIRECTION OUTPUT ;
    USE SIGNAL ;
    PORT
      LAYER M4 ;
        RECT  0 74.304 0.084 74.328 ;
    END
  END tap_d[476]
  PIN tap_d[477]
    DIRECTION OUTPUT ;
    USE SIGNAL ;
    PORT
      LAYER M4 ;
        RECT  0 74.4 0.084 74.424 ;
    END
  END tap_d[477]
  PIN tap_d[478]
    DIRECTION OUTPUT ;
    USE SIGNAL ;
    PORT
      LAYER M4 ;
        RECT  0 74.496 0.084 74.52 ;
    END
  END tap_d[478]
  PIN tap_d[479]
    DIRECTION OUTPUT ;
    USE SIGNAL ;
    PORT
      LAYER M4 ;
        RECT  0 74.592 0.084 74.616 ;
    END
  END tap_d[479]
  PIN tap_d[47]
    DIRECTION OUTPUT ;
    USE SIGNAL ;
    PORT
      LAYER M4 ;
        RECT  0 31.632 0.084 31.656 ;
    END
  END tap_d[47]
  PIN tap_d[480]
    DIRECTION OUTPUT ;
    USE SIGNAL ;
    PORT
      LAYER M4 ;
        RECT  0 74.688 0.084 74.712 ;
    END
  END tap_d[480]
  PIN tap_d[481]
    DIRECTION OUTPUT ;
    USE SIGNAL ;
    PORT
      LAYER M4 ;
        RECT  0 74.784 0.084 74.808 ;
    END
  END tap_d[481]
  PIN tap_d[482]
    DIRECTION OUTPUT ;
    USE SIGNAL ;
    PORT
      LAYER M4 ;
        RECT  0 74.88 0.084 74.904 ;
    END
  END tap_d[482]
  PIN tap_d[483]
    DIRECTION OUTPUT ;
    USE SIGNAL ;
    PORT
      LAYER M4 ;
        RECT  0 74.976 0.084 75 ;
    END
  END tap_d[483]
  PIN tap_d[484]
    DIRECTION OUTPUT ;
    USE SIGNAL ;
    PORT
      LAYER M4 ;
        RECT  0 75.072 0.084 75.096 ;
    END
  END tap_d[484]
  PIN tap_d[485]
    DIRECTION OUTPUT ;
    USE SIGNAL ;
    PORT
      LAYER M4 ;
        RECT  0 75.168 0.084 75.192 ;
    END
  END tap_d[485]
  PIN tap_d[486]
    DIRECTION OUTPUT ;
    USE SIGNAL ;
    PORT
      LAYER M4 ;
        RECT  0 75.264 0.084 75.288 ;
    END
  END tap_d[486]
  PIN tap_d[487]
    DIRECTION OUTPUT ;
    USE SIGNAL ;
    PORT
      LAYER M4 ;
        RECT  0 75.408 0.084 75.432 ;
    END
  END tap_d[487]
  PIN tap_d[488]
    DIRECTION OUTPUT ;
    USE SIGNAL ;
    PORT
      LAYER M4 ;
        RECT  0 75.504 0.084 75.528 ;
    END
  END tap_d[488]
  PIN tap_d[489]
    DIRECTION OUTPUT ;
    USE SIGNAL ;
    PORT
      LAYER M4 ;
        RECT  0 75.6 0.084 75.624 ;
    END
  END tap_d[489]
  PIN tap_d[48]
    DIRECTION OUTPUT ;
    USE SIGNAL ;
    PORT
      LAYER M4 ;
        RECT  0 31.728 0.084 31.752 ;
    END
  END tap_d[48]
  PIN tap_d[490]
    DIRECTION OUTPUT ;
    USE SIGNAL ;
    PORT
      LAYER M4 ;
        RECT  0 75.696 0.084 75.72 ;
    END
  END tap_d[490]
  PIN tap_d[491]
    DIRECTION OUTPUT ;
    USE SIGNAL ;
    PORT
      LAYER M4 ;
        RECT  0 75.792 0.084 75.816 ;
    END
  END tap_d[491]
  PIN tap_d[492]
    DIRECTION OUTPUT ;
    USE SIGNAL ;
    PORT
      LAYER M4 ;
        RECT  0 75.888 0.084 75.912 ;
    END
  END tap_d[492]
  PIN tap_d[493]
    DIRECTION OUTPUT ;
    USE SIGNAL ;
    PORT
      LAYER M4 ;
        RECT  0 75.984 0.084 76.008 ;
    END
  END tap_d[493]
  PIN tap_d[494]
    DIRECTION OUTPUT ;
    USE SIGNAL ;
    PORT
      LAYER M4 ;
        RECT  0 76.08 0.084 76.104 ;
    END
  END tap_d[494]
  PIN tap_d[495]
    DIRECTION OUTPUT ;
    USE SIGNAL ;
    PORT
      LAYER M4 ;
        RECT  0 76.176 0.084 76.2 ;
    END
  END tap_d[495]
  PIN tap_d[496]
    DIRECTION OUTPUT ;
    USE SIGNAL ;
    PORT
      LAYER M4 ;
        RECT  0 76.272 0.084 76.296 ;
    END
  END tap_d[496]
  PIN tap_d[497]
    DIRECTION OUTPUT ;
    USE SIGNAL ;
    PORT
      LAYER M4 ;
        RECT  0 76.368 0.084 76.392 ;
    END
  END tap_d[497]
  PIN tap_d[498]
    DIRECTION OUTPUT ;
    USE SIGNAL ;
    PORT
      LAYER M4 ;
        RECT  0 76.464 0.084 76.488 ;
    END
  END tap_d[498]
  PIN tap_d[499]
    DIRECTION OUTPUT ;
    USE SIGNAL ;
    PORT
      LAYER M4 ;
        RECT  0 76.56 0.084 76.584 ;
    END
  END tap_d[499]
  PIN tap_d[49]
    DIRECTION OUTPUT ;
    USE SIGNAL ;
    PORT
      LAYER M4 ;
        RECT  0 31.872 0.084 31.896 ;
    END
  END tap_d[49]
  PIN tap_d[4]
    DIRECTION OUTPUT ;
    USE SIGNAL ;
    PORT
      LAYER M4 ;
        RECT  0 27.36 0.084 27.384 ;
    END
  END tap_d[4]
  PIN tap_d[500]
    DIRECTION OUTPUT ;
    USE SIGNAL ;
    PORT
      LAYER M4 ;
        RECT  0 76.656 0.084 76.68 ;
    END
  END tap_d[500]
  PIN tap_d[501]
    DIRECTION OUTPUT ;
    USE SIGNAL ;
    PORT
      LAYER M4 ;
        RECT  0 76.8 0.084 76.824 ;
    END
  END tap_d[501]
  PIN tap_d[502]
    DIRECTION OUTPUT ;
    USE SIGNAL ;
    PORT
      LAYER M4 ;
        RECT  0 76.896 0.084 76.92 ;
    END
  END tap_d[502]
  PIN tap_d[503]
    DIRECTION OUTPUT ;
    USE SIGNAL ;
    PORT
      LAYER M4 ;
        RECT  0 76.992 0.084 77.016 ;
    END
  END tap_d[503]
  PIN tap_d[504]
    DIRECTION OUTPUT ;
    USE SIGNAL ;
    PORT
      LAYER M4 ;
        RECT  0 77.088 0.084 77.112 ;
    END
  END tap_d[504]
  PIN tap_d[505]
    DIRECTION OUTPUT ;
    USE SIGNAL ;
    PORT
      LAYER M4 ;
        RECT  0 77.184 0.084 77.208 ;
    END
  END tap_d[505]
  PIN tap_d[506]
    DIRECTION OUTPUT ;
    USE SIGNAL ;
    PORT
      LAYER M4 ;
        RECT  0 77.28 0.084 77.304 ;
    END
  END tap_d[506]
  PIN tap_d[507]
    DIRECTION OUTPUT ;
    USE SIGNAL ;
    PORT
      LAYER M4 ;
        RECT  0 77.376 0.084 77.4 ;
    END
  END tap_d[507]
  PIN tap_d[50]
    DIRECTION OUTPUT ;
    USE SIGNAL ;
    PORT
      LAYER M4 ;
        RECT  0 31.968 0.084 31.992 ;
    END
  END tap_d[50]
  PIN tap_d[51]
    DIRECTION OUTPUT ;
    USE SIGNAL ;
    PORT
      LAYER M4 ;
        RECT  0 32.064 0.084 32.088 ;
    END
  END tap_d[51]
  PIN tap_d[52]
    DIRECTION OUTPUT ;
    USE SIGNAL ;
    PORT
      LAYER M4 ;
        RECT  0 32.16 0.084 32.184 ;
    END
  END tap_d[52]
  PIN tap_d[53]
    DIRECTION OUTPUT ;
    USE SIGNAL ;
    PORT
      LAYER M4 ;
        RECT  0 32.256 0.084 32.28 ;
    END
  END tap_d[53]
  PIN tap_d[54]
    DIRECTION OUTPUT ;
    USE SIGNAL ;
    PORT
      LAYER M4 ;
        RECT  0 32.352 0.084 32.376 ;
    END
  END tap_d[54]
  PIN tap_d[55]
    DIRECTION OUTPUT ;
    USE SIGNAL ;
    PORT
      LAYER M4 ;
        RECT  0 32.448 0.084 32.472 ;
    END
  END tap_d[55]
  PIN tap_d[56]
    DIRECTION OUTPUT ;
    USE SIGNAL ;
    PORT
      LAYER M4 ;
        RECT  0 32.544 0.084 32.568 ;
    END
  END tap_d[56]
  PIN tap_d[57]
    DIRECTION OUTPUT ;
    USE SIGNAL ;
    PORT
      LAYER M4 ;
        RECT  0 32.64 0.084 32.664 ;
    END
  END tap_d[57]
  PIN tap_d[58]
    DIRECTION OUTPUT ;
    USE SIGNAL ;
    PORT
      LAYER M4 ;
        RECT  0 32.736 0.084 32.76 ;
    END
  END tap_d[58]
  PIN tap_d[59]
    DIRECTION OUTPUT ;
    USE SIGNAL ;
    PORT
      LAYER M4 ;
        RECT  0 32.832 0.084 32.856 ;
    END
  END tap_d[59]
  PIN tap_d[5]
    DIRECTION OUTPUT ;
    USE SIGNAL ;
    PORT
      LAYER M4 ;
        RECT  0 27.456 0.084 27.48 ;
    END
  END tap_d[5]
  PIN tap_d[60]
    DIRECTION OUTPUT ;
    USE SIGNAL ;
    PORT
      LAYER M4 ;
        RECT  0 32.928 0.084 32.952 ;
    END
  END tap_d[60]
  PIN tap_d[61]
    DIRECTION OUTPUT ;
    USE SIGNAL ;
    PORT
      LAYER M4 ;
        RECT  0 33.024 0.084 33.048 ;
    END
  END tap_d[61]
  PIN tap_d[62]
    DIRECTION OUTPUT ;
    USE SIGNAL ;
    PORT
      LAYER M4 ;
        RECT  0 33.12 0.084 33.144 ;
    END
  END tap_d[62]
  PIN tap_d[63]
    DIRECTION OUTPUT ;
    USE SIGNAL ;
    PORT
      LAYER M4 ;
        RECT  0 33.264 0.084 33.288 ;
    END
  END tap_d[63]
  PIN tap_d[64]
    DIRECTION OUTPUT ;
    USE SIGNAL ;
    PORT
      LAYER M4 ;
        RECT  0 33.36 0.084 33.384 ;
    END
  END tap_d[64]
  PIN tap_d[65]
    DIRECTION OUTPUT ;
    USE SIGNAL ;
    PORT
      LAYER M4 ;
        RECT  0 33.456 0.084 33.48 ;
    END
  END tap_d[65]
  PIN tap_d[66]
    DIRECTION OUTPUT ;
    USE SIGNAL ;
    PORT
      LAYER M4 ;
        RECT  0 33.552 0.084 33.576 ;
    END
  END tap_d[66]
  PIN tap_d[67]
    DIRECTION OUTPUT ;
    USE SIGNAL ;
    PORT
      LAYER M4 ;
        RECT  0 33.648 0.084 33.672 ;
    END
  END tap_d[67]
  PIN tap_d[68]
    DIRECTION OUTPUT ;
    USE SIGNAL ;
    PORT
      LAYER M4 ;
        RECT  0 33.744 0.084 33.768 ;
    END
  END tap_d[68]
  PIN tap_d[69]
    DIRECTION OUTPUT ;
    USE SIGNAL ;
    PORT
      LAYER M4 ;
        RECT  0 33.84 0.084 33.864 ;
    END
  END tap_d[69]
  PIN tap_d[6]
    DIRECTION OUTPUT ;
    USE SIGNAL ;
    PORT
      LAYER M4 ;
        RECT  0 27.552 0.084 27.576 ;
    END
  END tap_d[6]
  PIN tap_d[70]
    DIRECTION OUTPUT ;
    USE SIGNAL ;
    PORT
      LAYER M4 ;
        RECT  0 33.936 0.084 33.96 ;
    END
  END tap_d[70]
  PIN tap_d[71]
    DIRECTION OUTPUT ;
    USE SIGNAL ;
    PORT
      LAYER M4 ;
        RECT  0 34.032 0.084 34.056 ;
    END
  END tap_d[71]
  PIN tap_d[72]
    DIRECTION OUTPUT ;
    USE SIGNAL ;
    PORT
      LAYER M4 ;
        RECT  0 34.128 0.084 34.152 ;
    END
  END tap_d[72]
  PIN tap_d[73]
    DIRECTION OUTPUT ;
    USE SIGNAL ;
    PORT
      LAYER M4 ;
        RECT  0 34.224 0.084 34.248 ;
    END
  END tap_d[73]
  PIN tap_d[74]
    DIRECTION OUTPUT ;
    USE SIGNAL ;
    PORT
      LAYER M4 ;
        RECT  0 34.32 0.084 34.344 ;
    END
  END tap_d[74]
  PIN tap_d[75]
    DIRECTION OUTPUT ;
    USE SIGNAL ;
    PORT
      LAYER M4 ;
        RECT  0 34.416 0.084 34.44 ;
    END
  END tap_d[75]
  PIN tap_d[76]
    DIRECTION OUTPUT ;
    USE SIGNAL ;
    PORT
      LAYER M4 ;
        RECT  0 34.512 0.084 34.536 ;
    END
  END tap_d[76]
  PIN tap_d[77]
    DIRECTION OUTPUT ;
    USE SIGNAL ;
    PORT
      LAYER M4 ;
        RECT  0 34.656 0.084 34.68 ;
    END
  END tap_d[77]
  PIN tap_d[78]
    DIRECTION OUTPUT ;
    USE SIGNAL ;
    PORT
      LAYER M4 ;
        RECT  0 34.752 0.084 34.776 ;
    END
  END tap_d[78]
  PIN tap_d[79]
    DIRECTION OUTPUT ;
    USE SIGNAL ;
    PORT
      LAYER M4 ;
        RECT  0 34.848 0.084 34.872 ;
    END
  END tap_d[79]
  PIN tap_d[7]
    DIRECTION OUTPUT ;
    USE SIGNAL ;
    PORT
      LAYER M4 ;
        RECT  0 27.696 0.084 27.72 ;
    END
  END tap_d[7]
  PIN tap_d[80]
    DIRECTION OUTPUT ;
    USE SIGNAL ;
    PORT
      LAYER M4 ;
        RECT  0 34.944 0.084 34.968 ;
    END
  END tap_d[80]
  PIN tap_d[81]
    DIRECTION OUTPUT ;
    USE SIGNAL ;
    PORT
      LAYER M4 ;
        RECT  0 35.04 0.084 35.064 ;
    END
  END tap_d[81]
  PIN tap_d[82]
    DIRECTION OUTPUT ;
    USE SIGNAL ;
    PORT
      LAYER M4 ;
        RECT  0 35.136 0.084 35.16 ;
    END
  END tap_d[82]
  PIN tap_d[83]
    DIRECTION OUTPUT ;
    USE SIGNAL ;
    PORT
      LAYER M4 ;
        RECT  0 35.232 0.084 35.256 ;
    END
  END tap_d[83]
  PIN tap_d[84]
    DIRECTION OUTPUT ;
    USE SIGNAL ;
    PORT
      LAYER M4 ;
        RECT  0 35.328 0.084 35.352 ;
    END
  END tap_d[84]
  PIN tap_d[85]
    DIRECTION OUTPUT ;
    USE SIGNAL ;
    PORT
      LAYER M4 ;
        RECT  0 35.424 0.084 35.448 ;
    END
  END tap_d[85]
  PIN tap_d[86]
    DIRECTION OUTPUT ;
    USE SIGNAL ;
    PORT
      LAYER M4 ;
        RECT  0 35.52 0.084 35.544 ;
    END
  END tap_d[86]
  PIN tap_d[87]
    DIRECTION OUTPUT ;
    USE SIGNAL ;
    PORT
      LAYER M4 ;
        RECT  0 35.616 0.084 35.64 ;
    END
  END tap_d[87]
  PIN tap_d[88]
    DIRECTION OUTPUT ;
    USE SIGNAL ;
    PORT
      LAYER M4 ;
        RECT  0 35.712 0.084 35.736 ;
    END
  END tap_d[88]
  PIN tap_d[89]
    DIRECTION OUTPUT ;
    USE SIGNAL ;
    PORT
      LAYER M4 ;
        RECT  0 35.808 0.084 35.832 ;
    END
  END tap_d[89]
  PIN tap_d[8]
    DIRECTION OUTPUT ;
    USE SIGNAL ;
    PORT
      LAYER M4 ;
        RECT  0 27.792 0.084 27.816 ;
    END
  END tap_d[8]
  PIN tap_d[90]
    DIRECTION OUTPUT ;
    USE SIGNAL ;
    PORT
      LAYER M4 ;
        RECT  0 35.904 0.084 35.928 ;
    END
  END tap_d[90]
  PIN tap_d[91]
    DIRECTION OUTPUT ;
    USE SIGNAL ;
    PORT
      LAYER M4 ;
        RECT  0 36 0.084 36.024 ;
    END
  END tap_d[91]
  PIN tap_d[92]
    DIRECTION OUTPUT ;
    USE SIGNAL ;
    PORT
      LAYER M4 ;
        RECT  0 36.144 0.084 36.168 ;
    END
  END tap_d[92]
  PIN tap_d[93]
    DIRECTION OUTPUT ;
    USE SIGNAL ;
    PORT
      LAYER M4 ;
        RECT  0 36.24 0.084 36.264 ;
    END
  END tap_d[93]
  PIN tap_d[94]
    DIRECTION OUTPUT ;
    USE SIGNAL ;
    PORT
      LAYER M4 ;
        RECT  0 36.336 0.084 36.36 ;
    END
  END tap_d[94]
  PIN tap_d[95]
    DIRECTION OUTPUT ;
    USE SIGNAL ;
    PORT
      LAYER M4 ;
        RECT  0 36.432 0.084 36.456 ;
    END
  END tap_d[95]
  PIN tap_d[96]
    DIRECTION OUTPUT ;
    USE SIGNAL ;
    PORT
      LAYER M4 ;
        RECT  0 36.528 0.084 36.552 ;
    END
  END tap_d[96]
  PIN tap_d[97]
    DIRECTION OUTPUT ;
    USE SIGNAL ;
    PORT
      LAYER M4 ;
        RECT  0 36.624 0.084 36.648 ;
    END
  END tap_d[97]
  PIN tap_d[98]
    DIRECTION OUTPUT ;
    USE SIGNAL ;
    PORT
      LAYER M4 ;
        RECT  0 36.72 0.084 36.744 ;
    END
  END tap_d[98]
  PIN tap_d[99]
    DIRECTION OUTPUT ;
    USE SIGNAL ;
    PORT
      LAYER M4 ;
        RECT  0 36.816 0.084 36.84 ;
    END
  END tap_d[99]
  PIN tap_d[9]
    DIRECTION OUTPUT ;
    USE SIGNAL ;
    PORT
      LAYER M4 ;
        RECT  0 27.888 0.084 27.912 ;
    END
  END tap_d[9]
  PIN tie_hi
    DIRECTION OUTPUT ;
    USE SIGNAL ;
    PORT
      LAYER M3 ;
        RECT  0.936 103.618 0.954 103.656 ;
    END
  END tie_hi
  PIN tie_lo
    DIRECTION OUTPUT ;
    USE SIGNAL ;
    PORT
      LAYER M3 ;
        RECT  1.188 103.618 1.206 103.656 ;
    END
  END tie_lo
  PIN VDD
    DIRECTION INOUT ;
    USE POWER ;
    PORT
      LAYER M5 ;
        RECT  45.792 2.151 45.912 101.273 ;
        RECT  40.392 2.151 40.512 101.273 ;
        RECT  34.992 2.151 35.112 101.273 ;
        RECT  29.592 2.151 29.712 101.273 ;
        RECT  24.192 2.151 24.312 101.273 ;
        RECT  18.792 2.151 18.912 101.273 ;
        RECT  13.392 2.151 13.512 101.273 ;
        RECT  7.992 2.151 8.112 101.273 ;
        RECT  2.592 2.151 2.712 101.273 ;
    END
  END VDD
  PIN VSS
    DIRECTION INOUT ;
    USE GROUND ;
    PORT
      LAYER M5 ;
        RECT  45.6 2.137 45.72 101.259 ;
        RECT  40.2 2.137 40.32 101.259 ;
        RECT  34.8 2.137 34.92 101.259 ;
        RECT  29.4 2.137 29.52 101.259 ;
        RECT  24 2.137 24.12 101.259 ;
        RECT  18.6 2.137 18.72 101.259 ;
        RECT  13.2 2.137 13.32 101.259 ;
        RECT  7.8 2.137 7.92 101.259 ;
        RECT  2.4 2.137 2.52 101.259 ;
    END
  END VSS
  # OT_OBS_CLOSED layer=M5 d_um=1.536 added=127
  OBS
    LAYER RVTN ;
     RECT  2.16 2.16 50.49 2.295 ;
     RECT  2.16 2.565 50.49 2.835 ;
     RECT  2.16 3.105 50.49 3.375 ;
     RECT  2.16 3.645 50.49 3.915 ;
     RECT  2.16 4.185 50.49 4.455 ;
     RECT  2.16 4.725 50.49 4.995 ;
     RECT  2.16 5.265 50.49 5.535 ;
     RECT  2.16 5.805 50.49 6.075 ;
     RECT  2.16 6.345 50.49 6.615 ;
     RECT  2.16 6.885 50.49 7.155 ;
     RECT  2.16 7.425 50.49 7.695 ;
     RECT  2.16 7.965 50.49 8.235 ;
     RECT  2.16 8.505 50.49 8.775 ;
     RECT  2.16 9.045 50.49 9.315 ;
     RECT  2.16 9.585 50.49 9.855 ;
     RECT  2.16 10.125 50.49 10.395 ;
     RECT  2.16 10.665 50.49 10.935 ;
     RECT  2.16 11.205 50.49 11.475 ;
     RECT  2.16 11.745 50.49 12.015 ;
     RECT  2.16 12.285 50.49 12.555 ;
     RECT  2.16 12.825 50.49 13.095 ;
     RECT  2.16 13.365 50.49 13.635 ;
     RECT  2.16 13.905 50.49 14.175 ;
     RECT  2.16 14.445 50.49 14.715 ;
     RECT  2.16 14.985 50.49 15.255 ;
     RECT  2.16 15.525 50.49 15.795 ;
     RECT  2.16 16.065 50.49 16.335 ;
     RECT  2.16 16.605 50.49 16.875 ;
     RECT  2.16 17.145 50.49 17.415 ;
     RECT  2.16 17.685 50.49 17.955 ;
     RECT  2.16 18.225 50.49 18.495 ;
     RECT  2.16 18.765 50.49 19.035 ;
     RECT  2.16 19.305 50.49 19.575 ;
     RECT  2.16 19.845 50.49 20.115 ;
     RECT  2.16 20.385 50.49 20.655 ;
     RECT  2.16 20.925 50.49 21.195 ;
     RECT  2.16 21.465 50.49 21.735 ;
     RECT  2.16 22.005 50.49 22.275 ;
     RECT  2.16 22.545 50.49 22.815 ;
     RECT  2.16 23.085 50.49 23.355 ;
     RECT  2.16 23.625 50.49 23.895 ;
     RECT  2.16 24.165 50.49 24.435 ;
     RECT  2.16 24.705 50.49 24.975 ;
     RECT  2.16 25.245 50.49 25.515 ;
     RECT  2.16 25.785 50.49 26.055 ;
     RECT  2.16 26.325 50.49 26.595 ;
     RECT  2.16 26.865 50.49 27.135 ;
     RECT  2.16 27.405 50.49 27.675 ;
     RECT  2.16 27.945 50.49 28.215 ;
     RECT  2.16 28.485 50.49 28.755 ;
     RECT  2.16 29.025 50.49 29.295 ;
     RECT  2.16 29.565 50.49 29.835 ;
     RECT  2.16 30.105 50.49 30.375 ;
     RECT  2.16 30.645 50.49 30.915 ;
     RECT  2.16 31.185 50.49 31.455 ;
     RECT  2.16 31.725 50.49 31.995 ;
     RECT  2.16 32.265 50.49 32.535 ;
     RECT  2.16 32.805 50.49 33.075 ;
     RECT  2.16 33.345 50.49 33.615 ;
     RECT  2.16 33.885 50.49 34.155 ;
     RECT  2.16 34.425 50.49 34.695 ;
     RECT  2.16 34.965 50.49 35.235 ;
     RECT  2.16 35.505 50.49 35.775 ;
     RECT  2.16 36.045 50.49 36.315 ;
     RECT  2.16 36.585 50.49 36.855 ;
     RECT  2.16 37.125 50.49 37.395 ;
     RECT  2.16 37.665 50.49 37.935 ;
     RECT  2.16 38.205 50.49 38.475 ;
     RECT  2.16 38.745 50.49 39.015 ;
     RECT  2.16 39.285 50.49 39.555 ;
     RECT  2.16 39.825 50.49 40.095 ;
     RECT  2.16 40.365 50.49 40.635 ;
     RECT  2.16 40.905 50.49 41.175 ;
     RECT  2.16 41.445 50.49 41.715 ;
     RECT  2.16 41.985 50.49 42.255 ;
     RECT  2.16 42.525 50.49 42.795 ;
     RECT  2.16 43.065 50.49 43.335 ;
     RECT  2.16 43.605 50.49 43.875 ;
     RECT  2.16 44.145 50.49 44.415 ;
     RECT  2.16 44.685 50.49 44.955 ;
     RECT  2.16 45.225 50.49 45.495 ;
     RECT  2.16 45.765 50.49 46.035 ;
     RECT  2.16 46.305 50.49 46.575 ;
     RECT  2.16 46.845 50.49 47.115 ;
     RECT  2.16 47.385 50.49 47.655 ;
     RECT  2.16 47.925 50.49 48.195 ;
     RECT  2.16 48.465 50.49 48.735 ;
     RECT  2.16 49.005 50.49 49.275 ;
     RECT  2.16 49.545 50.49 49.815 ;
     RECT  2.16 50.085 50.49 50.355 ;
     RECT  2.16 50.625 50.49 50.895 ;
     RECT  2.16 51.165 50.49 51.435 ;
     RECT  2.16 51.705 50.49 51.975 ;
     RECT  2.16 52.245 50.49 52.515 ;
     RECT  2.16 52.785 50.49 53.055 ;
     RECT  2.16 53.325 50.49 53.595 ;
     RECT  2.16 53.865 50.49 54.135 ;
     RECT  2.16 54.405 50.49 54.675 ;
     RECT  2.16 54.945 50.49 55.215 ;
     RECT  2.16 55.485 50.49 55.755 ;
     RECT  2.16 56.025 50.49 56.295 ;
     RECT  2.16 56.565 50.49 56.835 ;
     RECT  2.16 57.105 50.49 57.375 ;
     RECT  2.16 57.645 50.49 57.915 ;
     RECT  2.16 58.185 50.49 58.455 ;
     RECT  2.16 58.725 50.49 58.995 ;
     RECT  2.16 59.265 50.49 59.535 ;
     RECT  2.16 59.805 50.49 60.075 ;
     RECT  2.16 60.345 50.49 60.615 ;
     RECT  2.16 60.885 50.49 61.155 ;
     RECT  2.16 61.425 50.49 61.695 ;
     RECT  2.16 61.965 50.49 62.235 ;
     RECT  2.16 62.505 50.49 62.775 ;
     RECT  2.16 63.045 50.49 63.315 ;
     RECT  2.16 63.585 50.49 63.855 ;
     RECT  2.16 64.125 50.49 64.395 ;
     RECT  2.16 64.665 50.49 64.935 ;
     RECT  2.16 65.205 50.49 65.475 ;
     RECT  2.16 65.745 50.49 66.015 ;
     RECT  2.16 66.285 50.49 66.555 ;
     RECT  2.16 66.825 50.49 67.095 ;
     RECT  2.16 67.365 50.49 67.635 ;
     RECT  2.16 67.905 50.49 68.175 ;
     RECT  2.16 68.445 50.49 68.715 ;
     RECT  2.16 68.985 50.49 69.255 ;
     RECT  2.16 69.525 50.49 69.795 ;
     RECT  2.16 70.065 50.49 70.335 ;
     RECT  2.16 70.605 50.49 70.875 ;
     RECT  2.16 71.145 50.49 71.415 ;
     RECT  2.16 71.685 50.49 71.955 ;
     RECT  2.16 72.225 50.49 72.495 ;
     RECT  2.16 72.765 50.49 73.035 ;
     RECT  2.16 73.305 50.49 73.575 ;
     RECT  2.16 73.845 50.49 74.115 ;
     RECT  2.16 74.385 50.49 74.655 ;
     RECT  2.16 74.925 50.49 75.195 ;
     RECT  2.16 75.465 50.49 75.735 ;
     RECT  2.16 76.005 50.49 76.275 ;
     RECT  2.16 76.545 50.49 76.815 ;
     RECT  2.16 77.085 50.49 77.355 ;
     RECT  2.16 77.625 50.49 77.895 ;
     RECT  2.16 78.165 50.49 78.435 ;
     RECT  2.16 78.705 50.49 78.975 ;
     RECT  2.16 79.245 50.49 79.515 ;
     RECT  2.16 79.785 50.49 80.055 ;
     RECT  2.16 80.325 50.49 80.595 ;
     RECT  2.16 80.865 50.49 81.135 ;
     RECT  2.16 81.405 50.49 81.675 ;
     RECT  2.16 81.945 50.49 82.215 ;
     RECT  2.16 82.485 50.49 82.755 ;
     RECT  2.16 83.025 50.49 83.295 ;
     RECT  2.16 83.565 50.49 83.835 ;
     RECT  2.16 84.105 50.49 84.375 ;
     RECT  2.16 84.645 50.49 84.915 ;
     RECT  2.16 85.185 50.49 85.455 ;
     RECT  2.16 85.725 50.49 85.995 ;
     RECT  2.16 86.265 50.49 86.535 ;
     RECT  2.16 86.805 50.49 87.075 ;
     RECT  2.16 87.345 50.49 87.615 ;
     RECT  2.16 87.885 50.49 88.155 ;
     RECT  2.16 88.425 50.49 88.695 ;
     RECT  2.16 88.965 50.49 89.235 ;
     RECT  2.16 89.505 50.49 89.775 ;
     RECT  2.16 90.045 50.49 90.315 ;
     RECT  2.16 90.585 50.49 90.855 ;
     RECT  2.16 91.125 50.49 91.395 ;
     RECT  2.16 91.665 50.49 91.935 ;
     RECT  2.16 92.205 50.49 92.475 ;
     RECT  2.16 92.745 50.49 93.015 ;
     RECT  2.16 93.285 50.49 93.555 ;
     RECT  2.16 93.825 50.49 94.095 ;
     RECT  2.16 94.365 50.49 94.635 ;
     RECT  2.16 94.905 50.49 95.175 ;
     RECT  2.16 95.445 50.49 95.715 ;
     RECT  2.16 95.985 50.49 96.255 ;
     RECT  2.16 96.525 50.49 96.795 ;
     RECT  2.16 97.065 50.49 97.335 ;
     RECT  2.16 97.605 50.49 97.875 ;
     RECT  2.16 98.145 50.49 98.415 ;
     RECT  2.16 98.685 50.49 98.955 ;
     RECT  2.16 99.225 50.49 99.495 ;
     RECT  2.16 99.765 50.49 100.035 ;
     RECT  2.16 100.305 50.49 100.575 ;
     RECT  2.16 100.845 50.49 101.115 ;
    LAYER RVTP ;
     RECT  2.16 2.295 50.49 2.565 ;
     RECT  2.16 2.835 50.49 3.105 ;
     RECT  2.16 3.375 50.49 3.645 ;
     RECT  2.16 3.915 50.49 4.185 ;
     RECT  2.16 4.455 50.49 4.725 ;
     RECT  2.16 4.995 50.49 5.265 ;
     RECT  2.16 5.535 50.49 5.805 ;
     RECT  2.16 6.075 50.49 6.345 ;
     RECT  2.16 6.615 50.49 6.885 ;
     RECT  2.16 7.155 50.49 7.425 ;
     RECT  2.16 7.695 50.49 7.965 ;
     RECT  2.16 8.235 50.49 8.505 ;
     RECT  2.16 8.775 50.49 9.045 ;
     RECT  2.16 9.315 50.49 9.585 ;
     RECT  2.16 9.855 50.49 10.125 ;
     RECT  2.16 10.395 50.49 10.665 ;
     RECT  2.16 10.935 50.49 11.205 ;
     RECT  2.16 11.475 50.49 11.745 ;
     RECT  2.16 12.015 50.49 12.285 ;
     RECT  2.16 12.555 50.49 12.825 ;
     RECT  2.16 13.095 50.49 13.365 ;
     RECT  2.16 13.635 50.49 13.905 ;
     RECT  2.16 14.175 50.49 14.445 ;
     RECT  2.16 14.715 50.49 14.985 ;
     RECT  2.16 15.255 50.49 15.525 ;
     RECT  2.16 15.795 50.49 16.065 ;
     RECT  2.16 16.335 50.49 16.605 ;
     RECT  2.16 16.875 50.49 17.145 ;
     RECT  2.16 17.415 50.49 17.685 ;
     RECT  2.16 17.955 50.49 18.225 ;
     RECT  2.16 18.495 50.49 18.765 ;
     RECT  2.16 19.035 50.49 19.305 ;
     RECT  2.16 19.575 50.49 19.845 ;
     RECT  2.16 20.115 50.49 20.385 ;
     RECT  2.16 20.655 50.49 20.925 ;
     RECT  2.16 21.195 50.49 21.465 ;
     RECT  2.16 21.735 50.49 22.005 ;
     RECT  2.16 22.275 50.49 22.545 ;
     RECT  2.16 22.815 50.49 23.085 ;
     RECT  2.16 23.355 50.49 23.625 ;
     RECT  2.16 23.895 50.49 24.165 ;
     RECT  2.16 24.435 50.49 24.705 ;
     RECT  2.16 24.975 50.49 25.245 ;
     RECT  2.16 25.515 50.49 25.785 ;
     RECT  2.16 26.055 50.49 26.325 ;
     RECT  2.16 26.595 50.49 26.865 ;
     RECT  2.16 27.135 50.49 27.405 ;
     RECT  2.16 27.675 50.49 27.945 ;
     RECT  2.16 28.215 50.49 28.485 ;
     RECT  2.16 28.755 50.49 29.025 ;
     RECT  2.16 29.295 50.49 29.565 ;
     RECT  2.16 29.835 50.49 30.105 ;
     RECT  2.16 30.375 50.49 30.645 ;
     RECT  2.16 30.915 50.49 31.185 ;
     RECT  2.16 31.455 50.49 31.725 ;
     RECT  2.16 31.995 50.49 32.265 ;
     RECT  2.16 32.535 50.49 32.805 ;
     RECT  2.16 33.075 50.49 33.345 ;
     RECT  2.16 33.615 50.49 33.885 ;
     RECT  2.16 34.155 50.49 34.425 ;
     RECT  2.16 34.695 50.49 34.965 ;
     RECT  2.16 35.235 50.49 35.505 ;
     RECT  2.16 35.775 50.49 36.045 ;
     RECT  2.16 36.315 50.49 36.585 ;
     RECT  2.16 36.855 50.49 37.125 ;
     RECT  2.16 37.395 50.49 37.665 ;
     RECT  2.16 37.935 50.49 38.205 ;
     RECT  2.16 38.475 50.49 38.745 ;
     RECT  2.16 39.015 50.49 39.285 ;
     RECT  2.16 39.555 50.49 39.825 ;
     RECT  2.16 40.095 50.49 40.365 ;
     RECT  2.16 40.635 50.49 40.905 ;
     RECT  2.16 41.175 50.49 41.445 ;
     RECT  2.16 41.715 50.49 41.985 ;
     RECT  2.16 42.255 50.49 42.525 ;
     RECT  2.16 42.795 50.49 43.065 ;
     RECT  2.16 43.335 50.49 43.605 ;
     RECT  2.16 43.875 50.49 44.145 ;
     RECT  2.16 44.415 50.49 44.685 ;
     RECT  2.16 44.955 50.49 45.225 ;
     RECT  2.16 45.495 50.49 45.765 ;
     RECT  2.16 46.035 50.49 46.305 ;
     RECT  2.16 46.575 50.49 46.845 ;
     RECT  2.16 47.115 50.49 47.385 ;
     RECT  2.16 47.655 50.49 47.925 ;
     RECT  2.16 48.195 50.49 48.465 ;
     RECT  2.16 48.735 50.49 49.005 ;
     RECT  2.16 49.275 50.49 49.545 ;
     RECT  2.16 49.815 50.49 50.085 ;
     RECT  2.16 50.355 50.49 50.625 ;
     RECT  2.16 50.895 50.49 51.165 ;
     RECT  2.16 51.435 50.49 51.705 ;
     RECT  2.16 51.975 50.49 52.245 ;
     RECT  2.16 52.515 50.49 52.785 ;
     RECT  2.16 53.055 50.49 53.325 ;
     RECT  2.16 53.595 50.49 53.865 ;
     RECT  2.16 54.135 50.49 54.405 ;
     RECT  2.16 54.675 50.49 54.945 ;
     RECT  2.16 55.215 50.49 55.485 ;
     RECT  2.16 55.755 50.49 56.025 ;
     RECT  2.16 56.295 50.49 56.565 ;
     RECT  2.16 56.835 50.49 57.105 ;
     RECT  2.16 57.375 50.49 57.645 ;
     RECT  2.16 57.915 50.49 58.185 ;
     RECT  2.16 58.455 50.49 58.725 ;
     RECT  2.16 58.995 50.49 59.265 ;
     RECT  2.16 59.535 50.49 59.805 ;
     RECT  2.16 60.075 50.49 60.345 ;
     RECT  2.16 60.615 50.49 60.885 ;
     RECT  2.16 61.155 50.49 61.425 ;
     RECT  2.16 61.695 50.49 61.965 ;
     RECT  2.16 62.235 50.49 62.505 ;
     RECT  2.16 62.775 50.49 63.045 ;
     RECT  2.16 63.315 50.49 63.585 ;
     RECT  2.16 63.855 50.49 64.125 ;
     RECT  2.16 64.395 50.49 64.665 ;
     RECT  2.16 64.935 50.49 65.205 ;
     RECT  2.16 65.475 50.49 65.745 ;
     RECT  2.16 66.015 50.49 66.285 ;
     RECT  2.16 66.555 50.49 66.825 ;
     RECT  2.16 67.095 50.49 67.365 ;
     RECT  2.16 67.635 50.49 67.905 ;
     RECT  2.16 68.175 50.49 68.445 ;
     RECT  2.16 68.715 50.49 68.985 ;
     RECT  2.16 69.255 50.49 69.525 ;
     RECT  2.16 69.795 50.49 70.065 ;
     RECT  2.16 70.335 50.49 70.605 ;
     RECT  2.16 70.875 50.49 71.145 ;
     RECT  2.16 71.415 50.49 71.685 ;
     RECT  2.16 71.955 50.49 72.225 ;
     RECT  2.16 72.495 50.49 72.765 ;
     RECT  2.16 73.035 50.49 73.305 ;
     RECT  2.16 73.575 50.49 73.845 ;
     RECT  2.16 74.115 50.49 74.385 ;
     RECT  2.16 74.655 50.49 74.925 ;
     RECT  2.16 75.195 50.49 75.465 ;
     RECT  2.16 75.735 50.49 76.005 ;
     RECT  2.16 76.275 50.49 76.545 ;
     RECT  2.16 76.815 50.49 77.085 ;
     RECT  2.16 77.355 50.49 77.625 ;
     RECT  2.16 77.895 50.49 78.165 ;
     RECT  2.16 78.435 50.49 78.705 ;
     RECT  2.16 78.975 50.49 79.245 ;
     RECT  2.16 79.515 50.49 79.785 ;
     RECT  2.16 80.055 50.49 80.325 ;
     RECT  2.16 80.595 50.49 80.865 ;
     RECT  2.16 81.135 50.49 81.405 ;
     RECT  2.16 81.675 50.49 81.945 ;
     RECT  2.16 82.215 50.49 82.485 ;
     RECT  2.16 82.755 50.49 83.025 ;
     RECT  2.16 83.295 50.49 83.565 ;
     RECT  2.16 83.835 50.49 84.105 ;
     RECT  2.16 84.375 50.49 84.645 ;
     RECT  2.16 84.915 50.49 85.185 ;
     RECT  2.16 85.455 50.49 85.725 ;
     RECT  2.16 85.995 50.49 86.265 ;
     RECT  2.16 86.535 50.49 86.805 ;
     RECT  2.16 87.075 50.49 87.345 ;
     RECT  2.16 87.615 50.49 87.885 ;
     RECT  2.16 88.155 50.49 88.425 ;
     RECT  2.16 88.695 50.49 88.965 ;
     RECT  2.16 89.235 50.49 89.505 ;
     RECT  2.16 89.775 50.49 90.045 ;
     RECT  2.16 90.315 50.49 90.585 ;
     RECT  2.16 90.855 50.49 91.125 ;
     RECT  2.16 91.395 50.49 91.665 ;
     RECT  2.16 91.935 50.49 92.205 ;
     RECT  2.16 92.475 50.49 92.745 ;
     RECT  2.16 93.015 50.49 93.285 ;
     RECT  2.16 93.555 50.49 93.825 ;
     RECT  2.16 94.095 50.49 94.365 ;
     RECT  2.16 94.635 50.49 94.905 ;
     RECT  2.16 95.175 50.49 95.445 ;
     RECT  2.16 95.715 50.49 95.985 ;
     RECT  2.16 96.255 50.49 96.525 ;
     RECT  2.16 96.795 50.49 97.065 ;
     RECT  2.16 97.335 50.49 97.605 ;
     RECT  2.16 97.875 50.49 98.145 ;
     RECT  2.16 98.415 50.49 98.685 ;
     RECT  2.16 98.955 50.49 99.225 ;
     RECT  2.16 99.495 50.49 99.765 ;
     RECT  2.16 100.035 50.49 100.305 ;
     RECT  2.16 100.575 50.49 100.845 ;
     RECT  2.16 101.115 50.49 101.25 ;
    LAYER M1 ;
     RECT  2.16 2.151 50.49 101.259 ;
    LAYER M2 ;
     RECT  0.031 23.796 0.103 23.814 ;
     RECT  0.103 47.322 0.139 47.34 ;
     RECT  0.103 48.366 0.139 49.374 ;
     RECT  0.103 50.706 0.139 50.724 ;
     RECT  0.103 65.448 0.139 65.97 ;
     RECT  0.103 27.216 0.175 27.234 ;
     RECT  0.103 32.238 0.175 32.454 ;
     RECT  0.103 33.93 0.175 34.146 ;
     RECT  0.103 34.938 0.175 34.956 ;
     RECT  0.103 54.576 0.175 54.594 ;
     RECT  0.103 55.836 0.175 55.854 ;
     RECT  0.103 68.922 0.175 68.94 ;
     RECT  0.103 72.936 0.175 73.53 ;
     RECT  0.103 31.23 0.203 31.248 ;
     RECT  0.175 32.238 0.203 32.724 ;
     RECT  0.175 33.93 0.203 34.956 ;
     RECT  0.103 37.521 0.203 37.539 ;
     RECT  0.103 40.878 0.203 41.202 ;
     RECT  0.139 47.322 0.203 50.724 ;
     RECT  0.103 58.122 0.203 58.14 ;
     RECT  0.139 64.908 0.203 65.97 ;
     RECT  0.175 26.496 0.211 27.234 ;
     RECT  0.103 28.458 0.211 28.476 ;
     RECT  0.203 47.322 0.239 50.454 ;
     RECT  0.139 43.956 0.247 44.514 ;
     RECT  0.103 45.468 0.247 45.99 ;
     RECT  0.239 47.322 0.247 47.574 ;
     RECT  0.247 43.956 0.275 45.99 ;
     RECT  0.175 55.836 0.275 56.394 ;
     RECT  0.103 42.57 0.463 42.588 ;
     RECT  0.275 43.956 0.463 45.594 ;
     RECT  0.211 25.758 0.499 28.476 ;
     RECT  0.103 29.466 0.499 29.484 ;
     RECT  0.139 67.842 0.499 67.86 ;
     RECT  0.175 68.922 0.499 68.976 ;
     RECT  0.499 25.758 0.535 29.484 ;
     RECT  0.203 33.93 0.535 34.416 ;
     RECT  0.463 42.57 0.535 42.714 ;
     RECT  0.247 47.286 0.535 47.574 ;
     RECT  0.499 51.678 0.535 51.696 ;
     RECT  0.103 52.992 0.535 53.514 ;
     RECT  0.275 55.836 0.535 55.854 ;
     RECT  0.103 62.514 0.535 63.108 ;
     RECT  0.535 25.758 0.571 29.592 ;
     RECT  0.283 100.242 0.931 100.26 ;
     RECT  0.679 101.088 0.931 101.106 ;
     RECT  0.751 5.346 1.147 5.364 ;
     RECT  0.967 6.624 1.147 6.642 ;
     RECT  0.103 23.598 1.147 23.814 ;
     RECT  1.147 23.598 1.183 24.426 ;
     RECT  0.571 25.758 1.183 29.628 ;
     RECT  0.103 64.098 1.183 64.116 ;
     RECT  0.203 64.908 1.183 65.466 ;
     RECT  1.147 6.624 1.363 7.344 ;
     RECT  1.147 5.346 1.471 5.832 ;
     RECT  1.363 6.624 1.471 7.794 ;
     RECT  1.543 3.654 1.615 3.672 ;
     RECT  1.471 5.346 1.615 7.794 ;
     RECT  0.931 100.242 1.687 101.106 ;
     RECT  1.615 3.654 1.831 4.104 ;
     RECT  1.579 2.808 1.867 2.826 ;
     RECT  1.615 5.346 1.867 8.424 ;
     RECT  1.867 10.206 1.903 10.224 ;
     RECT  1.183 23.598 1.903 29.628 ;
     RECT  0.211 30.726 1.903 31.212 ;
     RECT  1.831 3.654 1.939 4.284 ;
     RECT  1.867 5.31 1.939 8.424 ;
     RECT  1.903 9.756 1.939 10.224 ;
     RECT  1.939 9.756 1.975 10.494 ;
     RECT  1.831 11.646 1.975 11.664 ;
     RECT  1.867 2.574 2.011 2.826 ;
     RECT  1.939 3.654 2.011 8.424 ;
     RECT  1.687 100.08 2.011 101.106 ;
     RECT  2.011 2.574 2.047 8.424 ;
     RECT  2.011 99.54 2.047 101.106 ;
     RECT  2.047 2.538 2.083 8.424 ;
     RECT  1.975 9.756 2.083 11.664 ;
     RECT  1.399 98.082 2.119 98.1 ;
     RECT  2.083 9.756 2.155 11.844 ;
     RECT  0.535 47.196 2.155 47.574 ;
     RECT  0.535 62.478 2.155 63.108 ;
     RECT  1.183 64.098 2.155 65.466 ;
     RECT  0.103 70.074 2.155 70.092 ;
     RECT  2.119 74.628 2.155 74.646 ;
     RECT  0.535 75.546 2.155 75.564 ;
     RECT  2.119 97.92 2.155 98.1 ;
     RECT  2.047 98.928 2.155 101.106 ;
     RECT  2.083 2.538 2.16 8.604 ;
     RECT  2.155 9.756 2.16 11.934 ;
     RECT  1.903 23.598 2.16 31.212 ;
     RECT  0.203 32.436 2.16 32.724 ;
     RECT  0.535 33.858 2.16 34.416 ;
     RECT  0.499 35.208 2.16 35.334 ;
     RECT  2.155 37.908 2.16 37.926 ;
     RECT  0.535 39.186 2.16 39.816 ;
     RECT  0.535 41.346 2.16 41.364 ;
     RECT  0.535 42.57 2.16 42.75 ;
     RECT  0.463 43.776 2.16 45.594 ;
     RECT  2.155 47.016 2.16 47.574 ;
     RECT  0.239 48.366 2.16 50.076 ;
     RECT  0.535 51.408 2.16 51.696 ;
     RECT  0.535 52.794 2.16 53.514 ;
     RECT  0.175 54.576 2.16 54.864 ;
     RECT  0.535 55.656 2.16 55.854 ;
     RECT  0.535 60.624 2.16 60.642 ;
     RECT  2.155 62.208 2.16 65.466 ;
     RECT  2.155 66.456 2.16 66.474 ;
     RECT  0.499 67.842 2.16 68.976 ;
     RECT  2.155 70.002 2.16 70.092 ;
     RECT  0.103 71.154 2.16 71.784 ;
     RECT  0.175 72.576 2.16 73.53 ;
     RECT  2.155 74.628 2.16 76.068 ;
     RECT  2.155 77.904 2.16 77.922 ;
     RECT  1.435 92.52 2.16 92.538 ;
     RECT  1.867 97.146 2.16 97.164 ;
     RECT  2.155 97.92 2.16 101.106 ;
     RECT  2.16 2.151 2.263 101.259 ;
     RECT  2.263 2.106 2.371 101.259 ;
     RECT  2.371 2.106 2.399 101.529 ;
     RECT  2.399 2.151 2.795 101.529 ;
     RECT  2.299 0.036 2.831 0.054 ;
     RECT  2.335 103.59 2.831 103.608 ;
     RECT  2.795 2.151 3.127 101.448 ;
     RECT  3.127 1.728 3.407 101.448 ;
     RECT  3.595 103.59 3.947 103.608 ;
     RECT  3.407 1.728 4.235 101.259 ;
     RECT  4.711 103.59 4.811 103.608 ;
     RECT  4.963 0.036 5.099 0.054 ;
     RECT  4.235 2.106 5.135 101.259 ;
     RECT  6.079 0.036 6.179 0.054 ;
     RECT  5.135 2.151 6.439 101.259 ;
     RECT  5.863 103.59 6.503 103.608 ;
     RECT  6.439 1.728 6.755 101.259 ;
     RECT  6.755 2.106 7.079 101.259 ;
     RECT  6.799 102.006 7.331 102.024 ;
     RECT  8.095 103.59 8.231 103.608 ;
     RECT  7.079 2.151 8.347 101.259 ;
     RECT  8.347 2.106 8.491 101.259 ;
     RECT  8.491 2.106 8.591 101.529 ;
     RECT  8.591 2.106 8.987 101.448 ;
     RECT  8.987 2.151 9.023 101.448 ;
     RECT  9.023 2.151 9.095 101.376 ;
     RECT  7.051 0.036 9.671 0.054 ;
     RECT  10.687 0.036 11.399 0.054 ;
     RECT  9.463 103.59 12.443 103.608 ;
     RECT  12.415 0.036 12.551 0.054 ;
     RECT  9.095 2.151 13.315 101.259 ;
     RECT  13.315 2.151 13.415 101.448 ;
     RECT  13.315 0.108 13.531 0.126 ;
     RECT  13.531 0.036 13.559 0.126 ;
     RECT  13.559 0.036 13.631 0.054 ;
     RECT  13.675 103.59 14.207 103.608 ;
     RECT  15.007 103.59 16.799 103.608 ;
     RECT  13.415 2.151 16.843 101.259 ;
     RECT  16.843 1.728 17.123 101.259 ;
     RECT  17.123 2.151 18.499 101.259 ;
     RECT  19.003 0.036 19.103 0.054 ;
     RECT  18.859 103.59 19.859 103.608 ;
     RECT  18.499 2.106 20.363 101.259 ;
     RECT  21.343 0.036 21.407 0.054 ;
     RECT  20.363 2.151 21.883 101.259 ;
     RECT  21.883 2.106 21.955 101.259 ;
     RECT  21.955 1.728 22.271 101.259 ;
     RECT  22.351 0.036 22.523 0.054 ;
     RECT  22.271 2.106 22.595 101.259 ;
     RECT  22.243 103.59 22.991 103.608 ;
     RECT  23.251 0.036 23.351 0.054 ;
     RECT  22.595 2.151 23.719 101.259 ;
     RECT  23.719 1.728 23.999 101.259 ;
     RECT  24.115 1.152 24.431 1.17 ;
     RECT  24.331 102.546 24.431 102.564 ;
     RECT  24.655 103.59 24.755 103.608 ;
     RECT  23.999 2.151 25.483 101.259 ;
     RECT  25.483 1.728 25.691 101.259 ;
     RECT  25.663 0.036 25.763 0.054 ;
     RECT  25.691 2.151 26.635 101.259 ;
     RECT  25.843 103.59 26.699 103.608 ;
     RECT  26.635 1.728 26.951 101.259 ;
     RECT  26.887 0.108 27.031 0.126 ;
     RECT  27.031 0.036 27.275 0.126 ;
     RECT  27.859 103.59 28.255 103.608 ;
     RECT  27.275 0.036 28.463 0.054 ;
     RECT  28.255 103.446 28.463 103.608 ;
     RECT  28.463 103.518 28.859 103.608 ;
     RECT  26.951 2.151 28.903 101.259 ;
     RECT  29.191 0.036 29.435 0.054 ;
     RECT  28.903 2.106 29.515 101.259 ;
     RECT  29.515 2.106 29.579 101.448 ;
     RECT  29.579 2.151 29.651 101.448 ;
     RECT  28.859 103.59 29.831 103.608 ;
     RECT  30.559 0.036 30.659 0.054 ;
     RECT  29.651 2.151 31.567 101.259 ;
     RECT  31.567 1.728 32.099 101.259 ;
     RECT  31.747 0.036 32.819 0.054 ;
     RECT  32.099 2.151 32.935 101.259 ;
     RECT  32.935 1.728 33.179 101.259 ;
     RECT  30.883 103.59 33.215 103.608 ;
     RECT  33.907 0.036 34.151 0.054 ;
     RECT  34.195 103.59 34.331 103.608 ;
     RECT  35.095 1.152 35.195 1.17 ;
     RECT  34.879 0.036 35.699 0.054 ;
     RECT  33.179 2.151 36.391 101.259 ;
     RECT  36.391 2.106 37.435 101.259 ;
     RECT  35.095 103.59 37.463 103.608 ;
     RECT  37.435 1.728 37.643 101.259 ;
     RECT  38.947 103.518 38.983 103.536 ;
     RECT  38.983 103.518 39.227 103.608 ;
     RECT  39.523 0.036 40.099 0.054 ;
     RECT  39.227 103.59 40.235 103.608 ;
     RECT  37.643 2.151 40.243 101.259 ;
     RECT  40.099 0.036 40.271 0.126 ;
     RECT  40.271 0.108 40.415 0.126 ;
     RECT  40.351 103.356 40.487 103.572 ;
     RECT  40.243 1.728 40.667 101.259 ;
     RECT  40.487 103.446 41.035 103.572 ;
     RECT  41.035 103.446 41.207 103.608 ;
     RECT  41.107 0.036 41.387 0.054 ;
     RECT  41.207 103.446 41.387 103.464 ;
     RECT  42.007 103.59 42.575 103.608 ;
     RECT  42.547 0.036 42.583 0.054 ;
     RECT  40.667 2.151 42.727 101.259 ;
     RECT  42.583 0.036 42.755 0.126 ;
     RECT  42.755 0.036 43.223 0.054 ;
     RECT  42.727 2.106 43.303 101.259 ;
     RECT  43.303 1.656 43.439 101.259 ;
     RECT  43.483 103.59 44.123 103.608 ;
     RECT  43.439 2.106 44.375 101.259 ;
     RECT  44.131 103.518 44.591 103.536 ;
     RECT  43.015 102.276 44.671 102.294 ;
     RECT  44.671 102.051 44.995 102.294 ;
     RECT  44.995 102.051 45.131 102.654 ;
     RECT  45.131 102.051 45.499 102.294 ;
     RECT  45.355 0.576 45.707 0.594 ;
     RECT  45.499 102.006 45.707 102.294 ;
     RECT  44.851 103.59 45.751 103.608 ;
     RECT  46.255 0.108 46.399 0.126 ;
     RECT  46.399 0.036 46.499 0.126 ;
     RECT  45.751 103.518 46.679 103.608 ;
     RECT  46.679 103.59 47.479 103.608 ;
     RECT  44.375 2.151 47.767 101.259 ;
     RECT  46.499 0.036 48.443 0.054 ;
     RECT  47.767 2.106 48.443 101.259 ;
     RECT  48.443 2.151 48.847 101.259 ;
     RECT  47.479 103.518 49.019 103.608 ;
     RECT  48.847 2.151 49.279 101.484 ;
     RECT  49.019 103.554 49.307 103.608 ;
     RECT  49.243 0.036 49.415 0.054 ;
     RECT  49.279 2.106 49.559 101.484 ;
     RECT  49.307 103.59 49.631 103.608 ;
     RECT  49.559 2.106 50.207 101.259 ;
     RECT  50.207 2.151 50.49 101.259 ;
     RECT  50.49 2.196 50.495 5.364 ;
     RECT  50.49 6.246 50.495 10.044 ;
     RECT  50.49 84.15 50.495 84.366 ;
     RECT  50.495 2.268 50.531 5.364 ;
     RECT  50.49 12.726 50.531 12.744 ;
     RECT  50.495 84.348 50.531 84.366 ;
     RECT  50.49 93.87 50.531 94.554 ;
     RECT  50.495 7.056 50.567 10.044 ;
     RECT  50.495 6.246 50.603 6.264 ;
     RECT  50.531 93.87 50.603 94.428 ;
     RECT  50.531 2.268 50.639 5.328 ;
     RECT  50.567 10.026 50.675 10.044 ;
     RECT  50.639 2.268 50.711 5.184 ;
     RECT  50.711 3.078 50.747 5.184 ;
     RECT  50.747 3.348 50.783 5.184 ;
     RECT  50.567 7.056 50.783 9.234 ;
     RECT  50.49 95.76 50.783 95.778 ;
     RECT  50.783 3.348 50.819 3.636 ;
     RECT  50.783 7.056 50.819 8.694 ;
     RECT  50.819 3.348 50.855 3.366 ;
     RECT  50.783 4.5 50.891 5.184 ;
     RECT  50.711 2.268 50.927 2.286 ;
     RECT  50.819 7.056 50.927 8.424 ;
     RECT  50.755 0.036 50.963 0.054 ;
     RECT  50.927 8.406 50.963 8.424 ;
     RECT  50.927 7.056 50.999 7.344 ;
     RECT  50.603 94.41 50.999 94.428 ;
     RECT  50.891 5.076 51.035 5.184 ;
     RECT  51.035 5.076 51.179 5.094 ;
     RECT  50.49 79.218 51.179 79.614 ;
     RECT  50.999 7.326 51.287 7.344 ;
     RECT  50.49 80.676 51.359 82.314 ;
     RECT  51.179 79.596 51.503 79.614 ;
     RECT  51.359 80.676 51.575 81.504 ;
     RECT  51.575 80.676 51.683 80.694 ;
     RECT  51.575 81.486 51.755 81.504 ;
     RECT  51.359 82.296 51.863 82.314 ;
     RECT  45.707 102.276 52.367 102.294 ;
    LAYER M3 ;
     RECT  0.756 0.012 51.174 0.523 ;
     RECT  0.756 0.523 51.282 5.369 ;
     RECT  0.972 5.369 51.282 6.647 ;
     RECT  1.152 6.647 51.282 7.349 ;
     RECT  1.368 7.349 50.958 7.799 ;
     RECT  1.62 7.799 50.958 8.429 ;
     RECT  1.908 8.429 50.814 8.699 ;
     RECT  1.908 8.699 50.778 9.239 ;
     RECT  1.908 9.239 50.67 10.049 ;
     RECT  1.908 10.049 50.526 10.201 ;
     RECT  1.872 10.201 50.526 11.641 ;
     RECT  1.836 11.641 50.526 12.749 ;
     RECT  1.836 12.749 50.346 13.019 ;
     RECT  1.836 13.019 50.202 13.469 ;
     RECT  1.836 13.469 2.79 22.981 ;
     RECT  3.528 13.469 50.202 22.981 ;
     RECT  0.108 23.593 0.126 23.791 ;
     RECT  1.836 22.981 50.202 24.403 ;
     RECT  0.036 23.791 0.126 25.753 ;
     RECT  0.036 25.753 0.234 26.131 ;
     RECT  0.036 26.131 0.27 26.527 ;
     RECT  1.152 24.403 50.202 26.527 ;
     RECT  0.036 26.527 50.202 26.909 ;
     RECT  0.108 26.909 50.202 28.301 ;
     RECT  0.108 28.301 0.27 29.029 ;
     RECT  1.152 28.301 50.202 29.029 ;
     RECT  0.108 29.029 50.202 29.057 ;
     RECT  0.108 29.057 0.594 29.789 ;
     RECT  0.108 29.789 0.522 29.981 ;
     RECT  0.108 29.981 0.198 30.365 ;
     RECT  0.144 30.365 0.198 30.721 ;
     RECT  0.144 30.721 0.234 31.189 ;
     RECT  0.144 31.189 0.558 31.225 ;
     RECT  0.108 31.225 0.558 31.373 ;
     RECT  0.144 31.373 0.558 32.233 ;
     RECT  0.108 32.233 0.558 32.669 ;
     RECT  0.108 32.669 0.342 32.861 ;
     RECT  0.144 32.861 0.342 33.053 ;
     RECT  0.144 33.053 0.198 33.853 ;
     RECT  0.144 33.853 0.558 33.916 ;
     RECT  0.108 33.916 0.558 34.349 ;
     RECT  0.108 34.349 0.522 34.973 ;
     RECT  0.144 34.973 0.522 35.203 ;
     RECT  0.144 35.203 0.558 35.357 ;
     RECT  0.144 35.357 0.522 35.789 ;
     RECT  0.504 35.789 0.522 35.933 ;
     RECT  0.216 37.387 0.234 37.516 ;
     RECT  0.108 37.516 0.234 37.517 ;
     RECT  0.108 37.517 0.198 37.565 ;
     RECT  0.144 37.565 0.198 37.613 ;
     RECT  0.144 37.613 0.162 38.587 ;
     RECT  0.144 38.587 0.342 39.181 ;
     RECT  0.144 39.181 0.558 40.061 ;
     RECT  0.18 40.061 0.558 40.109 ;
     RECT  0.18 40.109 0.414 40.445 ;
     RECT  0.18 40.445 0.198 40.873 ;
     RECT  0.108 40.873 0.198 41.309 ;
     RECT  0.144 41.309 0.198 41.341 ;
     RECT  0.144 41.341 0.558 42.556 ;
     RECT  0.108 42.556 0.558 42.893 ;
     RECT  0.108 42.893 0.486 43.901 ;
     RECT  0.144 43.901 0.486 44.383 ;
     RECT  0.144 44.383 0.558 44.621 ;
     RECT  0.144 44.621 0.522 45.451 ;
     RECT  0.108 45.451 0.522 45.571 ;
     RECT  0.108 45.571 0.558 46.013 ;
     RECT  0.54 46.013 0.558 46.109 ;
     RECT  1.872 29.057 50.202 47.155 ;
     RECT  0.144 47.083 0.162 47.191 ;
     RECT  0.144 47.191 0.558 47.308 ;
     RECT  0.108 47.308 0.558 47.501 ;
     RECT  0.144 47.501 0.558 47.981 ;
     RECT  0.144 47.981 0.342 48.361 ;
     RECT  0.108 48.361 0.342 49.243 ;
     RECT  0.108 49.243 0.378 49.565 ;
     RECT  0.108 49.565 0.342 50.861 ;
     RECT  0.216 50.861 0.342 51.403 ;
     RECT  0.216 51.403 0.558 52.219 ;
     RECT  0.216 52.219 0.666 52.267 ;
     RECT  0.144 52.267 0.666 52.349 ;
     RECT  0.144 52.349 0.558 52.972 ;
     RECT  0.108 52.972 0.558 53.371 ;
     RECT  0.108 53.371 0.63 53.429 ;
     RECT  0.108 53.429 0.558 53.453 ;
     RECT  0.108 53.453 0.522 53.645 ;
     RECT  0.144 53.645 0.522 53.837 ;
     RECT  0.144 53.837 0.486 54.221 ;
     RECT  0.144 54.221 0.198 54.556 ;
     RECT  0.108 54.556 0.198 54.845 ;
     RECT  0.144 54.845 0.198 55.651 ;
     RECT  0.144 55.651 0.558 55.831 ;
     RECT  0.108 55.831 0.558 55.949 ;
     RECT  0.18 55.949 0.558 56.525 ;
     RECT  0.144 56.827 0.162 58.108 ;
     RECT  0.108 58.108 0.198 58.253 ;
     RECT  0.108 58.253 0.162 58.301 ;
     RECT  0.144 58.301 0.162 58.493 ;
     RECT  0.324 59.659 0.342 59.789 ;
     RECT  1.872 47.155 50.274 60.475 ;
     RECT  1.152 60.475 50.274 60.619 ;
     RECT  0.144 60.619 50.274 60.797 ;
     RECT  0.324 60.797 50.274 61.613 ;
     RECT  0.324 61.613 0.342 61.627 ;
     RECT  0.144 61.627 0.342 62.443 ;
     RECT  0.108 62.443 0.342 62.473 ;
     RECT  1.152 61.613 50.274 62.473 ;
     RECT  0.108 62.473 50.274 62.813 ;
     RECT  1.152 62.813 50.274 63.197 ;
     RECT  0.108 62.813 0.342 63.389 ;
     RECT  1.872 63.197 50.274 64.267 ;
     RECT  1.296 64.267 50.274 64.363 ;
     RECT  1.188 64.363 50.274 64.499 ;
     RECT  1.872 64.499 50.274 64.859 ;
     RECT  0.108 63.389 0.162 65.407 ;
     RECT  0.108 65.407 0.198 65.851 ;
     RECT  0.108 65.851 0.342 65.981 ;
     RECT  0.108 65.981 0.162 65.984 ;
     RECT  0.144 65.984 0.162 66.461 ;
     RECT  0.144 67.579 0.162 68.251 ;
     RECT  0.144 68.251 0.522 68.377 ;
     RECT  0.144 68.377 0.558 68.573 ;
     RECT  0.144 68.573 0.522 68.917 ;
     RECT  0.108 68.917 0.522 69.053 ;
     RECT  0.144 69.053 0.522 69.149 ;
     RECT  0.18 69.149 0.522 69.341 ;
     RECT  0.18 69.341 0.198 69.437 ;
     RECT  0.108 70.069 0.126 70.219 ;
     RECT  0.108 70.219 0.342 70.349 ;
     RECT  0.144 70.349 0.342 70.637 ;
     RECT  0.144 70.637 0.162 71.149 ;
     RECT  0.108 71.149 0.162 71.933 ;
     RECT  0.144 71.933 0.162 72.571 ;
     RECT  0.144 72.571 0.198 72.697 ;
     RECT  0.144 72.697 0.558 72.931 ;
     RECT  0.108 72.931 0.558 73.133 ;
     RECT  0.108 73.133 0.522 73.709 ;
     RECT  0.504 73.709 0.522 74.141 ;
     RECT  0.324 75.067 0.342 75.541 ;
     RECT  0.324 75.541 0.558 75.917 ;
     RECT  0.324 75.917 0.342 76.027 ;
     RECT  0.144 76.027 0.342 76.301 ;
     RECT  1.872 64.859 50.166 76.315 ;
     RECT  0.216 76.301 0.342 76.781 ;
     RECT  1.872 76.315 50.31 76.819 ;
     RECT  0.324 76.781 0.342 77.117 ;
     RECT  51.156 79.213 51.174 79.591 ;
     RECT  51.156 79.591 51.498 80.671 ;
     RECT  51.156 80.671 51.678 81.481 ;
     RECT  51.156 81.481 51.75 82.291 ;
     RECT  1.872 76.819 50.418 84.145 ;
     RECT  51.156 82.291 51.858 84.145 ;
     RECT  1.872 84.145 51.858 92.515 ;
     RECT  1.44 92.515 51.858 98.077 ;
     RECT  1.404 98.077 51.858 100.471 ;
     RECT  0.288 100.237 0.306 100.741 ;
     RECT  1.188 100.471 51.858 100.741 ;
     RECT  0.288 100.741 51.858 102.271 ;
     RECT  0.288 102.271 52.362 103.644 ;
    LAYER M4 ;
     RECT  0.025 26.88 0.06 26.904 ;
     RECT  0.06 26.88 0.173 77.4 ;
     RECT  0.173 27.072 1.177 77.4 ;
     RECT  1.045 6.864 1.181 6.888 ;
     RECT  1.237 6.336 1.421 6.36 ;
     RECT  0.469 100.272 1.525 100.296 ;
     RECT  1.525 100.08 1.717 100.296 ;
     RECT  1.717 100.08 1.909 100.92 ;
     RECT  0.853 8.448 2.053 8.472 ;
     RECT  1.909 100.08 2.101 101.208 ;
     RECT  1.681 2.784 2.245 2.808 ;
     RECT  1.421 5.712 2.245 6.36 ;
     RECT  2.245 2.784 2.293 4.44 ;
     RECT  2.245 5.664 2.293 6.552 ;
     RECT  2.053 7.968 2.293 8.472 ;
     RECT  2.293 5.664 2.365 8.472 ;
     RECT  2.252 9.648 2.365 9.672 ;
     RECT  1.853 1.728 2.408 1.752 ;
     RECT  2.293 2.784 2.408 4.536 ;
     RECT  2.365 5.664 2.408 9.672 ;
     RECT  1.177 26.88 2.408 77.4 ;
     RECT  2.293 98.016 2.408 98.04 ;
     RECT  2.101 99.168 2.408 101.208 ;
     RECT  2.408 1.728 2.6 101.208 ;
     RECT  2.6 1.728 2.704 101.262 ;
     RECT  2.704 100.32 2.717 101.262 ;
     RECT  2.485 103.536 2.761 103.56 ;
     RECT  2.704 1.728 2.765 9.672 ;
     RECT  2.704 72.72 2.765 77.4 ;
     RECT  2.704 25.152 2.801 71.736 ;
     RECT  2.704 97.488 2.819 99.288 ;
     RECT  2.765 72.72 2.837 77.304 ;
     RECT  2.761 102.624 2.867 103.56 ;
     RECT  2.801 66.048 2.873 71.112 ;
     RECT  2.837 76.032 2.873 77.304 ;
     RECT  2.867 102.624 2.963 102.648 ;
     RECT  2.873 66.288 3.017 71.112 ;
     RECT  2.704 10.704 3.053 13.08 ;
     RECT  2.873 76.272 3.089 77.304 ;
     RECT  2.765 2.304 3.107 9.672 ;
     RECT  2.801 25.152 3.122 64.968 ;
     RECT  3.089 77.28 3.125 77.304 ;
     RECT  2.837 73.296 3.197 74.568 ;
     RECT  2.819 97.488 3.241 99.192 ;
     RECT  3.107 2.88 3.244 9.672 ;
     RECT  3.244 2.928 3.341 9.672 ;
     RECT  3.122 25.632 3.377 64.968 ;
     RECT  3.017 66.288 3.377 70.872 ;
     RECT  3.089 76.272 3.413 76.296 ;
     RECT  3.053 11.376 3.532 13.08 ;
     RECT  3.377 66.288 3.557 69.864 ;
     RECT  3.341 3.024 3.587 9.672 ;
     RECT  3.197 73.344 3.737 74.568 ;
     RECT  3.397 1.152 3.761 1.176 ;
     RECT  3.532 11.376 3.779 12.936 ;
     RECT  3.737 73.344 3.809 74.328 ;
     RECT  3.557 67.44 3.827 69.864 ;
     RECT  3.761 1.152 3.917 1.224 ;
     RECT  3.377 70.848 4.093 70.872 ;
     RECT  3.557 66.288 4.097 66.408 ;
     RECT  3.827 69.6 4.097 69.864 ;
     RECT  3.241 98.064 4.105 99.192 ;
     RECT  4.097 69.84 4.133 69.864 ;
     RECT  2.717 100.32 4.141 101.448 ;
     RECT  3.377 25.68 4.169 64.968 ;
     RECT  3.587 4.416 4.213 9.672 ;
     RECT  3.779 12.192 4.307 12.936 ;
     RECT  4.193 1.728 4.309 1.752 ;
     RECT  3.587 3.024 4.309 3.432 ;
     RECT  3.827 67.44 4.313 68.328 ;
     RECT  4.169 25.68 4.457 64.92 ;
     RECT  4.457 25.68 4.499 64.824 ;
     RECT  2.293 0.144 4.597 0.168 ;
     RECT  4.307 12.192 4.601 12.504 ;
     RECT  4.499 26.304 4.601 64.824 ;
     RECT  4.597 0.144 4.652 0.6 ;
     RECT  4.652 0.048 4.739 0.6 ;
     RECT  4.601 12.192 4.777 12.216 ;
     RECT  4.213 4.416 4.781 7.992 ;
     RECT  4.739 0.096 4.817 0.6 ;
     RECT  4.781 4.416 4.835 7.464 ;
     RECT  4.105 98.064 4.835 98.088 ;
     RECT  4.601 64.272 4.853 64.824 ;
     RECT  4.777 99.744 4.883 99.768 ;
     RECT  4.309 1.728 4.885 3.432 ;
     RECT  4.835 4.416 4.885 6.984 ;
     RECT  4.093 70.848 4.921 71.16 ;
     RECT  4.601 26.304 5.069 63.24 ;
     RECT  5.069 26.304 5.105 58.728 ;
     RECT  4.885 1.728 5.113 6.984 ;
     RECT  4.213 8.976 5.125 9.672 ;
     RECT  4.097 66.384 5.389 66.408 ;
     RECT  5.389 66.384 5.425 66.6 ;
     RECT  4.141 100.896 5.425 101.448 ;
     RECT  4.817 0.096 5.537 0.12 ;
     RECT  5.125 8.976 5.537 9.72 ;
     RECT  5.425 66.24 5.605 66.6 ;
     RECT  5.605 66.192 5.641 66.648 ;
     RECT  5.425 100.848 5.641 101.448 ;
     RECT  5.105 26.784 5.681 58.728 ;
     RECT  5.641 100.32 5.725 101.448 ;
     RECT  5.681 42.528 5.753 58.728 ;
     RECT  5.641 66.192 5.845 67.272 ;
     RECT  4.313 68.304 5.845 68.328 ;
     RECT  5.725 100.848 5.891 101.448 ;
     RECT  5.101 72.672 5.893 72.696 ;
     RECT  5.893 72.384 5.933 72.696 ;
     RECT  4.921 70.704 5.969 71.16 ;
     RECT  5.113 1.728 6.028 6.792 ;
     RECT  6.028 2.88 6.041 6.792 ;
     RECT  5.845 65.808 6.109 68.328 ;
     RECT  5.425 69.456 6.109 69.48 ;
     RECT  6.041 2.88 6.131 5.736 ;
     RECT  5.933 72.384 6.217 72.408 ;
     RECT  5.537 8.976 6.229 9 ;
     RECT  6.085 6.816 6.253 7.464 ;
     RECT  6.229 8.784 6.253 9 ;
     RECT  4.777 11.664 6.253 12.216 ;
     RECT  4.853 64.272 6.257 64.584 ;
     RECT  6.253 10.8 6.293 12.216 ;
     RECT  5.753 42.816 6.323 58.728 ;
     RECT  3.809 74.304 6.433 74.328 ;
     RECT  6.131 4.56 6.437 5.736 ;
     RECT  6.253 6.816 6.437 9 ;
     RECT  6.133 0.576 6.509 0.6 ;
     RECT  6.323 56.064 6.541 58.728 ;
     RECT  5.681 26.784 6.545 41.16 ;
     RECT  6.545 38.16 6.563 41.16 ;
     RECT  6.541 56.064 6.577 58.776 ;
     RECT  6.323 42.816 6.617 54.792 ;
     RECT  5.969 71.136 6.649 71.16 ;
     RECT  5.891 100.896 6.659 101.448 ;
     RECT  5.069 60.192 6.685 63.24 ;
     RECT  6.257 64.272 6.685 64.488 ;
     RECT  6.433 73.488 6.757 74.328 ;
     RECT  6.437 6.816 6.761 6.984 ;
     RECT  6.617 42.816 6.829 54.744 ;
     RECT  6.757 73.488 6.829 75.144 ;
     RECT  6.829 42.576 6.865 54.744 ;
     RECT  6.577 56.064 6.865 59.112 ;
     RECT  6.685 60.192 6.865 64.488 ;
     RECT  6.145 77.28 6.865 77.304 ;
     RECT  6.563 38.256 6.901 41.16 ;
     RECT  6.865 42.192 6.901 54.744 ;
     RECT  6.028 1.728 6.949 1.752 ;
     RECT  6.217 72.24 6.973 72.408 ;
     RECT  6.949 1.152 7.157 1.752 ;
     RECT  6.109 65.808 7.189 69.48 ;
     RECT  6.997 103.536 7.193 103.56 ;
     RECT  6.293 10.8 7.196 10.824 ;
     RECT  6.437 7.968 7.197 9 ;
     RECT  7.196 9.984 7.197 10.824 ;
     RECT  6.545 26.784 7.397 37.128 ;
     RECT  6.649 71.136 7.405 71.208 ;
     RECT  6.973 72.192 7.405 72.408 ;
     RECT  6.131 2.88 7.477 3.432 ;
     RECT  6.437 4.56 7.477 5.688 ;
     RECT  6.761 6.816 7.477 6.84 ;
     RECT  7.405 71.136 7.477 72.408 ;
     RECT  7.157 1.728 7.513 1.752 ;
     RECT  7.477 2.88 7.513 6.84 ;
     RECT  7.541 103.488 7.58 103.512 ;
     RECT  7.148 99.744 7.585 99.768 ;
     RECT  6.829 73.536 7.621 75.144 ;
     RECT  7.093 76.128 7.621 76.152 ;
     RECT  7.58 103.344 7.667 103.512 ;
     RECT  6.293 12.192 7.669 12.216 ;
     RECT  7.585 99.168 7.669 99.768 ;
     RECT  6.901 38.256 7.765 54.744 ;
     RECT  6.865 56.064 7.765 64.488 ;
     RECT  7.189 65.808 7.765 69.528 ;
     RECT  7.513 1.728 7.808 6.84 ;
     RECT  7.197 7.968 7.808 10.824 ;
     RECT  7.669 11.952 7.808 12.216 ;
     RECT  7.669 25.248 7.808 25.272 ;
     RECT  7.397 26.736 7.808 37.128 ;
     RECT  7.765 38.256 7.808 64.488 ;
     RECT  7.765 65.808 7.808 70.008 ;
     RECT  7.477 71.136 7.808 72.552 ;
     RECT  7.621 73.536 7.808 76.152 ;
     RECT  6.865 77.28 7.808 78.024 ;
     RECT  4.789 85.92 7.808 85.944 ;
     RECT  7.669 99.024 7.808 99.768 ;
     RECT  6.659 100.944 7.808 101.448 ;
     RECT  7.667 103.44 7.859 103.512 ;
     RECT  6.565 0.096 8.017 0.12 ;
     RECT  7.808 1.728 8.104 101.448 ;
     RECT  8.017 0.096 8.156 0.168 ;
     RECT  8.104 1.728 8.165 7.368 ;
     RECT  8.165 2.88 8.201 7.368 ;
     RECT  8.104 26.928 8.237 68.376 ;
     RECT  8.156 0.048 8.243 0.168 ;
     RECT  8.243 0.144 8.291 0.168 ;
     RECT  8.201 2.88 8.291 4.632 ;
     RECT  8.104 25.152 8.291 25.272 ;
     RECT  8.237 61.344 8.345 68.376 ;
     RECT  8.201 5.712 8.425 7.368 ;
     RECT  8.425 5.808 8.435 7.368 ;
     RECT  8.165 1.728 8.444 1.752 ;
     RECT  8.291 2.88 8.483 4.536 ;
     RECT  8.444 0.576 8.531 1.752 ;
     RECT  8.104 76.752 8.597 77.976 ;
     RECT  8.549 103.536 8.633 103.56 ;
     RECT  8.345 61.536 8.675 68.376 ;
     RECT  8.104 73.776 8.705 75.48 ;
     RECT  8.237 26.928 8.741 60.168 ;
     RECT  8.675 66.144 8.813 68.376 ;
     RECT  8.741 26.928 8.957 45.768 ;
     RECT  8.531 1.728 9.029 1.752 ;
     RECT  8.957 26.928 9.029 45.624 ;
     RECT  8.104 100.896 9.065 101.448 ;
     RECT  8.104 8.784 9.097 9.048 ;
     RECT  8.597 77.952 9.097 77.976 ;
     RECT  9.029 28.08 9.109 45.624 ;
     RECT  8.104 10.272 9.245 11.016 ;
     RECT  8.483 2.88 9.301 2.904 ;
     RECT  8.104 72.192 9.313 72.264 ;
     RECT  8.104 69.456 9.349 71.208 ;
     RECT  9.313 72.192 9.349 72.984 ;
     RECT  8.705 74.352 9.349 75.48 ;
     RECT  8.597 76.752 9.349 76.776 ;
     RECT  8.104 85.92 9.349 85.944 ;
     RECT  9.349 69.456 9.395 72.984 ;
     RECT  9.301 2.304 9.425 2.904 ;
     RECT  9.425 2.832 9.452 2.904 ;
     RECT  8.531 0.576 9.461 0.6 ;
     RECT  9.109 28.08 9.461 45.576 ;
     RECT  8.741 46.752 9.461 60.168 ;
     RECT  9.395 69.456 9.461 71.784 ;
     RECT  9.461 46.752 9.491 59.016 ;
     RECT  8.435 6.432 9.493 7.368 ;
     RECT  9.452 2.832 9.5 3.432 ;
     RECT  8.483 4.512 9.5 4.536 ;
     RECT  9.421 13.056 9.533 13.08 ;
     RECT  9.349 14.784 9.533 14.808 ;
     RECT  9.097 8.496 9.541 9.048 ;
     RECT  8.675 61.536 9.569 65.064 ;
     RECT  9.241 82.608 9.569 82.632 ;
     RECT  8.104 80.4 9.601 80.424 ;
     RECT  9.097 77.952 9.637 78.12 ;
     RECT  9.569 61.728 9.713 65.064 ;
     RECT  9.493 5.712 9.749 7.368 ;
     RECT  9.133 102.048 9.779 102.072 ;
     RECT  9.541 8.496 9.785 10.248 ;
     RECT  9.491 49.488 9.785 59.016 ;
     RECT  9.785 49.488 9.821 53.016 ;
     RECT  9.749 5.712 9.836 6.84 ;
     RECT  9.836 5.664 9.923 6.84 ;
     RECT  9.395 72.768 9.925 72.984 ;
     RECT  9.349 74.352 9.925 76.776 ;
     RECT  9.637 77.952 9.961 78.36 ;
     RECT  9.601 79.536 9.961 80.424 ;
     RECT  9.5 2.832 10.067 4.536 ;
     RECT  9.685 0.096 10.073 0.216 ;
     RECT  8.813 66.144 10.105 66.888 ;
     RECT  8.813 68.016 10.105 68.376 ;
     RECT  9.925 72.768 10.109 76.776 ;
     RECT  9.713 64.32 10.124 65.064 ;
     RECT  10.105 66.144 10.124 68.376 ;
     RECT  9.785 8.496 10.141 9.144 ;
     RECT  9.461 34.224 10.181 45.576 ;
     RECT  9.491 46.752 10.181 48.408 ;
     RECT  10.124 64.32 10.211 68.376 ;
     RECT  10.109 72.768 10.211 76.2 ;
     RECT  9.349 85.488 10.217 85.944 ;
     RECT  10.211 66.144 10.253 68.376 ;
     RECT  9.923 5.712 10.259 6.84 ;
     RECT  10.253 66.672 10.259 68.376 ;
     RECT  9.029 26.928 10.261 26.952 ;
     RECT  9.461 28.08 10.261 33.096 ;
     RECT  10.261 26.928 10.289 33.096 ;
     RECT  10.181 34.224 10.289 39.816 ;
     RECT  9.461 69.552 10.289 71.784 ;
     RECT  10.259 66.672 10.297 66.696 ;
     RECT  10.073 0.096 10.316 0.12 ;
     RECT  9.785 54.048 10.325 59.016 ;
     RECT  10.067 3.312 10.357 4.536 ;
     RECT  10.357 3.312 10.397 4.584 ;
     RECT  10.316 0.048 10.403 0.12 ;
     RECT  9.065 100.896 10.429 101.016 ;
     RECT  10.289 26.928 10.433 33.048 ;
     RECT  9.961 77.952 10.433 80.424 ;
     RECT  9.461 60.144 10.501 60.168 ;
     RECT  10.325 54.048 10.505 58.728 ;
     RECT  10.403 0.096 10.541 0.12 ;
     RECT  10.289 70.08 10.541 71.784 ;
     RECT  10.181 46.752 10.609 48.12 ;
     RECT  10.433 79.488 10.685 80.424 ;
     RECT  9.713 61.728 10.717 63.24 ;
     RECT  10.211 64.32 10.717 65.064 ;
     RECT  10.433 77.952 10.721 78.36 ;
     RECT  10.259 6.816 10.748 6.84 ;
     RECT  10.141 8.304 10.748 9.144 ;
     RECT  10.211 72.768 10.748 74.712 ;
     RECT  10.501 60.144 10.753 60.456 ;
     RECT  10.717 61.728 10.753 65.064 ;
     RECT  10.289 34.896 10.787 39.816 ;
     RECT  9.821 49.68 10.789 53.016 ;
     RECT  10.748 72.384 10.835 74.712 ;
     RECT  10.181 40.896 10.861 45.576 ;
     RECT  10.609 46.656 10.861 48.12 ;
     RECT  10.753 60.144 10.861 65.064 ;
     RECT  10.748 6.816 10.883 9.144 ;
     RECT  10.861 40.896 10.901 48.12 ;
     RECT  10.787 34.896 10.937 34.92 ;
     RECT  10.901 41.712 10.937 48.12 ;
     RECT  10.211 75.84 10.973 76.2 ;
     RECT  10.685 79.488 11.009 79.56 ;
     RECT  10.789 49.536 11.113 53.016 ;
     RECT  10.397 3.312 11.132 3.48 ;
     RECT  10.937 44.352 11.189 48.12 ;
     RECT  11.132 2.88 11.219 3.48 ;
     RECT  10.259 5.712 11.261 5.736 ;
     RECT  10.861 60.096 11.261 65.064 ;
     RECT  10.259 68.016 11.297 68.376 ;
     RECT  10.787 35.904 11.329 39.816 ;
     RECT  11.113 49.488 11.329 53.016 ;
     RECT  10.505 54.048 11.329 58.68 ;
     RECT  10.433 26.928 11.333 27.336 ;
     RECT  11.189 46.656 11.333 48.12 ;
     RECT  10.433 29.04 11.365 33.048 ;
     RECT  11.329 35.904 11.369 39.912 ;
     RECT  10.069 1.728 11.405 1.8 ;
     RECT  9.785 10.224 11.405 10.248 ;
     RECT  10.835 72.768 11.441 74.712 ;
     RECT  11.333 26.928 11.513 26.952 ;
     RECT  11.369 36.624 11.513 39.912 ;
     RECT  11.441 72.816 11.513 74.712 ;
     RECT  11.429 0.576 11.545 0.6 ;
     RECT  11.219 3.408 11.612 3.48 ;
     RECT  10.397 4.56 11.612 4.584 ;
     RECT  10.883 6.864 11.621 9.144 ;
     RECT  11.365 29.04 11.657 33.672 ;
     RECT  11.621 9.12 11.689 9.144 ;
     RECT  10.541 70.08 11.689 71.256 ;
     RECT  11.261 60.096 11.725 64.872 ;
     RECT  11.657 29.04 11.729 33.048 ;
     RECT  10.973 76.176 11.761 76.2 ;
     RECT  10.825 77.376 11.761 77.448 ;
     RECT  11.621 6.864 11.801 7.992 ;
     RECT  11.729 29.04 11.801 31.704 ;
     RECT  11.689 69.84 11.801 71.256 ;
     RECT  11.801 29.04 11.977 30.6 ;
     RECT  11.333 47.184 11.977 48.12 ;
     RECT  11.801 6.864 11.989 6.984 ;
     RECT  11.977 47.184 12.013 48.216 ;
     RECT  11.329 49.488 12.013 58.68 ;
     RECT  11.513 36.624 12.017 36.648 ;
     RECT  11.948 35.616 12.035 35.64 ;
     RECT  11.989 6.288 12.089 6.984 ;
     RECT  11.612 3.408 12.125 4.584 ;
     RECT  12.013 47.184 12.125 58.68 ;
     RECT  11.513 72.816 12.125 72.84 ;
     RECT  10.937 41.712 12.157 43.368 ;
     RECT  11.689 9.12 12.161 9.72 ;
     RECT  12.125 48.672 12.193 58.68 ;
     RECT  11.725 59.712 12.193 64.872 ;
     RECT  11.761 76.176 12.197 77.544 ;
     RECT  11.545 0.144 12.229 0.6 ;
     RECT  11.513 74.4 12.229 74.712 ;
     RECT  11.513 37.824 12.277 39.912 ;
     RECT  12.157 41.472 12.277 43.368 ;
     RECT  11.009 79.488 12.325 79.512 ;
     RECT  11.189 44.352 12.409 45.576 ;
     RECT  11.825 2.304 12.421 2.328 ;
     RECT  12.325 79.056 12.445 79.512 ;
     RECT  12.476 68.304 12.517 68.328 ;
     RECT  12.409 67.248 12.589 67.272 ;
     RECT  12.421 2.16 12.613 2.328 ;
     RECT  12.125 3.408 12.613 4.008 ;
     RECT  12.62 11.856 12.625 11.88 ;
     RECT  12.409 44.352 12.661 46.2 ;
     RECT  12.125 47.184 12.661 47.304 ;
     RECT  10.429 100.896 12.661 101.208 ;
     RECT  12.229 0.144 12.805 0.648 ;
     RECT  11.801 69.84 12.841 70.728 ;
     RECT  12.613 2.16 12.901 4.008 ;
     RECT  12.805 0.096 12.947 0.648 ;
     RECT  12.437 5.712 13.093 5.736 ;
     RECT  12.625 11.376 13.093 11.88 ;
     RECT  12.044 102.624 13.139 102.648 ;
     RECT  11.801 7.968 13.165 7.992 ;
     RECT  12.161 9.12 13.165 9.624 ;
     RECT  12.947 0.528 13.169 0.648 ;
     RECT  12.901 1.728 13.208 4.008 ;
     RECT  13.093 5.616 13.208 5.736 ;
     RECT  12.089 6.912 13.208 6.984 ;
     RECT  13.165 7.968 13.208 9.624 ;
     RECT  13.093 10.608 13.208 11.88 ;
     RECT  8.291 25.152 13.208 25.176 ;
     RECT  12.625 27.36 13.208 27.384 ;
     RECT  11.977 28.944 13.208 30.6 ;
     RECT  11.801 31.68 13.208 31.704 ;
     RECT  11.729 33.024 13.208 33.048 ;
     RECT  11.989 34.512 13.208 34.536 ;
     RECT  12.277 37.824 13.208 43.368 ;
     RECT  12.661 44.352 13.208 47.304 ;
     RECT  12.193 48.672 13.208 64.872 ;
     RECT  12.589 66.768 13.208 67.272 ;
     RECT  12.517 68.304 13.208 68.616 ;
     RECT  12.841 69.84 13.208 70.776 ;
     RECT  12.229 74.4 13.208 75.432 ;
     RECT  12.197 77.04 13.208 77.544 ;
     RECT  12.445 78.576 13.208 79.512 ;
     RECT  10.217 85.92 13.208 85.944 ;
     RECT  12.997 98.64 13.208 98.664 ;
     RECT  13.045 99.744 13.208 99.768 ;
     RECT  12.661 100.896 13.208 101.448 ;
     RECT  13.169 0.576 13.385 0.648 ;
     RECT  13.208 1.728 13.504 101.448 ;
     RECT  13.504 100.896 13.523 101.448 ;
     RECT  13.504 60.864 13.619 64.968 ;
     RECT  13.504 66.48 13.619 66.504 ;
     RECT  13.504 45.216 13.637 45.576 ;
     RECT  13.504 75.6 13.66 78.696 ;
     RECT  13.66 76.368 13.67 78.696 ;
     RECT  13.385 0.624 13.673 0.648 ;
     RECT  13.504 39.792 13.709 41.736 ;
     RECT  13.504 73.392 13.715 74.136 ;
     RECT  13.633 103.536 13.717 103.56 ;
     RECT  13.504 1.728 13.745 9.624 ;
     RECT  13.504 68.4 13.753 68.424 ;
     RECT  13.504 48.96 13.763 48.984 ;
     RECT  13.504 51.312 13.763 59.064 ;
     RECT  13.637 45.216 13.853 45.48 ;
     RECT  13.745 1.728 13.889 6.312 ;
     RECT  13.67 76.368 13.889 78.648 ;
     RECT  13.763 51.36 13.961 51.768 ;
     RECT  13.889 77.28 13.961 78.648 ;
     RECT  13.504 70.56 14.003 70.584 ;
     RECT  13.504 72.096 14.003 72.12 ;
     RECT  13.504 85.92 14.003 85.944 ;
     RECT  13.763 52.992 14.069 59.064 ;
     RECT  13.745 7.44 14.105 9.624 ;
     RECT  13.889 1.728 14.213 5.736 ;
     RECT  14.069 52.992 14.213 55.752 ;
     RECT  13.961 77.28 14.213 77.544 ;
     RECT  13.709 40.656 14.321 41.736 ;
     RECT  14.213 52.992 14.321 53.4 ;
     RECT  13.715 74.112 14.321 74.136 ;
     RECT  13.504 99.216 14.332 99.24 ;
     RECT  13.961 78.528 14.429 78.648 ;
     RECT  14.069 56.88 14.465 59.064 ;
     RECT  14.105 7.44 14.501 7.464 ;
     RECT  13.504 47.184 14.501 47.832 ;
     RECT  14.429 78.624 14.501 78.648 ;
     RECT  14.465 58.944 14.537 59.064 ;
     RECT  14.321 41.472 14.569 41.736 ;
     RECT  13.504 42.72 14.569 43.368 ;
     RECT  13.853 45.216 14.569 45.24 ;
     RECT  14.321 52.992 14.573 53.016 ;
     RECT  14.537 59.04 14.573 59.064 ;
     RECT  14.213 1.728 14.579 5.688 ;
     RECT  13.523 100.896 14.597 100.92 ;
     RECT  14.579 2.928 14.653 5.688 ;
     RECT  13.619 60.864 14.675 64.728 ;
     RECT  14.213 54.384 14.717 55.752 ;
     RECT  14.569 44.64 14.753 45.24 ;
     RECT  13.961 51.744 14.753 51.768 ;
     RECT  14.717 55.2 14.753 55.752 ;
     RECT  14.465 56.88 14.753 57.96 ;
     RECT  14.675 60.864 14.753 60.888 ;
     RECT  14.569 41.472 14.789 43.368 ;
     RECT  14.753 56.88 14.789 57.72 ;
     RECT  14.675 61.872 14.789 64.728 ;
     RECT  14.789 43.152 14.861 43.368 ;
     RECT  14.753 45.216 14.861 45.24 ;
     RECT  14.789 61.872 14.861 62.616 ;
     RECT  14.677 102.624 14.867 102.648 ;
     RECT  14.653 3.648 14.915 5.688 ;
     RECT  14.861 43.344 14.933 43.368 ;
     RECT  14.915 3.888 14.969 5.688 ;
     RECT  14.861 61.872 14.969 62.568 ;
     RECT  14.789 63.936 14.969 64.728 ;
     RECT  13.504 11.424 15.041 11.448 ;
     RECT  14.213 77.28 15.164 77.304 ;
     RECT  15.164 76.944 15.205 77.304 ;
     RECT  14.597 100.896 15.251 101.448 ;
     RECT  14.105 9.072 15.253 9.624 ;
     RECT  15.205 76.656 15.329 77.304 ;
     RECT  15.253 8.544 15.395 9.624 ;
     RECT  14.969 3.936 15.437 5.688 ;
     RECT  14.821 6.912 15.469 6.936 ;
     RECT  14.789 41.712 15.617 41.736 ;
     RECT  14.482 0.144 15.644 0.168 ;
     RECT  15.469 6.672 15.685 6.936 ;
     RECT  15.505 72.96 15.689 72.984 ;
     RECT  15.644 0.048 15.731 0.168 ;
     RECT  14.579 1.728 15.757 1.8 ;
     RECT  15.685 5.712 15.833 6.936 ;
     RECT  15.437 3.936 15.937 4.584 ;
     RECT  15.329 76.896 15.941 77.304 ;
     RECT  15.757 1.728 15.973 2.328 ;
     RECT  15.98 78.72 16.009 78.744 ;
     RECT  16.009 78.72 16.067 79.032 ;
     RECT  15.395 8.544 16.081 9.528 ;
     RECT  16.067 79.008 16.093 79.032 ;
     RECT  16.081 7.968 16.157 9.528 ;
     RECT  15.941 76.896 16.157 76.92 ;
     RECT  15.833 6.768 16.333 6.936 ;
     RECT  16.157 7.968 16.333 7.992 ;
     RECT  15.731 0.096 16.441 0.168 ;
     RECT  15.973 1.152 16.441 2.904 ;
     RECT  16.441 0.096 16.547 2.904 ;
     RECT  16.547 1.728 16.549 2.904 ;
     RECT  15.937 3.888 16.549 4.584 ;
     RECT  15.251 101.424 16.549 101.448 ;
     RECT  16.547 0.096 16.595 0.312 ;
     RECT  16.549 1.728 16.613 4.584 ;
     RECT  15.833 5.712 16.613 5.736 ;
     RECT  16.613 1.728 16.643 5.736 ;
     RECT  16.549 101.424 16.643 102.072 ;
     RECT  16.595 0.096 16.691 0.12 ;
     RECT  16.643 101.424 16.801 101.448 ;
     RECT  16.643 3.888 16.837 5.736 ;
     RECT  16.333 6.768 16.837 7.992 ;
     RECT  16.757 99.216 16.841 99.24 ;
     RECT  16.837 3.888 16.877 7.992 ;
     RECT  16.877 6.288 16.921 7.992 ;
     RECT  14.501 47.184 17.089 47.208 ;
     RECT  17.089 47.088 17.129 47.208 ;
     RECT  16.921 6.768 17.171 7.992 ;
     RECT  16.801 101.184 17.219 101.448 ;
     RECT  17.089 99.744 17.411 99.768 ;
     RECT  16.877 3.888 17.561 5.16 ;
     RECT  17.612 0.144 17.693 0.168 ;
     RECT  17.219 101.424 17.756 101.448 ;
     RECT  17.693 0.144 17.777 0.264 ;
     RECT  17.171 6.768 17.909 7.416 ;
     RECT  16.643 1.728 18.085 2.904 ;
     RECT  17.561 3.888 18.085 4.008 ;
     RECT  17.561 5.04 18.125 5.16 ;
     RECT  17.909 6.288 18.125 7.416 ;
     RECT  18.061 98.64 18.133 98.664 ;
     RECT  18.085 1.728 18.161 4.008 ;
     RECT  13.504 25.152 18.205 25.176 ;
     RECT  18.161 1.104 18.245 4.008 ;
     RECT  18.125 5.04 18.325 7.416 ;
     RECT  17.756 101.424 18.419 101.496 ;
     RECT  18.419 101.424 18.493 101.448 ;
     RECT  18.245 1.92 18.608 4.008 ;
     RECT  18.325 5.04 18.608 7.464 ;
     RECT  16.157 9.504 18.608 9.528 ;
     RECT  18.205 25.152 18.608 25.272 ;
     RECT  17.129 47.088 18.608 47.112 ;
     RECT  14.789 57.696 18.608 57.72 ;
     RECT  14.969 61.968 18.608 62.568 ;
     RECT  14.969 64.704 18.608 64.728 ;
     RECT  18.133 98.64 18.608 99.192 ;
     RECT  18.493 101.376 18.608 101.448 ;
     RECT  18.325 0.096 18.817 0.12 ;
     RECT  18.608 1.92 18.904 101.448 ;
     RECT  18.904 6.816 19.037 7.368 ;
     RECT  18.904 1.92 19.277 3.528 ;
     RECT  18.817 0.048 19.619 0.12 ;
     RECT  19.637 0.576 19.721 0.6 ;
     RECT  18.904 4.56 19.873 5.736 ;
     RECT  19.037 7.344 19.909 7.368 ;
     RECT  18.904 8.352 19.909 8.376 ;
     RECT  19.873 5.712 19.957 5.736 ;
     RECT  18.904 9.504 19.973 10.296 ;
     RECT  19.909 7.344 20.009 8.376 ;
     RECT  19.957 5.712 20.053 5.784 ;
     RECT  18.904 100.896 20.06 101.448 ;
     RECT  19.277 1.728 20.099 3.528 ;
     RECT  20.099 3.408 20.108 3.528 ;
     RECT  19.873 4.56 20.108 4.584 ;
     RECT  20.009 7.872 20.117 8.376 ;
     RECT  20.06 100.896 20.147 101.496 ;
     RECT  20.053 5.712 20.189 6.84 ;
     RECT  20.189 5.712 20.261 5.784 ;
     RECT  20.473 99.744 20.579 99.768 ;
     RECT  19.973 9.648 20.701 10.296 ;
     RECT  20.677 0.096 20.873 0.12 ;
     RECT  20.099 1.728 20.917 2.328 ;
     RECT  18.904 47.088 20.941 47.112 ;
     RECT  20.108 3.408 20.989 4.584 ;
     RECT  20.917 1.104 21.085 2.328 ;
     RECT  20.989 3.408 21.085 3.528 ;
     RECT  20.989 4.56 21.089 4.584 ;
     RECT  20.941 47.088 21.089 47.304 ;
     RECT  20.833 102.624 21.155 102.648 ;
     RECT  21.085 1.104 21.197 3.528 ;
     RECT  20.701 9.648 21.373 9.72 ;
     RECT  20.189 6.816 21.397 6.84 ;
     RECT  21.197 1.728 21.443 3.528 ;
     RECT  21.443 1.728 21.529 2.904 ;
     RECT  21.529 2.832 21.587 2.904 ;
     RECT  20.261 5.712 21.593 5.736 ;
     RECT  21.397 6.816 21.637 6.888 ;
     RECT  21.692 0.048 21.779 0.072 ;
     RECT  21.733 5.136 21.817 5.16 ;
     RECT  21.625 102.576 21.923 102.6 ;
     RECT  20.147 100.896 22.021 101.448 ;
     RECT  21.637 6.768 22.025 6.888 ;
     RECT  22.021 100.896 22.307 101.496 ;
     RECT  21.373 8.88 22.313 9.72 ;
     RECT  18.904 61.968 22.417 62.568 ;
     RECT  21.587 2.88 22.421 2.904 ;
     RECT  22.373 6.288 22.457 6.312 ;
     RECT  22.313 8.88 22.961 9.528 ;
     RECT  22.957 4.56 22.993 4.584 ;
     RECT  22.921 0.576 23.029 0.6 ;
     RECT  22.993 3.936 23.173 4.584 ;
     RECT  23.029 0.576 23.177 0.696 ;
     RECT  23.177 0.576 23.219 0.6 ;
     RECT  23.173 3.936 23.365 5.16 ;
     RECT  21.529 1.728 23.461 1.8 ;
     RECT  23.365 3.936 23.461 5.688 ;
     RECT  23.461 1.728 23.605 2.28 ;
     RECT  23.461 3.936 23.605 5.832 ;
     RECT  18.904 64.704 23.605 64.728 ;
     RECT  23.605 47.28 23.845 47.304 ;
     RECT  23.893 11.424 23.929 11.448 ;
     RECT  23.852 0.048 23.939 0.168 ;
     RECT  23.605 1.728 24.008 5.832 ;
     RECT  23.461 7.104 24.008 7.128 ;
     RECT  22.961 9.504 24.008 9.528 ;
     RECT  23.929 10.512 24.008 11.448 ;
     RECT  18.904 25.248 24.008 25.272 ;
     RECT  23.845 47.136 24.008 47.304 ;
     RECT  18.904 57.696 24.008 57.72 ;
     RECT  22.417 61.872 24.008 62.568 ;
     RECT  23.605 64.416 24.008 64.728 ;
     RECT  22.307 100.896 24.008 101.448 ;
     RECT  23.939 0.096 24.181 0.168 ;
     RECT  24.181 0.096 24.289 0.216 ;
     RECT  24.008 1.728 24.304 101.448 ;
     RECT  24.304 64.704 24.401 64.872 ;
     RECT  24.289 0.096 24.419 0.312 ;
     RECT  24.401 64.848 24.419 64.872 ;
     RECT  24.304 100.08 24.437 101.448 ;
     RECT  24.419 0.096 24.467 0.216 ;
     RECT  24.304 7.872 24.473 8.52 ;
     RECT  24.304 50.736 24.473 51.336 ;
     RECT  24.473 50.736 24.553 50.76 ;
     RECT  24.304 5.472 24.563 6.888 ;
     RECT  24.467 0.096 24.689 0.12 ;
     RECT  24.304 10.8 24.689 11.448 ;
     RECT  24.689 10.8 24.833 10.824 ;
     RECT  24.563 5.664 24.905 6.888 ;
     RECT  24.304 1.728 25.085 4.2 ;
     RECT  24.304 25.248 25.139 25.272 ;
     RECT  25.085 2.304 25.285 4.2 ;
     RECT  24.473 8.496 25.297 8.52 ;
     RECT  25.297 8.496 25.337 8.712 ;
     RECT  24.905 5.712 25.589 6.888 ;
     RECT  25.285 2.304 25.715 4.584 ;
     RECT  25.589 5.712 25.769 6.312 ;
     RECT  25.765 1.152 25.873 1.176 ;
     RECT  25.873 0.576 25.949 1.176 ;
     RECT  25.949 0.576 26.053 0.6 ;
     RECT  25.715 2.304 26.053 2.904 ;
     RECT  24.304 47.136 26.06 47.16 ;
     RECT  24.437 100.896 26.065 101.448 ;
     RECT  25.769 6.24 26.129 6.312 ;
     RECT  26.06 47.136 26.147 47.304 ;
     RECT  26.101 103.44 26.156 103.464 ;
     RECT  25.337 8.592 26.165 8.712 ;
     RECT  26.053 0.096 26.195 0.6 ;
     RECT  26.156 102.624 26.243 103.464 ;
     RECT  26.147 47.136 26.453 47.16 ;
     RECT  25.901 7.44 26.521 7.464 ;
     RECT  26.165 8.592 26.521 8.616 ;
     RECT  26.053 1.728 26.909 2.904 ;
     RECT  25.715 3.936 26.909 4.584 ;
     RECT  26.909 1.728 26.989 4.584 ;
     RECT  26.195 0.096 27.065 0.12 ;
     RECT  26.129 6.288 27.065 6.312 ;
     RECT  26.989 1.728 27.217 5.16 ;
     RECT  26.521 7.44 27.313 8.616 ;
     RECT  26.065 100.896 27.349 100.968 ;
     RECT  26.773 102.048 27.349 102.072 ;
     RECT  27.313 7.44 27.493 8.712 ;
     RECT  26.089 10.752 27.749 10.776 ;
     RECT  27.217 3.936 27.925 5.16 ;
     RECT  27.925 3.936 28.019 5.736 ;
     RECT  27.349 100.896 28.019 102.072 ;
     RECT  24.304 24.096 28.289 24.12 ;
     RECT  27.217 1.728 28.403 2.904 ;
     RECT  28.019 100.896 28.405 101.448 ;
     RECT  26.243 103.44 28.7 103.464 ;
     RECT  28.7 102.624 28.787 103.464 ;
     RECT  28.787 103.344 28.933 103.464 ;
     RECT  28.933 103.344 28.973 103.512 ;
     RECT  28.748 0.048 29.005 0.072 ;
     RECT  28.019 3.984 29.029 5.736 ;
     RECT  28.403 2.832 29.077 2.904 ;
     RECT  29.029 3.984 29.077 5.784 ;
     RECT  27.493 6.864 29.077 8.712 ;
     RECT  29.005 0.048 29.123 0.312 ;
     RECT  29.077 2.832 29.125 8.712 ;
     RECT  29.123 0.048 29.225 0.216 ;
     RECT  28.973 103.392 29.333 103.512 ;
     RECT  28.403 1.728 29.408 1.752 ;
     RECT  29.125 2.832 29.408 9.288 ;
     RECT  28.393 23.376 29.408 23.4 ;
     RECT  24.304 57.696 29.408 57.72 ;
     RECT  24.304 61.968 29.408 62.568 ;
     RECT  24.304 68.112 29.408 68.136 ;
     RECT  28.892 99.168 29.408 99.192 ;
     RECT  28.405 100.896 29.408 101.352 ;
     RECT  29.408 1.728 29.501 101.352 ;
     RECT  29.225 0.048 29.555 0.168 ;
     RECT  29.501 1.728 29.704 101.448 ;
     RECT  29.555 0.048 29.843 0.072 ;
     RECT  29.704 57.6 29.843 57.72 ;
     RECT  29.704 1.728 29.891 9.288 ;
     RECT  29.891 4.56 29.909 9.288 ;
     RECT  29.843 57.6 29.987 57.624 ;
     RECT  29.909 4.56 30.122 9 ;
     RECT  29.891 1.728 30.188 3.192 ;
     RECT  30.122 4.56 30.227 6.888 ;
     RECT  30.188 1.152 30.275 3.192 ;
     RECT  29.333 103.392 30.373 103.416 ;
     RECT  30.227 4.56 30.377 6.84 ;
     RECT  29.704 10.272 30.557 10.296 ;
     RECT  30.122 7.872 30.737 9 ;
     RECT  30.737 7.872 30.851 8.568 ;
     RECT  30.769 0.144 30.853 0.168 ;
     RECT  30.275 1.728 30.877 3.192 ;
     RECT  30.377 4.704 30.917 6.84 ;
     RECT  30.373 102.624 30.947 103.416 ;
     RECT  31.013 0.096 31.097 0.12 ;
     RECT  29.704 100.896 31.277 101.448 ;
     RECT  30.877 1.728 31.378 3.432 ;
     RECT  29.704 58.704 31.529 58.728 ;
     RECT  30.917 4.704 31.637 5.784 ;
     RECT  31.378 1.728 31.813 3.48 ;
     RECT  31.637 4.704 31.813 5.112 ;
     RECT  31.813 1.728 31.859 5.112 ;
     RECT  31.859 1.728 31.916 2.328 ;
     RECT  30.917 6.816 31.957 6.84 ;
     RECT  31.859 3.408 32.069 5.112 ;
     RECT  31.277 100.896 32.099 101.016 ;
     RECT  30.851 8.544 32.101 8.568 ;
     RECT  31.916 1.152 32.245 2.328 ;
     RECT  32.245 0.576 32.341 2.328 ;
     RECT  32.341 0.096 32.357 2.328 ;
     RECT  30.947 103.392 32.425 103.416 ;
     RECT  32.357 1.152 32.435 2.328 ;
     RECT  32.357 0.096 32.483 0.12 ;
     RECT  32.101 8.544 32.669 8.616 ;
     RECT  32.425 102.624 32.675 103.416 ;
     RECT  32.669 8.544 32.753 9.144 ;
     RECT  31.957 6.816 32.965 7.464 ;
     RECT  32.069 3.408 33.037 5.016 ;
     RECT  32.893 98.64 33.041 98.664 ;
     RECT  32.435 1.728 33.073 2.328 ;
     RECT  33.037 3.36 33.073 5.016 ;
     RECT  32.245 101.184 33.148 101.448 ;
     RECT  33.148 101.184 33.299 101.208 ;
     RECT  32.749 58.704 33.365 58.728 ;
     RECT  32.675 103.392 33.397 103.416 ;
     RECT  33.073 1.728 33.443 5.016 ;
     RECT  33.443 2.256 33.493 5.016 ;
     RECT  32.965 6.288 33.548 7.464 ;
     RECT  33.493 2.256 33.605 5.16 ;
     RECT  33.548 6.192 33.605 7.464 ;
     RECT  33.605 2.256 33.685 7.464 ;
     RECT  32.753 8.544 33.685 8.568 ;
     RECT  33.685 2.256 33.74 8.568 ;
     RECT  33.74 2.256 33.769 9.096 ;
     RECT  33.769 8.496 33.781 9.096 ;
     RECT  33.769 2.256 33.797 7.464 ;
     RECT  33.001 99.744 33.829 99.768 ;
     RECT  33.397 103.392 33.925 103.56 ;
     RECT  33.925 103.296 34.115 103.56 ;
     RECT  34.115 103.392 34.259 103.56 ;
     RECT  33.829 99.168 34.453 99.768 ;
     RECT  33.596 100.896 34.657 100.92 ;
     RECT  33.797 2.256 34.765 7.224 ;
     RECT  34.765 1.728 34.808 7.224 ;
     RECT  33.781 8.496 34.808 9.528 ;
     RECT  29.704 61.968 34.808 62.568 ;
     RECT  29.704 68.112 34.808 68.136 ;
     RECT  34.453 99.168 34.808 99.816 ;
     RECT  34.657 100.896 34.808 101.4 ;
     RECT  34.808 1.728 35.104 101.4 ;
     RECT  35.104 100.896 35.125 101.4 ;
     RECT  35.104 7.968 35.381 7.992 ;
     RECT  35.104 1.728 35.497 6.888 ;
     RECT  33.781 0.096 35.557 0.12 ;
     RECT  35.104 62.16 35.597 62.184 ;
     RECT  35.125 100.896 35.857 101.448 ;
     RECT  35.104 99.792 35.957 99.816 ;
     RECT  35.104 9.504 36.097 10.344 ;
     RECT  35.497 1.728 36.316 5.16 ;
     RECT  34.259 103.392 36.421 103.416 ;
     RECT  35.557 0.096 36.611 0.6 ;
     RECT  36.421 102.624 36.611 103.416 ;
     RECT  36.62 0.048 36.707 0.072 ;
     RECT  35.497 6.288 36.785 6.888 ;
     RECT  36.316 4.56 36.803 5.16 ;
     RECT  35.104 68.112 37.004 68.136 ;
     RECT  37.004 67.248 37.045 68.136 ;
     RECT  37.033 72.672 37.045 72.936 ;
     RECT  36.097 9.36 37.073 10.344 ;
     RECT  37.045 66.336 37.091 68.136 ;
     RECT  37.045 72.432 37.117 72.936 ;
     RECT  35.857 100.896 37.141 101.208 ;
     RECT  37.091 66.336 37.145 66.36 ;
     RECT  37.117 72.432 37.181 72.792 ;
     RECT  36.803 4.56 37.388 4.584 ;
     RECT  37.388 4.272 37.475 4.584 ;
     RECT  36.316 1.728 37.493 3.192 ;
     RECT  36.611 103.248 37.501 103.416 ;
     RECT  36.785 6.288 37.537 6.408 ;
     RECT  37.475 4.56 37.541 4.584 ;
     RECT  37.181 72.432 37.573 72.696 ;
     RECT  37.493 1.728 37.577 3.432 ;
     RECT  37.537 5.712 37.621 6.408 ;
     RECT  36.853 7.92 37.649 7.944 ;
     RECT  37.501 103.248 37.763 103.56 ;
     RECT  37.825 0.576 37.909 0.6 ;
     RECT  37.621 6.288 37.969 6.408 ;
     RECT  37.909 0.096 38.003 0.6 ;
     RECT  37.969 6.288 38.009 6.888 ;
     RECT  38.009 6.384 38.053 6.888 ;
     RECT  38.003 0.096 38.081 0.12 ;
     RECT  38.108 99.552 38.195 99.576 ;
     RECT  37.573 69.84 38.333 69.864 ;
     RECT  37.141 100.896 38.387 101.448 ;
     RECT  37.897 65.52 38.437 65.544 ;
     RECT  38.437 65.52 38.509 66.024 ;
     RECT  38.509 65.52 38.545 66.072 ;
     RECT  38.387 101.424 38.621 101.448 ;
     RECT  37.573 71.808 38.653 72.696 ;
     RECT  38.285 7.536 38.689 7.56 ;
     RECT  38.437 4.704 38.697 4.728 ;
     RECT  37.091 68.064 38.725 68.136 ;
     RECT  38.697 3.984 38.729 4.728 ;
     RECT  38.653 71.808 38.761 72.792 ;
     RECT  38.761 71.664 38.765 72.792 ;
     RECT  38.729 3.984 38.797 4.008 ;
     RECT  38.401 70.56 38.797 70.584 ;
     RECT  38.765 71.664 38.797 72.744 ;
     RECT  38.689 7.536 38.837 8.04 ;
     RECT  38.725 68.064 38.905 68.712 ;
     RECT  38.581 86.016 38.905 86.04 ;
     RECT  38.905 85.488 38.989 86.04 ;
     RECT  37.763 103.248 39.077 103.512 ;
     RECT  37.577 1.728 39.121 2.856 ;
     RECT  38.797 3.888 39.121 4.008 ;
     RECT  38.905 68.064 39.125 69.048 ;
     RECT  39.013 0.576 39.205 0.6 ;
     RECT  38.053 6.384 39.253 6.408 ;
     RECT  38.837 7.536 39.253 7.56 ;
     RECT  38.989 86.016 39.26 86.04 ;
     RECT  39.253 6.384 39.337 7.56 ;
     RECT  39.205 0.096 39.347 0.6 ;
     RECT  39.121 1.728 39.452 4.008 ;
     RECT  37.073 9.36 39.625 9.384 ;
     RECT  39.337 5.904 39.685 7.56 ;
     RECT  39.625 9.36 39.697 10.2 ;
     RECT  38.797 70.56 39.841 72.744 ;
     RECT  39.841 69.552 39.949 72.744 ;
     RECT  39.949 69.552 40.093 72.84 ;
     RECT  39.347 0.576 40.129 0.6 ;
     RECT  39.452 1.68 40.129 4.008 ;
     RECT  40.129 0.576 40.208 4.008 ;
     RECT  39.685 5.712 40.208 7.56 ;
     RECT  39.697 9.264 40.208 10.2 ;
     RECT  39.085 11.424 40.208 11.448 ;
     RECT  38.545 65.52 40.208 66.936 ;
     RECT  39.125 68.064 40.208 68.424 ;
     RECT  40.093 69.552 40.208 73.032 ;
     RECT  40.049 83.232 40.208 83.256 ;
     RECT  39.26 86.016 40.208 86.376 ;
     RECT  40.069 88.896 40.208 88.92 ;
     RECT  40.021 90.528 40.208 90.552 ;
     RECT  39.877 99.744 40.208 99.768 ;
     RECT  40.208 0.576 40.307 100.992 ;
     RECT  40.307 1.728 40.4 100.992 ;
     RECT  40.4 1.728 40.504 101.262 ;
     RECT  40.307 0.576 40.637 0.6 ;
     RECT  40.504 89.472 40.643 90.024 ;
     RECT  39.077 103.248 40.777 103.56 ;
     RECT  40.777 103.248 40.889 103.608 ;
     RECT  40.643 89.472 40.933 89.496 ;
     RECT  40.889 103.248 41.317 103.56 ;
     RECT  40.504 9.072 41.321 10.824 ;
     RECT  40.504 91.152 41.365 91.176 ;
     RECT  41.317 103.152 41.459 103.56 ;
     RECT  40.504 100.896 41.507 100.92 ;
     RECT  40.504 75.216 41.533 75.24 ;
     RECT  41.533 74.688 41.573 75.24 ;
     RECT  40.504 5.664 41.597 5.736 ;
     RECT  40.504 6.816 41.597 7.656 ;
     RECT  41.597 5.664 41.609 7.656 ;
     RECT  40.504 65.712 41.645 73.56 ;
     RECT  40.504 1.728 41.653 1.8 ;
     RECT  40.504 2.832 41.653 4.536 ;
     RECT  41.609 6.24 41.681 7.656 ;
     RECT  41.612 88.224 41.699 88.248 ;
     RECT  40.504 77.952 41.713 77.976 ;
     RECT  41.653 1.728 41.749 4.536 ;
     RECT  41.749 1.728 41.753 5.16 ;
     RECT  41.645 65.712 42.077 72.984 ;
     RECT  42.077 65.712 42.113 68.376 ;
     RECT  42.037 93.456 42.121 93.48 ;
     RECT  41.321 10.8 42.133 10.824 ;
     RECT  41.681 6.288 42.185 7.656 ;
     RECT  42.133 10.8 42.253 10.872 ;
     RECT  41.713 77.472 42.253 77.976 ;
     RECT  42.077 69.456 42.329 69.48 ;
     RECT  42.253 77.184 42.361 77.976 ;
     RECT  42.284 91.728 42.371 91.752 ;
     RECT  42.229 0.096 42.469 0.12 ;
     RECT  42.185 7.632 42.545 7.656 ;
     RECT  42.469 0.096 42.581 0.552 ;
     RECT  42.185 6.288 42.625 6.312 ;
     RECT  41.753 2.88 42.659 5.16 ;
     RECT  42.572 92.928 42.659 92.952 ;
     RECT  41.321 9.072 42.661 9.288 ;
     RECT  42.253 10.8 42.661 11.688 ;
     RECT  42.659 3.36 42.757 5.16 ;
     RECT  42.077 71.232 42.761 72.984 ;
     RECT  42.113 65.712 42.833 68.136 ;
     RECT  41.459 103.248 42.869 103.56 ;
     RECT  42.833 65.712 42.941 66.936 ;
     RECT  42.581 0.528 42.977 0.552 ;
     RECT  41.573 74.688 43.009 74.712 ;
     RECT  42.941 65.712 43.013 65.784 ;
     RECT  43.004 92.256 43.091 92.328 ;
     RECT  41.753 1.728 43.181 1.8 ;
     RECT  42.757 3.36 43.229 5.88 ;
     RECT  43.009 74.688 43.229 75.48 ;
     RECT  42.361 76.464 43.261 77.976 ;
     RECT  43.229 75.216 43.333 75.48 ;
     RECT  43.261 76.464 43.333 78.696 ;
     RECT  42.761 71.232 43.337 72.888 ;
     RECT  43.333 75.216 43.379 78.696 ;
     RECT  42.38 94.656 43.397 94.68 ;
     RECT  43.337 71.232 43.429 72.84 ;
     RECT  42.833 68.112 43.475 68.136 ;
     RECT  43.397 94.656 43.481 95.16 ;
     RECT  43.429 70.704 43.517 72.84 ;
     RECT  43.379 75.456 43.525 78.696 ;
     RECT  43.091 92.304 43.525 92.328 ;
     RECT  43.525 76.8 43.549 78.696 ;
     RECT  43.229 3.36 43.697 5.736 ;
     RECT  43.181 1.728 43.717 2.328 ;
     RECT  43.697 3.36 43.717 4.056 ;
     RECT  43.481 94.656 43.859 94.68 ;
     RECT  43.717 1.728 43.877 4.056 ;
     RECT  43.517 70.992 43.907 72.84 ;
     RECT  42.869 103.248 43.973 103.512 ;
     RECT  42.661 9.072 44.053 11.688 ;
     RECT  44.053 8.448 44.089 11.688 ;
     RECT  44.089 7.968 44.161 11.688 ;
     RECT  44.161 7.44 44.237 11.688 ;
     RECT  44.197 93.456 44.281 93.48 ;
     RECT  44.237 9.072 44.345 11.688 ;
     RECT  43.525 75.456 44.377 75.816 ;
     RECT  44.345 10.464 44.525 11.688 ;
     RECT  44.377 75.12 44.557 75.816 ;
     RECT  43.549 76.8 44.557 79.032 ;
     RECT  44.237 7.44 44.561 7.992 ;
     RECT  43.697 5.136 44.581 5.736 ;
     RECT  43.973 103.248 44.597 103.56 ;
     RECT  43.907 71.616 44.629 72.84 ;
     RECT  43.333 74.112 44.629 74.136 ;
     RECT  44.684 0.144 44.771 0.168 ;
     RECT  44.557 75.12 44.821 79.032 ;
     RECT  43.877 1.728 44.945 4.008 ;
     RECT  44.581 5.136 44.945 5.784 ;
     RECT  44.945 1.728 44.957 5.784 ;
     RECT  44.561 7.44 45.025 7.464 ;
     RECT  44.597 103.248 45.025 103.272 ;
     RECT  44.629 71.616 45.061 74.136 ;
     RECT  44.821 75.12 45.061 79.176 ;
     RECT  45.025 103.152 45.065 103.272 ;
     RECT  44.957 2.016 45.157 5.784 ;
     RECT  45.025 6.768 45.157 7.464 ;
     RECT  44.953 84.912 45.277 84.936 ;
     RECT  44.989 86.016 45.277 86.04 ;
     RECT  45.169 102.048 45.421 102.072 ;
     RECT  45.157 2.016 45.608 7.464 ;
     RECT  44.345 9.072 45.608 9.096 ;
     RECT  44.525 11.232 45.608 11.688 ;
     RECT  43.013 65.712 45.608 65.736 ;
     RECT  45.061 71.616 45.608 79.176 ;
     RECT  45.277 84.912 45.608 86.04 ;
     RECT  44.54 92.928 45.608 92.952 ;
     RECT  45.421 101.472 45.608 102.072 ;
     RECT  45.608 2.016 45.827 102.072 ;
     RECT  45.827 2.016 45.904 101.262 ;
     RECT  45.781 0.096 45.965 0.12 ;
     RECT  45.904 85.488 46.019 85.512 ;
     RECT  45.904 2.016 46.067 6.84 ;
     RECT  46.067 2.016 46.108 6.408 ;
     RECT  45.904 82.608 46.109 82.632 ;
     RECT  45.065 103.152 46.133 103.176 ;
     RECT  46.108 2.016 46.165 6.312 ;
     RECT  45.904 74.16 46.181 77.352 ;
     RECT  45.904 10.848 46.253 12.36 ;
     RECT  45.904 78.672 46.253 79.224 ;
     RECT  46.316 0.528 46.403 0.552 ;
     RECT  45.904 88.32 46.441 88.344 ;
     RECT  46.253 78.72 46.505 79.224 ;
     RECT  46.505 78.72 46.577 78.984 ;
     RECT  46.165 1.728 46.585 6.312 ;
     RECT  45.904 71.616 46.685 73.08 ;
     RECT  46.685 71.616 46.721 72.888 ;
     RECT  46.721 72.24 46.739 72.888 ;
     RECT  46.739 72.24 46.793 72.84 ;
     RECT  46.793 72.576 46.829 72.84 ;
     RECT  46.253 11.232 46.835 12.36 ;
     RECT  46.181 74.16 46.901 76.872 ;
     RECT  46.585 1.728 46.937 5.784 ;
     RECT  45.904 7.968 46.969 9.288 ;
     RECT  46.937 1.728 46.997 1.848 ;
     RECT  46.133 103.152 47.009 103.56 ;
     RECT  46.997 1.68 47.081 1.848 ;
     RECT  46.901 74.4 47.081 76.872 ;
     RECT  47.081 75.408 47.117 76.872 ;
     RECT  47.173 6.864 47.18 6.888 ;
     RECT  46.969 7.968 47.18 10.248 ;
     RECT  47.117 75.648 47.18 76.872 ;
     RECT  47.18 75.648 47.225 76.968 ;
     RECT  47.225 76.176 47.267 76.968 ;
     RECT  47.081 1.728 47.297 1.848 ;
     RECT  47.267 76.224 47.297 76.296 ;
     RECT  46.937 2.88 47.369 5.784 ;
     RECT  47.081 74.4 47.369 74.424 ;
     RECT  47.005 88.896 47.369 88.92 ;
     RECT  47.324 87.696 47.411 87.72 ;
     RECT  47.297 76.224 47.441 76.248 ;
     RECT  47.009 103.152 47.468 103.512 ;
     RECT  47.468 102.624 47.555 103.512 ;
     RECT  46.835 11.424 47.725 12.36 ;
     RECT  47.725 11.424 47.765 12.552 ;
     RECT  47.297 1.728 47.873 1.752 ;
     RECT  47.18 6.864 47.939 10.248 ;
     RECT  47.369 2.88 47.977 3.432 ;
     RECT  47.797 0.528 47.987 0.552 ;
     RECT  47.369 4.512 48.085 5.784 ;
     RECT  47.939 6.864 48.085 7.464 ;
     RECT  47.977 2.832 48.131 3.432 ;
     RECT  47.689 89.472 48.179 89.544 ;
     RECT  47.765 12.528 48.197 12.552 ;
     RECT  48.188 0.048 48.275 0.072 ;
     RECT  47.939 8.496 48.325 10.248 ;
     RECT  48.325 8.496 48.449 10.296 ;
     RECT  48.517 76.8 48.553 76.824 ;
     RECT  47.725 101.472 48.563 101.496 ;
     RECT  48.553 76.8 48.665 77.016 ;
     RECT  47.555 103.296 48.689 103.512 ;
     RECT  48.085 4.512 48.755 7.464 ;
     RECT  48.665 76.992 48.769 77.016 ;
     RECT  48.449 8.496 48.773 9.24 ;
     RECT  48.769 76.992 48.809 77.112 ;
     RECT  48.755 4.512 48.841 5.256 ;
     RECT  48.809 77.088 48.841 77.112 ;
     RECT  48.841 4.416 48.845 5.256 ;
     RECT  47.765 11.424 48.845 11.448 ;
     RECT  48.773 8.496 48.899 9.144 ;
     RECT  48.841 77.088 48.917 77.208 ;
     RECT  48.845 4.416 48.947 5.208 ;
     RECT  48.947 4.416 48.989 5.16 ;
     RECT  48.449 10.272 48.989 10.296 ;
     RECT  48.625 75.168 48.989 75.192 ;
     RECT  48.131 2.88 48.995 3.432 ;
     RECT  48.917 77.184 49.025 77.208 ;
     RECT  48.689 103.296 49.168 103.56 ;
     RECT  48.995 3.216 49.237 3.432 ;
     RECT  48.989 4.416 49.237 4.968 ;
     RECT  48.755 6.288 49.237 7.464 ;
     RECT  48.179 89.472 49.249 89.496 ;
     RECT  49.168 103.296 49.313 103.608 ;
     RECT  49.285 0.096 49.385 0.12 ;
     RECT  48.913 13.008 49.385 13.032 ;
     RECT  49.237 6.288 49.457 7.56 ;
     RECT  48.899 9.12 49.457 9.144 ;
     RECT  49.445 1.728 49.529 1.752 ;
     RECT  49.313 103.296 49.628 103.512 ;
     RECT  49.345 77.856 49.673 78.12 ;
     RECT  49.705 90.576 49.788 90.6 ;
     RECT  49.788 90.528 49.789 90.6 ;
     RECT  49.673 77.856 49.817 77.88 ;
     RECT  49.789 90.528 49.897 90.552 ;
     RECT  49.457 6.288 49.907 7.464 ;
     RECT  49.628 102.624 49.907 103.512 ;
     RECT  49.907 6.864 50.041 7.464 ;
     RECT  50.041 6.864 50.099 6.888 ;
     RECT  49.907 102.624 50.099 103.416 ;
     RECT  49.237 3.216 50.105 4.968 ;
     RECT  50.105 3.216 50.281 3.24 ;
     RECT  50.245 99.168 50.281 99.192 ;
     RECT  50.281 2.88 50.317 3.24 ;
     RECT  50.281 98.64 50.483 99.192 ;
     RECT  50.317 2.304 50.573 3.24 ;
     RECT  50.636 0.576 50.723 0.6 ;
     RECT  50.483 98.64 50.723 98.664 ;
     RECT  50.105 4.944 50.789 4.968 ;
     RECT  50.101 100.32 50.915 100.344 ;
     RECT  50.749 2.256 51.107 2.28 ;
     RECT  50.137 101.472 51.107 101.496 ;
     RECT  51.212 0.528 51.299 0.552 ;
     RECT  50.099 102.624 51.425 103.32 ;
     RECT  51.425 102.624 51.689 103.56 ;
     RECT  51.689 102.624 51.875 103.32 ;
     RECT  51.875 103.296 52.085 103.32 ;
    LAYER M5 ;
     RECT  0.864 0.016 51.288 0.563 ;
     RECT  0.864 0.563 51.096 1.763 ;
     RECT  27.36 1.763 51.096 2.291 ;
     RECT  0.864 1.763 26.376 2.339 ;
     RECT  27.36 2.291 50.52 2.339 ;
     RECT  27.36 2.339 50.328 2.867 ;
     RECT  0.864 2.339 11.208 2.915 ;
     RECT  41.616 2.867 50.328 2.915 ;
     RECT  12.48 2.339 26.376 3.301 ;
     RECT  27.36 2.867 40.512 3.301 ;
     RECT  9.504 2.915 11.208 3.397 ;
     RECT  12.48 3.301 40.512 3.397 ;
     RECT  9.504 3.397 40.512 3.925 ;
     RECT  41.616 2.915 50.088 3.925 ;
     RECT  0.864 2.915 8.472 4.501 ;
     RECT  9.504 3.925 50.088 4.501 ;
     RECT  0.864 4.501 50.088 5.699 ;
     RECT  15.696 5.699 22.44 5.747 ;
     RECT  23.472 5.699 50.088 5.747 ;
     RECT  23.472 5.747 42.792 5.795 ;
     RECT  44.592 5.747 50.088 5.795 ;
     RECT  23.472 5.795 30.696 5.843 ;
     RECT  31.968 5.795 42.792 5.891 ;
     RECT  24 5.843 30.696 5.987 ;
     RECT  45.168 5.795 50.088 6.227 ;
     RECT  0.864 5.699 14.424 6.323 ;
     RECT  19.92 5.747 22.44 6.323 ;
     RECT  31.968 5.891 42.6 6.323 ;
     RECT  0.864 6.323 9.672 6.371 ;
     RECT  31.968 6.323 42.168 6.371 ;
     RECT  34.8 6.371 42.168 6.419 ;
     RECT  31.968 6.371 33.816 6.707 ;
     RECT  16.224 5.747 18.912 6.803 ;
     RECT  19.92 6.323 21.672 6.803 ;
     RECT  38.016 6.419 42.168 6.851 ;
     RECT  0.864 6.371 1.08 6.899 ;
     RECT  2.064 6.371 9.672 6.899 ;
     RECT  17.568 6.803 18.912 6.899 ;
     RECT  19.92 6.803 21.432 6.899 ;
     RECT  24 5.987 30.216 6.899 ;
     RECT  34.8 6.419 36.744 6.899 ;
     RECT  38.016 6.851 38.328 6.899 ;
     RECT  39.6 6.851 40.632 6.899 ;
     RECT  42.048 6.851 42.168 6.899 ;
     RECT  45.216 6.227 50.088 6.899 ;
     RECT  25.92 6.899 30.072 6.947 ;
     RECT  2.064 6.899 9.576 6.995 ;
     RECT  25.92 6.947 29.712 7.043 ;
     RECT  45.216 6.899 49.992 7.187 ;
     RECT  10.8 6.323 14.424 7.427 ;
     RECT  11.376 7.427 14.424 7.475 ;
     RECT  18.336 6.899 18.912 7.475 ;
     RECT  25.92 7.043 27.624 7.475 ;
     RECT  31.968 6.707 33.72 7.475 ;
     RECT  45.504 7.187 49.992 7.475 ;
     RECT  38.304 6.899 38.328 7.571 ;
     RECT  39.6 6.899 40.512 7.571 ;
     RECT  19.92 6.899 20.664 7.907 ;
     RECT  16.224 6.803 16.488 7.957 ;
     RECT  29.136 7.043 29.712 7.957 ;
     RECT  30.816 7.861 30.84 7.957 ;
     RECT  2.064 6.995 6.264 8.003 ;
     RECT  7.296 6.995 9.576 8.003 ;
     RECT  11.424 7.475 13.512 8.003 ;
     RECT  16.224 7.957 17.16 8.003 ;
     RECT  26.736 7.475 27.624 8.003 ;
     RECT  33.696 7.475 33.72 8.003 ;
     RECT  34.8 6.899 35.208 8.003 ;
     RECT  0.864 6.899 0.888 8.483 ;
     RECT  34.8 8.003 35.112 8.485 ;
     RECT  26.736 8.003 26.76 8.579 ;
     RECT  29.136 7.957 30.84 8.579 ;
     RECT  29.136 8.579 29.976 8.581 ;
     RECT  32.16 7.475 32.712 8.627 ;
     RECT  11.424 8.003 11.448 8.723 ;
     RECT  2.4 8.003 6.264 8.819 ;
     RECT  7.8 8.003 9.576 8.965 ;
     RECT  34.32 8.485 35.112 9.061 ;
     RECT  44.064 8.437 44.088 9.107 ;
     RECT  7.68 8.965 9.576 9.109 ;
     RECT  32.688 8.627 32.712 9.155 ;
     RECT  45.6 7.475 49.32 9.155 ;
     RECT  45.6 9.155 48.792 9.251 ;
     RECT  42.144 6.899 42.168 9.253 ;
     RECT  17.136 8.003 17.16 9.539 ;
     RECT  33.792 9.061 35.112 9.539 ;
     RECT  15.36 9.493 15.384 9.635 ;
     RECT  2.4 8.819 5.64 9.637 ;
     RECT  2.304 9.637 5.64 9.731 ;
     RECT  7.248 9.109 9.576 9.731 ;
     RECT  7.248 9.731 9.096 10.019 ;
     RECT  7.68 10.019 9.096 10.307 ;
     RECT  20.64 7.907 20.664 10.307 ;
     RECT  48.336 9.251 48.792 10.307 ;
     RECT  13.2 8.003 13.512 10.597 ;
     RECT  42.144 9.253 42.696 10.883 ;
     RECT  42.672 10.883 42.696 11.411 ;
     RECT  45.6 9.251 47.304 11.459 ;
     RECT  47.28 11.459 47.304 11.747 ;
     RECT  13.104 10.597 13.512 11.845 ;
     RECT  2.304 9.731 4.248 12.901 ;
     RECT  28.416 8.581 29.976 23.411 ;
     RECT  24 6.899 24.504 24.085 ;
     RECT  7.68 10.307 8.112 25.141 ;
     RECT  24 24.085 25.128 25.237 ;
     RECT  7.68 25.141 8.28 25.283 ;
     RECT  23.856 25.237 25.128 25.283 ;
     RECT  2.304 12.901 4.296 25.669 ;
     RECT  7.8 25.283 8.28 26.725 ;
     RECT  7.44 26.725 8.28 26.867 ;
     RECT  2.304 25.669 4.488 27.061 ;
     RECT  5.616 9.731 5.64 27.061 ;
     RECT  12.672 11.845 13.512 27.395 ;
     RECT  2.304 27.061 5.64 27.733 ;
     RECT  2.304 27.733 6.264 27.875 ;
     RECT  2.304 27.875 5.64 27.923 ;
     RECT  10.272 27.301 10.296 28.115 ;
     RECT  2.4 27.923 5.64 28.259 ;
     RECT  7.8 26.867 8.28 28.547 ;
     RECT  5.616 28.259 5.64 29.077 ;
     RECT  5.616 29.077 6.12 29.363 ;
     RECT  2.4 28.259 4.488 30.085 ;
     RECT  5.616 29.363 5.784 30.085 ;
     RECT  0.144 30.421 0.168 30.611 ;
     RECT  11.376 29.941 11.4 31.283 ;
     RECT  2.4 30.085 5.784 31.475 ;
     RECT  0.144 32.773 0.168 33.059 ;
     RECT  7.8 28.547 8.232 33.301 ;
     RECT  7.8 33.301 9.096 33.587 ;
     RECT  7.8 33.587 8.232 33.589 ;
     RECT  11.376 32.437 11.4 33.683 ;
     RECT  7.44 33.589 8.232 34.067 ;
     RECT  2.4 31.475 5.688 34.357 ;
     RECT  2.304 34.357 5.688 34.499 ;
     RECT  2.4 34.499 5.688 35.845 ;
     RECT  7.8 34.067 8.232 36.613 ;
     RECT  7.8 36.613 8.76 36.803 ;
     RECT  10.752 35.845 10.776 36.901 ;
     RECT  9.12 36.853 9.24 36.995 ;
     RECT  10.752 36.901 10.824 37.091 ;
     RECT  9.12 36.995 9.144 37.283 ;
     RECT  12 34.501 12.024 37.813 ;
     RECT  13.104 27.395 13.512 37.813 ;
     RECT  12 37.813 13.512 37.859 ;
     RECT  2.4 35.845 6.552 38.435 ;
     RECT  10.752 37.091 10.776 39.491 ;
     RECT  12.432 37.859 13.512 39.877 ;
     RECT  0.144 38.533 0.168 40.355 ;
     RECT  12.288 39.877 13.512 40.835 ;
     RECT  2.4 38.435 5.688 40.837 ;
     RECT  7.8 36.803 8.112 40.981 ;
     RECT  2.16 40.837 5.688 41.123 ;
     RECT  7.248 40.981 8.112 41.651 ;
     RECT  7.8 41.651 8.112 42.469 ;
     RECT  13.008 40.835 13.512 42.613 ;
     RECT  7.8 42.469 8.376 42.709 ;
     RECT  6.864 42.709 8.376 42.947 ;
     RECT  0.144 42.997 0.168 43.331 ;
     RECT  12.432 42.613 13.512 43.331 ;
     RECT  6.864 42.947 8.112 44.099 ;
     RECT  0.144 44.725 0.168 44.915 ;
     RECT  7.8 44.099 8.112 45.109 ;
     RECT  9.456 44.437 9.48 45.109 ;
     RECT  7.8 45.109 9.48 45.635 ;
     RECT  2.4 41.123 5.688 46.885 ;
     RECT  2.304 46.885 5.688 47.075 ;
     RECT  2.4 47.075 5.688 47.269 ;
     RECT  6.672 46.645 6.696 47.269 ;
     RECT  23.856 25.283 24.504 47.269 ;
     RECT  2.4 47.269 6.696 47.315 ;
     RECT  0.144 47.317 0.168 47.699 ;
     RECT  11.184 46.645 11.208 48.131 ;
     RECT  13.008 43.331 13.512 48.949 ;
     RECT  2.4 47.315 6.312 49.571 ;
     RECT  9.456 45.635 9.48 50.339 ;
     RECT  9.6 50.341 9.624 50.723 ;
     RECT  23.616 47.269 24.504 50.771 ;
     RECT  23.616 50.771 24.456 51.347 ;
     RECT  0.144 51.445 0.168 51.779 ;
     RECT  7.8 45.635 8.112 51.973 ;
     RECT  7.8 51.973 8.52 52.931 ;
     RECT  2.4 49.571 5.688 52.981 ;
     RECT  13.008 48.949 13.752 53.219 ;
     RECT  2.4 52.981 6.264 53.603 ;
     RECT  2.4 53.603 5.688 54.661 ;
     RECT  6.72 53.941 6.744 54.661 ;
     RECT  2.4 54.661 6.744 54.707 ;
     RECT  13.008 53.219 13.512 54.997 ;
     RECT  13.008 54.997 13.848 55.669 ;
     RECT  12.912 55.669 13.848 55.907 ;
     RECT  2.4 54.707 6.312 56.053 ;
     RECT  2.304 56.053 6.312 56.243 ;
     RECT  0.144 56.149 0.168 56.339 ;
     RECT  2.4 56.243 6.312 56.437 ;
     RECT  7.8 52.931 8.112 56.437 ;
     RECT  2.4 56.437 8.112 56.483 ;
     RECT  9.12 56.389 9.144 57.635 ;
     RECT  29.4 23.411 29.976 57.635 ;
     RECT  7.008 56.483 8.112 57.827 ;
     RECT  12.912 55.907 13.512 58.021 ;
     RECT  12.912 58.021 13.704 58.645 ;
     RECT  29.4 57.635 29.832 58.739 ;
     RECT  7.344 57.827 8.112 58.933 ;
     RECT  12.24 58.645 13.704 59.027 ;
     RECT  12.24 59.027 13.512 59.315 ;
     RECT  0.144 59.509 0.168 59.795 ;
     RECT  10.944 50.293 10.968 60.133 ;
     RECT  10.944 60.133 11.208 60.179 ;
     RECT  12.912 59.315 13.512 60.469 ;
     RECT  0.144 61.237 0.168 62.003 ;
     RECT  14.64 61.717 14.664 62.003 ;
     RECT  22.56 61.957 22.584 62.099 ;
     RECT  34.32 9.539 35.112 62.147 ;
     RECT  7.248 58.933 8.112 62.629 ;
     RECT  11.184 60.179 11.208 62.629 ;
     RECT  12.528 60.469 13.512 62.629 ;
     RECT  7.056 62.629 8.112 62.725 ;
     RECT  7.056 62.725 8.52 63.875 ;
     RECT  7.056 63.875 8.112 63.923 ;
     RECT  11.184 62.629 13.656 64.115 ;
     RECT  7.248 63.923 8.112 64.307 ;
     RECT  23.616 51.347 24.312 64.451 ;
     RECT  12.528 64.115 13.656 64.693 ;
     RECT  24 64.451 24.312 64.837 ;
     RECT  12.528 64.693 13.704 64.883 ;
     RECT  40.2 7.571 40.512 65.509 ;
     RECT  2.4 56.483 5.688 65.797 ;
     RECT  7.8 64.307 8.112 65.845 ;
     RECT  10.176 65.317 10.2 66.179 ;
     RECT  11.184 64.115 11.208 66.661 ;
     RECT  7.8 65.845 8.664 66.709 ;
     RECT  39.312 65.509 40.512 66.755 ;
     RECT  39.648 66.755 40.512 66.947 ;
     RECT  7.296 66.709 8.664 67.091 ;
     RECT  10.224 66.661 11.208 67.283 ;
     RECT  7.8 67.091 8.664 67.571 ;
     RECT  2.4 65.797 5.88 68.099 ;
     RECT  37.056 66.325 37.08 68.099 ;
     RECT  24 64.837 24.408 68.147 ;
     RECT  40.2 66.947 40.512 68.197 ;
     RECT  13.008 64.883 13.704 68.293 ;
     RECT  12.528 68.293 13.704 68.435 ;
     RECT  12.528 68.435 13.512 68.627 ;
     RECT  40.08 68.197 40.512 68.773 ;
     RECT  40.08 68.773 40.92 70.069 ;
     RECT  11.184 67.283 11.208 70.499 ;
     RECT  13.008 68.627 13.512 70.549 ;
     RECT  0.144 70.453 0.168 70.643 ;
     RECT  43.44 68.101 43.464 70.739 ;
     RECT  9.36 70.453 9.384 71.221 ;
     RECT  40.08 70.069 41.064 71.221 ;
     RECT  13.008 70.549 13.992 72.131 ;
     RECT  40.08 71.221 41.64 72.179 ;
     RECT  45.6 11.459 45.912 72.325 ;
     RECT  9.36 71.221 10.2 72.373 ;
     RECT  45.6 72.325 46.392 72.517 ;
     RECT  45.6 72.517 46.488 72.565 ;
     RECT  43.488 70.981 43.896 72.611 ;
     RECT  45.36 72.565 46.488 72.613 ;
     RECT  9.36 72.373 10.824 72.707 ;
     RECT  45.36 72.613 46.584 72.709 ;
     RECT  40.08 72.179 41.064 72.803 ;
     RECT  45.36 72.709 46.728 72.899 ;
     RECT  37.056 72.421 37.08 72.947 ;
     RECT  45.36 72.899 46.584 72.995 ;
     RECT  40.08 72.803 40.776 73.043 ;
     RECT  45.36 72.995 46.488 73.091 ;
     RECT  45.36 73.091 45.912 73.141 ;
     RECT  44.64 73.141 45.912 73.283 ;
     RECT  13.008 72.131 13.512 73.381 ;
     RECT  6.72 72.373 6.744 73.523 ;
     RECT  13.008 73.381 13.704 74.147 ;
     RECT  45.36 73.283 45.912 74.437 ;
     RECT  7.8 67.571 8.112 75.109 ;
     RECT  43.488 72.611 43.512 75.205 ;
     RECT  45.216 74.437 45.912 75.253 ;
     RECT  9.36 72.707 10.2 75.395 ;
     RECT  13.008 74.147 13.512 75.589 ;
     RECT  0.144 75.013 0.168 75.731 ;
     RECT  43.344 75.205 43.512 75.875 ;
     RECT  43.344 75.875 43.368 75.923 ;
     RECT  45.216 75.253 46.824 76.019 ;
     RECT  7.104 75.109 8.112 76.163 ;
     RECT  45.6 76.019 46.824 76.165 ;
     RECT  45.6 76.165 47.256 76.355 ;
     RECT  13.008 75.589 13.608 76.357 ;
     RECT  15.216 76.645 15.24 76.979 ;
     RECT  47.232 76.355 47.256 76.979 ;
     RECT  45.6 76.355 45.912 77.125 ;
     RECT  0.144 77.077 0.168 77.363 ;
     RECT  13.008 76.357 13.848 77.363 ;
     RECT  44.832 77.125 45.912 77.557 ;
     RECT  13.008 77.363 13.512 78.469 ;
     RECT  44.304 77.557 45.912 78.563 ;
     RECT  13.008 78.469 13.608 78.613 ;
     RECT  43.296 77.845 43.32 78.707 ;
     RECT  16.032 78.709 16.056 79.043 ;
     RECT  13.008 78.613 13.992 79.045 ;
     RECT  44.832 78.563 45.912 79.187 ;
     RECT  12.336 79.045 13.992 79.523 ;
     RECT  40.08 73.043 40.512 83.267 ;
     RECT  45.6 79.187 45.912 84.901 ;
     RECT  44.976 84.901 45.912 85.477 ;
     RECT  9.36 75.395 9.384 85.523 ;
     RECT  13.008 79.523 13.992 85.955 ;
     RECT  38.928 85.477 38.952 86.005 ;
     RECT  40.2 83.267 40.512 86.005 ;
     RECT  44.976 85.477 46.008 88.309 ;
     RECT  44.976 88.309 46.392 88.885 ;
     RECT  47.376 87.685 47.4 88.885 ;
     RECT  38.592 86.005 40.512 89.461 ;
     RECT  41.664 88.213 41.688 89.461 ;
     RECT  44.976 88.885 47.4 89.461 ;
     RECT  44.976 89.461 49.224 90.517 ;
     RECT  38.592 89.461 41.688 91.717 ;
     RECT  38.592 91.717 42.36 92.245 ;
     RECT  38.592 92.245 43.08 92.293 ;
     RECT  44.976 90.517 49.848 92.917 ;
     RECT  38.592 92.293 43.512 93.445 ;
     RECT  44.592 92.917 49.848 93.445 ;
     RECT  2.4 68.099 5.688 98.005 ;
     RECT  38.592 93.445 49.848 98.629 ;
     RECT  13.008 85.955 13.512 98.675 ;
     RECT  7.8 76.163 8.112 99.013 ;
     RECT  2.304 98.005 5.688 99.157 ;
     RECT  7.68 99.013 8.112 99.157 ;
     RECT  18.6 7.475 18.912 99.157 ;
     RECT  29.4 58.739 29.712 99.157 ;
     RECT  34.464 62.147 35.112 99.157 ;
     RECT  13.056 98.675 13.512 99.205 ;
     RECT  38.592 98.629 50.712 99.541 ;
     RECT  7.632 99.157 8.112 99.733 ;
     RECT  16.8 99.205 16.824 99.733 ;
     RECT  18.192 99.157 18.912 99.733 ;
     RECT  2.112 99.157 5.688 99.779 ;
     RECT  13.056 99.205 14.28 99.779 ;
     RECT  2.112 99.779 4.104 100.069 ;
     RECT  38.16 99.541 50.712 100.309 ;
     RECT  5.664 99.779 5.688 100.837 ;
     RECT  5.664 100.837 5.88 100.885 ;
     RECT  7.2 99.733 8.112 100.885 ;
     RECT  13.2 99.779 14.28 100.885 ;
     RECT  16.8 99.733 18.912 100.885 ;
     RECT  20.544 99.733 20.568 100.885 ;
     RECT  24 68.147 24.312 100.885 ;
     RECT  26.112 47.269 26.136 100.885 ;
     RECT  28.944 99.157 29.712 100.885 ;
     RECT  33.84 99.157 35.112 100.885 ;
     RECT  38.16 100.309 50.904 100.885 ;
     RECT  1.536 100.069 4.104 100.981 ;
     RECT  1.536 100.981 4.296 101.173 ;
     RECT  5.28 100.885 15.24 101.173 ;
     RECT  16.8 100.885 32.088 101.173 ;
     RECT  33.648 100.885 50.904 101.173 ;
     RECT  1.536 101.173 15.24 101.413 ;
     RECT  16.8 101.173 50.904 101.413 ;
     RECT  1.536 101.413 50.904 101.461 ;
     RECT  1.536 101.461 51.096 102.613 ;
     RECT  1.536 102.613 51.864 103.632 ;
     RECT  26.376 1.763 27.36 3.301 ;
     RECT  11.208 2.339 12.48 3.397 ;
     RECT  40.512 2.867 41.616 3.925 ;
     RECT  8.472 2.915 9.504 4.501 ;
     RECT  14.424 5.699 15.696 5.747 ;
     RECT  22.44 5.699 23.472 5.843 ;
     RECT  18.912 5.747 19.92 7.907 ;
     RECT  30.696 5.795 31.968 5.987 ;
     RECT  9.672 6.323 10.8 6.899 ;
     RECT  1.08 6.371 2.064 6.899 ;
     RECT  33.816 6.371 34.8 6.707 ;
     RECT  36.744 6.419 38.016 6.899 ;
     RECT  33.72 6.707 34.8 8.003 ;
     RECT  16.488 6.803 17.568 6.899 ;
     RECT  38.328 6.851 39.6 7.571 ;
     RECT  40.632 6.851 42.048 6.899 ;
     RECT  0.888 6.899 2.064 8.003 ;
     RECT  9.576 6.899 10.8 7.427 ;
     RECT  16.488 6.899 18.336 7.475 ;
     RECT  24.504 6.899 25.92 7.475 ;
     RECT  30.072 6.899 30.216 6.947 ;
     RECT  29.712 6.947 30.216 7.861 ;
     RECT  6.264 6.995 7.296 8.003 ;
     RECT  27.624 7.043 29.136 8.003 ;
     RECT  45.216 7.187 45.504 7.475 ;
     RECT  16.488 7.475 18.6 7.957 ;
     RECT  31.968 7.475 32.16 7.861 ;
     RECT  32.712 7.475 33.696 8.003 ;
     RECT  45.216 7.475 45.6 8.437 ;
     RECT  29.712 7.861 30.816 7.957 ;
     RECT  30.84 7.861 32.16 8.579 ;
     RECT  17.16 7.957 18.6 9.539 ;
     RECT  0.888 8.003 2.4 8.483 ;
     RECT  6.264 8.003 7.8 8.819 ;
     RECT  28.416 8.003 29.136 8.581 ;
     RECT  32.712 8.003 34.8 8.485 ;
     RECT  44.088 8.437 45.6 9.107 ;
     RECT  2.304 8.483 2.4 9.637 ;
     RECT  32.712 8.485 34.32 9.061 ;
     RECT  7.248 8.819 7.8 8.965 ;
     RECT  7.248 8.965 7.68 9.109 ;
     RECT  32.712 9.061 33.792 9.155 ;
     RECT  47.304 9.251 48.336 10.307 ;
     RECT  4.248 9.731 5.616 12.901 ;
     RECT  45.912 11.459 47.28 11.747 ;
     RECT  4.296 12.901 5.616 25.669 ;
     RECT  7.68 25.283 7.8 26.725 ;
     RECT  4.488 25.669 5.616 27.061 ;
     RECT  5.64 27.875 6.12 29.077 ;
     RECT  4.488 28.259 5.616 30.085 ;
     RECT  11.376 31.283 11.4 32.437 ;
     RECT  12.024 34.501 13.104 37.813 ;
     RECT  6.552 35.845 7.8 38.435 ;
     RECT  10.776 35.845 12 36.901 ;
     RECT  8.112 36.803 8.76 36.853 ;
     RECT  8.112 36.853 9.12 37.283 ;
     RECT  9.24 36.853 10.752 36.995 ;
     RECT  10.824 36.901 12 37.091 ;
     RECT  10.776 37.091 12 37.859 ;
     RECT  7.248 41.651 7.8 42.709 ;
     RECT  5.688 42.709 6.864 44.099 ;
     RECT  8.112 42.947 8.376 44.437 ;
     RECT  0.144 43.331 0.168 44.725 ;
     RECT  8.112 44.437 9.456 45.109 ;
     RECT  8.112 45.635 9.456 50.339 ;
     RECT  5.688 46.645 6.672 47.269 ;
     RECT  6.696 46.645 7.8 47.315 ;
     RECT  6.312 47.315 7.8 49.571 ;
     RECT  9.48 50.293 10.944 50.339 ;
     RECT  8.112 50.339 10.944 50.341 ;
     RECT  8.112 50.341 9.6 50.723 ;
     RECT  9.624 50.341 10.944 50.723 ;
     RECT  8.112 50.723 8.52 51.973 ;
     RECT  5.688 53.603 6.264 53.941 ;
     RECT  5.688 53.941 6.72 54.661 ;
     RECT  6.744 53.941 7.8 54.707 ;
     RECT  6.312 54.707 7.8 56.437 ;
     RECT  8.112 56.389 9.12 57.635 ;
     RECT  5.688 56.483 7.008 57.827 ;
     RECT  7.248 57.827 7.344 58.933 ;
     RECT  10.968 58.645 12.24 59.315 ;
     RECT  10.968 59.315 12.912 60.133 ;
     RECT  0.144 59.795 0.168 61.237 ;
     RECT  11.208 60.133 12.912 60.469 ;
     RECT  11.208 60.469 12.528 62.629 ;
     RECT  13.512 61.717 14.64 62.003 ;
     RECT  22.584 61.957 23.616 62.099 ;
     RECT  13.512 62.003 13.656 62.629 ;
     RECT  5.688 62.629 7.056 63.923 ;
     RECT  11.208 64.115 12.528 64.883 ;
     RECT  10.2 65.317 11.184 66.179 ;
     RECT  8.664 65.845 10.176 66.179 ;
     RECT  10.224 66.179 11.184 66.661 ;
     RECT  5.88 66.709 7.296 67.091 ;
     RECT  40.08 66.947 40.2 68.197 ;
     RECT  11.208 68.293 12.528 68.627 ;
     RECT  8.112 70.453 9.36 85.523 ;
     RECT  13.512 72.131 13.704 73.381 ;
     RECT  5.688 72.373 6.72 73.523 ;
     RECT  6.744 72.373 7.8 73.523 ;
     RECT  43.896 72.565 45.36 72.611 ;
     RECT  43.512 72.611 45.36 73.141 ;
     RECT  43.512 73.141 44.64 73.283 ;
     RECT  45.216 73.283 45.36 74.437 ;
     RECT  13.512 74.147 13.608 75.589 ;
     RECT  5.688 75.109 7.104 76.163 ;
     RECT  0.144 75.731 0.168 77.077 ;
     RECT  45.216 76.019 45.6 77.125 ;
     RECT  45.912 76.355 47.232 76.979 ;
     RECT  13.848 76.645 15.216 76.979 ;
     RECT  13.512 77.363 13.848 78.469 ;
     RECT  43.32 77.845 44.304 78.563 ;
     RECT  13.608 78.469 13.848 78.613 ;
     RECT  43.32 78.563 44.832 78.707 ;
     RECT  38.952 85.477 40.2 86.005 ;
     RECT  46.008 87.685 47.376 88.309 ;
     RECT  40.512 88.213 41.664 89.461 ;
     RECT  46.392 88.309 47.376 88.885 ;
     RECT  43.512 92.293 44.976 92.917 ;
     RECT  43.512 92.917 44.592 93.445 ;
     RECT  16.824 99.205 18.192 99.733 ;
     RECT  5.688 99.733 7.2 100.837 ;
     RECT  4.104 99.779 5.664 100.885 ;
     RECT  13.056 99.779 13.2 100.885 ;
     RECT  5.88 100.837 7.2 100.885 ;
     RECT  4.104 100.885 5.28 100.981 ;
     RECT  4.296 100.981 5.28 101.173 ;
  END
END qfd_xcst_s
END LIBRARY
